VERSION 5.8 ;
BUSBITCHARS "[]" ;
DIVIDERCHAR "/" ;
UNITS
    DATABASE MICRONS 1000 ;
END UNITS

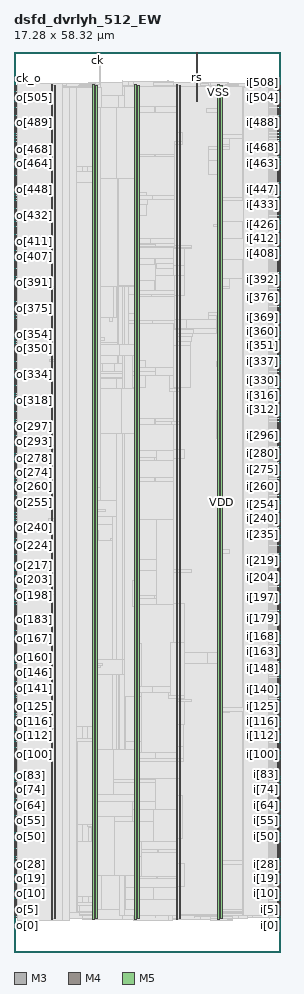
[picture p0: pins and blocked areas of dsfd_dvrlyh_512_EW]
MACRO dsfd_dvrlyh_512_EW
  FOREIGN dsfd_dvrlyh_512_EW 0 0 ;
  CLASS BLOCK ;
  SIZE 17.28 BY 58.32 ;
  PIN ck
    DIRECTION INPUT ;
    USE SIGNAL ;
    PORT
      LAYER M3 ;
        RECT  5.4 58.176 5.418 58.32 ;
    END
    PORT
      LAYER M3 ;
        RECT  5.4 57.595 5.418 58.188 ;
    END
  END ck
  PIN ck_o
    DIRECTION OUTPUT ;
    USE SIGNAL ;
    PORT
      LAYER M4 ;
        RECT  0 56.112 0.192 56.136 ;
    END
  END ck_o
  PIN i[0]
    DIRECTION INPUT ;
    USE SIGNAL ;
    PORT
      LAYER M4 ;
        RECT  17.088 2.208 17.28 2.232 ;
    END
  END i[0]
  PIN i[100]
    DIRECTION INPUT ;
    USE SIGNAL ;
    PORT
      LAYER M4 ;
        RECT  17.088 12.768 17.28 12.792 ;
    END
  END i[100]
  PIN i[101]
    DIRECTION INPUT ;
    USE SIGNAL ;
    PORT
      LAYER M4 ;
        RECT  17.088 12.864 17.28 12.888 ;
    END
  END i[101]
  PIN i[102]
    DIRECTION INPUT ;
    USE SIGNAL ;
    PORT
      LAYER M4 ;
        RECT  17.088 12.96 17.28 12.984 ;
    END
  END i[102]
  PIN i[103]
    DIRECTION INPUT ;
    USE SIGNAL ;
    PORT
      LAYER M4 ;
        RECT  17.088 13.104 17.28 13.128 ;
    END
  END i[103]
  PIN i[104]
    DIRECTION INPUT ;
    USE SIGNAL ;
    PORT
      LAYER M4 ;
        RECT  17.088 13.2 17.28 13.224 ;
    END
  END i[104]
  PIN i[105]
    DIRECTION INPUT ;
    USE SIGNAL ;
    PORT
      LAYER M4 ;
        RECT  17.088 13.296 17.28 13.32 ;
    END
  END i[105]
  PIN i[106]
    DIRECTION INPUT ;
    USE SIGNAL ;
    PORT
      LAYER M4 ;
        RECT  17.088 13.392 17.28 13.416 ;
    END
  END i[106]
  PIN i[107]
    DIRECTION INPUT ;
    USE SIGNAL ;
    PORT
      LAYER M4 ;
        RECT  17.088 13.488 17.28 13.512 ;
    END
  END i[107]
  PIN i[108]
    DIRECTION INPUT ;
    USE SIGNAL ;
    PORT
      LAYER M4 ;
        RECT  17.088 13.632 17.28 13.656 ;
    END
  END i[108]
  PIN i[109]
    DIRECTION INPUT ;
    USE SIGNAL ;
    PORT
      LAYER M4 ;
        RECT  17.088 13.728 17.28 13.752 ;
    END
  END i[109]
  PIN i[10]
    DIRECTION INPUT ;
    USE SIGNAL ;
    PORT
      LAYER M4 ;
        RECT  17.088 3.264 17.28 3.288 ;
    END
  END i[10]
  PIN i[110]
    DIRECTION INPUT ;
    USE SIGNAL ;
    PORT
      LAYER M4 ;
        RECT  17.088 13.824 17.28 13.848 ;
    END
  END i[110]
  PIN i[111]
    DIRECTION INPUT ;
    USE SIGNAL ;
    PORT
      LAYER M4 ;
        RECT  17.088 13.92 17.28 13.944 ;
    END
  END i[111]
  PIN i[112]
    DIRECTION INPUT ;
    USE SIGNAL ;
    PORT
      LAYER M4 ;
        RECT  17.088 14.016 17.28 14.04 ;
    END
  END i[112]
  PIN i[113]
    DIRECTION INPUT ;
    USE SIGNAL ;
    PORT
      LAYER M4 ;
        RECT  17.088 14.16 17.28 14.184 ;
    END
  END i[113]
  PIN i[114]
    DIRECTION INPUT ;
    USE SIGNAL ;
    PORT
      LAYER M4 ;
        RECT  17.088 14.256 17.28 14.28 ;
    END
  END i[114]
  PIN i[115]
    DIRECTION INPUT ;
    USE SIGNAL ;
    PORT
      LAYER M4 ;
        RECT  17.088 14.352 17.28 14.376 ;
    END
  END i[115]
  PIN i[116]
    DIRECTION INPUT ;
    USE SIGNAL ;
    PORT
      LAYER M4 ;
        RECT  17.088 14.448 17.28 14.472 ;
    END
  END i[116]
  PIN i[117]
    DIRECTION INPUT ;
    USE SIGNAL ;
    PORT
      LAYER M4 ;
        RECT  17.088 14.544 17.28 14.568 ;
    END
  END i[117]
  PIN i[118]
    DIRECTION INPUT ;
    USE SIGNAL ;
    PORT
      LAYER M4 ;
        RECT  17.088 14.688 17.28 14.712 ;
    END
  END i[118]
  PIN i[119]
    DIRECTION INPUT ;
    USE SIGNAL ;
    PORT
      LAYER M4 ;
        RECT  17.088 14.784 17.28 14.808 ;
    END
  END i[119]
  PIN i[11]
    DIRECTION INPUT ;
    USE SIGNAL ;
    PORT
      LAYER M4 ;
        RECT  17.088 3.408 17.28 3.432 ;
    END
  END i[11]
  PIN i[120]
    DIRECTION INPUT ;
    USE SIGNAL ;
    PORT
      LAYER M4 ;
        RECT  17.088 14.88 17.28 14.904 ;
    END
  END i[120]
  PIN i[121]
    DIRECTION INPUT ;
    USE SIGNAL ;
    PORT
      LAYER M4 ;
        RECT  17.088 14.976 17.28 15 ;
    END
  END i[121]
  PIN i[122]
    DIRECTION INPUT ;
    USE SIGNAL ;
    PORT
      LAYER M4 ;
        RECT  17.088 15.072 17.28 15.096 ;
    END
  END i[122]
  PIN i[123]
    DIRECTION INPUT ;
    USE SIGNAL ;
    PORT
      LAYER M4 ;
        RECT  17.088 15.216 17.28 15.24 ;
    END
  END i[123]
  PIN i[124]
    DIRECTION INPUT ;
    USE SIGNAL ;
    PORT
      LAYER M4 ;
        RECT  17.088 15.312 17.28 15.336 ;
    END
  END i[124]
  PIN i[125]
    DIRECTION INPUT ;
    USE SIGNAL ;
    PORT
      LAYER M4 ;
        RECT  17.088 15.408 17.28 15.432 ;
    END
  END i[125]
  PIN i[126]
    DIRECTION INPUT ;
    USE SIGNAL ;
    PORT
      LAYER M4 ;
        RECT  17.088 15.504 17.28 15.528 ;
    END
  END i[126]
  PIN i[127]
    DIRECTION INPUT ;
    USE SIGNAL ;
    PORT
      LAYER M4 ;
        RECT  17.088 15.6 17.28 15.624 ;
    END
  END i[127]
  PIN i[128]
    DIRECTION INPUT ;
    USE SIGNAL ;
    PORT
      LAYER M4 ;
        RECT  17.088 15.744 17.28 15.768 ;
    END
  END i[128]
  PIN i[129]
    DIRECTION INPUT ;
    USE SIGNAL ;
    PORT
      LAYER M4 ;
        RECT  17.088 15.84 17.28 15.864 ;
    END
  END i[129]
  PIN i[12]
    DIRECTION INPUT ;
    USE SIGNAL ;
    PORT
      LAYER M4 ;
        RECT  17.088 3.504 17.28 3.528 ;
    END
  END i[12]
  PIN i[130]
    DIRECTION INPUT ;
    USE SIGNAL ;
    PORT
      LAYER M4 ;
        RECT  17.088 15.936 17.28 15.96 ;
    END
  END i[130]
  PIN i[131]
    DIRECTION INPUT ;
    USE SIGNAL ;
    PORT
      LAYER M4 ;
        RECT  17.088 16.032 17.28 16.056 ;
    END
  END i[131]
  PIN i[132]
    DIRECTION INPUT ;
    USE SIGNAL ;
    PORT
      LAYER M4 ;
        RECT  17.088 16.128 17.28 16.152 ;
    END
  END i[132]
  PIN i[133]
    DIRECTION INPUT ;
    USE SIGNAL ;
    PORT
      LAYER M4 ;
        RECT  17.088 16.272 17.28 16.296 ;
    END
  END i[133]
  PIN i[134]
    DIRECTION INPUT ;
    USE SIGNAL ;
    PORT
      LAYER M4 ;
        RECT  17.088 16.368 17.28 16.392 ;
    END
  END i[134]
  PIN i[135]
    DIRECTION INPUT ;
    USE SIGNAL ;
    PORT
      LAYER M4 ;
        RECT  17.088 16.464 17.28 16.488 ;
    END
  END i[135]
  PIN i[136]
    DIRECTION INPUT ;
    USE SIGNAL ;
    PORT
      LAYER M4 ;
        RECT  17.088 16.56 17.28 16.584 ;
    END
  END i[136]
  PIN i[137]
    DIRECTION INPUT ;
    USE SIGNAL ;
    PORT
      LAYER M4 ;
        RECT  17.088 16.656 17.28 16.68 ;
    END
  END i[137]
  PIN i[138]
    DIRECTION INPUT ;
    USE SIGNAL ;
    PORT
      LAYER M4 ;
        RECT  17.088 16.8 17.28 16.824 ;
    END
  END i[138]
  PIN i[139]
    DIRECTION INPUT ;
    USE SIGNAL ;
    PORT
      LAYER M4 ;
        RECT  17.088 16.896 17.28 16.92 ;
    END
  END i[139]
  PIN i[13]
    DIRECTION INPUT ;
    USE SIGNAL ;
    PORT
      LAYER M4 ;
        RECT  17.088 3.6 17.28 3.624 ;
    END
  END i[13]
  PIN i[140]
    DIRECTION INPUT ;
    USE SIGNAL ;
    PORT
      LAYER M4 ;
        RECT  17.088 16.992 17.28 17.016 ;
    END
  END i[140]
  PIN i[141]
    DIRECTION INPUT ;
    USE SIGNAL ;
    PORT
      LAYER M4 ;
        RECT  17.088 17.088 17.28 17.112 ;
    END
  END i[141]
  PIN i[142]
    DIRECTION INPUT ;
    USE SIGNAL ;
    PORT
      LAYER M4 ;
        RECT  17.088 17.184 17.28 17.208 ;
    END
  END i[142]
  PIN i[143]
    DIRECTION INPUT ;
    USE SIGNAL ;
    PORT
      LAYER M4 ;
        RECT  17.088 17.328 17.28 17.352 ;
    END
  END i[143]
  PIN i[144]
    DIRECTION INPUT ;
    USE SIGNAL ;
    PORT
      LAYER M4 ;
        RECT  17.088 17.424 17.28 17.448 ;
    END
  END i[144]
  PIN i[145]
    DIRECTION INPUT ;
    USE SIGNAL ;
    PORT
      LAYER M4 ;
        RECT  17.088 17.52 17.28 17.544 ;
    END
  END i[145]
  PIN i[146]
    DIRECTION INPUT ;
    USE SIGNAL ;
    PORT
      LAYER M4 ;
        RECT  17.088 17.616 17.28 17.64 ;
    END
  END i[146]
  PIN i[147]
    DIRECTION INPUT ;
    USE SIGNAL ;
    PORT
      LAYER M4 ;
        RECT  17.088 17.712 17.28 17.736 ;
    END
  END i[147]
  PIN i[148]
    DIRECTION INPUT ;
    USE SIGNAL ;
    PORT
      LAYER M4 ;
        RECT  17.088 17.856 17.28 17.88 ;
    END
  END i[148]
  PIN i[149]
    DIRECTION INPUT ;
    USE SIGNAL ;
    PORT
      LAYER M4 ;
        RECT  17.088 17.952 17.28 17.976 ;
    END
  END i[149]
  PIN i[14]
    DIRECTION INPUT ;
    USE SIGNAL ;
    PORT
      LAYER M4 ;
        RECT  17.088 3.696 17.28 3.72 ;
    END
  END i[14]
  PIN i[150]
    DIRECTION INPUT ;
    USE SIGNAL ;
    PORT
      LAYER M4 ;
        RECT  17.088 18.048 17.28 18.072 ;
    END
  END i[150]
  PIN i[151]
    DIRECTION INPUT ;
    USE SIGNAL ;
    PORT
      LAYER M4 ;
        RECT  17.088 18.144 17.28 18.168 ;
    END
  END i[151]
  PIN i[152]
    DIRECTION INPUT ;
    USE SIGNAL ;
    PORT
      LAYER M4 ;
        RECT  17.088 18.24 17.28 18.264 ;
    END
  END i[152]
  PIN i[153]
    DIRECTION INPUT ;
    USE SIGNAL ;
    PORT
      LAYER M4 ;
        RECT  17.088 18.384 17.28 18.408 ;
    END
  END i[153]
  PIN i[154]
    DIRECTION INPUT ;
    USE SIGNAL ;
    PORT
      LAYER M4 ;
        RECT  17.088 18.48 17.28 18.504 ;
    END
  END i[154]
  PIN i[155]
    DIRECTION INPUT ;
    USE SIGNAL ;
    PORT
      LAYER M4 ;
        RECT  17.088 18.576 17.28 18.6 ;
    END
  END i[155]
  PIN i[156]
    DIRECTION INPUT ;
    USE SIGNAL ;
    PORT
      LAYER M4 ;
        RECT  17.088 18.672 17.28 18.696 ;
    END
  END i[156]
  PIN i[157]
    DIRECTION INPUT ;
    USE SIGNAL ;
    PORT
      LAYER M4 ;
        RECT  17.088 18.768 17.28 18.792 ;
    END
  END i[157]
  PIN i[158]
    DIRECTION INPUT ;
    USE SIGNAL ;
    PORT
      LAYER M4 ;
        RECT  17.088 18.912 17.28 18.936 ;
    END
  END i[158]
  PIN i[159]
    DIRECTION INPUT ;
    USE SIGNAL ;
    PORT
      LAYER M4 ;
        RECT  17.088 19.008 17.28 19.032 ;
    END
  END i[159]
  PIN i[15]
    DIRECTION INPUT ;
    USE SIGNAL ;
    PORT
      LAYER M4 ;
        RECT  17.088 3.792 17.28 3.816 ;
    END
  END i[15]
  PIN i[160]
    DIRECTION INPUT ;
    USE SIGNAL ;
    PORT
      LAYER M4 ;
        RECT  17.088 19.104 17.28 19.128 ;
    END
  END i[160]
  PIN i[161]
    DIRECTION INPUT ;
    USE SIGNAL ;
    PORT
      LAYER M4 ;
        RECT  17.088 19.2 17.28 19.224 ;
    END
  END i[161]
  PIN i[162]
    DIRECTION INPUT ;
    USE SIGNAL ;
    PORT
      LAYER M4 ;
        RECT  17.088 19.296 17.28 19.32 ;
    END
  END i[162]
  PIN i[163]
    DIRECTION INPUT ;
    USE SIGNAL ;
    PORT
      LAYER M4 ;
        RECT  17.088 19.44 17.28 19.464 ;
    END
  END i[163]
  PIN i[164]
    DIRECTION INPUT ;
    USE SIGNAL ;
    PORT
      LAYER M4 ;
        RECT  17.088 19.536 17.28 19.56 ;
    END
  END i[164]
  PIN i[165]
    DIRECTION INPUT ;
    USE SIGNAL ;
    PORT
      LAYER M4 ;
        RECT  17.088 19.632 17.28 19.656 ;
    END
  END i[165]
  PIN i[166]
    DIRECTION INPUT ;
    USE SIGNAL ;
    PORT
      LAYER M4 ;
        RECT  17.088 19.728 17.28 19.752 ;
    END
  END i[166]
  PIN i[167]
    DIRECTION INPUT ;
    USE SIGNAL ;
    PORT
      LAYER M4 ;
        RECT  17.088 19.824 17.28 19.848 ;
    END
  END i[167]
  PIN i[168]
    DIRECTION INPUT ;
    USE SIGNAL ;
    PORT
      LAYER M4 ;
        RECT  17.088 19.92 17.28 19.944 ;
    END
  END i[168]
  PIN i[169]
    DIRECTION INPUT ;
    USE SIGNAL ;
    PORT
      LAYER M4 ;
        RECT  17.088 20.064 17.28 20.088 ;
    END
  END i[169]
  PIN i[16]
    DIRECTION INPUT ;
    USE SIGNAL ;
    PORT
      LAYER M4 ;
        RECT  17.088 3.936 17.28 3.96 ;
    END
  END i[16]
  PIN i[170]
    DIRECTION INPUT ;
    USE SIGNAL ;
    PORT
      LAYER M4 ;
        RECT  17.088 20.16 17.28 20.184 ;
    END
  END i[170]
  PIN i[171]
    DIRECTION INPUT ;
    USE SIGNAL ;
    PORT
      LAYER M4 ;
        RECT  17.088 20.256 17.28 20.28 ;
    END
  END i[171]
  PIN i[172]
    DIRECTION INPUT ;
    USE SIGNAL ;
    PORT
      LAYER M4 ;
        RECT  17.088 20.352 17.28 20.376 ;
    END
  END i[172]
  PIN i[173]
    DIRECTION INPUT ;
    USE SIGNAL ;
    PORT
      LAYER M4 ;
        RECT  17.088 20.448 17.28 20.472 ;
    END
  END i[173]
  PIN i[174]
    DIRECTION INPUT ;
    USE SIGNAL ;
    PORT
      LAYER M4 ;
        RECT  17.088 20.592 17.28 20.616 ;
    END
  END i[174]
  PIN i[175]
    DIRECTION INPUT ;
    USE SIGNAL ;
    PORT
      LAYER M4 ;
        RECT  17.088 20.688 17.28 20.712 ;
    END
  END i[175]
  PIN i[176]
    DIRECTION INPUT ;
    USE SIGNAL ;
    PORT
      LAYER M4 ;
        RECT  17.088 20.784 17.28 20.808 ;
    END
  END i[176]
  PIN i[177]
    DIRECTION INPUT ;
    USE SIGNAL ;
    PORT
      LAYER M4 ;
        RECT  17.088 20.88 17.28 20.904 ;
    END
  END i[177]
  PIN i[178]
    DIRECTION INPUT ;
    USE SIGNAL ;
    PORT
      LAYER M4 ;
        RECT  17.088 20.976 17.28 21 ;
    END
  END i[178]
  PIN i[179]
    DIRECTION INPUT ;
    USE SIGNAL ;
    PORT
      LAYER M4 ;
        RECT  17.088 21.12 17.28 21.144 ;
    END
  END i[179]
  PIN i[17]
    DIRECTION INPUT ;
    USE SIGNAL ;
    PORT
      LAYER M4 ;
        RECT  17.088 4.032 17.28 4.056 ;
    END
  END i[17]
  PIN i[180]
    DIRECTION INPUT ;
    USE SIGNAL ;
    PORT
      LAYER M4 ;
        RECT  17.088 21.216 17.28 21.24 ;
    END
  END i[180]
  PIN i[181]
    DIRECTION INPUT ;
    USE SIGNAL ;
    PORT
      LAYER M4 ;
        RECT  17.088 21.312 17.28 21.336 ;
    END
  END i[181]
  PIN i[182]
    DIRECTION INPUT ;
    USE SIGNAL ;
    PORT
      LAYER M4 ;
        RECT  17.088 21.408 17.28 21.432 ;
    END
  END i[182]
  PIN i[183]
    DIRECTION INPUT ;
    USE SIGNAL ;
    PORT
      LAYER M4 ;
        RECT  17.088 21.504 17.28 21.528 ;
    END
  END i[183]
  PIN i[184]
    DIRECTION INPUT ;
    USE SIGNAL ;
    PORT
      LAYER M4 ;
        RECT  17.088 21.648 17.28 21.672 ;
    END
  END i[184]
  PIN i[185]
    DIRECTION INPUT ;
    USE SIGNAL ;
    PORT
      LAYER M4 ;
        RECT  17.088 21.744 17.28 21.768 ;
    END
  END i[185]
  PIN i[186]
    DIRECTION INPUT ;
    USE SIGNAL ;
    PORT
      LAYER M4 ;
        RECT  17.088 21.84 17.28 21.864 ;
    END
  END i[186]
  PIN i[187]
    DIRECTION INPUT ;
    USE SIGNAL ;
    PORT
      LAYER M4 ;
        RECT  17.088 21.936 17.28 21.96 ;
    END
  END i[187]
  PIN i[188]
    DIRECTION INPUT ;
    USE SIGNAL ;
    PORT
      LAYER M4 ;
        RECT  17.088 22.032 17.28 22.056 ;
    END
  END i[188]
  PIN i[189]
    DIRECTION INPUT ;
    USE SIGNAL ;
    PORT
      LAYER M4 ;
        RECT  17.088 22.176 17.28 22.2 ;
    END
  END i[189]
  PIN i[18]
    DIRECTION INPUT ;
    USE SIGNAL ;
    PORT
      LAYER M4 ;
        RECT  17.088 4.128 17.28 4.152 ;
    END
  END i[18]
  PIN i[190]
    DIRECTION INPUT ;
    USE SIGNAL ;
    PORT
      LAYER M4 ;
        RECT  17.088 22.272 17.28 22.296 ;
    END
  END i[190]
  PIN i[191]
    DIRECTION INPUT ;
    USE SIGNAL ;
    PORT
      LAYER M4 ;
        RECT  17.088 22.368 17.28 22.392 ;
    END
  END i[191]
  PIN i[192]
    DIRECTION INPUT ;
    USE SIGNAL ;
    PORT
      LAYER M4 ;
        RECT  17.088 22.464 17.28 22.488 ;
    END
  END i[192]
  PIN i[193]
    DIRECTION INPUT ;
    USE SIGNAL ;
    PORT
      LAYER M4 ;
        RECT  17.088 22.56 17.28 22.584 ;
    END
  END i[193]
  PIN i[194]
    DIRECTION INPUT ;
    USE SIGNAL ;
    PORT
      LAYER M4 ;
        RECT  17.088 22.704 17.28 22.728 ;
    END
  END i[194]
  PIN i[195]
    DIRECTION INPUT ;
    USE SIGNAL ;
    PORT
      LAYER M4 ;
        RECT  17.088 22.8 17.28 22.824 ;
    END
  END i[195]
  PIN i[196]
    DIRECTION INPUT ;
    USE SIGNAL ;
    PORT
      LAYER M4 ;
        RECT  17.088 22.896 17.28 22.92 ;
    END
  END i[196]
  PIN i[197]
    DIRECTION INPUT ;
    USE SIGNAL ;
    PORT
      LAYER M4 ;
        RECT  17.088 22.992 17.28 23.016 ;
    END
  END i[197]
  PIN i[198]
    DIRECTION INPUT ;
    USE SIGNAL ;
    PORT
      LAYER M4 ;
        RECT  17.088 23.088 17.28 23.112 ;
    END
  END i[198]
  PIN i[199]
    DIRECTION INPUT ;
    USE SIGNAL ;
    PORT
      LAYER M4 ;
        RECT  17.088 23.232 17.28 23.256 ;
    END
  END i[199]
  PIN i[19]
    DIRECTION INPUT ;
    USE SIGNAL ;
    PORT
      LAYER M4 ;
        RECT  17.088 4.224 17.28 4.248 ;
    END
  END i[19]
  PIN i[1]
    DIRECTION INPUT ;
    USE SIGNAL ;
    PORT
      LAYER M4 ;
        RECT  17.088 2.352 17.28 2.376 ;
    END
  END i[1]
  PIN i[200]
    DIRECTION INPUT ;
    USE SIGNAL ;
    PORT
      LAYER M4 ;
        RECT  17.088 23.328 17.28 23.352 ;
    END
  END i[200]
  PIN i[201]
    DIRECTION INPUT ;
    USE SIGNAL ;
    PORT
      LAYER M4 ;
        RECT  17.088 23.424 17.28 23.448 ;
    END
  END i[201]
  PIN i[202]
    DIRECTION INPUT ;
    USE SIGNAL ;
    PORT
      LAYER M4 ;
        RECT  17.088 23.52 17.28 23.544 ;
    END
  END i[202]
  PIN i[203]
    DIRECTION INPUT ;
    USE SIGNAL ;
    PORT
      LAYER M4 ;
        RECT  17.088 23.616 17.28 23.64 ;
    END
  END i[203]
  PIN i[204]
    DIRECTION INPUT ;
    USE SIGNAL ;
    PORT
      LAYER M4 ;
        RECT  17.088 23.76 17.28 23.784 ;
    END
  END i[204]
  PIN i[205]
    DIRECTION INPUT ;
    USE SIGNAL ;
    PORT
      LAYER M4 ;
        RECT  17.088 23.856 17.28 23.88 ;
    END
  END i[205]
  PIN i[206]
    DIRECTION INPUT ;
    USE SIGNAL ;
    PORT
      LAYER M4 ;
        RECT  17.088 23.952 17.28 23.976 ;
    END
  END i[206]
  PIN i[207]
    DIRECTION INPUT ;
    USE SIGNAL ;
    PORT
      LAYER M4 ;
        RECT  17.088 24.048 17.28 24.072 ;
    END
  END i[207]
  PIN i[208]
    DIRECTION INPUT ;
    USE SIGNAL ;
    PORT
      LAYER M4 ;
        RECT  17.088 24.144 17.28 24.168 ;
    END
  END i[208]
  PIN i[209]
    DIRECTION INPUT ;
    USE SIGNAL ;
    PORT
      LAYER M4 ;
        RECT  17.088 24.288 17.28 24.312 ;
    END
  END i[209]
  PIN i[20]
    DIRECTION INPUT ;
    USE SIGNAL ;
    PORT
      LAYER M4 ;
        RECT  17.088 4.32 17.28 4.344 ;
    END
  END i[20]
  PIN i[210]
    DIRECTION INPUT ;
    USE SIGNAL ;
    PORT
      LAYER M4 ;
        RECT  17.088 24.384 17.28 24.408 ;
    END
  END i[210]
  PIN i[211]
    DIRECTION INPUT ;
    USE SIGNAL ;
    PORT
      LAYER M4 ;
        RECT  17.088 24.48 17.28 24.504 ;
    END
  END i[211]
  PIN i[212]
    DIRECTION INPUT ;
    USE SIGNAL ;
    PORT
      LAYER M4 ;
        RECT  17.088 24.576 17.28 24.6 ;
    END
  END i[212]
  PIN i[213]
    DIRECTION INPUT ;
    USE SIGNAL ;
    PORT
      LAYER M4 ;
        RECT  17.088 24.672 17.28 24.696 ;
    END
  END i[213]
  PIN i[214]
    DIRECTION INPUT ;
    USE SIGNAL ;
    PORT
      LAYER M4 ;
        RECT  17.088 24.816 17.28 24.84 ;
    END
  END i[214]
  PIN i[215]
    DIRECTION INPUT ;
    USE SIGNAL ;
    PORT
      LAYER M4 ;
        RECT  17.088 24.912 17.28 24.936 ;
    END
  END i[215]
  PIN i[216]
    DIRECTION INPUT ;
    USE SIGNAL ;
    PORT
      LAYER M4 ;
        RECT  17.088 25.008 17.28 25.032 ;
    END
  END i[216]
  PIN i[217]
    DIRECTION INPUT ;
    USE SIGNAL ;
    PORT
      LAYER M4 ;
        RECT  17.088 25.104 17.28 25.128 ;
    END
  END i[217]
  PIN i[218]
    DIRECTION INPUT ;
    USE SIGNAL ;
    PORT
      LAYER M4 ;
        RECT  17.088 25.2 17.28 25.224 ;
    END
  END i[218]
  PIN i[219]
    DIRECTION INPUT ;
    USE SIGNAL ;
    PORT
      LAYER M4 ;
        RECT  17.088 25.344 17.28 25.368 ;
    END
  END i[219]
  PIN i[21]
    DIRECTION INPUT ;
    USE SIGNAL ;
    PORT
      LAYER M4 ;
        RECT  17.088 4.416 17.28 4.44 ;
    END
  END i[21]
  PIN i[220]
    DIRECTION INPUT ;
    USE SIGNAL ;
    PORT
      LAYER M4 ;
        RECT  17.088 25.44 17.28 25.464 ;
    END
  END i[220]
  PIN i[221]
    DIRECTION INPUT ;
    USE SIGNAL ;
    PORT
      LAYER M4 ;
        RECT  17.088 25.536 17.28 25.56 ;
    END
  END i[221]
  PIN i[222]
    DIRECTION INPUT ;
    USE SIGNAL ;
    PORT
      LAYER M4 ;
        RECT  17.088 25.632 17.28 25.656 ;
    END
  END i[222]
  PIN i[223]
    DIRECTION INPUT ;
    USE SIGNAL ;
    PORT
      LAYER M4 ;
        RECT  17.088 25.728 17.28 25.752 ;
    END
  END i[223]
  PIN i[224]
    DIRECTION INPUT ;
    USE SIGNAL ;
    PORT
      LAYER M4 ;
        RECT  17.088 25.872 17.28 25.896 ;
    END
  END i[224]
  PIN i[225]
    DIRECTION INPUT ;
    USE SIGNAL ;
    PORT
      LAYER M4 ;
        RECT  17.088 25.968 17.28 25.992 ;
    END
  END i[225]
  PIN i[226]
    DIRECTION INPUT ;
    USE SIGNAL ;
    PORT
      LAYER M4 ;
        RECT  17.088 26.064 17.28 26.088 ;
    END
  END i[226]
  PIN i[227]
    DIRECTION INPUT ;
    USE SIGNAL ;
    PORT
      LAYER M4 ;
        RECT  17.088 26.16 17.28 26.184 ;
    END
  END i[227]
  PIN i[228]
    DIRECTION INPUT ;
    USE SIGNAL ;
    PORT
      LAYER M4 ;
        RECT  17.088 26.256 17.28 26.28 ;
    END
  END i[228]
  PIN i[229]
    DIRECTION INPUT ;
    USE SIGNAL ;
    PORT
      LAYER M4 ;
        RECT  17.088 26.4 17.28 26.424 ;
    END
  END i[229]
  PIN i[22]
    DIRECTION INPUT ;
    USE SIGNAL ;
    PORT
      LAYER M4 ;
        RECT  17.088 4.56 17.28 4.584 ;
    END
  END i[22]
  PIN i[230]
    DIRECTION INPUT ;
    USE SIGNAL ;
    PORT
      LAYER M4 ;
        RECT  17.088 26.496 17.28 26.52 ;
    END
  END i[230]
  PIN i[231]
    DIRECTION INPUT ;
    USE SIGNAL ;
    PORT
      LAYER M4 ;
        RECT  17.088 26.592 17.28 26.616 ;
    END
  END i[231]
  PIN i[232]
    DIRECTION INPUT ;
    USE SIGNAL ;
    PORT
      LAYER M4 ;
        RECT  17.088 26.688 17.28 26.712 ;
    END
  END i[232]
  PIN i[233]
    DIRECTION INPUT ;
    USE SIGNAL ;
    PORT
      LAYER M4 ;
        RECT  17.088 26.784 17.28 26.808 ;
    END
  END i[233]
  PIN i[234]
    DIRECTION INPUT ;
    USE SIGNAL ;
    PORT
      LAYER M4 ;
        RECT  17.088 26.928 17.28 26.952 ;
    END
  END i[234]
  PIN i[235]
    DIRECTION INPUT ;
    USE SIGNAL ;
    PORT
      LAYER M4 ;
        RECT  17.088 27.024 17.28 27.048 ;
    END
  END i[235]
  PIN i[236]
    DIRECTION INPUT ;
    USE SIGNAL ;
    PORT
      LAYER M4 ;
        RECT  17.088 27.12 17.28 27.144 ;
    END
  END i[236]
  PIN i[237]
    DIRECTION INPUT ;
    USE SIGNAL ;
    PORT
      LAYER M4 ;
        RECT  17.088 27.216 17.28 27.24 ;
    END
  END i[237]
  PIN i[238]
    DIRECTION INPUT ;
    USE SIGNAL ;
    PORT
      LAYER M4 ;
        RECT  17.088 27.312 17.28 27.336 ;
    END
  END i[238]
  PIN i[239]
    DIRECTION INPUT ;
    USE SIGNAL ;
    PORT
      LAYER M4 ;
        RECT  17.088 27.408 17.28 27.432 ;
    END
  END i[239]
  PIN i[23]
    DIRECTION INPUT ;
    USE SIGNAL ;
    PORT
      LAYER M4 ;
        RECT  17.088 4.656 17.28 4.68 ;
    END
  END i[23]
  PIN i[240]
    DIRECTION INPUT ;
    USE SIGNAL ;
    PORT
      LAYER M4 ;
        RECT  17.088 27.552 17.28 27.576 ;
    END
  END i[240]
  PIN i[241]
    DIRECTION INPUT ;
    USE SIGNAL ;
    PORT
      LAYER M4 ;
        RECT  17.088 27.648 17.28 27.672 ;
    END
  END i[241]
  PIN i[242]
    DIRECTION INPUT ;
    USE SIGNAL ;
    PORT
      LAYER M4 ;
        RECT  17.088 27.744 17.28 27.768 ;
    END
  END i[242]
  PIN i[243]
    DIRECTION INPUT ;
    USE SIGNAL ;
    PORT
      LAYER M4 ;
        RECT  17.088 27.84 17.28 27.864 ;
    END
  END i[243]
  PIN i[244]
    DIRECTION INPUT ;
    USE SIGNAL ;
    PORT
      LAYER M4 ;
        RECT  17.088 27.936 17.28 27.96 ;
    END
  END i[244]
  PIN i[245]
    DIRECTION INPUT ;
    USE SIGNAL ;
    PORT
      LAYER M4 ;
        RECT  17.088 28.08 17.28 28.104 ;
    END
  END i[245]
  PIN i[246]
    DIRECTION INPUT ;
    USE SIGNAL ;
    PORT
      LAYER M4 ;
        RECT  17.088 28.176 17.28 28.2 ;
    END
  END i[246]
  PIN i[247]
    DIRECTION INPUT ;
    USE SIGNAL ;
    PORT
      LAYER M4 ;
        RECT  17.088 28.272 17.28 28.296 ;
    END
  END i[247]
  PIN i[248]
    DIRECTION INPUT ;
    USE SIGNAL ;
    PORT
      LAYER M4 ;
        RECT  17.088 28.368 17.28 28.392 ;
    END
  END i[248]
  PIN i[249]
    DIRECTION INPUT ;
    USE SIGNAL ;
    PORT
      LAYER M4 ;
        RECT  17.088 28.464 17.28 28.488 ;
    END
  END i[249]
  PIN i[24]
    DIRECTION INPUT ;
    USE SIGNAL ;
    PORT
      LAYER M4 ;
        RECT  17.088 4.752 17.28 4.776 ;
    END
  END i[24]
  PIN i[250]
    DIRECTION INPUT ;
    USE SIGNAL ;
    PORT
      LAYER M4 ;
        RECT  17.088 28.608 17.28 28.632 ;
    END
  END i[250]
  PIN i[251]
    DIRECTION INPUT ;
    USE SIGNAL ;
    PORT
      LAYER M4 ;
        RECT  17.088 28.704 17.28 28.728 ;
    END
  END i[251]
  PIN i[252]
    DIRECTION INPUT ;
    USE SIGNAL ;
    PORT
      LAYER M4 ;
        RECT  17.088 28.8 17.28 28.824 ;
    END
  END i[252]
  PIN i[253]
    DIRECTION INPUT ;
    USE SIGNAL ;
    PORT
      LAYER M4 ;
        RECT  17.088 28.896 17.28 28.92 ;
    END
  END i[253]
  PIN i[254]
    DIRECTION INPUT ;
    USE SIGNAL ;
    PORT
      LAYER M4 ;
        RECT  17.088 28.992 17.28 29.016 ;
    END
  END i[254]
  PIN i[255]
    DIRECTION INPUT ;
    USE SIGNAL ;
    PORT
      LAYER M4 ;
        RECT  17.088 29.136 17.28 29.16 ;
    END
  END i[255]
  PIN i[256]
    DIRECTION INPUT ;
    USE SIGNAL ;
    PORT
      LAYER M4 ;
        RECT  17.088 29.232 17.28 29.256 ;
    END
  END i[256]
  PIN i[257]
    DIRECTION INPUT ;
    USE SIGNAL ;
    PORT
      LAYER M4 ;
        RECT  17.088 29.328 17.28 29.352 ;
    END
  END i[257]
  PIN i[258]
    DIRECTION INPUT ;
    USE SIGNAL ;
    PORT
      LAYER M4 ;
        RECT  17.088 29.424 17.28 29.448 ;
    END
  END i[258]
  PIN i[259]
    DIRECTION INPUT ;
    USE SIGNAL ;
    PORT
      LAYER M4 ;
        RECT  17.088 29.52 17.28 29.544 ;
    END
  END i[259]
  PIN i[25]
    DIRECTION INPUT ;
    USE SIGNAL ;
    PORT
      LAYER M4 ;
        RECT  17.088 4.848 17.28 4.872 ;
    END
  END i[25]
  PIN i[260]
    DIRECTION INPUT ;
    USE SIGNAL ;
    PORT
      LAYER M4 ;
        RECT  17.088 29.664 17.28 29.688 ;
    END
  END i[260]
  PIN i[261]
    DIRECTION INPUT ;
    USE SIGNAL ;
    PORT
      LAYER M4 ;
        RECT  17.088 29.76 17.28 29.784 ;
    END
  END i[261]
  PIN i[262]
    DIRECTION INPUT ;
    USE SIGNAL ;
    PORT
      LAYER M4 ;
        RECT  17.088 29.856 17.28 29.88 ;
    END
  END i[262]
  PIN i[263]
    DIRECTION INPUT ;
    USE SIGNAL ;
    PORT
      LAYER M4 ;
        RECT  17.088 29.952 17.28 29.976 ;
    END
  END i[263]
  PIN i[264]
    DIRECTION INPUT ;
    USE SIGNAL ;
    PORT
      LAYER M4 ;
        RECT  17.088 30.048 17.28 30.072 ;
    END
  END i[264]
  PIN i[265]
    DIRECTION INPUT ;
    USE SIGNAL ;
    PORT
      LAYER M4 ;
        RECT  17.088 30.192 17.28 30.216 ;
    END
  END i[265]
  PIN i[266]
    DIRECTION INPUT ;
    USE SIGNAL ;
    PORT
      LAYER M4 ;
        RECT  17.088 30.288 17.28 30.312 ;
    END
  END i[266]
  PIN i[267]
    DIRECTION INPUT ;
    USE SIGNAL ;
    PORT
      LAYER M4 ;
        RECT  17.088 30.384 17.28 30.408 ;
    END
  END i[267]
  PIN i[268]
    DIRECTION INPUT ;
    USE SIGNAL ;
    PORT
      LAYER M4 ;
        RECT  17.088 30.48 17.28 30.504 ;
    END
  END i[268]
  PIN i[269]
    DIRECTION INPUT ;
    USE SIGNAL ;
    PORT
      LAYER M4 ;
        RECT  17.088 30.576 17.28 30.6 ;
    END
  END i[269]
  PIN i[26]
    DIRECTION INPUT ;
    USE SIGNAL ;
    PORT
      LAYER M4 ;
        RECT  17.088 4.944 17.28 4.968 ;
    END
  END i[26]
  PIN i[270]
    DIRECTION INPUT ;
    USE SIGNAL ;
    PORT
      LAYER M4 ;
        RECT  17.088 30.72 17.28 30.744 ;
    END
  END i[270]
  PIN i[271]
    DIRECTION INPUT ;
    USE SIGNAL ;
    PORT
      LAYER M4 ;
        RECT  17.088 30.816 17.28 30.84 ;
    END
  END i[271]
  PIN i[272]
    DIRECTION INPUT ;
    USE SIGNAL ;
    PORT
      LAYER M4 ;
        RECT  17.088 30.912 17.28 30.936 ;
    END
  END i[272]
  PIN i[273]
    DIRECTION INPUT ;
    USE SIGNAL ;
    PORT
      LAYER M4 ;
        RECT  17.088 31.008 17.28 31.032 ;
    END
  END i[273]
  PIN i[274]
    DIRECTION INPUT ;
    USE SIGNAL ;
    PORT
      LAYER M4 ;
        RECT  17.088 31.104 17.28 31.128 ;
    END
  END i[274]
  PIN i[275]
    DIRECTION INPUT ;
    USE SIGNAL ;
    PORT
      LAYER M4 ;
        RECT  17.088 31.248 17.28 31.272 ;
    END
  END i[275]
  PIN i[276]
    DIRECTION INPUT ;
    USE SIGNAL ;
    PORT
      LAYER M4 ;
        RECT  17.088 31.344 17.28 31.368 ;
    END
  END i[276]
  PIN i[277]
    DIRECTION INPUT ;
    USE SIGNAL ;
    PORT
      LAYER M4 ;
        RECT  17.088 31.44 17.28 31.464 ;
    END
  END i[277]
  PIN i[278]
    DIRECTION INPUT ;
    USE SIGNAL ;
    PORT
      LAYER M4 ;
        RECT  17.088 31.536 17.28 31.56 ;
    END
  END i[278]
  PIN i[279]
    DIRECTION INPUT ;
    USE SIGNAL ;
    PORT
      LAYER M4 ;
        RECT  17.088 31.632 17.28 31.656 ;
    END
  END i[279]
  PIN i[27]
    DIRECTION INPUT ;
    USE SIGNAL ;
    PORT
      LAYER M4 ;
        RECT  17.088 5.088 17.28 5.112 ;
    END
  END i[27]
  PIN i[280]
    DIRECTION INPUT ;
    USE SIGNAL ;
    PORT
      LAYER M4 ;
        RECT  17.088 31.776 17.28 31.8 ;
    END
  END i[280]
  PIN i[281]
    DIRECTION INPUT ;
    USE SIGNAL ;
    PORT
      LAYER M4 ;
        RECT  17.088 31.872 17.28 31.896 ;
    END
  END i[281]
  PIN i[282]
    DIRECTION INPUT ;
    USE SIGNAL ;
    PORT
      LAYER M4 ;
        RECT  17.088 31.968 17.28 31.992 ;
    END
  END i[282]
  PIN i[283]
    DIRECTION INPUT ;
    USE SIGNAL ;
    PORT
      LAYER M4 ;
        RECT  17.088 32.064 17.28 32.088 ;
    END
  END i[283]
  PIN i[284]
    DIRECTION INPUT ;
    USE SIGNAL ;
    PORT
      LAYER M4 ;
        RECT  17.088 32.16 17.28 32.184 ;
    END
  END i[284]
  PIN i[285]
    DIRECTION INPUT ;
    USE SIGNAL ;
    PORT
      LAYER M4 ;
        RECT  17.088 32.304 17.28 32.328 ;
    END
  END i[285]
  PIN i[286]
    DIRECTION INPUT ;
    USE SIGNAL ;
    PORT
      LAYER M4 ;
        RECT  17.088 32.4 17.28 32.424 ;
    END
  END i[286]
  PIN i[287]
    DIRECTION INPUT ;
    USE SIGNAL ;
    PORT
      LAYER M4 ;
        RECT  17.088 32.496 17.28 32.52 ;
    END
  END i[287]
  PIN i[288]
    DIRECTION INPUT ;
    USE SIGNAL ;
    PORT
      LAYER M4 ;
        RECT  17.088 32.592 17.28 32.616 ;
    END
  END i[288]
  PIN i[289]
    DIRECTION INPUT ;
    USE SIGNAL ;
    PORT
      LAYER M4 ;
        RECT  17.088 32.688 17.28 32.712 ;
    END
  END i[289]
  PIN i[28]
    DIRECTION INPUT ;
    USE SIGNAL ;
    PORT
      LAYER M4 ;
        RECT  17.088 5.184 17.28 5.208 ;
    END
  END i[28]
  PIN i[290]
    DIRECTION INPUT ;
    USE SIGNAL ;
    PORT
      LAYER M4 ;
        RECT  17.088 32.832 17.28 32.856 ;
    END
  END i[290]
  PIN i[291]
    DIRECTION INPUT ;
    USE SIGNAL ;
    PORT
      LAYER M4 ;
        RECT  17.088 32.928 17.28 32.952 ;
    END
  END i[291]
  PIN i[292]
    DIRECTION INPUT ;
    USE SIGNAL ;
    PORT
      LAYER M4 ;
        RECT  17.088 33.024 17.28 33.048 ;
    END
  END i[292]
  PIN i[293]
    DIRECTION INPUT ;
    USE SIGNAL ;
    PORT
      LAYER M4 ;
        RECT  17.088 33.12 17.28 33.144 ;
    END
  END i[293]
  PIN i[294]
    DIRECTION INPUT ;
    USE SIGNAL ;
    PORT
      LAYER M4 ;
        RECT  17.088 33.216 17.28 33.24 ;
    END
  END i[294]
  PIN i[295]
    DIRECTION INPUT ;
    USE SIGNAL ;
    PORT
      LAYER M4 ;
        RECT  17.088 33.36 17.28 33.384 ;
    END
  END i[295]
  PIN i[296]
    DIRECTION INPUT ;
    USE SIGNAL ;
    PORT
      LAYER M4 ;
        RECT  17.088 33.456 17.28 33.48 ;
    END
  END i[296]
  PIN i[297]
    DIRECTION INPUT ;
    USE SIGNAL ;
    PORT
      LAYER M4 ;
        RECT  17.088 33.552 17.28 33.576 ;
    END
  END i[297]
  PIN i[298]
    DIRECTION INPUT ;
    USE SIGNAL ;
    PORT
      LAYER M4 ;
        RECT  17.088 33.648 17.28 33.672 ;
    END
  END i[298]
  PIN i[299]
    DIRECTION INPUT ;
    USE SIGNAL ;
    PORT
      LAYER M4 ;
        RECT  17.088 33.744 17.28 33.768 ;
    END
  END i[299]
  PIN i[29]
    DIRECTION INPUT ;
    USE SIGNAL ;
    PORT
      LAYER M4 ;
        RECT  17.088 5.28 17.28 5.304 ;
    END
  END i[29]
  PIN i[2]
    DIRECTION INPUT ;
    USE SIGNAL ;
    PORT
      LAYER M4 ;
        RECT  17.088 2.448 17.28 2.472 ;
    END
  END i[2]
  PIN i[300]
    DIRECTION INPUT ;
    USE SIGNAL ;
    PORT
      LAYER M4 ;
        RECT  17.088 33.888 17.28 33.912 ;
    END
  END i[300]
  PIN i[301]
    DIRECTION INPUT ;
    USE SIGNAL ;
    PORT
      LAYER M4 ;
        RECT  17.088 33.984 17.28 34.008 ;
    END
  END i[301]
  PIN i[302]
    DIRECTION INPUT ;
    USE SIGNAL ;
    PORT
      LAYER M4 ;
        RECT  17.088 34.08 17.28 34.104 ;
    END
  END i[302]
  PIN i[303]
    DIRECTION INPUT ;
    USE SIGNAL ;
    PORT
      LAYER M4 ;
        RECT  17.088 34.176 17.28 34.2 ;
    END
  END i[303]
  PIN i[304]
    DIRECTION INPUT ;
    USE SIGNAL ;
    PORT
      LAYER M4 ;
        RECT  17.088 34.272 17.28 34.296 ;
    END
  END i[304]
  PIN i[305]
    DIRECTION INPUT ;
    USE SIGNAL ;
    PORT
      LAYER M4 ;
        RECT  17.088 34.416 17.28 34.44 ;
    END
  END i[305]
  PIN i[306]
    DIRECTION INPUT ;
    USE SIGNAL ;
    PORT
      LAYER M4 ;
        RECT  17.088 34.512 17.28 34.536 ;
    END
  END i[306]
  PIN i[307]
    DIRECTION INPUT ;
    USE SIGNAL ;
    PORT
      LAYER M4 ;
        RECT  17.088 34.608 17.28 34.632 ;
    END
  END i[307]
  PIN i[308]
    DIRECTION INPUT ;
    USE SIGNAL ;
    PORT
      LAYER M4 ;
        RECT  17.088 34.704 17.28 34.728 ;
    END
  END i[308]
  PIN i[309]
    DIRECTION INPUT ;
    USE SIGNAL ;
    PORT
      LAYER M4 ;
        RECT  17.088 34.8 17.28 34.824 ;
    END
  END i[309]
  PIN i[30]
    DIRECTION INPUT ;
    USE SIGNAL ;
    PORT
      LAYER M4 ;
        RECT  17.088 5.376 17.28 5.4 ;
    END
  END i[30]
  PIN i[310]
    DIRECTION INPUT ;
    USE SIGNAL ;
    PORT
      LAYER M4 ;
        RECT  17.088 34.944 17.28 34.968 ;
    END
  END i[310]
  PIN i[311]
    DIRECTION INPUT ;
    USE SIGNAL ;
    PORT
      LAYER M4 ;
        RECT  17.088 35.04 17.28 35.064 ;
    END
  END i[311]
  PIN i[312]
    DIRECTION INPUT ;
    USE SIGNAL ;
    PORT
      LAYER M4 ;
        RECT  17.088 35.136 17.28 35.16 ;
    END
  END i[312]
  PIN i[313]
    DIRECTION INPUT ;
    USE SIGNAL ;
    PORT
      LAYER M4 ;
        RECT  17.088 35.232 17.28 35.256 ;
    END
  END i[313]
  PIN i[314]
    DIRECTION INPUT ;
    USE SIGNAL ;
    PORT
      LAYER M4 ;
        RECT  17.088 35.328 17.28 35.352 ;
    END
  END i[314]
  PIN i[315]
    DIRECTION INPUT ;
    USE SIGNAL ;
    PORT
      LAYER M4 ;
        RECT  17.088 35.424 17.28 35.448 ;
    END
  END i[315]
  PIN i[316]
    DIRECTION INPUT ;
    USE SIGNAL ;
    PORT
      LAYER M4 ;
        RECT  17.088 35.568 17.28 35.592 ;
    END
  END i[316]
  PIN i[317]
    DIRECTION INPUT ;
    USE SIGNAL ;
    PORT
      LAYER M4 ;
        RECT  17.088 35.664 17.28 35.688 ;
    END
  END i[317]
  PIN i[318]
    DIRECTION INPUT ;
    USE SIGNAL ;
    PORT
      LAYER M4 ;
        RECT  17.088 35.76 17.28 35.784 ;
    END
  END i[318]
  PIN i[319]
    DIRECTION INPUT ;
    USE SIGNAL ;
    PORT
      LAYER M4 ;
        RECT  17.088 35.856 17.28 35.88 ;
    END
  END i[319]
  PIN i[31]
    DIRECTION INPUT ;
    USE SIGNAL ;
    PORT
      LAYER M4 ;
        RECT  17.088 5.472 17.28 5.496 ;
    END
  END i[31]
  PIN i[320]
    DIRECTION INPUT ;
    USE SIGNAL ;
    PORT
      LAYER M4 ;
        RECT  17.088 35.952 17.28 35.976 ;
    END
  END i[320]
  PIN i[321]
    DIRECTION INPUT ;
    USE SIGNAL ;
    PORT
      LAYER M4 ;
        RECT  17.088 36.096 17.28 36.12 ;
    END
  END i[321]
  PIN i[322]
    DIRECTION INPUT ;
    USE SIGNAL ;
    PORT
      LAYER M4 ;
        RECT  17.088 36.192 17.28 36.216 ;
    END
  END i[322]
  PIN i[323]
    DIRECTION INPUT ;
    USE SIGNAL ;
    PORT
      LAYER M4 ;
        RECT  17.088 36.288 17.28 36.312 ;
    END
  END i[323]
  PIN i[324]
    DIRECTION INPUT ;
    USE SIGNAL ;
    PORT
      LAYER M4 ;
        RECT  17.088 36.384 17.28 36.408 ;
    END
  END i[324]
  PIN i[325]
    DIRECTION INPUT ;
    USE SIGNAL ;
    PORT
      LAYER M4 ;
        RECT  17.088 36.48 17.28 36.504 ;
    END
  END i[325]
  PIN i[326]
    DIRECTION INPUT ;
    USE SIGNAL ;
    PORT
      LAYER M4 ;
        RECT  17.088 36.624 17.28 36.648 ;
    END
  END i[326]
  PIN i[327]
    DIRECTION INPUT ;
    USE SIGNAL ;
    PORT
      LAYER M4 ;
        RECT  17.088 36.72 17.28 36.744 ;
    END
  END i[327]
  PIN i[328]
    DIRECTION INPUT ;
    USE SIGNAL ;
    PORT
      LAYER M4 ;
        RECT  17.088 36.816 17.28 36.84 ;
    END
  END i[328]
  PIN i[329]
    DIRECTION INPUT ;
    USE SIGNAL ;
    PORT
      LAYER M4 ;
        RECT  17.088 36.912 17.28 36.936 ;
    END
  END i[329]
  PIN i[32]
    DIRECTION INPUT ;
    USE SIGNAL ;
    PORT
      LAYER M4 ;
        RECT  17.088 5.616 17.28 5.64 ;
    END
  END i[32]
  PIN i[330]
    DIRECTION INPUT ;
    USE SIGNAL ;
    PORT
      LAYER M4 ;
        RECT  17.088 37.008 17.28 37.032 ;
    END
  END i[330]
  PIN i[331]
    DIRECTION INPUT ;
    USE SIGNAL ;
    PORT
      LAYER M4 ;
        RECT  17.088 37.152 17.28 37.176 ;
    END
  END i[331]
  PIN i[332]
    DIRECTION INPUT ;
    USE SIGNAL ;
    PORT
      LAYER M4 ;
        RECT  17.088 37.248 17.28 37.272 ;
    END
  END i[332]
  PIN i[333]
    DIRECTION INPUT ;
    USE SIGNAL ;
    PORT
      LAYER M4 ;
        RECT  17.088 37.344 17.28 37.368 ;
    END
  END i[333]
  PIN i[334]
    DIRECTION INPUT ;
    USE SIGNAL ;
    PORT
      LAYER M4 ;
        RECT  17.088 37.44 17.28 37.464 ;
    END
  END i[334]
  PIN i[335]
    DIRECTION INPUT ;
    USE SIGNAL ;
    PORT
      LAYER M4 ;
        RECT  17.088 37.536 17.28 37.56 ;
    END
  END i[335]
  PIN i[336]
    DIRECTION INPUT ;
    USE SIGNAL ;
    PORT
      LAYER M4 ;
        RECT  17.088 37.68 17.28 37.704 ;
    END
  END i[336]
  PIN i[337]
    DIRECTION INPUT ;
    USE SIGNAL ;
    PORT
      LAYER M4 ;
        RECT  17.088 37.776 17.28 37.8 ;
    END
  END i[337]
  PIN i[338]
    DIRECTION INPUT ;
    USE SIGNAL ;
    PORT
      LAYER M4 ;
        RECT  17.088 37.872 17.28 37.896 ;
    END
  END i[338]
  PIN i[339]
    DIRECTION INPUT ;
    USE SIGNAL ;
    PORT
      LAYER M4 ;
        RECT  17.088 37.968 17.28 37.992 ;
    END
  END i[339]
  PIN i[33]
    DIRECTION INPUT ;
    USE SIGNAL ;
    PORT
      LAYER M4 ;
        RECT  17.088 5.712 17.28 5.736 ;
    END
  END i[33]
  PIN i[340]
    DIRECTION INPUT ;
    USE SIGNAL ;
    PORT
      LAYER M4 ;
        RECT  17.088 38.064 17.28 38.088 ;
    END
  END i[340]
  PIN i[341]
    DIRECTION INPUT ;
    USE SIGNAL ;
    PORT
      LAYER M4 ;
        RECT  17.088 38.208 17.28 38.232 ;
    END
  END i[341]
  PIN i[342]
    DIRECTION INPUT ;
    USE SIGNAL ;
    PORT
      LAYER M4 ;
        RECT  17.088 38.304 17.28 38.328 ;
    END
  END i[342]
  PIN i[343]
    DIRECTION INPUT ;
    USE SIGNAL ;
    PORT
      LAYER M4 ;
        RECT  17.088 38.4 17.28 38.424 ;
    END
  END i[343]
  PIN i[344]
    DIRECTION INPUT ;
    USE SIGNAL ;
    PORT
      LAYER M4 ;
        RECT  17.088 38.496 17.28 38.52 ;
    END
  END i[344]
  PIN i[345]
    DIRECTION INPUT ;
    USE SIGNAL ;
    PORT
      LAYER M4 ;
        RECT  17.088 38.592 17.28 38.616 ;
    END
  END i[345]
  PIN i[346]
    DIRECTION INPUT ;
    USE SIGNAL ;
    PORT
      LAYER M4 ;
        RECT  17.088 38.736 17.28 38.76 ;
    END
  END i[346]
  PIN i[347]
    DIRECTION INPUT ;
    USE SIGNAL ;
    PORT
      LAYER M4 ;
        RECT  17.088 38.832 17.28 38.856 ;
    END
  END i[347]
  PIN i[348]
    DIRECTION INPUT ;
    USE SIGNAL ;
    PORT
      LAYER M4 ;
        RECT  17.088 38.928 17.28 38.952 ;
    END
  END i[348]
  PIN i[349]
    DIRECTION INPUT ;
    USE SIGNAL ;
    PORT
      LAYER M4 ;
        RECT  17.088 39.024 17.28 39.048 ;
    END
  END i[349]
  PIN i[34]
    DIRECTION INPUT ;
    USE SIGNAL ;
    PORT
      LAYER M4 ;
        RECT  17.088 5.808 17.28 5.832 ;
    END
  END i[34]
  PIN i[350]
    DIRECTION INPUT ;
    USE SIGNAL ;
    PORT
      LAYER M4 ;
        RECT  17.088 39.12 17.28 39.144 ;
    END
  END i[350]
  PIN i[351]
    DIRECTION INPUT ;
    USE SIGNAL ;
    PORT
      LAYER M4 ;
        RECT  17.088 39.264 17.28 39.288 ;
    END
  END i[351]
  PIN i[352]
    DIRECTION INPUT ;
    USE SIGNAL ;
    PORT
      LAYER M4 ;
        RECT  17.088 39.36 17.28 39.384 ;
    END
  END i[352]
  PIN i[353]
    DIRECTION INPUT ;
    USE SIGNAL ;
    PORT
      LAYER M4 ;
        RECT  17.088 39.456 17.28 39.48 ;
    END
  END i[353]
  PIN i[354]
    DIRECTION INPUT ;
    USE SIGNAL ;
    PORT
      LAYER M4 ;
        RECT  17.088 39.552 17.28 39.576 ;
    END
  END i[354]
  PIN i[355]
    DIRECTION INPUT ;
    USE SIGNAL ;
    PORT
      LAYER M4 ;
        RECT  17.088 39.648 17.28 39.672 ;
    END
  END i[355]
  PIN i[356]
    DIRECTION INPUT ;
    USE SIGNAL ;
    PORT
      LAYER M4 ;
        RECT  17.088 39.792 17.28 39.816 ;
    END
  END i[356]
  PIN i[357]
    DIRECTION INPUT ;
    USE SIGNAL ;
    PORT
      LAYER M4 ;
        RECT  17.088 39.888 17.28 39.912 ;
    END
  END i[357]
  PIN i[358]
    DIRECTION INPUT ;
    USE SIGNAL ;
    PORT
      LAYER M4 ;
        RECT  17.088 39.984 17.28 40.008 ;
    END
  END i[358]
  PIN i[359]
    DIRECTION INPUT ;
    USE SIGNAL ;
    PORT
      LAYER M4 ;
        RECT  17.088 40.08 17.28 40.104 ;
    END
  END i[359]
  PIN i[35]
    DIRECTION INPUT ;
    USE SIGNAL ;
    PORT
      LAYER M4 ;
        RECT  17.088 5.904 17.28 5.928 ;
    END
  END i[35]
  PIN i[360]
    DIRECTION INPUT ;
    USE SIGNAL ;
    PORT
      LAYER M4 ;
        RECT  17.088 40.176 17.28 40.2 ;
    END
  END i[360]
  PIN i[361]
    DIRECTION INPUT ;
    USE SIGNAL ;
    PORT
      LAYER M4 ;
        RECT  17.088 40.32 17.28 40.344 ;
    END
  END i[361]
  PIN i[362]
    DIRECTION INPUT ;
    USE SIGNAL ;
    PORT
      LAYER M4 ;
        RECT  17.088 40.416 17.28 40.44 ;
    END
  END i[362]
  PIN i[363]
    DIRECTION INPUT ;
    USE SIGNAL ;
    PORT
      LAYER M4 ;
        RECT  17.088 40.512 17.28 40.536 ;
    END
  END i[363]
  PIN i[364]
    DIRECTION INPUT ;
    USE SIGNAL ;
    PORT
      LAYER M4 ;
        RECT  17.088 40.608 17.28 40.632 ;
    END
  END i[364]
  PIN i[365]
    DIRECTION INPUT ;
    USE SIGNAL ;
    PORT
      LAYER M4 ;
        RECT  17.088 40.704 17.28 40.728 ;
    END
  END i[365]
  PIN i[366]
    DIRECTION INPUT ;
    USE SIGNAL ;
    PORT
      LAYER M4 ;
        RECT  17.088 40.848 17.28 40.872 ;
    END
  END i[366]
  PIN i[367]
    DIRECTION INPUT ;
    USE SIGNAL ;
    PORT
      LAYER M4 ;
        RECT  17.088 40.944 17.28 40.968 ;
    END
  END i[367]
  PIN i[368]
    DIRECTION INPUT ;
    USE SIGNAL ;
    PORT
      LAYER M4 ;
        RECT  17.088 41.04 17.28 41.064 ;
    END
  END i[368]
  PIN i[369]
    DIRECTION INPUT ;
    USE SIGNAL ;
    PORT
      LAYER M4 ;
        RECT  17.088 41.136 17.28 41.16 ;
    END
  END i[369]
  PIN i[36]
    DIRECTION INPUT ;
    USE SIGNAL ;
    PORT
      LAYER M4 ;
        RECT  17.088 6 17.28 6.024 ;
    END
  END i[36]
  PIN i[370]
    DIRECTION INPUT ;
    USE SIGNAL ;
    PORT
      LAYER M4 ;
        RECT  17.088 41.232 17.28 41.256 ;
    END
  END i[370]
  PIN i[371]
    DIRECTION INPUT ;
    USE SIGNAL ;
    PORT
      LAYER M4 ;
        RECT  17.088 41.376 17.28 41.4 ;
    END
  END i[371]
  PIN i[372]
    DIRECTION INPUT ;
    USE SIGNAL ;
    PORT
      LAYER M4 ;
        RECT  17.088 41.472 17.28 41.496 ;
    END
  END i[372]
  PIN i[373]
    DIRECTION INPUT ;
    USE SIGNAL ;
    PORT
      LAYER M4 ;
        RECT  17.088 41.568 17.28 41.592 ;
    END
  END i[373]
  PIN i[374]
    DIRECTION INPUT ;
    USE SIGNAL ;
    PORT
      LAYER M4 ;
        RECT  17.088 41.664 17.28 41.688 ;
    END
  END i[374]
  PIN i[375]
    DIRECTION INPUT ;
    USE SIGNAL ;
    PORT
      LAYER M4 ;
        RECT  17.088 41.76 17.28 41.784 ;
    END
  END i[375]
  PIN i[376]
    DIRECTION INPUT ;
    USE SIGNAL ;
    PORT
      LAYER M4 ;
        RECT  17.088 41.904 17.28 41.928 ;
    END
  END i[376]
  PIN i[377]
    DIRECTION INPUT ;
    USE SIGNAL ;
    PORT
      LAYER M4 ;
        RECT  17.088 42 17.28 42.024 ;
    END
  END i[377]
  PIN i[378]
    DIRECTION INPUT ;
    USE SIGNAL ;
    PORT
      LAYER M4 ;
        RECT  17.088 42.096 17.28 42.12 ;
    END
  END i[378]
  PIN i[379]
    DIRECTION INPUT ;
    USE SIGNAL ;
    PORT
      LAYER M4 ;
        RECT  17.088 42.192 17.28 42.216 ;
    END
  END i[379]
  PIN i[37]
    DIRECTION INPUT ;
    USE SIGNAL ;
    PORT
      LAYER M4 ;
        RECT  17.088 6.144 17.28 6.168 ;
    END
  END i[37]
  PIN i[380]
    DIRECTION INPUT ;
    USE SIGNAL ;
    PORT
      LAYER M4 ;
        RECT  17.088 42.288 17.28 42.312 ;
    END
  END i[380]
  PIN i[381]
    DIRECTION INPUT ;
    USE SIGNAL ;
    PORT
      LAYER M4 ;
        RECT  17.088 42.432 17.28 42.456 ;
    END
  END i[381]
  PIN i[382]
    DIRECTION INPUT ;
    USE SIGNAL ;
    PORT
      LAYER M4 ;
        RECT  17.088 42.528 17.28 42.552 ;
    END
  END i[382]
  PIN i[383]
    DIRECTION INPUT ;
    USE SIGNAL ;
    PORT
      LAYER M4 ;
        RECT  17.088 42.624 17.28 42.648 ;
    END
  END i[383]
  PIN i[384]
    DIRECTION INPUT ;
    USE SIGNAL ;
    PORT
      LAYER M4 ;
        RECT  17.088 42.72 17.28 42.744 ;
    END
  END i[384]
  PIN i[385]
    DIRECTION INPUT ;
    USE SIGNAL ;
    PORT
      LAYER M4 ;
        RECT  17.088 42.816 17.28 42.84 ;
    END
  END i[385]
  PIN i[386]
    DIRECTION INPUT ;
    USE SIGNAL ;
    PORT
      LAYER M4 ;
        RECT  17.088 42.912 17.28 42.936 ;
    END
  END i[386]
  PIN i[387]
    DIRECTION INPUT ;
    USE SIGNAL ;
    PORT
      LAYER M4 ;
        RECT  17.088 43.056 17.28 43.08 ;
    END
  END i[387]
  PIN i[388]
    DIRECTION INPUT ;
    USE SIGNAL ;
    PORT
      LAYER M4 ;
        RECT  17.088 43.152 17.28 43.176 ;
    END
  END i[388]
  PIN i[389]
    DIRECTION INPUT ;
    USE SIGNAL ;
    PORT
      LAYER M4 ;
        RECT  17.088 43.248 17.28 43.272 ;
    END
  END i[389]
  PIN i[38]
    DIRECTION INPUT ;
    USE SIGNAL ;
    PORT
      LAYER M4 ;
        RECT  17.088 6.24 17.28 6.264 ;
    END
  END i[38]
  PIN i[390]
    DIRECTION INPUT ;
    USE SIGNAL ;
    PORT
      LAYER M4 ;
        RECT  17.088 43.344 17.28 43.368 ;
    END
  END i[390]
  PIN i[391]
    DIRECTION INPUT ;
    USE SIGNAL ;
    PORT
      LAYER M4 ;
        RECT  17.088 43.44 17.28 43.464 ;
    END
  END i[391]
  PIN i[392]
    DIRECTION INPUT ;
    USE SIGNAL ;
    PORT
      LAYER M4 ;
        RECT  17.088 43.584 17.28 43.608 ;
    END
  END i[392]
  PIN i[393]
    DIRECTION INPUT ;
    USE SIGNAL ;
    PORT
      LAYER M4 ;
        RECT  17.088 43.68 17.28 43.704 ;
    END
  END i[393]
  PIN i[394]
    DIRECTION INPUT ;
    USE SIGNAL ;
    PORT
      LAYER M4 ;
        RECT  17.088 43.776 17.28 43.8 ;
    END
  END i[394]
  PIN i[395]
    DIRECTION INPUT ;
    USE SIGNAL ;
    PORT
      LAYER M4 ;
        RECT  17.088 43.872 17.28 43.896 ;
    END
  END i[395]
  PIN i[396]
    DIRECTION INPUT ;
    USE SIGNAL ;
    PORT
      LAYER M4 ;
        RECT  17.088 43.968 17.28 43.992 ;
    END
  END i[396]
  PIN i[397]
    DIRECTION INPUT ;
    USE SIGNAL ;
    PORT
      LAYER M4 ;
        RECT  17.088 44.112 17.28 44.136 ;
    END
  END i[397]
  PIN i[398]
    DIRECTION INPUT ;
    USE SIGNAL ;
    PORT
      LAYER M4 ;
        RECT  17.088 44.208 17.28 44.232 ;
    END
  END i[398]
  PIN i[399]
    DIRECTION INPUT ;
    USE SIGNAL ;
    PORT
      LAYER M4 ;
        RECT  17.088 44.304 17.28 44.328 ;
    END
  END i[399]
  PIN i[39]
    DIRECTION INPUT ;
    USE SIGNAL ;
    PORT
      LAYER M4 ;
        RECT  17.088 6.336 17.28 6.36 ;
    END
  END i[39]
  PIN i[3]
    DIRECTION INPUT ;
    USE SIGNAL ;
    PORT
      LAYER M4 ;
        RECT  17.088 2.544 17.28 2.568 ;
    END
  END i[3]
  PIN i[400]
    DIRECTION INPUT ;
    USE SIGNAL ;
    PORT
      LAYER M4 ;
        RECT  17.088 44.4 17.28 44.424 ;
    END
  END i[400]
  PIN i[401]
    DIRECTION INPUT ;
    USE SIGNAL ;
    PORT
      LAYER M4 ;
        RECT  17.088 44.496 17.28 44.52 ;
    END
  END i[401]
  PIN i[402]
    DIRECTION INPUT ;
    USE SIGNAL ;
    PORT
      LAYER M4 ;
        RECT  17.088 44.64 17.28 44.664 ;
    END
  END i[402]
  PIN i[403]
    DIRECTION INPUT ;
    USE SIGNAL ;
    PORT
      LAYER M4 ;
        RECT  17.088 44.736 17.28 44.76 ;
    END
  END i[403]
  PIN i[404]
    DIRECTION INPUT ;
    USE SIGNAL ;
    PORT
      LAYER M4 ;
        RECT  17.088 44.832 17.28 44.856 ;
    END
  END i[404]
  PIN i[405]
    DIRECTION INPUT ;
    USE SIGNAL ;
    PORT
      LAYER M4 ;
        RECT  17.088 44.928 17.28 44.952 ;
    END
  END i[405]
  PIN i[406]
    DIRECTION INPUT ;
    USE SIGNAL ;
    PORT
      LAYER M4 ;
        RECT  17.088 45.024 17.28 45.048 ;
    END
  END i[406]
  PIN i[407]
    DIRECTION INPUT ;
    USE SIGNAL ;
    PORT
      LAYER M4 ;
        RECT  17.088 45.168 17.28 45.192 ;
    END
  END i[407]
  PIN i[408]
    DIRECTION INPUT ;
    USE SIGNAL ;
    PORT
      LAYER M4 ;
        RECT  17.088 45.264 17.28 45.288 ;
    END
  END i[408]
  PIN i[409]
    DIRECTION INPUT ;
    USE SIGNAL ;
    PORT
      LAYER M4 ;
        RECT  17.088 45.36 17.28 45.384 ;
    END
  END i[409]
  PIN i[40]
    DIRECTION INPUT ;
    USE SIGNAL ;
    PORT
      LAYER M4 ;
        RECT  17.088 6.432 17.28 6.456 ;
    END
  END i[40]
  PIN i[410]
    DIRECTION INPUT ;
    USE SIGNAL ;
    PORT
      LAYER M4 ;
        RECT  17.088 45.456 17.28 45.48 ;
    END
  END i[410]
  PIN i[411]
    DIRECTION INPUT ;
    USE SIGNAL ;
    PORT
      LAYER M4 ;
        RECT  17.088 45.552 17.28 45.576 ;
    END
  END i[411]
  PIN i[412]
    DIRECTION INPUT ;
    USE SIGNAL ;
    PORT
      LAYER M4 ;
        RECT  17.088 45.696 17.28 45.72 ;
    END
  END i[412]
  PIN i[413]
    DIRECTION INPUT ;
    USE SIGNAL ;
    PORT
      LAYER M4 ;
        RECT  17.088 45.792 17.28 45.816 ;
    END
  END i[413]
  PIN i[414]
    DIRECTION INPUT ;
    USE SIGNAL ;
    PORT
      LAYER M4 ;
        RECT  17.088 45.888 17.28 45.912 ;
    END
  END i[414]
  PIN i[415]
    DIRECTION INPUT ;
    USE SIGNAL ;
    PORT
      LAYER M4 ;
        RECT  17.088 45.984 17.28 46.008 ;
    END
  END i[415]
  PIN i[416]
    DIRECTION INPUT ;
    USE SIGNAL ;
    PORT
      LAYER M4 ;
        RECT  17.088 46.08 17.28 46.104 ;
    END
  END i[416]
  PIN i[417]
    DIRECTION INPUT ;
    USE SIGNAL ;
    PORT
      LAYER M4 ;
        RECT  17.088 46.224 17.28 46.248 ;
    END
  END i[417]
  PIN i[418]
    DIRECTION INPUT ;
    USE SIGNAL ;
    PORT
      LAYER M4 ;
        RECT  17.088 46.32 17.28 46.344 ;
    END
  END i[418]
  PIN i[419]
    DIRECTION INPUT ;
    USE SIGNAL ;
    PORT
      LAYER M4 ;
        RECT  17.088 46.416 17.28 46.44 ;
    END
  END i[419]
  PIN i[41]
    DIRECTION INPUT ;
    USE SIGNAL ;
    PORT
      LAYER M4 ;
        RECT  17.088 6.528 17.28 6.552 ;
    END
  END i[41]
  PIN i[420]
    DIRECTION INPUT ;
    USE SIGNAL ;
    PORT
      LAYER M4 ;
        RECT  17.088 46.512 17.28 46.536 ;
    END
  END i[420]
  PIN i[421]
    DIRECTION INPUT ;
    USE SIGNAL ;
    PORT
      LAYER M4 ;
        RECT  17.088 46.608 17.28 46.632 ;
    END
  END i[421]
  PIN i[422]
    DIRECTION INPUT ;
    USE SIGNAL ;
    PORT
      LAYER M4 ;
        RECT  17.088 46.752 17.28 46.776 ;
    END
  END i[422]
  PIN i[423]
    DIRECTION INPUT ;
    USE SIGNAL ;
    PORT
      LAYER M4 ;
        RECT  17.088 46.848 17.28 46.872 ;
    END
  END i[423]
  PIN i[424]
    DIRECTION INPUT ;
    USE SIGNAL ;
    PORT
      LAYER M4 ;
        RECT  17.088 46.944 17.28 46.968 ;
    END
  END i[424]
  PIN i[425]
    DIRECTION INPUT ;
    USE SIGNAL ;
    PORT
      LAYER M4 ;
        RECT  17.088 47.04 17.28 47.064 ;
    END
  END i[425]
  PIN i[426]
    DIRECTION INPUT ;
    USE SIGNAL ;
    PORT
      LAYER M4 ;
        RECT  17.088 47.136 17.28 47.16 ;
    END
  END i[426]
  PIN i[427]
    DIRECTION INPUT ;
    USE SIGNAL ;
    PORT
      LAYER M4 ;
        RECT  17.088 47.28 17.28 47.304 ;
    END
  END i[427]
  PIN i[428]
    DIRECTION INPUT ;
    USE SIGNAL ;
    PORT
      LAYER M4 ;
        RECT  17.088 47.376 17.28 47.4 ;
    END
  END i[428]
  PIN i[429]
    DIRECTION INPUT ;
    USE SIGNAL ;
    PORT
      LAYER M4 ;
        RECT  17.088 47.472 17.28 47.496 ;
    END
  END i[429]
  PIN i[42]
    DIRECTION INPUT ;
    USE SIGNAL ;
    PORT
      LAYER M4 ;
        RECT  17.088 6.672 17.28 6.696 ;
    END
  END i[42]
  PIN i[430]
    DIRECTION INPUT ;
    USE SIGNAL ;
    PORT
      LAYER M4 ;
        RECT  17.088 47.568 17.28 47.592 ;
    END
  END i[430]
  PIN i[431]
    DIRECTION INPUT ;
    USE SIGNAL ;
    PORT
      LAYER M4 ;
        RECT  17.088 47.664 17.28 47.688 ;
    END
  END i[431]
  PIN i[432]
    DIRECTION INPUT ;
    USE SIGNAL ;
    PORT
      LAYER M4 ;
        RECT  17.088 47.808 17.28 47.832 ;
    END
  END i[432]
  PIN i[433]
    DIRECTION INPUT ;
    USE SIGNAL ;
    PORT
      LAYER M4 ;
        RECT  17.088 47.904 17.28 47.928 ;
    END
  END i[433]
  PIN i[434]
    DIRECTION INPUT ;
    USE SIGNAL ;
    PORT
      LAYER M4 ;
        RECT  17.088 48 17.28 48.024 ;
    END
  END i[434]
  PIN i[435]
    DIRECTION INPUT ;
    USE SIGNAL ;
    PORT
      LAYER M4 ;
        RECT  17.088 48.096 17.28 48.12 ;
    END
  END i[435]
  PIN i[436]
    DIRECTION INPUT ;
    USE SIGNAL ;
    PORT
      LAYER M4 ;
        RECT  17.088 48.192 17.28 48.216 ;
    END
  END i[436]
  PIN i[437]
    DIRECTION INPUT ;
    USE SIGNAL ;
    PORT
      LAYER M4 ;
        RECT  17.088 48.336 17.28 48.36 ;
    END
  END i[437]
  PIN i[438]
    DIRECTION INPUT ;
    USE SIGNAL ;
    PORT
      LAYER M4 ;
        RECT  17.088 48.432 17.28 48.456 ;
    END
  END i[438]
  PIN i[439]
    DIRECTION INPUT ;
    USE SIGNAL ;
    PORT
      LAYER M4 ;
        RECT  17.088 48.528 17.28 48.552 ;
    END
  END i[439]
  PIN i[43]
    DIRECTION INPUT ;
    USE SIGNAL ;
    PORT
      LAYER M4 ;
        RECT  17.088 6.768 17.28 6.792 ;
    END
  END i[43]
  PIN i[440]
    DIRECTION INPUT ;
    USE SIGNAL ;
    PORT
      LAYER M4 ;
        RECT  17.088 48.624 17.28 48.648 ;
    END
  END i[440]
  PIN i[441]
    DIRECTION INPUT ;
    USE SIGNAL ;
    PORT
      LAYER M4 ;
        RECT  17.088 48.72 17.28 48.744 ;
    END
  END i[441]
  PIN i[442]
    DIRECTION INPUT ;
    USE SIGNAL ;
    PORT
      LAYER M4 ;
        RECT  17.088 48.864 17.28 48.888 ;
    END
  END i[442]
  PIN i[443]
    DIRECTION INPUT ;
    USE SIGNAL ;
    PORT
      LAYER M4 ;
        RECT  17.088 48.96 17.28 48.984 ;
    END
  END i[443]
  PIN i[444]
    DIRECTION INPUT ;
    USE SIGNAL ;
    PORT
      LAYER M4 ;
        RECT  17.088 49.056 17.28 49.08 ;
    END
  END i[444]
  PIN i[445]
    DIRECTION INPUT ;
    USE SIGNAL ;
    PORT
      LAYER M4 ;
        RECT  17.088 49.152 17.28 49.176 ;
    END
  END i[445]
  PIN i[446]
    DIRECTION INPUT ;
    USE SIGNAL ;
    PORT
      LAYER M4 ;
        RECT  17.088 49.248 17.28 49.272 ;
    END
  END i[446]
  PIN i[447]
    DIRECTION INPUT ;
    USE SIGNAL ;
    PORT
      LAYER M4 ;
        RECT  17.088 49.392 17.28 49.416 ;
    END
  END i[447]
  PIN i[448]
    DIRECTION INPUT ;
    USE SIGNAL ;
    PORT
      LAYER M4 ;
        RECT  17.088 49.488 17.28 49.512 ;
    END
  END i[448]
  PIN i[449]
    DIRECTION INPUT ;
    USE SIGNAL ;
    PORT
      LAYER M4 ;
        RECT  17.088 49.584 17.28 49.608 ;
    END
  END i[449]
  PIN i[44]
    DIRECTION INPUT ;
    USE SIGNAL ;
    PORT
      LAYER M4 ;
        RECT  17.088 6.864 17.28 6.888 ;
    END
  END i[44]
  PIN i[450]
    DIRECTION INPUT ;
    USE SIGNAL ;
    PORT
      LAYER M4 ;
        RECT  17.088 49.68 17.28 49.704 ;
    END
  END i[450]
  PIN i[451]
    DIRECTION INPUT ;
    USE SIGNAL ;
    PORT
      LAYER M4 ;
        RECT  17.088 49.776 17.28 49.8 ;
    END
  END i[451]
  PIN i[452]
    DIRECTION INPUT ;
    USE SIGNAL ;
    PORT
      LAYER M4 ;
        RECT  17.088 49.92 17.28 49.944 ;
    END
  END i[452]
  PIN i[453]
    DIRECTION INPUT ;
    USE SIGNAL ;
    PORT
      LAYER M4 ;
        RECT  17.088 50.016 17.28 50.04 ;
    END
  END i[453]
  PIN i[454]
    DIRECTION INPUT ;
    USE SIGNAL ;
    PORT
      LAYER M4 ;
        RECT  17.088 50.112 17.28 50.136 ;
    END
  END i[454]
  PIN i[455]
    DIRECTION INPUT ;
    USE SIGNAL ;
    PORT
      LAYER M4 ;
        RECT  17.088 50.208 17.28 50.232 ;
    END
  END i[455]
  PIN i[456]
    DIRECTION INPUT ;
    USE SIGNAL ;
    PORT
      LAYER M4 ;
        RECT  17.088 50.304 17.28 50.328 ;
    END
  END i[456]
  PIN i[457]
    DIRECTION INPUT ;
    USE SIGNAL ;
    PORT
      LAYER M4 ;
        RECT  17.088 50.4 17.28 50.424 ;
    END
  END i[457]
  PIN i[458]
    DIRECTION INPUT ;
    USE SIGNAL ;
    PORT
      LAYER M4 ;
        RECT  17.088 50.544 17.28 50.568 ;
    END
  END i[458]
  PIN i[459]
    DIRECTION INPUT ;
    USE SIGNAL ;
    PORT
      LAYER M4 ;
        RECT  17.088 50.64 17.28 50.664 ;
    END
  END i[459]
  PIN i[45]
    DIRECTION INPUT ;
    USE SIGNAL ;
    PORT
      LAYER M4 ;
        RECT  17.088 6.96 17.28 6.984 ;
    END
  END i[45]
  PIN i[460]
    DIRECTION INPUT ;
    USE SIGNAL ;
    PORT
      LAYER M4 ;
        RECT  17.088 50.736 17.28 50.76 ;
    END
  END i[460]
  PIN i[461]
    DIRECTION INPUT ;
    USE SIGNAL ;
    PORT
      LAYER M4 ;
        RECT  17.088 50.832 17.28 50.856 ;
    END
  END i[461]
  PIN i[462]
    DIRECTION INPUT ;
    USE SIGNAL ;
    PORT
      LAYER M4 ;
        RECT  17.088 50.928 17.28 50.952 ;
    END
  END i[462]
  PIN i[463]
    DIRECTION INPUT ;
    USE SIGNAL ;
    PORT
      LAYER M4 ;
        RECT  17.088 51.072 17.28 51.096 ;
    END
  END i[463]
  PIN i[464]
    DIRECTION INPUT ;
    USE SIGNAL ;
    PORT
      LAYER M4 ;
        RECT  17.088 51.168 17.28 51.192 ;
    END
  END i[464]
  PIN i[465]
    DIRECTION INPUT ;
    USE SIGNAL ;
    PORT
      LAYER M4 ;
        RECT  17.088 51.264 17.28 51.288 ;
    END
  END i[465]
  PIN i[466]
    DIRECTION INPUT ;
    USE SIGNAL ;
    PORT
      LAYER M4 ;
        RECT  17.088 51.36 17.28 51.384 ;
    END
  END i[466]
  PIN i[467]
    DIRECTION INPUT ;
    USE SIGNAL ;
    PORT
      LAYER M4 ;
        RECT  17.088 51.456 17.28 51.48 ;
    END
  END i[467]
  PIN i[468]
    DIRECTION INPUT ;
    USE SIGNAL ;
    PORT
      LAYER M4 ;
        RECT  17.088 51.6 17.28 51.624 ;
    END
  END i[468]
  PIN i[469]
    DIRECTION INPUT ;
    USE SIGNAL ;
    PORT
      LAYER M4 ;
        RECT  17.088 51.696 17.28 51.72 ;
    END
  END i[469]
  PIN i[46]
    DIRECTION INPUT ;
    USE SIGNAL ;
    PORT
      LAYER M4 ;
        RECT  17.088 7.056 17.28 7.08 ;
    END
  END i[46]
  PIN i[470]
    DIRECTION INPUT ;
    USE SIGNAL ;
    PORT
      LAYER M4 ;
        RECT  17.088 51.792 17.28 51.816 ;
    END
  END i[470]
  PIN i[471]
    DIRECTION INPUT ;
    USE SIGNAL ;
    PORT
      LAYER M4 ;
        RECT  17.088 51.888 17.28 51.912 ;
    END
  END i[471]
  PIN i[472]
    DIRECTION INPUT ;
    USE SIGNAL ;
    PORT
      LAYER M4 ;
        RECT  17.088 51.984 17.28 52.008 ;
    END
  END i[472]
  PIN i[473]
    DIRECTION INPUT ;
    USE SIGNAL ;
    PORT
      LAYER M4 ;
        RECT  17.088 52.128 17.28 52.152 ;
    END
  END i[473]
  PIN i[474]
    DIRECTION INPUT ;
    USE SIGNAL ;
    PORT
      LAYER M4 ;
        RECT  17.088 52.224 17.28 52.248 ;
    END
  END i[474]
  PIN i[475]
    DIRECTION INPUT ;
    USE SIGNAL ;
    PORT
      LAYER M4 ;
        RECT  17.088 52.32 17.28 52.344 ;
    END
  END i[475]
  PIN i[476]
    DIRECTION INPUT ;
    USE SIGNAL ;
    PORT
      LAYER M4 ;
        RECT  17.088 52.416 17.28 52.44 ;
    END
  END i[476]
  PIN i[477]
    DIRECTION INPUT ;
    USE SIGNAL ;
    PORT
      LAYER M4 ;
        RECT  17.088 52.512 17.28 52.536 ;
    END
  END i[477]
  PIN i[478]
    DIRECTION INPUT ;
    USE SIGNAL ;
    PORT
      LAYER M4 ;
        RECT  17.088 52.656 17.28 52.68 ;
    END
  END i[478]
  PIN i[479]
    DIRECTION INPUT ;
    USE SIGNAL ;
    PORT
      LAYER M4 ;
        RECT  17.088 52.752 17.28 52.776 ;
    END
  END i[479]
  PIN i[47]
    DIRECTION INPUT ;
    USE SIGNAL ;
    PORT
      LAYER M4 ;
        RECT  17.088 7.2 17.28 7.224 ;
    END
  END i[47]
  PIN i[480]
    DIRECTION INPUT ;
    USE SIGNAL ;
    PORT
      LAYER M4 ;
        RECT  17.088 52.848 17.28 52.872 ;
    END
  END i[480]
  PIN i[481]
    DIRECTION INPUT ;
    USE SIGNAL ;
    PORT
      LAYER M4 ;
        RECT  17.088 52.944 17.28 52.968 ;
    END
  END i[481]
  PIN i[482]
    DIRECTION INPUT ;
    USE SIGNAL ;
    PORT
      LAYER M4 ;
        RECT  17.088 53.04 17.28 53.064 ;
    END
  END i[482]
  PIN i[483]
    DIRECTION INPUT ;
    USE SIGNAL ;
    PORT
      LAYER M4 ;
        RECT  17.088 53.184 17.28 53.208 ;
    END
  END i[483]
  PIN i[484]
    DIRECTION INPUT ;
    USE SIGNAL ;
    PORT
      LAYER M4 ;
        RECT  17.088 53.28 17.28 53.304 ;
    END
  END i[484]
  PIN i[485]
    DIRECTION INPUT ;
    USE SIGNAL ;
    PORT
      LAYER M4 ;
        RECT  17.088 53.376 17.28 53.4 ;
    END
  END i[485]
  PIN i[486]
    DIRECTION INPUT ;
    USE SIGNAL ;
    PORT
      LAYER M4 ;
        RECT  17.088 53.472 17.28 53.496 ;
    END
  END i[486]
  PIN i[487]
    DIRECTION INPUT ;
    USE SIGNAL ;
    PORT
      LAYER M4 ;
        RECT  17.088 53.568 17.28 53.592 ;
    END
  END i[487]
  PIN i[488]
    DIRECTION INPUT ;
    USE SIGNAL ;
    PORT
      LAYER M4 ;
        RECT  17.088 53.712 17.28 53.736 ;
    END
  END i[488]
  PIN i[489]
    DIRECTION INPUT ;
    USE SIGNAL ;
    PORT
      LAYER M4 ;
        RECT  17.088 53.808 17.28 53.832 ;
    END
  END i[489]
  PIN i[48]
    DIRECTION INPUT ;
    USE SIGNAL ;
    PORT
      LAYER M4 ;
        RECT  17.088 7.296 17.28 7.32 ;
    END
  END i[48]
  PIN i[490]
    DIRECTION INPUT ;
    USE SIGNAL ;
    PORT
      LAYER M4 ;
        RECT  17.088 53.904 17.28 53.928 ;
    END
  END i[490]
  PIN i[491]
    DIRECTION INPUT ;
    USE SIGNAL ;
    PORT
      LAYER M4 ;
        RECT  17.088 54 17.28 54.024 ;
    END
  END i[491]
  PIN i[492]
    DIRECTION INPUT ;
    USE SIGNAL ;
    PORT
      LAYER M4 ;
        RECT  17.088 54.096 17.28 54.12 ;
    END
  END i[492]
  PIN i[493]
    DIRECTION INPUT ;
    USE SIGNAL ;
    PORT
      LAYER M4 ;
        RECT  17.088 54.24 17.28 54.264 ;
    END
  END i[493]
  PIN i[494]
    DIRECTION INPUT ;
    USE SIGNAL ;
    PORT
      LAYER M4 ;
        RECT  17.088 54.336 17.28 54.36 ;
    END
  END i[494]
  PIN i[495]
    DIRECTION INPUT ;
    USE SIGNAL ;
    PORT
      LAYER M4 ;
        RECT  17.088 54.432 17.28 54.456 ;
    END
  END i[495]
  PIN i[496]
    DIRECTION INPUT ;
    USE SIGNAL ;
    PORT
      LAYER M4 ;
        RECT  17.088 54.528 17.28 54.552 ;
    END
  END i[496]
  PIN i[497]
    DIRECTION INPUT ;
    USE SIGNAL ;
    PORT
      LAYER M4 ;
        RECT  17.088 54.624 17.28 54.648 ;
    END
  END i[497]
  PIN i[498]
    DIRECTION INPUT ;
    USE SIGNAL ;
    PORT
      LAYER M4 ;
        RECT  17.088 54.768 17.28 54.792 ;
    END
  END i[498]
  PIN i[499]
    DIRECTION INPUT ;
    USE SIGNAL ;
    PORT
      LAYER M4 ;
        RECT  17.088 54.864 17.28 54.888 ;
    END
  END i[499]
  PIN i[49]
    DIRECTION INPUT ;
    USE SIGNAL ;
    PORT
      LAYER M4 ;
        RECT  17.088 7.392 17.28 7.416 ;
    END
  END i[49]
  PIN i[4]
    DIRECTION INPUT ;
    USE SIGNAL ;
    PORT
      LAYER M4 ;
        RECT  17.088 2.64 17.28 2.664 ;
    END
  END i[4]
  PIN i[500]
    DIRECTION INPUT ;
    USE SIGNAL ;
    PORT
      LAYER M4 ;
        RECT  17.088 54.96 17.28 54.984 ;
    END
  END i[500]
  PIN i[501]
    DIRECTION INPUT ;
    USE SIGNAL ;
    PORT
      LAYER M4 ;
        RECT  17.088 55.056 17.28 55.08 ;
    END
  END i[501]
  PIN i[502]
    DIRECTION INPUT ;
    USE SIGNAL ;
    PORT
      LAYER M4 ;
        RECT  17.088 55.152 17.28 55.176 ;
    END
  END i[502]
  PIN i[503]
    DIRECTION INPUT ;
    USE SIGNAL ;
    PORT
      LAYER M4 ;
        RECT  17.088 55.296 17.28 55.32 ;
    END
  END i[503]
  PIN i[504]
    DIRECTION INPUT ;
    USE SIGNAL ;
    PORT
      LAYER M4 ;
        RECT  17.088 55.392 17.28 55.416 ;
    END
  END i[504]
  PIN i[505]
    DIRECTION INPUT ;
    USE SIGNAL ;
    PORT
      LAYER M4 ;
        RECT  17.088 55.488 17.28 55.512 ;
    END
  END i[505]
  PIN i[506]
    DIRECTION INPUT ;
    USE SIGNAL ;
    PORT
      LAYER M4 ;
        RECT  17.088 55.584 17.28 55.608 ;
    END
  END i[506]
  PIN i[507]
    DIRECTION INPUT ;
    USE SIGNAL ;
    PORT
      LAYER M4 ;
        RECT  17.088 55.68 17.28 55.704 ;
    END
  END i[507]
  PIN i[508]
    DIRECTION INPUT ;
    USE SIGNAL ;
    PORT
      LAYER M4 ;
        RECT  17.088 55.824 17.28 55.848 ;
    END
  END i[508]
  PIN i[509]
    DIRECTION INPUT ;
    USE SIGNAL ;
    PORT
      LAYER M4 ;
        RECT  17.088 55.92 17.28 55.944 ;
    END
  END i[509]
  PIN i[50]
    DIRECTION INPUT ;
    USE SIGNAL ;
    PORT
      LAYER M4 ;
        RECT  17.088 7.488 17.28 7.512 ;
    END
  END i[50]
  PIN i[510]
    DIRECTION INPUT ;
    USE SIGNAL ;
    PORT
      LAYER M4 ;
        RECT  17.088 56.016 17.28 56.04 ;
    END
  END i[510]
  PIN i[511]
    DIRECTION INPUT ;
    USE SIGNAL ;
    PORT
      LAYER M4 ;
        RECT  17.088 56.112 17.28 56.136 ;
    END
  END i[511]
  PIN i[51]
    DIRECTION INPUT ;
    USE SIGNAL ;
    PORT
      LAYER M4 ;
        RECT  17.088 7.584 17.28 7.608 ;
    END
  END i[51]
  PIN i[52]
    DIRECTION INPUT ;
    USE SIGNAL ;
    PORT
      LAYER M4 ;
        RECT  17.088 7.728 17.28 7.752 ;
    END
  END i[52]
  PIN i[53]
    DIRECTION INPUT ;
    USE SIGNAL ;
    PORT
      LAYER M4 ;
        RECT  17.088 7.824 17.28 7.848 ;
    END
  END i[53]
  PIN i[54]
    DIRECTION INPUT ;
    USE SIGNAL ;
    PORT
      LAYER M4 ;
        RECT  17.088 7.92 17.28 7.944 ;
    END
  END i[54]
  PIN i[55]
    DIRECTION INPUT ;
    USE SIGNAL ;
    PORT
      LAYER M4 ;
        RECT  17.088 8.016 17.28 8.04 ;
    END
  END i[55]
  PIN i[56]
    DIRECTION INPUT ;
    USE SIGNAL ;
    PORT
      LAYER M4 ;
        RECT  17.088 8.112 17.28 8.136 ;
    END
  END i[56]
  PIN i[57]
    DIRECTION INPUT ;
    USE SIGNAL ;
    PORT
      LAYER M4 ;
        RECT  17.088 8.256 17.28 8.28 ;
    END
  END i[57]
  PIN i[58]
    DIRECTION INPUT ;
    USE SIGNAL ;
    PORT
      LAYER M4 ;
        RECT  17.088 8.352 17.28 8.376 ;
    END
  END i[58]
  PIN i[59]
    DIRECTION INPUT ;
    USE SIGNAL ;
    PORT
      LAYER M4 ;
        RECT  17.088 8.448 17.28 8.472 ;
    END
  END i[59]
  PIN i[5]
    DIRECTION INPUT ;
    USE SIGNAL ;
    PORT
      LAYER M4 ;
        RECT  17.088 2.736 17.28 2.76 ;
    END
  END i[5]
  PIN i[60]
    DIRECTION INPUT ;
    USE SIGNAL ;
    PORT
      LAYER M4 ;
        RECT  17.088 8.544 17.28 8.568 ;
    END
  END i[60]
  PIN i[61]
    DIRECTION INPUT ;
    USE SIGNAL ;
    PORT
      LAYER M4 ;
        RECT  17.088 8.64 17.28 8.664 ;
    END
  END i[61]
  PIN i[62]
    DIRECTION INPUT ;
    USE SIGNAL ;
    PORT
      LAYER M4 ;
        RECT  17.088 8.784 17.28 8.808 ;
    END
  END i[62]
  PIN i[63]
    DIRECTION INPUT ;
    USE SIGNAL ;
    PORT
      LAYER M4 ;
        RECT  17.088 8.88 17.28 8.904 ;
    END
  END i[63]
  PIN i[64]
    DIRECTION INPUT ;
    USE SIGNAL ;
    PORT
      LAYER M4 ;
        RECT  17.088 8.976 17.28 9 ;
    END
  END i[64]
  PIN i[65]
    DIRECTION INPUT ;
    USE SIGNAL ;
    PORT
      LAYER M4 ;
        RECT  17.088 9.072 17.28 9.096 ;
    END
  END i[65]
  PIN i[66]
    DIRECTION INPUT ;
    USE SIGNAL ;
    PORT
      LAYER M4 ;
        RECT  17.088 9.168 17.28 9.192 ;
    END
  END i[66]
  PIN i[67]
    DIRECTION INPUT ;
    USE SIGNAL ;
    PORT
      LAYER M4 ;
        RECT  17.088 9.312 17.28 9.336 ;
    END
  END i[67]
  PIN i[68]
    DIRECTION INPUT ;
    USE SIGNAL ;
    PORT
      LAYER M4 ;
        RECT  17.088 9.408 17.28 9.432 ;
    END
  END i[68]
  PIN i[69]
    DIRECTION INPUT ;
    USE SIGNAL ;
    PORT
      LAYER M4 ;
        RECT  17.088 9.504 17.28 9.528 ;
    END
  END i[69]
  PIN i[6]
    DIRECTION INPUT ;
    USE SIGNAL ;
    PORT
      LAYER M4 ;
        RECT  17.088 2.88 17.28 2.904 ;
    END
  END i[6]
  PIN i[70]
    DIRECTION INPUT ;
    USE SIGNAL ;
    PORT
      LAYER M4 ;
        RECT  17.088 9.6 17.28 9.624 ;
    END
  END i[70]
  PIN i[71]
    DIRECTION INPUT ;
    USE SIGNAL ;
    PORT
      LAYER M4 ;
        RECT  17.088 9.696 17.28 9.72 ;
    END
  END i[71]
  PIN i[72]
    DIRECTION INPUT ;
    USE SIGNAL ;
    PORT
      LAYER M4 ;
        RECT  17.088 9.84 17.28 9.864 ;
    END
  END i[72]
  PIN i[73]
    DIRECTION INPUT ;
    USE SIGNAL ;
    PORT
      LAYER M4 ;
        RECT  17.088 9.936 17.28 9.96 ;
    END
  END i[73]
  PIN i[74]
    DIRECTION INPUT ;
    USE SIGNAL ;
    PORT
      LAYER M4 ;
        RECT  17.088 10.032 17.28 10.056 ;
    END
  END i[74]
  PIN i[75]
    DIRECTION INPUT ;
    USE SIGNAL ;
    PORT
      LAYER M4 ;
        RECT  17.088 10.128 17.28 10.152 ;
    END
  END i[75]
  PIN i[76]
    DIRECTION INPUT ;
    USE SIGNAL ;
    PORT
      LAYER M4 ;
        RECT  17.088 10.224 17.28 10.248 ;
    END
  END i[76]
  PIN i[77]
    DIRECTION INPUT ;
    USE SIGNAL ;
    PORT
      LAYER M4 ;
        RECT  17.088 10.368 17.28 10.392 ;
    END
  END i[77]
  PIN i[78]
    DIRECTION INPUT ;
    USE SIGNAL ;
    PORT
      LAYER M4 ;
        RECT  17.088 10.464 17.28 10.488 ;
    END
  END i[78]
  PIN i[79]
    DIRECTION INPUT ;
    USE SIGNAL ;
    PORT
      LAYER M4 ;
        RECT  17.088 10.56 17.28 10.584 ;
    END
  END i[79]
  PIN i[7]
    DIRECTION INPUT ;
    USE SIGNAL ;
    PORT
      LAYER M4 ;
        RECT  17.088 2.976 17.28 3 ;
    END
  END i[7]
  PIN i[80]
    DIRECTION INPUT ;
    USE SIGNAL ;
    PORT
      LAYER M4 ;
        RECT  17.088 10.656 17.28 10.68 ;
    END
  END i[80]
  PIN i[81]
    DIRECTION INPUT ;
    USE SIGNAL ;
    PORT
      LAYER M4 ;
        RECT  17.088 10.752 17.28 10.776 ;
    END
  END i[81]
  PIN i[82]
    DIRECTION INPUT ;
    USE SIGNAL ;
    PORT
      LAYER M4 ;
        RECT  17.088 10.896 17.28 10.92 ;
    END
  END i[82]
  PIN i[83]
    DIRECTION INPUT ;
    USE SIGNAL ;
    PORT
      LAYER M4 ;
        RECT  17.088 10.992 17.28 11.016 ;
    END
  END i[83]
  PIN i[84]
    DIRECTION INPUT ;
    USE SIGNAL ;
    PORT
      LAYER M4 ;
        RECT  17.088 11.088 17.28 11.112 ;
    END
  END i[84]
  PIN i[85]
    DIRECTION INPUT ;
    USE SIGNAL ;
    PORT
      LAYER M4 ;
        RECT  17.088 11.184 17.28 11.208 ;
    END
  END i[85]
  PIN i[86]
    DIRECTION INPUT ;
    USE SIGNAL ;
    PORT
      LAYER M4 ;
        RECT  17.088 11.28 17.28 11.304 ;
    END
  END i[86]
  PIN i[87]
    DIRECTION INPUT ;
    USE SIGNAL ;
    PORT
      LAYER M4 ;
        RECT  17.088 11.424 17.28 11.448 ;
    END
  END i[87]
  PIN i[88]
    DIRECTION INPUT ;
    USE SIGNAL ;
    PORT
      LAYER M4 ;
        RECT  17.088 11.52 17.28 11.544 ;
    END
  END i[88]
  PIN i[89]
    DIRECTION INPUT ;
    USE SIGNAL ;
    PORT
      LAYER M4 ;
        RECT  17.088 11.616 17.28 11.64 ;
    END
  END i[89]
  PIN i[8]
    DIRECTION INPUT ;
    USE SIGNAL ;
    PORT
      LAYER M4 ;
        RECT  17.088 3.072 17.28 3.096 ;
    END
  END i[8]
  PIN i[90]
    DIRECTION INPUT ;
    USE SIGNAL ;
    PORT
      LAYER M4 ;
        RECT  17.088 11.712 17.28 11.736 ;
    END
  END i[90]
  PIN i[91]
    DIRECTION INPUT ;
    USE SIGNAL ;
    PORT
      LAYER M4 ;
        RECT  17.088 11.808 17.28 11.832 ;
    END
  END i[91]
  PIN i[92]
    DIRECTION INPUT ;
    USE SIGNAL ;
    PORT
      LAYER M4 ;
        RECT  17.088 11.904 17.28 11.928 ;
    END
  END i[92]
  PIN i[93]
    DIRECTION INPUT ;
    USE SIGNAL ;
    PORT
      LAYER M4 ;
        RECT  17.088 12.048 17.28 12.072 ;
    END
  END i[93]
  PIN i[94]
    DIRECTION INPUT ;
    USE SIGNAL ;
    PORT
      LAYER M4 ;
        RECT  17.088 12.144 17.28 12.168 ;
    END
  END i[94]
  PIN i[95]
    DIRECTION INPUT ;
    USE SIGNAL ;
    PORT
      LAYER M4 ;
        RECT  17.088 12.24 17.28 12.264 ;
    END
  END i[95]
  PIN i[96]
    DIRECTION INPUT ;
    USE SIGNAL ;
    PORT
      LAYER M4 ;
        RECT  17.088 12.336 17.28 12.36 ;
    END
  END i[96]
  PIN i[97]
    DIRECTION INPUT ;
    USE SIGNAL ;
    PORT
      LAYER M4 ;
        RECT  17.088 12.432 17.28 12.456 ;
    END
  END i[97]
  PIN i[98]
    DIRECTION INPUT ;
    USE SIGNAL ;
    PORT
      LAYER M4 ;
        RECT  17.088 12.576 17.28 12.6 ;
    END
  END i[98]
  PIN i[99]
    DIRECTION INPUT ;
    USE SIGNAL ;
    PORT
      LAYER M4 ;
        RECT  17.088 12.672 17.28 12.696 ;
    END
  END i[99]
  PIN i[9]
    DIRECTION INPUT ;
    USE SIGNAL ;
    PORT
      LAYER M4 ;
        RECT  17.088 3.168 17.28 3.192 ;
    END
  END i[9]
  PIN o[0]
    DIRECTION OUTPUT ;
    USE SIGNAL ;
    PORT
      LAYER M4 ;
        RECT  0 2.208 0.192 2.232 ;
    END
  END o[0]
  PIN o[100]
    DIRECTION OUTPUT ;
    USE SIGNAL ;
    PORT
      LAYER M4 ;
        RECT  0 12.768 0.192 12.792 ;
    END
  END o[100]
  PIN o[101]
    DIRECTION OUTPUT ;
    USE SIGNAL ;
    PORT
      LAYER M4 ;
        RECT  0 12.864 0.192 12.888 ;
    END
  END o[101]
  PIN o[102]
    DIRECTION OUTPUT ;
    USE SIGNAL ;
    PORT
      LAYER M4 ;
        RECT  0 12.96 0.192 12.984 ;
    END
  END o[102]
  PIN o[103]
    DIRECTION OUTPUT ;
    USE SIGNAL ;
    PORT
      LAYER M4 ;
        RECT  0 13.056 0.192 13.08 ;
    END
  END o[103]
  PIN o[104]
    DIRECTION OUTPUT ;
    USE SIGNAL ;
    PORT
      LAYER M4 ;
        RECT  0 13.152 0.192 13.176 ;
    END
  END o[104]
  PIN o[105]
    DIRECTION OUTPUT ;
    USE SIGNAL ;
    PORT
      LAYER M4 ;
        RECT  0 13.296 0.192 13.32 ;
    END
  END o[105]
  PIN o[106]
    DIRECTION OUTPUT ;
    USE SIGNAL ;
    PORT
      LAYER M4 ;
        RECT  0 13.392 0.192 13.416 ;
    END
  END o[106]
  PIN o[107]
    DIRECTION OUTPUT ;
    USE SIGNAL ;
    PORT
      LAYER M4 ;
        RECT  0 13.488 0.192 13.512 ;
    END
  END o[107]
  PIN o[108]
    DIRECTION OUTPUT ;
    USE SIGNAL ;
    PORT
      LAYER M4 ;
        RECT  0 13.584 0.192 13.608 ;
    END
  END o[108]
  PIN o[109]
    DIRECTION OUTPUT ;
    USE SIGNAL ;
    PORT
      LAYER M4 ;
        RECT  0 13.68 0.192 13.704 ;
    END
  END o[109]
  PIN o[10]
    DIRECTION OUTPUT ;
    USE SIGNAL ;
    PORT
      LAYER M4 ;
        RECT  0 3.264 0.192 3.288 ;
    END
  END o[10]
  PIN o[110]
    DIRECTION OUTPUT ;
    USE SIGNAL ;
    PORT
      LAYER M4 ;
        RECT  0 13.824 0.192 13.848 ;
    END
  END o[110]
  PIN o[111]
    DIRECTION OUTPUT ;
    USE SIGNAL ;
    PORT
      LAYER M4 ;
        RECT  0 13.92 0.192 13.944 ;
    END
  END o[111]
  PIN o[112]
    DIRECTION OUTPUT ;
    USE SIGNAL ;
    PORT
      LAYER M4 ;
        RECT  0 14.016 0.192 14.04 ;
    END
  END o[112]
  PIN o[113]
    DIRECTION OUTPUT ;
    USE SIGNAL ;
    PORT
      LAYER M4 ;
        RECT  0 14.112 0.192 14.136 ;
    END
  END o[113]
  PIN o[114]
    DIRECTION OUTPUT ;
    USE SIGNAL ;
    PORT
      LAYER M4 ;
        RECT  0 14.208 0.192 14.232 ;
    END
  END o[114]
  PIN o[115]
    DIRECTION OUTPUT ;
    USE SIGNAL ;
    PORT
      LAYER M4 ;
        RECT  0 14.352 0.192 14.376 ;
    END
  END o[115]
  PIN o[116]
    DIRECTION OUTPUT ;
    USE SIGNAL ;
    PORT
      LAYER M4 ;
        RECT  0 14.448 0.192 14.472 ;
    END
  END o[116]
  PIN o[117]
    DIRECTION OUTPUT ;
    USE SIGNAL ;
    PORT
      LAYER M4 ;
        RECT  0 14.544 0.192 14.568 ;
    END
  END o[117]
  PIN o[118]
    DIRECTION OUTPUT ;
    USE SIGNAL ;
    PORT
      LAYER M4 ;
        RECT  0 14.64 0.192 14.664 ;
    END
  END o[118]
  PIN o[119]
    DIRECTION OUTPUT ;
    USE SIGNAL ;
    PORT
      LAYER M4 ;
        RECT  0 14.736 0.192 14.76 ;
    END
  END o[119]
  PIN o[11]
    DIRECTION OUTPUT ;
    USE SIGNAL ;
    PORT
      LAYER M4 ;
        RECT  0 3.36 0.192 3.384 ;
    END
  END o[11]
  PIN o[120]
    DIRECTION OUTPUT ;
    USE SIGNAL ;
    PORT
      LAYER M4 ;
        RECT  0 14.88 0.192 14.904 ;
    END
  END o[120]
  PIN o[121]
    DIRECTION OUTPUT ;
    USE SIGNAL ;
    PORT
      LAYER M4 ;
        RECT  0 14.976 0.192 15 ;
    END
  END o[121]
  PIN o[122]
    DIRECTION OUTPUT ;
    USE SIGNAL ;
    PORT
      LAYER M4 ;
        RECT  0 15.072 0.192 15.096 ;
    END
  END o[122]
  PIN o[123]
    DIRECTION OUTPUT ;
    USE SIGNAL ;
    PORT
      LAYER M4 ;
        RECT  0 15.168 0.192 15.192 ;
    END
  END o[123]
  PIN o[124]
    DIRECTION OUTPUT ;
    USE SIGNAL ;
    PORT
      LAYER M4 ;
        RECT  0 15.264 0.192 15.288 ;
    END
  END o[124]
  PIN o[125]
    DIRECTION OUTPUT ;
    USE SIGNAL ;
    PORT
      LAYER M4 ;
        RECT  0 15.36 0.192 15.384 ;
    END
  END o[125]
  PIN o[126]
    DIRECTION OUTPUT ;
    USE SIGNAL ;
    PORT
      LAYER M4 ;
        RECT  0 15.504 0.192 15.528 ;
    END
  END o[126]
  PIN o[127]
    DIRECTION OUTPUT ;
    USE SIGNAL ;
    PORT
      LAYER M4 ;
        RECT  0 15.6 0.192 15.624 ;
    END
  END o[127]
  PIN o[128]
    DIRECTION OUTPUT ;
    USE SIGNAL ;
    PORT
      LAYER M4 ;
        RECT  0 15.696 0.192 15.72 ;
    END
  END o[128]
  PIN o[129]
    DIRECTION OUTPUT ;
    USE SIGNAL ;
    PORT
      LAYER M4 ;
        RECT  0 15.792 0.192 15.816 ;
    END
  END o[129]
  PIN o[12]
    DIRECTION OUTPUT ;
    USE SIGNAL ;
    PORT
      LAYER M4 ;
        RECT  0 3.504 0.192 3.528 ;
    END
  END o[12]
  PIN o[130]
    DIRECTION OUTPUT ;
    USE SIGNAL ;
    PORT
      LAYER M4 ;
        RECT  0 15.888 0.192 15.912 ;
    END
  END o[130]
  PIN o[131]
    DIRECTION OUTPUT ;
    USE SIGNAL ;
    PORT
      LAYER M4 ;
        RECT  0 16.032 0.192 16.056 ;
    END
  END o[131]
  PIN o[132]
    DIRECTION OUTPUT ;
    USE SIGNAL ;
    PORT
      LAYER M4 ;
        RECT  0 16.128 0.192 16.152 ;
    END
  END o[132]
  PIN o[133]
    DIRECTION OUTPUT ;
    USE SIGNAL ;
    PORT
      LAYER M4 ;
        RECT  0 16.224 0.192 16.248 ;
    END
  END o[133]
  PIN o[134]
    DIRECTION OUTPUT ;
    USE SIGNAL ;
    PORT
      LAYER M4 ;
        RECT  0 16.32 0.192 16.344 ;
    END
  END o[134]
  PIN o[135]
    DIRECTION OUTPUT ;
    USE SIGNAL ;
    PORT
      LAYER M4 ;
        RECT  0 16.416 0.192 16.44 ;
    END
  END o[135]
  PIN o[136]
    DIRECTION OUTPUT ;
    USE SIGNAL ;
    PORT
      LAYER M4 ;
        RECT  0 16.56 0.192 16.584 ;
    END
  END o[136]
  PIN o[137]
    DIRECTION OUTPUT ;
    USE SIGNAL ;
    PORT
      LAYER M4 ;
        RECT  0 16.656 0.192 16.68 ;
    END
  END o[137]
  PIN o[138]
    DIRECTION OUTPUT ;
    USE SIGNAL ;
    PORT
      LAYER M4 ;
        RECT  0 16.752 0.192 16.776 ;
    END
  END o[138]
  PIN o[139]
    DIRECTION OUTPUT ;
    USE SIGNAL ;
    PORT
      LAYER M4 ;
        RECT  0 16.848 0.192 16.872 ;
    END
  END o[139]
  PIN o[13]
    DIRECTION OUTPUT ;
    USE SIGNAL ;
    PORT
      LAYER M4 ;
        RECT  0 3.6 0.192 3.624 ;
    END
  END o[13]
  PIN o[140]
    DIRECTION OUTPUT ;
    USE SIGNAL ;
    PORT
      LAYER M4 ;
        RECT  0 16.944 0.192 16.968 ;
    END
  END o[140]
  PIN o[141]
    DIRECTION OUTPUT ;
    USE SIGNAL ;
    PORT
      LAYER M4 ;
        RECT  0 17.088 0.192 17.112 ;
    END
  END o[141]
  PIN o[142]
    DIRECTION OUTPUT ;
    USE SIGNAL ;
    PORT
      LAYER M4 ;
        RECT  0 17.184 0.192 17.208 ;
    END
  END o[142]
  PIN o[143]
    DIRECTION OUTPUT ;
    USE SIGNAL ;
    PORT
      LAYER M4 ;
        RECT  0 17.28 0.192 17.304 ;
    END
  END o[143]
  PIN o[144]
    DIRECTION OUTPUT ;
    USE SIGNAL ;
    PORT
      LAYER M4 ;
        RECT  0 17.376 0.192 17.4 ;
    END
  END o[144]
  PIN o[145]
    DIRECTION OUTPUT ;
    USE SIGNAL ;
    PORT
      LAYER M4 ;
        RECT  0 17.472 0.192 17.496 ;
    END
  END o[145]
  PIN o[146]
    DIRECTION OUTPUT ;
    USE SIGNAL ;
    PORT
      LAYER M4 ;
        RECT  0 17.616 0.192 17.64 ;
    END
  END o[146]
  PIN o[147]
    DIRECTION OUTPUT ;
    USE SIGNAL ;
    PORT
      LAYER M4 ;
        RECT  0 17.712 0.192 17.736 ;
    END
  END o[147]
  PIN o[148]
    DIRECTION OUTPUT ;
    USE SIGNAL ;
    PORT
      LAYER M4 ;
        RECT  0 17.808 0.192 17.832 ;
    END
  END o[148]
  PIN o[149]
    DIRECTION OUTPUT ;
    USE SIGNAL ;
    PORT
      LAYER M4 ;
        RECT  0 17.904 0.192 17.928 ;
    END
  END o[149]
  PIN o[14]
    DIRECTION OUTPUT ;
    USE SIGNAL ;
    PORT
      LAYER M4 ;
        RECT  0 3.696 0.192 3.72 ;
    END
  END o[14]
  PIN o[150]
    DIRECTION OUTPUT ;
    USE SIGNAL ;
    PORT
      LAYER M4 ;
        RECT  0 18 0.192 18.024 ;
    END
  END o[150]
  PIN o[151]
    DIRECTION OUTPUT ;
    USE SIGNAL ;
    PORT
      LAYER M4 ;
        RECT  0 18.096 0.192 18.12 ;
    END
  END o[151]
  PIN o[152]
    DIRECTION OUTPUT ;
    USE SIGNAL ;
    PORT
      LAYER M4 ;
        RECT  0 18.24 0.192 18.264 ;
    END
  END o[152]
  PIN o[153]
    DIRECTION OUTPUT ;
    USE SIGNAL ;
    PORT
      LAYER M4 ;
        RECT  0 18.336 0.192 18.36 ;
    END
  END o[153]
  PIN o[154]
    DIRECTION OUTPUT ;
    USE SIGNAL ;
    PORT
      LAYER M4 ;
        RECT  0 18.432 0.192 18.456 ;
    END
  END o[154]
  PIN o[155]
    DIRECTION OUTPUT ;
    USE SIGNAL ;
    PORT
      LAYER M4 ;
        RECT  0 18.528 0.192 18.552 ;
    END
  END o[155]
  PIN o[156]
    DIRECTION OUTPUT ;
    USE SIGNAL ;
    PORT
      LAYER M4 ;
        RECT  0 18.624 0.192 18.648 ;
    END
  END o[156]
  PIN o[157]
    DIRECTION OUTPUT ;
    USE SIGNAL ;
    PORT
      LAYER M4 ;
        RECT  0 18.768 0.192 18.792 ;
    END
  END o[157]
  PIN o[158]
    DIRECTION OUTPUT ;
    USE SIGNAL ;
    PORT
      LAYER M4 ;
        RECT  0 18.864 0.192 18.888 ;
    END
  END o[158]
  PIN o[159]
    DIRECTION OUTPUT ;
    USE SIGNAL ;
    PORT
      LAYER M4 ;
        RECT  0 18.96 0.192 18.984 ;
    END
  END o[159]
  PIN o[15]
    DIRECTION OUTPUT ;
    USE SIGNAL ;
    PORT
      LAYER M4 ;
        RECT  0 3.792 0.192 3.816 ;
    END
  END o[15]
  PIN o[160]
    DIRECTION OUTPUT ;
    USE SIGNAL ;
    PORT
      LAYER M4 ;
        RECT  0 19.056 0.192 19.08 ;
    END
  END o[160]
  PIN o[161]
    DIRECTION OUTPUT ;
    USE SIGNAL ;
    PORT
      LAYER M4 ;
        RECT  0 19.152 0.192 19.176 ;
    END
  END o[161]
  PIN o[162]
    DIRECTION OUTPUT ;
    USE SIGNAL ;
    PORT
      LAYER M4 ;
        RECT  0 19.296 0.192 19.32 ;
    END
  END o[162]
  PIN o[163]
    DIRECTION OUTPUT ;
    USE SIGNAL ;
    PORT
      LAYER M4 ;
        RECT  0 19.392 0.192 19.416 ;
    END
  END o[163]
  PIN o[164]
    DIRECTION OUTPUT ;
    USE SIGNAL ;
    PORT
      LAYER M4 ;
        RECT  0 19.488 0.192 19.512 ;
    END
  END o[164]
  PIN o[165]
    DIRECTION OUTPUT ;
    USE SIGNAL ;
    PORT
      LAYER M4 ;
        RECT  0 19.584 0.192 19.608 ;
    END
  END o[165]
  PIN o[166]
    DIRECTION OUTPUT ;
    USE SIGNAL ;
    PORT
      LAYER M4 ;
        RECT  0 19.68 0.192 19.704 ;
    END
  END o[166]
  PIN o[167]
    DIRECTION OUTPUT ;
    USE SIGNAL ;
    PORT
      LAYER M4 ;
        RECT  0 19.824 0.192 19.848 ;
    END
  END o[167]
  PIN o[168]
    DIRECTION OUTPUT ;
    USE SIGNAL ;
    PORT
      LAYER M4 ;
        RECT  0 19.92 0.192 19.944 ;
    END
  END o[168]
  PIN o[169]
    DIRECTION OUTPUT ;
    USE SIGNAL ;
    PORT
      LAYER M4 ;
        RECT  0 20.016 0.192 20.04 ;
    END
  END o[169]
  PIN o[16]
    DIRECTION OUTPUT ;
    USE SIGNAL ;
    PORT
      LAYER M4 ;
        RECT  0 3.888 0.192 3.912 ;
    END
  END o[16]
  PIN o[170]
    DIRECTION OUTPUT ;
    USE SIGNAL ;
    PORT
      LAYER M4 ;
        RECT  0 20.112 0.192 20.136 ;
    END
  END o[170]
  PIN o[171]
    DIRECTION OUTPUT ;
    USE SIGNAL ;
    PORT
      LAYER M4 ;
        RECT  0 20.208 0.192 20.232 ;
    END
  END o[171]
  PIN o[172]
    DIRECTION OUTPUT ;
    USE SIGNAL ;
    PORT
      LAYER M4 ;
        RECT  0 20.352 0.192 20.376 ;
    END
  END o[172]
  PIN o[173]
    DIRECTION OUTPUT ;
    USE SIGNAL ;
    PORT
      LAYER M4 ;
        RECT  0 20.448 0.192 20.472 ;
    END
  END o[173]
  PIN o[174]
    DIRECTION OUTPUT ;
    USE SIGNAL ;
    PORT
      LAYER M4 ;
        RECT  0 20.544 0.192 20.568 ;
    END
  END o[174]
  PIN o[175]
    DIRECTION OUTPUT ;
    USE SIGNAL ;
    PORT
      LAYER M4 ;
        RECT  0 20.64 0.192 20.664 ;
    END
  END o[175]
  PIN o[176]
    DIRECTION OUTPUT ;
    USE SIGNAL ;
    PORT
      LAYER M4 ;
        RECT  0 20.736 0.192 20.76 ;
    END
  END o[176]
  PIN o[177]
    DIRECTION OUTPUT ;
    USE SIGNAL ;
    PORT
      LAYER M4 ;
        RECT  0 20.88 0.192 20.904 ;
    END
  END o[177]
  PIN o[178]
    DIRECTION OUTPUT ;
    USE SIGNAL ;
    PORT
      LAYER M4 ;
        RECT  0 20.976 0.192 21 ;
    END
  END o[178]
  PIN o[179]
    DIRECTION OUTPUT ;
    USE SIGNAL ;
    PORT
      LAYER M4 ;
        RECT  0 21.072 0.192 21.096 ;
    END
  END o[179]
  PIN o[17]
    DIRECTION OUTPUT ;
    USE SIGNAL ;
    PORT
      LAYER M4 ;
        RECT  0 4.032 0.192 4.056 ;
    END
  END o[17]
  PIN o[180]
    DIRECTION OUTPUT ;
    USE SIGNAL ;
    PORT
      LAYER M4 ;
        RECT  0 21.168 0.192 21.192 ;
    END
  END o[180]
  PIN o[181]
    DIRECTION OUTPUT ;
    USE SIGNAL ;
    PORT
      LAYER M4 ;
        RECT  0 21.264 0.192 21.288 ;
    END
  END o[181]
  PIN o[182]
    DIRECTION OUTPUT ;
    USE SIGNAL ;
    PORT
      LAYER M4 ;
        RECT  0 21.36 0.192 21.384 ;
    END
  END o[182]
  PIN o[183]
    DIRECTION OUTPUT ;
    USE SIGNAL ;
    PORT
      LAYER M4 ;
        RECT  0 21.504 0.192 21.528 ;
    END
  END o[183]
  PIN o[184]
    DIRECTION OUTPUT ;
    USE SIGNAL ;
    PORT
      LAYER M4 ;
        RECT  0 21.6 0.192 21.624 ;
    END
  END o[184]
  PIN o[185]
    DIRECTION OUTPUT ;
    USE SIGNAL ;
    PORT
      LAYER M4 ;
        RECT  0 21.696 0.192 21.72 ;
    END
  END o[185]
  PIN o[186]
    DIRECTION OUTPUT ;
    USE SIGNAL ;
    PORT
      LAYER M4 ;
        RECT  0 21.792 0.192 21.816 ;
    END
  END o[186]
  PIN o[187]
    DIRECTION OUTPUT ;
    USE SIGNAL ;
    PORT
      LAYER M4 ;
        RECT  0 21.888 0.192 21.912 ;
    END
  END o[187]
  PIN o[188]
    DIRECTION OUTPUT ;
    USE SIGNAL ;
    PORT
      LAYER M4 ;
        RECT  0 22.032 0.192 22.056 ;
    END
  END o[188]
  PIN o[189]
    DIRECTION OUTPUT ;
    USE SIGNAL ;
    PORT
      LAYER M4 ;
        RECT  0 22.128 0.192 22.152 ;
    END
  END o[189]
  PIN o[18]
    DIRECTION OUTPUT ;
    USE SIGNAL ;
    PORT
      LAYER M4 ;
        RECT  0 4.128 0.192 4.152 ;
    END
  END o[18]
  PIN o[190]
    DIRECTION OUTPUT ;
    USE SIGNAL ;
    PORT
      LAYER M4 ;
        RECT  0 22.224 0.192 22.248 ;
    END
  END o[190]
  PIN o[191]
    DIRECTION OUTPUT ;
    USE SIGNAL ;
    PORT
      LAYER M4 ;
        RECT  0 22.32 0.192 22.344 ;
    END
  END o[191]
  PIN o[192]
    DIRECTION OUTPUT ;
    USE SIGNAL ;
    PORT
      LAYER M4 ;
        RECT  0 22.416 0.192 22.44 ;
    END
  END o[192]
  PIN o[193]
    DIRECTION OUTPUT ;
    USE SIGNAL ;
    PORT
      LAYER M4 ;
        RECT  0 22.56 0.192 22.584 ;
    END
  END o[193]
  PIN o[194]
    DIRECTION OUTPUT ;
    USE SIGNAL ;
    PORT
      LAYER M4 ;
        RECT  0 22.656 0.192 22.68 ;
    END
  END o[194]
  PIN o[195]
    DIRECTION OUTPUT ;
    USE SIGNAL ;
    PORT
      LAYER M4 ;
        RECT  0 22.752 0.192 22.776 ;
    END
  END o[195]
  PIN o[196]
    DIRECTION OUTPUT ;
    USE SIGNAL ;
    PORT
      LAYER M4 ;
        RECT  0 22.848 0.192 22.872 ;
    END
  END o[196]
  PIN o[197]
    DIRECTION OUTPUT ;
    USE SIGNAL ;
    PORT
      LAYER M4 ;
        RECT  0 22.944 0.192 22.968 ;
    END
  END o[197]
  PIN o[198]
    DIRECTION OUTPUT ;
    USE SIGNAL ;
    PORT
      LAYER M4 ;
        RECT  0 23.088 0.192 23.112 ;
    END
  END o[198]
  PIN o[199]
    DIRECTION OUTPUT ;
    USE SIGNAL ;
    PORT
      LAYER M4 ;
        RECT  0 23.184 0.192 23.208 ;
    END
  END o[199]
  PIN o[19]
    DIRECTION OUTPUT ;
    USE SIGNAL ;
    PORT
      LAYER M4 ;
        RECT  0 4.224 0.192 4.248 ;
    END
  END o[19]
  PIN o[1]
    DIRECTION OUTPUT ;
    USE SIGNAL ;
    PORT
      LAYER M4 ;
        RECT  0 2.352 0.192 2.376 ;
    END
  END o[1]
  PIN o[200]
    DIRECTION OUTPUT ;
    USE SIGNAL ;
    PORT
      LAYER M4 ;
        RECT  0 23.28 0.192 23.304 ;
    END
  END o[200]
  PIN o[201]
    DIRECTION OUTPUT ;
    USE SIGNAL ;
    PORT
      LAYER M4 ;
        RECT  0 23.376 0.192 23.4 ;
    END
  END o[201]
  PIN o[202]
    DIRECTION OUTPUT ;
    USE SIGNAL ;
    PORT
      LAYER M4 ;
        RECT  0 23.472 0.192 23.496 ;
    END
  END o[202]
  PIN o[203]
    DIRECTION OUTPUT ;
    USE SIGNAL ;
    PORT
      LAYER M4 ;
        RECT  0 23.616 0.192 23.64 ;
    END
  END o[203]
  PIN o[204]
    DIRECTION OUTPUT ;
    USE SIGNAL ;
    PORT
      LAYER M4 ;
        RECT  0 23.712 0.192 23.736 ;
    END
  END o[204]
  PIN o[205]
    DIRECTION OUTPUT ;
    USE SIGNAL ;
    PORT
      LAYER M4 ;
        RECT  0 23.808 0.192 23.832 ;
    END
  END o[205]
  PIN o[206]
    DIRECTION OUTPUT ;
    USE SIGNAL ;
    PORT
      LAYER M4 ;
        RECT  0 23.904 0.192 23.928 ;
    END
  END o[206]
  PIN o[207]
    DIRECTION OUTPUT ;
    USE SIGNAL ;
    PORT
      LAYER M4 ;
        RECT  0 24 0.192 24.024 ;
    END
  END o[207]
  PIN o[208]
    DIRECTION OUTPUT ;
    USE SIGNAL ;
    PORT
      LAYER M4 ;
        RECT  0 24.096 0.192 24.12 ;
    END
  END o[208]
  PIN o[209]
    DIRECTION OUTPUT ;
    USE SIGNAL ;
    PORT
      LAYER M4 ;
        RECT  0 24.24 0.192 24.264 ;
    END
  END o[209]
  PIN o[20]
    DIRECTION OUTPUT ;
    USE SIGNAL ;
    PORT
      LAYER M4 ;
        RECT  0 4.32 0.192 4.344 ;
    END
  END o[20]
  PIN o[210]
    DIRECTION OUTPUT ;
    USE SIGNAL ;
    PORT
      LAYER M4 ;
        RECT  0 24.336 0.192 24.36 ;
    END
  END o[210]
  PIN o[211]
    DIRECTION OUTPUT ;
    USE SIGNAL ;
    PORT
      LAYER M4 ;
        RECT  0 24.432 0.192 24.456 ;
    END
  END o[211]
  PIN o[212]
    DIRECTION OUTPUT ;
    USE SIGNAL ;
    PORT
      LAYER M4 ;
        RECT  0 24.528 0.192 24.552 ;
    END
  END o[212]
  PIN o[213]
    DIRECTION OUTPUT ;
    USE SIGNAL ;
    PORT
      LAYER M4 ;
        RECT  0 24.624 0.192 24.648 ;
    END
  END o[213]
  PIN o[214]
    DIRECTION OUTPUT ;
    USE SIGNAL ;
    PORT
      LAYER M4 ;
        RECT  0 24.768 0.192 24.792 ;
    END
  END o[214]
  PIN o[215]
    DIRECTION OUTPUT ;
    USE SIGNAL ;
    PORT
      LAYER M4 ;
        RECT  0 24.864 0.192 24.888 ;
    END
  END o[215]
  PIN o[216]
    DIRECTION OUTPUT ;
    USE SIGNAL ;
    PORT
      LAYER M4 ;
        RECT  0 24.96 0.192 24.984 ;
    END
  END o[216]
  PIN o[217]
    DIRECTION OUTPUT ;
    USE SIGNAL ;
    PORT
      LAYER M4 ;
        RECT  0 25.056 0.192 25.08 ;
    END
  END o[217]
  PIN o[218]
    DIRECTION OUTPUT ;
    USE SIGNAL ;
    PORT
      LAYER M4 ;
        RECT  0 25.152 0.192 25.176 ;
    END
  END o[218]
  PIN o[219]
    DIRECTION OUTPUT ;
    USE SIGNAL ;
    PORT
      LAYER M4 ;
        RECT  0 25.296 0.192 25.32 ;
    END
  END o[219]
  PIN o[21]
    DIRECTION OUTPUT ;
    USE SIGNAL ;
    PORT
      LAYER M4 ;
        RECT  0 4.416 0.192 4.44 ;
    END
  END o[21]
  PIN o[220]
    DIRECTION OUTPUT ;
    USE SIGNAL ;
    PORT
      LAYER M4 ;
        RECT  0 25.392 0.192 25.416 ;
    END
  END o[220]
  PIN o[221]
    DIRECTION OUTPUT ;
    USE SIGNAL ;
    PORT
      LAYER M4 ;
        RECT  0 25.488 0.192 25.512 ;
    END
  END o[221]
  PIN o[222]
    DIRECTION OUTPUT ;
    USE SIGNAL ;
    PORT
      LAYER M4 ;
        RECT  0 25.584 0.192 25.608 ;
    END
  END o[222]
  PIN o[223]
    DIRECTION OUTPUT ;
    USE SIGNAL ;
    PORT
      LAYER M4 ;
        RECT  0 25.68 0.192 25.704 ;
    END
  END o[223]
  PIN o[224]
    DIRECTION OUTPUT ;
    USE SIGNAL ;
    PORT
      LAYER M4 ;
        RECT  0 25.824 0.192 25.848 ;
    END
  END o[224]
  PIN o[225]
    DIRECTION OUTPUT ;
    USE SIGNAL ;
    PORT
      LAYER M4 ;
        RECT  0 25.92 0.192 25.944 ;
    END
  END o[225]
  PIN o[226]
    DIRECTION OUTPUT ;
    USE SIGNAL ;
    PORT
      LAYER M4 ;
        RECT  0 26.016 0.192 26.04 ;
    END
  END o[226]
  PIN o[227]
    DIRECTION OUTPUT ;
    USE SIGNAL ;
    PORT
      LAYER M4 ;
        RECT  0 26.112 0.192 26.136 ;
    END
  END o[227]
  PIN o[228]
    DIRECTION OUTPUT ;
    USE SIGNAL ;
    PORT
      LAYER M4 ;
        RECT  0 26.208 0.192 26.232 ;
    END
  END o[228]
  PIN o[229]
    DIRECTION OUTPUT ;
    USE SIGNAL ;
    PORT
      LAYER M4 ;
        RECT  0 26.352 0.192 26.376 ;
    END
  END o[229]
  PIN o[22]
    DIRECTION OUTPUT ;
    USE SIGNAL ;
    PORT
      LAYER M4 ;
        RECT  0 4.56 0.192 4.584 ;
    END
  END o[22]
  PIN o[230]
    DIRECTION OUTPUT ;
    USE SIGNAL ;
    PORT
      LAYER M4 ;
        RECT  0 26.448 0.192 26.472 ;
    END
  END o[230]
  PIN o[231]
    DIRECTION OUTPUT ;
    USE SIGNAL ;
    PORT
      LAYER M4 ;
        RECT  0 26.544 0.192 26.568 ;
    END
  END o[231]
  PIN o[232]
    DIRECTION OUTPUT ;
    USE SIGNAL ;
    PORT
      LAYER M4 ;
        RECT  0 26.64 0.192 26.664 ;
    END
  END o[232]
  PIN o[233]
    DIRECTION OUTPUT ;
    USE SIGNAL ;
    PORT
      LAYER M4 ;
        RECT  0 26.736 0.192 26.76 ;
    END
  END o[233]
  PIN o[234]
    DIRECTION OUTPUT ;
    USE SIGNAL ;
    PORT
      LAYER M4 ;
        RECT  0 26.88 0.192 26.904 ;
    END
  END o[234]
  PIN o[235]
    DIRECTION OUTPUT ;
    USE SIGNAL ;
    PORT
      LAYER M4 ;
        RECT  0 26.976 0.192 27 ;
    END
  END o[235]
  PIN o[236]
    DIRECTION OUTPUT ;
    USE SIGNAL ;
    PORT
      LAYER M4 ;
        RECT  0 27.072 0.192 27.096 ;
    END
  END o[236]
  PIN o[237]
    DIRECTION OUTPUT ;
    USE SIGNAL ;
    PORT
      LAYER M4 ;
        RECT  0 27.168 0.192 27.192 ;
    END
  END o[237]
  PIN o[238]
    DIRECTION OUTPUT ;
    USE SIGNAL ;
    PORT
      LAYER M4 ;
        RECT  0 27.264 0.192 27.288 ;
    END
  END o[238]
  PIN o[239]
    DIRECTION OUTPUT ;
    USE SIGNAL ;
    PORT
      LAYER M4 ;
        RECT  0 27.36 0.192 27.384 ;
    END
  END o[239]
  PIN o[23]
    DIRECTION OUTPUT ;
    USE SIGNAL ;
    PORT
      LAYER M4 ;
        RECT  0 4.656 0.192 4.68 ;
    END
  END o[23]
  PIN o[240]
    DIRECTION OUTPUT ;
    USE SIGNAL ;
    PORT
      LAYER M4 ;
        RECT  0 27.504 0.192 27.528 ;
    END
  END o[240]
  PIN o[241]
    DIRECTION OUTPUT ;
    USE SIGNAL ;
    PORT
      LAYER M4 ;
        RECT  0 27.6 0.192 27.624 ;
    END
  END o[241]
  PIN o[242]
    DIRECTION OUTPUT ;
    USE SIGNAL ;
    PORT
      LAYER M4 ;
        RECT  0 27.696 0.192 27.72 ;
    END
  END o[242]
  PIN o[243]
    DIRECTION OUTPUT ;
    USE SIGNAL ;
    PORT
      LAYER M4 ;
        RECT  0 27.792 0.192 27.816 ;
    END
  END o[243]
  PIN o[244]
    DIRECTION OUTPUT ;
    USE SIGNAL ;
    PORT
      LAYER M4 ;
        RECT  0 27.888 0.192 27.912 ;
    END
  END o[244]
  PIN o[245]
    DIRECTION OUTPUT ;
    USE SIGNAL ;
    PORT
      LAYER M4 ;
        RECT  0 28.032 0.192 28.056 ;
    END
  END o[245]
  PIN o[246]
    DIRECTION OUTPUT ;
    USE SIGNAL ;
    PORT
      LAYER M4 ;
        RECT  0 28.128 0.192 28.152 ;
    END
  END o[246]
  PIN o[247]
    DIRECTION OUTPUT ;
    USE SIGNAL ;
    PORT
      LAYER M4 ;
        RECT  0 28.224 0.192 28.248 ;
    END
  END o[247]
  PIN o[248]
    DIRECTION OUTPUT ;
    USE SIGNAL ;
    PORT
      LAYER M4 ;
        RECT  0 28.32 0.192 28.344 ;
    END
  END o[248]
  PIN o[249]
    DIRECTION OUTPUT ;
    USE SIGNAL ;
    PORT
      LAYER M4 ;
        RECT  0 28.416 0.192 28.44 ;
    END
  END o[249]
  PIN o[24]
    DIRECTION OUTPUT ;
    USE SIGNAL ;
    PORT
      LAYER M4 ;
        RECT  0 4.752 0.192 4.776 ;
    END
  END o[24]
  PIN o[250]
    DIRECTION OUTPUT ;
    USE SIGNAL ;
    PORT
      LAYER M4 ;
        RECT  0 28.56 0.192 28.584 ;
    END
  END o[250]
  PIN o[251]
    DIRECTION OUTPUT ;
    USE SIGNAL ;
    PORT
      LAYER M4 ;
        RECT  0 28.656 0.192 28.68 ;
    END
  END o[251]
  PIN o[252]
    DIRECTION OUTPUT ;
    USE SIGNAL ;
    PORT
      LAYER M4 ;
        RECT  0 28.752 0.192 28.776 ;
    END
  END o[252]
  PIN o[253]
    DIRECTION OUTPUT ;
    USE SIGNAL ;
    PORT
      LAYER M4 ;
        RECT  0 28.848 0.192 28.872 ;
    END
  END o[253]
  PIN o[254]
    DIRECTION OUTPUT ;
    USE SIGNAL ;
    PORT
      LAYER M4 ;
        RECT  0 28.944 0.192 28.968 ;
    END
  END o[254]
  PIN o[255]
    DIRECTION OUTPUT ;
    USE SIGNAL ;
    PORT
      LAYER M4 ;
        RECT  0 29.088 0.192 29.112 ;
    END
  END o[255]
  PIN o[256]
    DIRECTION OUTPUT ;
    USE SIGNAL ;
    PORT
      LAYER M4 ;
        RECT  0 29.184 0.192 29.208 ;
    END
  END o[256]
  PIN o[257]
    DIRECTION OUTPUT ;
    USE SIGNAL ;
    PORT
      LAYER M4 ;
        RECT  0 29.28 0.192 29.304 ;
    END
  END o[257]
  PIN o[258]
    DIRECTION OUTPUT ;
    USE SIGNAL ;
    PORT
      LAYER M4 ;
        RECT  0 29.376 0.192 29.4 ;
    END
  END o[258]
  PIN o[259]
    DIRECTION OUTPUT ;
    USE SIGNAL ;
    PORT
      LAYER M4 ;
        RECT  0 29.472 0.192 29.496 ;
    END
  END o[259]
  PIN o[25]
    DIRECTION OUTPUT ;
    USE SIGNAL ;
    PORT
      LAYER M4 ;
        RECT  0 4.848 0.192 4.872 ;
    END
  END o[25]
  PIN o[260]
    DIRECTION OUTPUT ;
    USE SIGNAL ;
    PORT
      LAYER M4 ;
        RECT  0 29.616 0.192 29.64 ;
    END
  END o[260]
  PIN o[261]
    DIRECTION OUTPUT ;
    USE SIGNAL ;
    PORT
      LAYER M4 ;
        RECT  0 29.712 0.192 29.736 ;
    END
  END o[261]
  PIN o[262]
    DIRECTION OUTPUT ;
    USE SIGNAL ;
    PORT
      LAYER M4 ;
        RECT  0 29.808 0.192 29.832 ;
    END
  END o[262]
  PIN o[263]
    DIRECTION OUTPUT ;
    USE SIGNAL ;
    PORT
      LAYER M4 ;
        RECT  0 29.904 0.192 29.928 ;
    END
  END o[263]
  PIN o[264]
    DIRECTION OUTPUT ;
    USE SIGNAL ;
    PORT
      LAYER M4 ;
        RECT  0 30 0.192 30.024 ;
    END
  END o[264]
  PIN o[265]
    DIRECTION OUTPUT ;
    USE SIGNAL ;
    PORT
      LAYER M4 ;
        RECT  0 30.096 0.192 30.12 ;
    END
  END o[265]
  PIN o[266]
    DIRECTION OUTPUT ;
    USE SIGNAL ;
    PORT
      LAYER M4 ;
        RECT  0 30.24 0.192 30.264 ;
    END
  END o[266]
  PIN o[267]
    DIRECTION OUTPUT ;
    USE SIGNAL ;
    PORT
      LAYER M4 ;
        RECT  0 30.336 0.192 30.36 ;
    END
  END o[267]
  PIN o[268]
    DIRECTION OUTPUT ;
    USE SIGNAL ;
    PORT
      LAYER M4 ;
        RECT  0 30.432 0.192 30.456 ;
    END
  END o[268]
  PIN o[269]
    DIRECTION OUTPUT ;
    USE SIGNAL ;
    PORT
      LAYER M4 ;
        RECT  0 30.528 0.192 30.552 ;
    END
  END o[269]
  PIN o[26]
    DIRECTION OUTPUT ;
    USE SIGNAL ;
    PORT
      LAYER M4 ;
        RECT  0 4.944 0.192 4.968 ;
    END
  END o[26]
  PIN o[270]
    DIRECTION OUTPUT ;
    USE SIGNAL ;
    PORT
      LAYER M4 ;
        RECT  0 30.624 0.192 30.648 ;
    END
  END o[270]
  PIN o[271]
    DIRECTION OUTPUT ;
    USE SIGNAL ;
    PORT
      LAYER M4 ;
        RECT  0 30.768 0.192 30.792 ;
    END
  END o[271]
  PIN o[272]
    DIRECTION OUTPUT ;
    USE SIGNAL ;
    PORT
      LAYER M4 ;
        RECT  0 30.864 0.192 30.888 ;
    END
  END o[272]
  PIN o[273]
    DIRECTION OUTPUT ;
    USE SIGNAL ;
    PORT
      LAYER M4 ;
        RECT  0 30.96 0.192 30.984 ;
    END
  END o[273]
  PIN o[274]
    DIRECTION OUTPUT ;
    USE SIGNAL ;
    PORT
      LAYER M4 ;
        RECT  0 31.056 0.192 31.08 ;
    END
  END o[274]
  PIN o[275]
    DIRECTION OUTPUT ;
    USE SIGNAL ;
    PORT
      LAYER M4 ;
        RECT  0 31.152 0.192 31.176 ;
    END
  END o[275]
  PIN o[276]
    DIRECTION OUTPUT ;
    USE SIGNAL ;
    PORT
      LAYER M4 ;
        RECT  0 31.296 0.192 31.32 ;
    END
  END o[276]
  PIN o[277]
    DIRECTION OUTPUT ;
    USE SIGNAL ;
    PORT
      LAYER M4 ;
        RECT  0 31.392 0.192 31.416 ;
    END
  END o[277]
  PIN o[278]
    DIRECTION OUTPUT ;
    USE SIGNAL ;
    PORT
      LAYER M4 ;
        RECT  0 31.488 0.192 31.512 ;
    END
  END o[278]
  PIN o[279]
    DIRECTION OUTPUT ;
    USE SIGNAL ;
    PORT
      LAYER M4 ;
        RECT  0 31.584 0.192 31.608 ;
    END
  END o[279]
  PIN o[27]
    DIRECTION OUTPUT ;
    USE SIGNAL ;
    PORT
      LAYER M4 ;
        RECT  0 5.088 0.192 5.112 ;
    END
  END o[27]
  PIN o[280]
    DIRECTION OUTPUT ;
    USE SIGNAL ;
    PORT
      LAYER M4 ;
        RECT  0 31.68 0.192 31.704 ;
    END
  END o[280]
  PIN o[281]
    DIRECTION OUTPUT ;
    USE SIGNAL ;
    PORT
      LAYER M4 ;
        RECT  0 31.824 0.192 31.848 ;
    END
  END o[281]
  PIN o[282]
    DIRECTION OUTPUT ;
    USE SIGNAL ;
    PORT
      LAYER M4 ;
        RECT  0 31.92 0.192 31.944 ;
    END
  END o[282]
  PIN o[283]
    DIRECTION OUTPUT ;
    USE SIGNAL ;
    PORT
      LAYER M4 ;
        RECT  0 32.016 0.192 32.04 ;
    END
  END o[283]
  PIN o[284]
    DIRECTION OUTPUT ;
    USE SIGNAL ;
    PORT
      LAYER M4 ;
        RECT  0 32.112 0.192 32.136 ;
    END
  END o[284]
  PIN o[285]
    DIRECTION OUTPUT ;
    USE SIGNAL ;
    PORT
      LAYER M4 ;
        RECT  0 32.208 0.192 32.232 ;
    END
  END o[285]
  PIN o[286]
    DIRECTION OUTPUT ;
    USE SIGNAL ;
    PORT
      LAYER M4 ;
        RECT  0 32.352 0.192 32.376 ;
    END
  END o[286]
  PIN o[287]
    DIRECTION OUTPUT ;
    USE SIGNAL ;
    PORT
      LAYER M4 ;
        RECT  0 32.448 0.192 32.472 ;
    END
  END o[287]
  PIN o[288]
    DIRECTION OUTPUT ;
    USE SIGNAL ;
    PORT
      LAYER M4 ;
        RECT  0 32.544 0.192 32.568 ;
    END
  END o[288]
  PIN o[289]
    DIRECTION OUTPUT ;
    USE SIGNAL ;
    PORT
      LAYER M4 ;
        RECT  0 32.64 0.192 32.664 ;
    END
  END o[289]
  PIN o[28]
    DIRECTION OUTPUT ;
    USE SIGNAL ;
    PORT
      LAYER M4 ;
        RECT  0 5.184 0.192 5.208 ;
    END
  END o[28]
  PIN o[290]
    DIRECTION OUTPUT ;
    USE SIGNAL ;
    PORT
      LAYER M4 ;
        RECT  0 32.736 0.192 32.76 ;
    END
  END o[290]
  PIN o[291]
    DIRECTION OUTPUT ;
    USE SIGNAL ;
    PORT
      LAYER M4 ;
        RECT  0 32.88 0.192 32.904 ;
    END
  END o[291]
  PIN o[292]
    DIRECTION OUTPUT ;
    USE SIGNAL ;
    PORT
      LAYER M4 ;
        RECT  0 32.976 0.192 33 ;
    END
  END o[292]
  PIN o[293]
    DIRECTION OUTPUT ;
    USE SIGNAL ;
    PORT
      LAYER M4 ;
        RECT  0 33.072 0.192 33.096 ;
    END
  END o[293]
  PIN o[294]
    DIRECTION OUTPUT ;
    USE SIGNAL ;
    PORT
      LAYER M4 ;
        RECT  0 33.168 0.192 33.192 ;
    END
  END o[294]
  PIN o[295]
    DIRECTION OUTPUT ;
    USE SIGNAL ;
    PORT
      LAYER M4 ;
        RECT  0 33.264 0.192 33.288 ;
    END
  END o[295]
  PIN o[296]
    DIRECTION OUTPUT ;
    USE SIGNAL ;
    PORT
      LAYER M4 ;
        RECT  0 33.36 0.192 33.384 ;
    END
  END o[296]
  PIN o[297]
    DIRECTION OUTPUT ;
    USE SIGNAL ;
    PORT
      LAYER M4 ;
        RECT  0 33.504 0.192 33.528 ;
    END
  END o[297]
  PIN o[298]
    DIRECTION OUTPUT ;
    USE SIGNAL ;
    PORT
      LAYER M4 ;
        RECT  0 33.6 0.192 33.624 ;
    END
  END o[298]
  PIN o[299]
    DIRECTION OUTPUT ;
    USE SIGNAL ;
    PORT
      LAYER M4 ;
        RECT  0 33.696 0.192 33.72 ;
    END
  END o[299]
  PIN o[29]
    DIRECTION OUTPUT ;
    USE SIGNAL ;
    PORT
      LAYER M4 ;
        RECT  0 5.28 0.192 5.304 ;
    END
  END o[29]
  PIN o[2]
    DIRECTION OUTPUT ;
    USE SIGNAL ;
    PORT
      LAYER M4 ;
        RECT  0 2.448 0.192 2.472 ;
    END
  END o[2]
  PIN o[300]
    DIRECTION OUTPUT ;
    USE SIGNAL ;
    PORT
      LAYER M4 ;
        RECT  0 33.792 0.192 33.816 ;
    END
  END o[300]
  PIN o[301]
    DIRECTION OUTPUT ;
    USE SIGNAL ;
    PORT
      LAYER M4 ;
        RECT  0 33.888 0.192 33.912 ;
    END
  END o[301]
  PIN o[302]
    DIRECTION OUTPUT ;
    USE SIGNAL ;
    PORT
      LAYER M4 ;
        RECT  0 34.032 0.192 34.056 ;
    END
  END o[302]
  PIN o[303]
    DIRECTION OUTPUT ;
    USE SIGNAL ;
    PORT
      LAYER M4 ;
        RECT  0 34.128 0.192 34.152 ;
    END
  END o[303]
  PIN o[304]
    DIRECTION OUTPUT ;
    USE SIGNAL ;
    PORT
      LAYER M4 ;
        RECT  0 34.224 0.192 34.248 ;
    END
  END o[304]
  PIN o[305]
    DIRECTION OUTPUT ;
    USE SIGNAL ;
    PORT
      LAYER M4 ;
        RECT  0 34.32 0.192 34.344 ;
    END
  END o[305]
  PIN o[306]
    DIRECTION OUTPUT ;
    USE SIGNAL ;
    PORT
      LAYER M4 ;
        RECT  0 34.416 0.192 34.44 ;
    END
  END o[306]
  PIN o[307]
    DIRECTION OUTPUT ;
    USE SIGNAL ;
    PORT
      LAYER M4 ;
        RECT  0 34.56 0.192 34.584 ;
    END
  END o[307]
  PIN o[308]
    DIRECTION OUTPUT ;
    USE SIGNAL ;
    PORT
      LAYER M4 ;
        RECT  0 34.656 0.192 34.68 ;
    END
  END o[308]
  PIN o[309]
    DIRECTION OUTPUT ;
    USE SIGNAL ;
    PORT
      LAYER M4 ;
        RECT  0 34.752 0.192 34.776 ;
    END
  END o[309]
  PIN o[30]
    DIRECTION OUTPUT ;
    USE SIGNAL ;
    PORT
      LAYER M4 ;
        RECT  0 5.376 0.192 5.4 ;
    END
  END o[30]
  PIN o[310]
    DIRECTION OUTPUT ;
    USE SIGNAL ;
    PORT
      LAYER M4 ;
        RECT  0 34.848 0.192 34.872 ;
    END
  END o[310]
  PIN o[311]
    DIRECTION OUTPUT ;
    USE SIGNAL ;
    PORT
      LAYER M4 ;
        RECT  0 34.944 0.192 34.968 ;
    END
  END o[311]
  PIN o[312]
    DIRECTION OUTPUT ;
    USE SIGNAL ;
    PORT
      LAYER M4 ;
        RECT  0 35.088 0.192 35.112 ;
    END
  END o[312]
  PIN o[313]
    DIRECTION OUTPUT ;
    USE SIGNAL ;
    PORT
      LAYER M4 ;
        RECT  0 35.184 0.192 35.208 ;
    END
  END o[313]
  PIN o[314]
    DIRECTION OUTPUT ;
    USE SIGNAL ;
    PORT
      LAYER M4 ;
        RECT  0 35.28 0.192 35.304 ;
    END
  END o[314]
  PIN o[315]
    DIRECTION OUTPUT ;
    USE SIGNAL ;
    PORT
      LAYER M4 ;
        RECT  0 35.376 0.192 35.4 ;
    END
  END o[315]
  PIN o[316]
    DIRECTION OUTPUT ;
    USE SIGNAL ;
    PORT
      LAYER M4 ;
        RECT  0 35.472 0.192 35.496 ;
    END
  END o[316]
  PIN o[317]
    DIRECTION OUTPUT ;
    USE SIGNAL ;
    PORT
      LAYER M4 ;
        RECT  0 35.616 0.192 35.64 ;
    END
  END o[317]
  PIN o[318]
    DIRECTION OUTPUT ;
    USE SIGNAL ;
    PORT
      LAYER M4 ;
        RECT  0 35.712 0.192 35.736 ;
    END
  END o[318]
  PIN o[319]
    DIRECTION OUTPUT ;
    USE SIGNAL ;
    PORT
      LAYER M4 ;
        RECT  0 35.808 0.192 35.832 ;
    END
  END o[319]
  PIN o[31]
    DIRECTION OUTPUT ;
    USE SIGNAL ;
    PORT
      LAYER M4 ;
        RECT  0 5.472 0.192 5.496 ;
    END
  END o[31]
  PIN o[320]
    DIRECTION OUTPUT ;
    USE SIGNAL ;
    PORT
      LAYER M4 ;
        RECT  0 35.904 0.192 35.928 ;
    END
  END o[320]
  PIN o[321]
    DIRECTION OUTPUT ;
    USE SIGNAL ;
    PORT
      LAYER M4 ;
        RECT  0 36 0.192 36.024 ;
    END
  END o[321]
  PIN o[322]
    DIRECTION OUTPUT ;
    USE SIGNAL ;
    PORT
      LAYER M4 ;
        RECT  0 36.096 0.192 36.12 ;
    END
  END o[322]
  PIN o[323]
    DIRECTION OUTPUT ;
    USE SIGNAL ;
    PORT
      LAYER M4 ;
        RECT  0 36.24 0.192 36.264 ;
    END
  END o[323]
  PIN o[324]
    DIRECTION OUTPUT ;
    USE SIGNAL ;
    PORT
      LAYER M4 ;
        RECT  0 36.336 0.192 36.36 ;
    END
  END o[324]
  PIN o[325]
    DIRECTION OUTPUT ;
    USE SIGNAL ;
    PORT
      LAYER M4 ;
        RECT  0 36.432 0.192 36.456 ;
    END
  END o[325]
  PIN o[326]
    DIRECTION OUTPUT ;
    USE SIGNAL ;
    PORT
      LAYER M4 ;
        RECT  0 36.528 0.192 36.552 ;
    END
  END o[326]
  PIN o[327]
    DIRECTION OUTPUT ;
    USE SIGNAL ;
    PORT
      LAYER M4 ;
        RECT  0 36.624 0.192 36.648 ;
    END
  END o[327]
  PIN o[328]
    DIRECTION OUTPUT ;
    USE SIGNAL ;
    PORT
      LAYER M4 ;
        RECT  0 36.768 0.192 36.792 ;
    END
  END o[328]
  PIN o[329]
    DIRECTION OUTPUT ;
    USE SIGNAL ;
    PORT
      LAYER M4 ;
        RECT  0 36.864 0.192 36.888 ;
    END
  END o[329]
  PIN o[32]
    DIRECTION OUTPUT ;
    USE SIGNAL ;
    PORT
      LAYER M4 ;
        RECT  0 5.616 0.192 5.64 ;
    END
  END o[32]
  PIN o[330]
    DIRECTION OUTPUT ;
    USE SIGNAL ;
    PORT
      LAYER M4 ;
        RECT  0 36.96 0.192 36.984 ;
    END
  END o[330]
  PIN o[331]
    DIRECTION OUTPUT ;
    USE SIGNAL ;
    PORT
      LAYER M4 ;
        RECT  0 37.056 0.192 37.08 ;
    END
  END o[331]
  PIN o[332]
    DIRECTION OUTPUT ;
    USE SIGNAL ;
    PORT
      LAYER M4 ;
        RECT  0 37.152 0.192 37.176 ;
    END
  END o[332]
  PIN o[333]
    DIRECTION OUTPUT ;
    USE SIGNAL ;
    PORT
      LAYER M4 ;
        RECT  0 37.296 0.192 37.32 ;
    END
  END o[333]
  PIN o[334]
    DIRECTION OUTPUT ;
    USE SIGNAL ;
    PORT
      LAYER M4 ;
        RECT  0 37.392 0.192 37.416 ;
    END
  END o[334]
  PIN o[335]
    DIRECTION OUTPUT ;
    USE SIGNAL ;
    PORT
      LAYER M4 ;
        RECT  0 37.488 0.192 37.512 ;
    END
  END o[335]
  PIN o[336]
    DIRECTION OUTPUT ;
    USE SIGNAL ;
    PORT
      LAYER M4 ;
        RECT  0 37.584 0.192 37.608 ;
    END
  END o[336]
  PIN o[337]
    DIRECTION OUTPUT ;
    USE SIGNAL ;
    PORT
      LAYER M4 ;
        RECT  0 37.68 0.192 37.704 ;
    END
  END o[337]
  PIN o[338]
    DIRECTION OUTPUT ;
    USE SIGNAL ;
    PORT
      LAYER M4 ;
        RECT  0 37.824 0.192 37.848 ;
    END
  END o[338]
  PIN o[339]
    DIRECTION OUTPUT ;
    USE SIGNAL ;
    PORT
      LAYER M4 ;
        RECT  0 37.92 0.192 37.944 ;
    END
  END o[339]
  PIN o[33]
    DIRECTION OUTPUT ;
    USE SIGNAL ;
    PORT
      LAYER M4 ;
        RECT  0 5.712 0.192 5.736 ;
    END
  END o[33]
  PIN o[340]
    DIRECTION OUTPUT ;
    USE SIGNAL ;
    PORT
      LAYER M4 ;
        RECT  0 38.016 0.192 38.04 ;
    END
  END o[340]
  PIN o[341]
    DIRECTION OUTPUT ;
    USE SIGNAL ;
    PORT
      LAYER M4 ;
        RECT  0 38.112 0.192 38.136 ;
    END
  END o[341]
  PIN o[342]
    DIRECTION OUTPUT ;
    USE SIGNAL ;
    PORT
      LAYER M4 ;
        RECT  0 38.208 0.192 38.232 ;
    END
  END o[342]
  PIN o[343]
    DIRECTION OUTPUT ;
    USE SIGNAL ;
    PORT
      LAYER M4 ;
        RECT  0 38.352 0.192 38.376 ;
    END
  END o[343]
  PIN o[344]
    DIRECTION OUTPUT ;
    USE SIGNAL ;
    PORT
      LAYER M4 ;
        RECT  0 38.448 0.192 38.472 ;
    END
  END o[344]
  PIN o[345]
    DIRECTION OUTPUT ;
    USE SIGNAL ;
    PORT
      LAYER M4 ;
        RECT  0 38.544 0.192 38.568 ;
    END
  END o[345]
  PIN o[346]
    DIRECTION OUTPUT ;
    USE SIGNAL ;
    PORT
      LAYER M4 ;
        RECT  0 38.64 0.192 38.664 ;
    END
  END o[346]
  PIN o[347]
    DIRECTION OUTPUT ;
    USE SIGNAL ;
    PORT
      LAYER M4 ;
        RECT  0 38.736 0.192 38.76 ;
    END
  END o[347]
  PIN o[348]
    DIRECTION OUTPUT ;
    USE SIGNAL ;
    PORT
      LAYER M4 ;
        RECT  0 38.88 0.192 38.904 ;
    END
  END o[348]
  PIN o[349]
    DIRECTION OUTPUT ;
    USE SIGNAL ;
    PORT
      LAYER M4 ;
        RECT  0 38.976 0.192 39 ;
    END
  END o[349]
  PIN o[34]
    DIRECTION OUTPUT ;
    USE SIGNAL ;
    PORT
      LAYER M4 ;
        RECT  0 5.808 0.192 5.832 ;
    END
  END o[34]
  PIN o[350]
    DIRECTION OUTPUT ;
    USE SIGNAL ;
    PORT
      LAYER M4 ;
        RECT  0 39.072 0.192 39.096 ;
    END
  END o[350]
  PIN o[351]
    DIRECTION OUTPUT ;
    USE SIGNAL ;
    PORT
      LAYER M4 ;
        RECT  0 39.168 0.192 39.192 ;
    END
  END o[351]
  PIN o[352]
    DIRECTION OUTPUT ;
    USE SIGNAL ;
    PORT
      LAYER M4 ;
        RECT  0 39.264 0.192 39.288 ;
    END
  END o[352]
  PIN o[353]
    DIRECTION OUTPUT ;
    USE SIGNAL ;
    PORT
      LAYER M4 ;
        RECT  0 39.36 0.192 39.384 ;
    END
  END o[353]
  PIN o[354]
    DIRECTION OUTPUT ;
    USE SIGNAL ;
    PORT
      LAYER M4 ;
        RECT  0 39.504 0.192 39.528 ;
    END
  END o[354]
  PIN o[355]
    DIRECTION OUTPUT ;
    USE SIGNAL ;
    PORT
      LAYER M4 ;
        RECT  0 39.6 0.192 39.624 ;
    END
  END o[355]
  PIN o[356]
    DIRECTION OUTPUT ;
    USE SIGNAL ;
    PORT
      LAYER M4 ;
        RECT  0 39.696 0.192 39.72 ;
    END
  END o[356]
  PIN o[357]
    DIRECTION OUTPUT ;
    USE SIGNAL ;
    PORT
      LAYER M4 ;
        RECT  0 39.792 0.192 39.816 ;
    END
  END o[357]
  PIN o[358]
    DIRECTION OUTPUT ;
    USE SIGNAL ;
    PORT
      LAYER M4 ;
        RECT  0 39.888 0.192 39.912 ;
    END
  END o[358]
  PIN o[359]
    DIRECTION OUTPUT ;
    USE SIGNAL ;
    PORT
      LAYER M4 ;
        RECT  0 40.032 0.192 40.056 ;
    END
  END o[359]
  PIN o[35]
    DIRECTION OUTPUT ;
    USE SIGNAL ;
    PORT
      LAYER M4 ;
        RECT  0 5.904 0.192 5.928 ;
    END
  END o[35]
  PIN o[360]
    DIRECTION OUTPUT ;
    USE SIGNAL ;
    PORT
      LAYER M4 ;
        RECT  0 40.128 0.192 40.152 ;
    END
  END o[360]
  PIN o[361]
    DIRECTION OUTPUT ;
    USE SIGNAL ;
    PORT
      LAYER M4 ;
        RECT  0 40.224 0.192 40.248 ;
    END
  END o[361]
  PIN o[362]
    DIRECTION OUTPUT ;
    USE SIGNAL ;
    PORT
      LAYER M4 ;
        RECT  0 40.32 0.192 40.344 ;
    END
  END o[362]
  PIN o[363]
    DIRECTION OUTPUT ;
    USE SIGNAL ;
    PORT
      LAYER M4 ;
        RECT  0 40.416 0.192 40.44 ;
    END
  END o[363]
  PIN o[364]
    DIRECTION OUTPUT ;
    USE SIGNAL ;
    PORT
      LAYER M4 ;
        RECT  0 40.56 0.192 40.584 ;
    END
  END o[364]
  PIN o[365]
    DIRECTION OUTPUT ;
    USE SIGNAL ;
    PORT
      LAYER M4 ;
        RECT  0 40.656 0.192 40.68 ;
    END
  END o[365]
  PIN o[366]
    DIRECTION OUTPUT ;
    USE SIGNAL ;
    PORT
      LAYER M4 ;
        RECT  0 40.752 0.192 40.776 ;
    END
  END o[366]
  PIN o[367]
    DIRECTION OUTPUT ;
    USE SIGNAL ;
    PORT
      LAYER M4 ;
        RECT  0 40.848 0.192 40.872 ;
    END
  END o[367]
  PIN o[368]
    DIRECTION OUTPUT ;
    USE SIGNAL ;
    PORT
      LAYER M4 ;
        RECT  0 40.944 0.192 40.968 ;
    END
  END o[368]
  PIN o[369]
    DIRECTION OUTPUT ;
    USE SIGNAL ;
    PORT
      LAYER M4 ;
        RECT  0 41.088 0.192 41.112 ;
    END
  END o[369]
  PIN o[36]
    DIRECTION OUTPUT ;
    USE SIGNAL ;
    PORT
      LAYER M4 ;
        RECT  0 6 0.192 6.024 ;
    END
  END o[36]
  PIN o[370]
    DIRECTION OUTPUT ;
    USE SIGNAL ;
    PORT
      LAYER M4 ;
        RECT  0 41.184 0.192 41.208 ;
    END
  END o[370]
  PIN o[371]
    DIRECTION OUTPUT ;
    USE SIGNAL ;
    PORT
      LAYER M4 ;
        RECT  0 41.28 0.192 41.304 ;
    END
  END o[371]
  PIN o[372]
    DIRECTION OUTPUT ;
    USE SIGNAL ;
    PORT
      LAYER M4 ;
        RECT  0 41.376 0.192 41.4 ;
    END
  END o[372]
  PIN o[373]
    DIRECTION OUTPUT ;
    USE SIGNAL ;
    PORT
      LAYER M4 ;
        RECT  0 41.472 0.192 41.496 ;
    END
  END o[373]
  PIN o[374]
    DIRECTION OUTPUT ;
    USE SIGNAL ;
    PORT
      LAYER M4 ;
        RECT  0 41.616 0.192 41.64 ;
    END
  END o[374]
  PIN o[375]
    DIRECTION OUTPUT ;
    USE SIGNAL ;
    PORT
      LAYER M4 ;
        RECT  0 41.712 0.192 41.736 ;
    END
  END o[375]
  PIN o[376]
    DIRECTION OUTPUT ;
    USE SIGNAL ;
    PORT
      LAYER M4 ;
        RECT  0 41.808 0.192 41.832 ;
    END
  END o[376]
  PIN o[377]
    DIRECTION OUTPUT ;
    USE SIGNAL ;
    PORT
      LAYER M4 ;
        RECT  0 41.904 0.192 41.928 ;
    END
  END o[377]
  PIN o[378]
    DIRECTION OUTPUT ;
    USE SIGNAL ;
    PORT
      LAYER M4 ;
        RECT  0 42 0.192 42.024 ;
    END
  END o[378]
  PIN o[379]
    DIRECTION OUTPUT ;
    USE SIGNAL ;
    PORT
      LAYER M4 ;
        RECT  0 42.096 0.192 42.12 ;
    END
  END o[379]
  PIN o[37]
    DIRECTION OUTPUT ;
    USE SIGNAL ;
    PORT
      LAYER M4 ;
        RECT  0 6.096 0.192 6.12 ;
    END
  END o[37]
  PIN o[380]
    DIRECTION OUTPUT ;
    USE SIGNAL ;
    PORT
      LAYER M4 ;
        RECT  0 42.24 0.192 42.264 ;
    END
  END o[380]
  PIN o[381]
    DIRECTION OUTPUT ;
    USE SIGNAL ;
    PORT
      LAYER M4 ;
        RECT  0 42.336 0.192 42.36 ;
    END
  END o[381]
  PIN o[382]
    DIRECTION OUTPUT ;
    USE SIGNAL ;
    PORT
      LAYER M4 ;
        RECT  0 42.432 0.192 42.456 ;
    END
  END o[382]
  PIN o[383]
    DIRECTION OUTPUT ;
    USE SIGNAL ;
    PORT
      LAYER M4 ;
        RECT  0 42.528 0.192 42.552 ;
    END
  END o[383]
  PIN o[384]
    DIRECTION OUTPUT ;
    USE SIGNAL ;
    PORT
      LAYER M4 ;
        RECT  0 42.624 0.192 42.648 ;
    END
  END o[384]
  PIN o[385]
    DIRECTION OUTPUT ;
    USE SIGNAL ;
    PORT
      LAYER M4 ;
        RECT  0 42.768 0.192 42.792 ;
    END
  END o[385]
  PIN o[386]
    DIRECTION OUTPUT ;
    USE SIGNAL ;
    PORT
      LAYER M4 ;
        RECT  0 42.864 0.192 42.888 ;
    END
  END o[386]
  PIN o[387]
    DIRECTION OUTPUT ;
    USE SIGNAL ;
    PORT
      LAYER M4 ;
        RECT  0 42.96 0.192 42.984 ;
    END
  END o[387]
  PIN o[388]
    DIRECTION OUTPUT ;
    USE SIGNAL ;
    PORT
      LAYER M4 ;
        RECT  0 43.056 0.192 43.08 ;
    END
  END o[388]
  PIN o[389]
    DIRECTION OUTPUT ;
    USE SIGNAL ;
    PORT
      LAYER M4 ;
        RECT  0 43.152 0.192 43.176 ;
    END
  END o[389]
  PIN o[38]
    DIRECTION OUTPUT ;
    USE SIGNAL ;
    PORT
      LAYER M4 ;
        RECT  0 6.24 0.192 6.264 ;
    END
  END o[38]
  PIN o[390]
    DIRECTION OUTPUT ;
    USE SIGNAL ;
    PORT
      LAYER M4 ;
        RECT  0 43.296 0.192 43.32 ;
    END
  END o[390]
  PIN o[391]
    DIRECTION OUTPUT ;
    USE SIGNAL ;
    PORT
      LAYER M4 ;
        RECT  0 43.392 0.192 43.416 ;
    END
  END o[391]
  PIN o[392]
    DIRECTION OUTPUT ;
    USE SIGNAL ;
    PORT
      LAYER M4 ;
        RECT  0 43.488 0.192 43.512 ;
    END
  END o[392]
  PIN o[393]
    DIRECTION OUTPUT ;
    USE SIGNAL ;
    PORT
      LAYER M4 ;
        RECT  0 43.584 0.192 43.608 ;
    END
  END o[393]
  PIN o[394]
    DIRECTION OUTPUT ;
    USE SIGNAL ;
    PORT
      LAYER M4 ;
        RECT  0 43.68 0.192 43.704 ;
    END
  END o[394]
  PIN o[395]
    DIRECTION OUTPUT ;
    USE SIGNAL ;
    PORT
      LAYER M4 ;
        RECT  0 43.824 0.192 43.848 ;
    END
  END o[395]
  PIN o[396]
    DIRECTION OUTPUT ;
    USE SIGNAL ;
    PORT
      LAYER M4 ;
        RECT  0 43.92 0.192 43.944 ;
    END
  END o[396]
  PIN o[397]
    DIRECTION OUTPUT ;
    USE SIGNAL ;
    PORT
      LAYER M4 ;
        RECT  0 44.016 0.192 44.04 ;
    END
  END o[397]
  PIN o[398]
    DIRECTION OUTPUT ;
    USE SIGNAL ;
    PORT
      LAYER M4 ;
        RECT  0 44.112 0.192 44.136 ;
    END
  END o[398]
  PIN o[399]
    DIRECTION OUTPUT ;
    USE SIGNAL ;
    PORT
      LAYER M4 ;
        RECT  0 44.208 0.192 44.232 ;
    END
  END o[399]
  PIN o[39]
    DIRECTION OUTPUT ;
    USE SIGNAL ;
    PORT
      LAYER M4 ;
        RECT  0 6.336 0.192 6.36 ;
    END
  END o[39]
  PIN o[3]
    DIRECTION OUTPUT ;
    USE SIGNAL ;
    PORT
      LAYER M4 ;
        RECT  0 2.544 0.192 2.568 ;
    END
  END o[3]
  PIN o[400]
    DIRECTION OUTPUT ;
    USE SIGNAL ;
    PORT
      LAYER M4 ;
        RECT  0 44.352 0.192 44.376 ;
    END
  END o[400]
  PIN o[401]
    DIRECTION OUTPUT ;
    USE SIGNAL ;
    PORT
      LAYER M4 ;
        RECT  0 44.448 0.192 44.472 ;
    END
  END o[401]
  PIN o[402]
    DIRECTION OUTPUT ;
    USE SIGNAL ;
    PORT
      LAYER M4 ;
        RECT  0 44.544 0.192 44.568 ;
    END
  END o[402]
  PIN o[403]
    DIRECTION OUTPUT ;
    USE SIGNAL ;
    PORT
      LAYER M4 ;
        RECT  0 44.64 0.192 44.664 ;
    END
  END o[403]
  PIN o[404]
    DIRECTION OUTPUT ;
    USE SIGNAL ;
    PORT
      LAYER M4 ;
        RECT  0 44.736 0.192 44.76 ;
    END
  END o[404]
  PIN o[405]
    DIRECTION OUTPUT ;
    USE SIGNAL ;
    PORT
      LAYER M4 ;
        RECT  0 44.88 0.192 44.904 ;
    END
  END o[405]
  PIN o[406]
    DIRECTION OUTPUT ;
    USE SIGNAL ;
    PORT
      LAYER M4 ;
        RECT  0 44.976 0.192 45 ;
    END
  END o[406]
  PIN o[407]
    DIRECTION OUTPUT ;
    USE SIGNAL ;
    PORT
      LAYER M4 ;
        RECT  0 45.072 0.192 45.096 ;
    END
  END o[407]
  PIN o[408]
    DIRECTION OUTPUT ;
    USE SIGNAL ;
    PORT
      LAYER M4 ;
        RECT  0 45.168 0.192 45.192 ;
    END
  END o[408]
  PIN o[409]
    DIRECTION OUTPUT ;
    USE SIGNAL ;
    PORT
      LAYER M4 ;
        RECT  0 45.264 0.192 45.288 ;
    END
  END o[409]
  PIN o[40]
    DIRECTION OUTPUT ;
    USE SIGNAL ;
    PORT
      LAYER M4 ;
        RECT  0 6.432 0.192 6.456 ;
    END
  END o[40]
  PIN o[410]
    DIRECTION OUTPUT ;
    USE SIGNAL ;
    PORT
      LAYER M4 ;
        RECT  0 45.36 0.192 45.384 ;
    END
  END o[410]
  PIN o[411]
    DIRECTION OUTPUT ;
    USE SIGNAL ;
    PORT
      LAYER M4 ;
        RECT  0 45.504 0.192 45.528 ;
    END
  END o[411]
  PIN o[412]
    DIRECTION OUTPUT ;
    USE SIGNAL ;
    PORT
      LAYER M4 ;
        RECT  0 45.6 0.192 45.624 ;
    END
  END o[412]
  PIN o[413]
    DIRECTION OUTPUT ;
    USE SIGNAL ;
    PORT
      LAYER M4 ;
        RECT  0 45.696 0.192 45.72 ;
    END
  END o[413]
  PIN o[414]
    DIRECTION OUTPUT ;
    USE SIGNAL ;
    PORT
      LAYER M4 ;
        RECT  0 45.792 0.192 45.816 ;
    END
  END o[414]
  PIN o[415]
    DIRECTION OUTPUT ;
    USE SIGNAL ;
    PORT
      LAYER M4 ;
        RECT  0 45.888 0.192 45.912 ;
    END
  END o[415]
  PIN o[416]
    DIRECTION OUTPUT ;
    USE SIGNAL ;
    PORT
      LAYER M4 ;
        RECT  0 46.032 0.192 46.056 ;
    END
  END o[416]
  PIN o[417]
    DIRECTION OUTPUT ;
    USE SIGNAL ;
    PORT
      LAYER M4 ;
        RECT  0 46.128 0.192 46.152 ;
    END
  END o[417]
  PIN o[418]
    DIRECTION OUTPUT ;
    USE SIGNAL ;
    PORT
      LAYER M4 ;
        RECT  0 46.224 0.192 46.248 ;
    END
  END o[418]
  PIN o[419]
    DIRECTION OUTPUT ;
    USE SIGNAL ;
    PORT
      LAYER M4 ;
        RECT  0 46.32 0.192 46.344 ;
    END
  END o[419]
  PIN o[41]
    DIRECTION OUTPUT ;
    USE SIGNAL ;
    PORT
      LAYER M4 ;
        RECT  0 6.528 0.192 6.552 ;
    END
  END o[41]
  PIN o[420]
    DIRECTION OUTPUT ;
    USE SIGNAL ;
    PORT
      LAYER M4 ;
        RECT  0 46.416 0.192 46.44 ;
    END
  END o[420]
  PIN o[421]
    DIRECTION OUTPUT ;
    USE SIGNAL ;
    PORT
      LAYER M4 ;
        RECT  0 46.56 0.192 46.584 ;
    END
  END o[421]
  PIN o[422]
    DIRECTION OUTPUT ;
    USE SIGNAL ;
    PORT
      LAYER M4 ;
        RECT  0 46.656 0.192 46.68 ;
    END
  END o[422]
  PIN o[423]
    DIRECTION OUTPUT ;
    USE SIGNAL ;
    PORT
      LAYER M4 ;
        RECT  0 46.752 0.192 46.776 ;
    END
  END o[423]
  PIN o[424]
    DIRECTION OUTPUT ;
    USE SIGNAL ;
    PORT
      LAYER M4 ;
        RECT  0 46.848 0.192 46.872 ;
    END
  END o[424]
  PIN o[425]
    DIRECTION OUTPUT ;
    USE SIGNAL ;
    PORT
      LAYER M4 ;
        RECT  0 46.944 0.192 46.968 ;
    END
  END o[425]
  PIN o[426]
    DIRECTION OUTPUT ;
    USE SIGNAL ;
    PORT
      LAYER M4 ;
        RECT  0 47.088 0.192 47.112 ;
    END
  END o[426]
  PIN o[427]
    DIRECTION OUTPUT ;
    USE SIGNAL ;
    PORT
      LAYER M4 ;
        RECT  0 47.184 0.192 47.208 ;
    END
  END o[427]
  PIN o[428]
    DIRECTION OUTPUT ;
    USE SIGNAL ;
    PORT
      LAYER M4 ;
        RECT  0 47.28 0.192 47.304 ;
    END
  END o[428]
  PIN o[429]
    DIRECTION OUTPUT ;
    USE SIGNAL ;
    PORT
      LAYER M4 ;
        RECT  0 47.376 0.192 47.4 ;
    END
  END o[429]
  PIN o[42]
    DIRECTION OUTPUT ;
    USE SIGNAL ;
    PORT
      LAYER M4 ;
        RECT  0 6.624 0.192 6.648 ;
    END
  END o[42]
  PIN o[430]
    DIRECTION OUTPUT ;
    USE SIGNAL ;
    PORT
      LAYER M4 ;
        RECT  0 47.472 0.192 47.496 ;
    END
  END o[430]
  PIN o[431]
    DIRECTION OUTPUT ;
    USE SIGNAL ;
    PORT
      LAYER M4 ;
        RECT  0 47.616 0.192 47.64 ;
    END
  END o[431]
  PIN o[432]
    DIRECTION OUTPUT ;
    USE SIGNAL ;
    PORT
      LAYER M4 ;
        RECT  0 47.712 0.192 47.736 ;
    END
  END o[432]
  PIN o[433]
    DIRECTION OUTPUT ;
    USE SIGNAL ;
    PORT
      LAYER M4 ;
        RECT  0 47.808 0.192 47.832 ;
    END
  END o[433]
  PIN o[434]
    DIRECTION OUTPUT ;
    USE SIGNAL ;
    PORT
      LAYER M4 ;
        RECT  0 47.904 0.192 47.928 ;
    END
  END o[434]
  PIN o[435]
    DIRECTION OUTPUT ;
    USE SIGNAL ;
    PORT
      LAYER M4 ;
        RECT  0 48 0.192 48.024 ;
    END
  END o[435]
  PIN o[436]
    DIRECTION OUTPUT ;
    USE SIGNAL ;
    PORT
      LAYER M4 ;
        RECT  0 48.096 0.192 48.12 ;
    END
  END o[436]
  PIN o[437]
    DIRECTION OUTPUT ;
    USE SIGNAL ;
    PORT
      LAYER M4 ;
        RECT  0 48.24 0.192 48.264 ;
    END
  END o[437]
  PIN o[438]
    DIRECTION OUTPUT ;
    USE SIGNAL ;
    PORT
      LAYER M4 ;
        RECT  0 48.336 0.192 48.36 ;
    END
  END o[438]
  PIN o[439]
    DIRECTION OUTPUT ;
    USE SIGNAL ;
    PORT
      LAYER M4 ;
        RECT  0 48.432 0.192 48.456 ;
    END
  END o[439]
  PIN o[43]
    DIRECTION OUTPUT ;
    USE SIGNAL ;
    PORT
      LAYER M4 ;
        RECT  0 6.768 0.192 6.792 ;
    END
  END o[43]
  PIN o[440]
    DIRECTION OUTPUT ;
    USE SIGNAL ;
    PORT
      LAYER M4 ;
        RECT  0 48.528 0.192 48.552 ;
    END
  END o[440]
  PIN o[441]
    DIRECTION OUTPUT ;
    USE SIGNAL ;
    PORT
      LAYER M4 ;
        RECT  0 48.624 0.192 48.648 ;
    END
  END o[441]
  PIN o[442]
    DIRECTION OUTPUT ;
    USE SIGNAL ;
    PORT
      LAYER M4 ;
        RECT  0 48.768 0.192 48.792 ;
    END
  END o[442]
  PIN o[443]
    DIRECTION OUTPUT ;
    USE SIGNAL ;
    PORT
      LAYER M4 ;
        RECT  0 48.864 0.192 48.888 ;
    END
  END o[443]
  PIN o[444]
    DIRECTION OUTPUT ;
    USE SIGNAL ;
    PORT
      LAYER M4 ;
        RECT  0 48.96 0.192 48.984 ;
    END
  END o[444]
  PIN o[445]
    DIRECTION OUTPUT ;
    USE SIGNAL ;
    PORT
      LAYER M4 ;
        RECT  0 49.056 0.192 49.08 ;
    END
  END o[445]
  PIN o[446]
    DIRECTION OUTPUT ;
    USE SIGNAL ;
    PORT
      LAYER M4 ;
        RECT  0 49.152 0.192 49.176 ;
    END
  END o[446]
  PIN o[447]
    DIRECTION OUTPUT ;
    USE SIGNAL ;
    PORT
      LAYER M4 ;
        RECT  0 49.296 0.192 49.32 ;
    END
  END o[447]
  PIN o[448]
    DIRECTION OUTPUT ;
    USE SIGNAL ;
    PORT
      LAYER M4 ;
        RECT  0 49.392 0.192 49.416 ;
    END
  END o[448]
  PIN o[449]
    DIRECTION OUTPUT ;
    USE SIGNAL ;
    PORT
      LAYER M4 ;
        RECT  0 49.488 0.192 49.512 ;
    END
  END o[449]
  PIN o[44]
    DIRECTION OUTPUT ;
    USE SIGNAL ;
    PORT
      LAYER M4 ;
        RECT  0 6.864 0.192 6.888 ;
    END
  END o[44]
  PIN o[450]
    DIRECTION OUTPUT ;
    USE SIGNAL ;
    PORT
      LAYER M4 ;
        RECT  0 49.584 0.192 49.608 ;
    END
  END o[450]
  PIN o[451]
    DIRECTION OUTPUT ;
    USE SIGNAL ;
    PORT
      LAYER M4 ;
        RECT  0 49.68 0.192 49.704 ;
    END
  END o[451]
  PIN o[452]
    DIRECTION OUTPUT ;
    USE SIGNAL ;
    PORT
      LAYER M4 ;
        RECT  0 49.824 0.192 49.848 ;
    END
  END o[452]
  PIN o[453]
    DIRECTION OUTPUT ;
    USE SIGNAL ;
    PORT
      LAYER M4 ;
        RECT  0 49.92 0.192 49.944 ;
    END
  END o[453]
  PIN o[454]
    DIRECTION OUTPUT ;
    USE SIGNAL ;
    PORT
      LAYER M4 ;
        RECT  0 50.016 0.192 50.04 ;
    END
  END o[454]
  PIN o[455]
    DIRECTION OUTPUT ;
    USE SIGNAL ;
    PORT
      LAYER M4 ;
        RECT  0 50.112 0.192 50.136 ;
    END
  END o[455]
  PIN o[456]
    DIRECTION OUTPUT ;
    USE SIGNAL ;
    PORT
      LAYER M4 ;
        RECT  0 50.208 0.192 50.232 ;
    END
  END o[456]
  PIN o[457]
    DIRECTION OUTPUT ;
    USE SIGNAL ;
    PORT
      LAYER M4 ;
        RECT  0 50.352 0.192 50.376 ;
    END
  END o[457]
  PIN o[458]
    DIRECTION OUTPUT ;
    USE SIGNAL ;
    PORT
      LAYER M4 ;
        RECT  0 50.448 0.192 50.472 ;
    END
  END o[458]
  PIN o[459]
    DIRECTION OUTPUT ;
    USE SIGNAL ;
    PORT
      LAYER M4 ;
        RECT  0 50.544 0.192 50.568 ;
    END
  END o[459]
  PIN o[45]
    DIRECTION OUTPUT ;
    USE SIGNAL ;
    PORT
      LAYER M4 ;
        RECT  0 6.96 0.192 6.984 ;
    END
  END o[45]
  PIN o[460]
    DIRECTION OUTPUT ;
    USE SIGNAL ;
    PORT
      LAYER M4 ;
        RECT  0 50.64 0.192 50.664 ;
    END
  END o[460]
  PIN o[461]
    DIRECTION OUTPUT ;
    USE SIGNAL ;
    PORT
      LAYER M4 ;
        RECT  0 50.736 0.192 50.76 ;
    END
  END o[461]
  PIN o[462]
    DIRECTION OUTPUT ;
    USE SIGNAL ;
    PORT
      LAYER M4 ;
        RECT  0 50.88 0.192 50.904 ;
    END
  END o[462]
  PIN o[463]
    DIRECTION OUTPUT ;
    USE SIGNAL ;
    PORT
      LAYER M4 ;
        RECT  0 50.976 0.192 51 ;
    END
  END o[463]
  PIN o[464]
    DIRECTION OUTPUT ;
    USE SIGNAL ;
    PORT
      LAYER M4 ;
        RECT  0 51.072 0.192 51.096 ;
    END
  END o[464]
  PIN o[465]
    DIRECTION OUTPUT ;
    USE SIGNAL ;
    PORT
      LAYER M4 ;
        RECT  0 51.168 0.192 51.192 ;
    END
  END o[465]
  PIN o[466]
    DIRECTION OUTPUT ;
    USE SIGNAL ;
    PORT
      LAYER M4 ;
        RECT  0 51.264 0.192 51.288 ;
    END
  END o[466]
  PIN o[467]
    DIRECTION OUTPUT ;
    USE SIGNAL ;
    PORT
      LAYER M4 ;
        RECT  0 51.36 0.192 51.384 ;
    END
  END o[467]
  PIN o[468]
    DIRECTION OUTPUT ;
    USE SIGNAL ;
    PORT
      LAYER M4 ;
        RECT  0 51.504 0.192 51.528 ;
    END
  END o[468]
  PIN o[469]
    DIRECTION OUTPUT ;
    USE SIGNAL ;
    PORT
      LAYER M4 ;
        RECT  0 51.6 0.192 51.624 ;
    END
  END o[469]
  PIN o[46]
    DIRECTION OUTPUT ;
    USE SIGNAL ;
    PORT
      LAYER M4 ;
        RECT  0 7.056 0.192 7.08 ;
    END
  END o[46]
  PIN o[470]
    DIRECTION OUTPUT ;
    USE SIGNAL ;
    PORT
      LAYER M4 ;
        RECT  0 51.696 0.192 51.72 ;
    END
  END o[470]
  PIN o[471]
    DIRECTION OUTPUT ;
    USE SIGNAL ;
    PORT
      LAYER M4 ;
        RECT  0 51.792 0.192 51.816 ;
    END
  END o[471]
  PIN o[472]
    DIRECTION OUTPUT ;
    USE SIGNAL ;
    PORT
      LAYER M4 ;
        RECT  0 51.888 0.192 51.912 ;
    END
  END o[472]
  PIN o[473]
    DIRECTION OUTPUT ;
    USE SIGNAL ;
    PORT
      LAYER M4 ;
        RECT  0 52.032 0.192 52.056 ;
    END
  END o[473]
  PIN o[474]
    DIRECTION OUTPUT ;
    USE SIGNAL ;
    PORT
      LAYER M4 ;
        RECT  0 52.128 0.192 52.152 ;
    END
  END o[474]
  PIN o[475]
    DIRECTION OUTPUT ;
    USE SIGNAL ;
    PORT
      LAYER M4 ;
        RECT  0 52.224 0.192 52.248 ;
    END
  END o[475]
  PIN o[476]
    DIRECTION OUTPUT ;
    USE SIGNAL ;
    PORT
      LAYER M4 ;
        RECT  0 52.32 0.192 52.344 ;
    END
  END o[476]
  PIN o[477]
    DIRECTION OUTPUT ;
    USE SIGNAL ;
    PORT
      LAYER M4 ;
        RECT  0 52.416 0.192 52.44 ;
    END
  END o[477]
  PIN o[478]
    DIRECTION OUTPUT ;
    USE SIGNAL ;
    PORT
      LAYER M4 ;
        RECT  0 52.56 0.192 52.584 ;
    END
  END o[478]
  PIN o[479]
    DIRECTION OUTPUT ;
    USE SIGNAL ;
    PORT
      LAYER M4 ;
        RECT  0 52.656 0.192 52.68 ;
    END
  END o[479]
  PIN o[47]
    DIRECTION OUTPUT ;
    USE SIGNAL ;
    PORT
      LAYER M4 ;
        RECT  0 7.152 0.192 7.176 ;
    END
  END o[47]
  PIN o[480]
    DIRECTION OUTPUT ;
    USE SIGNAL ;
    PORT
      LAYER M4 ;
        RECT  0 52.752 0.192 52.776 ;
    END
  END o[480]
  PIN o[481]
    DIRECTION OUTPUT ;
    USE SIGNAL ;
    PORT
      LAYER M4 ;
        RECT  0 52.848 0.192 52.872 ;
    END
  END o[481]
  PIN o[482]
    DIRECTION OUTPUT ;
    USE SIGNAL ;
    PORT
      LAYER M4 ;
        RECT  0 52.944 0.192 52.968 ;
    END
  END o[482]
  PIN o[483]
    DIRECTION OUTPUT ;
    USE SIGNAL ;
    PORT
      LAYER M4 ;
        RECT  0 53.088 0.192 53.112 ;
    END
  END o[483]
  PIN o[484]
    DIRECTION OUTPUT ;
    USE SIGNAL ;
    PORT
      LAYER M4 ;
        RECT  0 53.184 0.192 53.208 ;
    END
  END o[484]
  PIN o[485]
    DIRECTION OUTPUT ;
    USE SIGNAL ;
    PORT
      LAYER M4 ;
        RECT  0 53.28 0.192 53.304 ;
    END
  END o[485]
  PIN o[486]
    DIRECTION OUTPUT ;
    USE SIGNAL ;
    PORT
      LAYER M4 ;
        RECT  0 53.376 0.192 53.4 ;
    END
  END o[486]
  PIN o[487]
    DIRECTION OUTPUT ;
    USE SIGNAL ;
    PORT
      LAYER M4 ;
        RECT  0 53.472 0.192 53.496 ;
    END
  END o[487]
  PIN o[488]
    DIRECTION OUTPUT ;
    USE SIGNAL ;
    PORT
      LAYER M4 ;
        RECT  0 53.616 0.192 53.64 ;
    END
  END o[488]
  PIN o[489]
    DIRECTION OUTPUT ;
    USE SIGNAL ;
    PORT
      LAYER M4 ;
        RECT  0 53.712 0.192 53.736 ;
    END
  END o[489]
  PIN o[48]
    DIRECTION OUTPUT ;
    USE SIGNAL ;
    PORT
      LAYER M4 ;
        RECT  0 7.296 0.192 7.32 ;
    END
  END o[48]
  PIN o[490]
    DIRECTION OUTPUT ;
    USE SIGNAL ;
    PORT
      LAYER M4 ;
        RECT  0 53.808 0.192 53.832 ;
    END
  END o[490]
  PIN o[491]
    DIRECTION OUTPUT ;
    USE SIGNAL ;
    PORT
      LAYER M4 ;
        RECT  0 53.904 0.192 53.928 ;
    END
  END o[491]
  PIN o[492]
    DIRECTION OUTPUT ;
    USE SIGNAL ;
    PORT
      LAYER M4 ;
        RECT  0 54 0.192 54.024 ;
    END
  END o[492]
  PIN o[493]
    DIRECTION OUTPUT ;
    USE SIGNAL ;
    PORT
      LAYER M4 ;
        RECT  0 54.096 0.192 54.12 ;
    END
  END o[493]
  PIN o[494]
    DIRECTION OUTPUT ;
    USE SIGNAL ;
    PORT
      LAYER M4 ;
        RECT  0 54.24 0.192 54.264 ;
    END
  END o[494]
  PIN o[495]
    DIRECTION OUTPUT ;
    USE SIGNAL ;
    PORT
      LAYER M4 ;
        RECT  0 54.336 0.192 54.36 ;
    END
  END o[495]
  PIN o[496]
    DIRECTION OUTPUT ;
    USE SIGNAL ;
    PORT
      LAYER M4 ;
        RECT  0 54.432 0.192 54.456 ;
    END
  END o[496]
  PIN o[497]
    DIRECTION OUTPUT ;
    USE SIGNAL ;
    PORT
      LAYER M4 ;
        RECT  0 54.528 0.192 54.552 ;
    END
  END o[497]
  PIN o[498]
    DIRECTION OUTPUT ;
    USE SIGNAL ;
    PORT
      LAYER M4 ;
        RECT  0 54.624 0.192 54.648 ;
    END
  END o[498]
  PIN o[499]
    DIRECTION OUTPUT ;
    USE SIGNAL ;
    PORT
      LAYER M4 ;
        RECT  0 54.768 0.192 54.792 ;
    END
  END o[499]
  PIN o[49]
    DIRECTION OUTPUT ;
    USE SIGNAL ;
    PORT
      LAYER M4 ;
        RECT  0 7.392 0.192 7.416 ;
    END
  END o[49]
  PIN o[4]
    DIRECTION OUTPUT ;
    USE SIGNAL ;
    PORT
      LAYER M4 ;
        RECT  0 2.64 0.192 2.664 ;
    END
  END o[4]
  PIN o[500]
    DIRECTION OUTPUT ;
    USE SIGNAL ;
    PORT
      LAYER M4 ;
        RECT  0 54.864 0.192 54.888 ;
    END
  END o[500]
  PIN o[501]
    DIRECTION OUTPUT ;
    USE SIGNAL ;
    PORT
      LAYER M4 ;
        RECT  0 54.96 0.192 54.984 ;
    END
  END o[501]
  PIN o[502]
    DIRECTION OUTPUT ;
    USE SIGNAL ;
    PORT
      LAYER M4 ;
        RECT  0 55.056 0.192 55.08 ;
    END
  END o[502]
  PIN o[503]
    DIRECTION OUTPUT ;
    USE SIGNAL ;
    PORT
      LAYER M4 ;
        RECT  0 55.152 0.192 55.176 ;
    END
  END o[503]
  PIN o[504]
    DIRECTION OUTPUT ;
    USE SIGNAL ;
    PORT
      LAYER M4 ;
        RECT  0 55.296 0.192 55.32 ;
    END
  END o[504]
  PIN o[505]
    DIRECTION OUTPUT ;
    USE SIGNAL ;
    PORT
      LAYER M4 ;
        RECT  0 55.392 0.192 55.416 ;
    END
  END o[505]
  PIN o[506]
    DIRECTION OUTPUT ;
    USE SIGNAL ;
    PORT
      LAYER M4 ;
        RECT  0 55.488 0.192 55.512 ;
    END
  END o[506]
  PIN o[507]
    DIRECTION OUTPUT ;
    USE SIGNAL ;
    PORT
      LAYER M4 ;
        RECT  0 55.584 0.192 55.608 ;
    END
  END o[507]
  PIN o[508]
    DIRECTION OUTPUT ;
    USE SIGNAL ;
    PORT
      LAYER M4 ;
        RECT  0 55.68 0.192 55.704 ;
    END
  END o[508]
  PIN o[509]
    DIRECTION OUTPUT ;
    USE SIGNAL ;
    PORT
      LAYER M4 ;
        RECT  0 55.824 0.192 55.848 ;
    END
  END o[509]
  PIN o[50]
    DIRECTION OUTPUT ;
    USE SIGNAL ;
    PORT
      LAYER M4 ;
        RECT  0 7.488 0.192 7.512 ;
    END
  END o[50]
  PIN o[510]
    DIRECTION OUTPUT ;
    USE SIGNAL ;
    PORT
      LAYER M4 ;
        RECT  0 55.92 0.192 55.944 ;
    END
  END o[510]
  PIN o[511]
    DIRECTION OUTPUT ;
    USE SIGNAL ;
    PORT
      LAYER M4 ;
        RECT  0 56.016 0.192 56.04 ;
    END
  END o[511]
  PIN o[51]
    DIRECTION OUTPUT ;
    USE SIGNAL ;
    PORT
      LAYER M4 ;
        RECT  0 7.584 0.192 7.608 ;
    END
  END o[51]
  PIN o[52]
    DIRECTION OUTPUT ;
    USE SIGNAL ;
    PORT
      LAYER M4 ;
        RECT  0 7.68 0.192 7.704 ;
    END
  END o[52]
  PIN o[53]
    DIRECTION OUTPUT ;
    USE SIGNAL ;
    PORT
      LAYER M4 ;
        RECT  0 7.824 0.192 7.848 ;
    END
  END o[53]
  PIN o[54]
    DIRECTION OUTPUT ;
    USE SIGNAL ;
    PORT
      LAYER M4 ;
        RECT  0 7.92 0.192 7.944 ;
    END
  END o[54]
  PIN o[55]
    DIRECTION OUTPUT ;
    USE SIGNAL ;
    PORT
      LAYER M4 ;
        RECT  0 8.016 0.192 8.04 ;
    END
  END o[55]
  PIN o[56]
    DIRECTION OUTPUT ;
    USE SIGNAL ;
    PORT
      LAYER M4 ;
        RECT  0 8.112 0.192 8.136 ;
    END
  END o[56]
  PIN o[57]
    DIRECTION OUTPUT ;
    USE SIGNAL ;
    PORT
      LAYER M4 ;
        RECT  0 8.208 0.192 8.232 ;
    END
  END o[57]
  PIN o[58]
    DIRECTION OUTPUT ;
    USE SIGNAL ;
    PORT
      LAYER M4 ;
        RECT  0 8.352 0.192 8.376 ;
    END
  END o[58]
  PIN o[59]
    DIRECTION OUTPUT ;
    USE SIGNAL ;
    PORT
      LAYER M4 ;
        RECT  0 8.448 0.192 8.472 ;
    END
  END o[59]
  PIN o[5]
    DIRECTION OUTPUT ;
    USE SIGNAL ;
    PORT
      LAYER M4 ;
        RECT  0 2.736 0.192 2.76 ;
    END
  END o[5]
  PIN o[60]
    DIRECTION OUTPUT ;
    USE SIGNAL ;
    PORT
      LAYER M4 ;
        RECT  0 8.544 0.192 8.568 ;
    END
  END o[60]
  PIN o[61]
    DIRECTION OUTPUT ;
    USE SIGNAL ;
    PORT
      LAYER M4 ;
        RECT  0 8.64 0.192 8.664 ;
    END
  END o[61]
  PIN o[62]
    DIRECTION OUTPUT ;
    USE SIGNAL ;
    PORT
      LAYER M4 ;
        RECT  0 8.736 0.192 8.76 ;
    END
  END o[62]
  PIN o[63]
    DIRECTION OUTPUT ;
    USE SIGNAL ;
    PORT
      LAYER M4 ;
        RECT  0 8.88 0.192 8.904 ;
    END
  END o[63]
  PIN o[64]
    DIRECTION OUTPUT ;
    USE SIGNAL ;
    PORT
      LAYER M4 ;
        RECT  0 8.976 0.192 9 ;
    END
  END o[64]
  PIN o[65]
    DIRECTION OUTPUT ;
    USE SIGNAL ;
    PORT
      LAYER M4 ;
        RECT  0 9.072 0.192 9.096 ;
    END
  END o[65]
  PIN o[66]
    DIRECTION OUTPUT ;
    USE SIGNAL ;
    PORT
      LAYER M4 ;
        RECT  0 9.168 0.192 9.192 ;
    END
  END o[66]
  PIN o[67]
    DIRECTION OUTPUT ;
    USE SIGNAL ;
    PORT
      LAYER M4 ;
        RECT  0 9.264 0.192 9.288 ;
    END
  END o[67]
  PIN o[68]
    DIRECTION OUTPUT ;
    USE SIGNAL ;
    PORT
      LAYER M4 ;
        RECT  0 9.36 0.192 9.384 ;
    END
  END o[68]
  PIN o[69]
    DIRECTION OUTPUT ;
    USE SIGNAL ;
    PORT
      LAYER M4 ;
        RECT  0 9.504 0.192 9.528 ;
    END
  END o[69]
  PIN o[6]
    DIRECTION OUTPUT ;
    USE SIGNAL ;
    PORT
      LAYER M4 ;
        RECT  0 2.88 0.192 2.904 ;
    END
  END o[6]
  PIN o[70]
    DIRECTION OUTPUT ;
    USE SIGNAL ;
    PORT
      LAYER M4 ;
        RECT  0 9.6 0.192 9.624 ;
    END
  END o[70]
  PIN o[71]
    DIRECTION OUTPUT ;
    USE SIGNAL ;
    PORT
      LAYER M4 ;
        RECT  0 9.696 0.192 9.72 ;
    END
  END o[71]
  PIN o[72]
    DIRECTION OUTPUT ;
    USE SIGNAL ;
    PORT
      LAYER M4 ;
        RECT  0 9.792 0.192 9.816 ;
    END
  END o[72]
  PIN o[73]
    DIRECTION OUTPUT ;
    USE SIGNAL ;
    PORT
      LAYER M4 ;
        RECT  0 9.888 0.192 9.912 ;
    END
  END o[73]
  PIN o[74]
    DIRECTION OUTPUT ;
    USE SIGNAL ;
    PORT
      LAYER M4 ;
        RECT  0 10.032 0.192 10.056 ;
    END
  END o[74]
  PIN o[75]
    DIRECTION OUTPUT ;
    USE SIGNAL ;
    PORT
      LAYER M4 ;
        RECT  0 10.128 0.192 10.152 ;
    END
  END o[75]
  PIN o[76]
    DIRECTION OUTPUT ;
    USE SIGNAL ;
    PORT
      LAYER M4 ;
        RECT  0 10.224 0.192 10.248 ;
    END
  END o[76]
  PIN o[77]
    DIRECTION OUTPUT ;
    USE SIGNAL ;
    PORT
      LAYER M4 ;
        RECT  0 10.32 0.192 10.344 ;
    END
  END o[77]
  PIN o[78]
    DIRECTION OUTPUT ;
    USE SIGNAL ;
    PORT
      LAYER M4 ;
        RECT  0 10.416 0.192 10.44 ;
    END
  END o[78]
  PIN o[79]
    DIRECTION OUTPUT ;
    USE SIGNAL ;
    PORT
      LAYER M4 ;
        RECT  0 10.56 0.192 10.584 ;
    END
  END o[79]
  PIN o[7]
    DIRECTION OUTPUT ;
    USE SIGNAL ;
    PORT
      LAYER M4 ;
        RECT  0 2.976 0.192 3 ;
    END
  END o[7]
  PIN o[80]
    DIRECTION OUTPUT ;
    USE SIGNAL ;
    PORT
      LAYER M4 ;
        RECT  0 10.656 0.192 10.68 ;
    END
  END o[80]
  PIN o[81]
    DIRECTION OUTPUT ;
    USE SIGNAL ;
    PORT
      LAYER M4 ;
        RECT  0 10.752 0.192 10.776 ;
    END
  END o[81]
  PIN o[82]
    DIRECTION OUTPUT ;
    USE SIGNAL ;
    PORT
      LAYER M4 ;
        RECT  0 10.848 0.192 10.872 ;
    END
  END o[82]
  PIN o[83]
    DIRECTION OUTPUT ;
    USE SIGNAL ;
    PORT
      LAYER M4 ;
        RECT  0 10.944 0.192 10.968 ;
    END
  END o[83]
  PIN o[84]
    DIRECTION OUTPUT ;
    USE SIGNAL ;
    PORT
      LAYER M4 ;
        RECT  0 11.088 0.192 11.112 ;
    END
  END o[84]
  PIN o[85]
    DIRECTION OUTPUT ;
    USE SIGNAL ;
    PORT
      LAYER M4 ;
        RECT  0 11.184 0.192 11.208 ;
    END
  END o[85]
  PIN o[86]
    DIRECTION OUTPUT ;
    USE SIGNAL ;
    PORT
      LAYER M4 ;
        RECT  0 11.28 0.192 11.304 ;
    END
  END o[86]
  PIN o[87]
    DIRECTION OUTPUT ;
    USE SIGNAL ;
    PORT
      LAYER M4 ;
        RECT  0 11.376 0.192 11.4 ;
    END
  END o[87]
  PIN o[88]
    DIRECTION OUTPUT ;
    USE SIGNAL ;
    PORT
      LAYER M4 ;
        RECT  0 11.472 0.192 11.496 ;
    END
  END o[88]
  PIN o[89]
    DIRECTION OUTPUT ;
    USE SIGNAL ;
    PORT
      LAYER M4 ;
        RECT  0 11.616 0.192 11.64 ;
    END
  END o[89]
  PIN o[8]
    DIRECTION OUTPUT ;
    USE SIGNAL ;
    PORT
      LAYER M4 ;
        RECT  0 3.072 0.192 3.096 ;
    END
  END o[8]
  PIN o[90]
    DIRECTION OUTPUT ;
    USE SIGNAL ;
    PORT
      LAYER M4 ;
        RECT  0 11.712 0.192 11.736 ;
    END
  END o[90]
  PIN o[91]
    DIRECTION OUTPUT ;
    USE SIGNAL ;
    PORT
      LAYER M4 ;
        RECT  0 11.808 0.192 11.832 ;
    END
  END o[91]
  PIN o[92]
    DIRECTION OUTPUT ;
    USE SIGNAL ;
    PORT
      LAYER M4 ;
        RECT  0 11.904 0.192 11.928 ;
    END
  END o[92]
  PIN o[93]
    DIRECTION OUTPUT ;
    USE SIGNAL ;
    PORT
      LAYER M4 ;
        RECT  0 12 0.192 12.024 ;
    END
  END o[93]
  PIN o[94]
    DIRECTION OUTPUT ;
    USE SIGNAL ;
    PORT
      LAYER M4 ;
        RECT  0 12.096 0.192 12.12 ;
    END
  END o[94]
  PIN o[95]
    DIRECTION OUTPUT ;
    USE SIGNAL ;
    PORT
      LAYER M4 ;
        RECT  0 12.24 0.192 12.264 ;
    END
  END o[95]
  PIN o[96]
    DIRECTION OUTPUT ;
    USE SIGNAL ;
    PORT
      LAYER M4 ;
        RECT  0 12.336 0.192 12.36 ;
    END
  END o[96]
  PIN o[97]
    DIRECTION OUTPUT ;
    USE SIGNAL ;
    PORT
      LAYER M4 ;
        RECT  0 12.432 0.192 12.456 ;
    END
  END o[97]
  PIN o[98]
    DIRECTION OUTPUT ;
    USE SIGNAL ;
    PORT
      LAYER M4 ;
        RECT  0 12.528 0.192 12.552 ;
    END
  END o[98]
  PIN o[99]
    DIRECTION OUTPUT ;
    USE SIGNAL ;
    PORT
      LAYER M4 ;
        RECT  0 12.624 0.192 12.648 ;
    END
  END o[99]
  PIN o[9]
    DIRECTION OUTPUT ;
    USE SIGNAL ;
    PORT
      LAYER M4 ;
        RECT  0 3.168 0.192 3.192 ;
    END
  END o[9]
  PIN rs
    DIRECTION INPUT ;
    USE SIGNAL ;
    PORT
      LAYER M5 ;
        RECT  11.856 58.128 11.88 58.32 ;
    END
    PORT
      LAYER M5 ;
        RECT  11.856 55.141 11.88 58.192 ;
    END
  END rs
  PIN VDD
    DIRECTION INOUT ;
    USE POWER ;
    PORT
      LAYER M5 ;
        RECT  13.392 2.151 13.512 56.169 ;
        RECT  10.692 2.151 10.812 56.169 ;
        RECT  7.992 2.151 8.112 56.169 ;
        RECT  5.292 2.151 5.412 56.169 ;
        RECT  2.592 2.151 2.712 56.169 ;
    END
  END VDD
  PIN VSS
    DIRECTION INOUT ;
    USE GROUND ;
    PORT
      LAYER M5 ;
        RECT  13.2 2.137 13.32 56.183 ;
        RECT  10.5 2.137 10.62 56.183 ;
        RECT  7.8 2.137 7.92 56.183 ;
        RECT  5.1 2.137 5.22 56.183 ;
        RECT  2.4 2.137 2.52 56.183 ;
    END
  END VSS
  # OT_OBS_CLOSED layer=M5 d_um=1.536 added=85
  OBS
    LAYER RVTN ;
     RECT  2.16 2.16 15.12 2.295 ;
     RECT  2.16 2.565 15.12 2.835 ;
     RECT  2.16 3.105 15.12 3.375 ;
     RECT  2.16 3.645 15.12 3.915 ;
     RECT  2.16 4.185 15.12 4.455 ;
     RECT  2.16 4.725 15.12 4.995 ;
     RECT  2.16 5.265 15.12 5.535 ;
     RECT  2.16 5.805 15.12 6.075 ;
     RECT  2.16 6.345 15.12 6.615 ;
     RECT  2.16 6.885 15.12 7.155 ;
     RECT  2.16 7.425 15.12 7.695 ;
     RECT  2.16 7.965 15.12 8.235 ;
     RECT  2.16 8.505 15.12 8.775 ;
     RECT  2.16 9.045 15.12 9.315 ;
     RECT  2.16 9.585 15.12 9.855 ;
     RECT  2.16 10.125 15.12 10.395 ;
     RECT  2.16 10.665 15.12 10.935 ;
     RECT  2.16 11.205 15.12 11.475 ;
     RECT  2.16 11.745 15.12 12.015 ;
     RECT  2.16 12.285 15.12 12.555 ;
     RECT  2.16 12.825 15.12 13.095 ;
     RECT  2.16 13.365 15.12 13.635 ;
     RECT  2.16 13.905 15.12 14.175 ;
     RECT  2.16 14.445 15.12 14.715 ;
     RECT  2.16 14.985 15.12 15.255 ;
     RECT  2.16 15.525 15.12 15.795 ;
     RECT  2.16 16.065 15.12 16.335 ;
     RECT  2.16 16.605 15.12 16.875 ;
     RECT  2.16 17.145 15.12 17.415 ;
     RECT  2.16 17.685 15.12 17.955 ;
     RECT  2.16 18.225 15.12 18.495 ;
     RECT  2.16 18.765 15.12 19.035 ;
     RECT  2.16 19.305 15.12 19.575 ;
     RECT  2.16 19.845 15.12 20.115 ;
     RECT  2.16 20.385 15.12 20.655 ;
     RECT  2.16 20.925 15.12 21.195 ;
     RECT  2.16 21.465 15.12 21.735 ;
     RECT  2.16 22.005 15.12 22.275 ;
     RECT  2.16 22.545 15.12 22.815 ;
     RECT  2.16 23.085 15.12 23.355 ;
     RECT  2.16 23.625 15.12 23.895 ;
     RECT  2.16 24.165 15.12 24.435 ;
     RECT  2.16 24.705 15.12 24.975 ;
     RECT  2.16 25.245 15.12 25.515 ;
     RECT  2.16 25.785 15.12 26.055 ;
     RECT  2.16 26.325 15.12 26.595 ;
     RECT  2.16 26.865 15.12 27.135 ;
     RECT  2.16 27.405 15.12 27.675 ;
     RECT  2.16 27.945 15.12 28.215 ;
     RECT  2.16 28.485 15.12 28.755 ;
     RECT  2.16 29.025 15.12 29.295 ;
     RECT  2.16 29.565 15.12 29.835 ;
     RECT  2.16 30.105 15.12 30.375 ;
     RECT  2.16 30.645 15.12 30.915 ;
     RECT  2.16 31.185 15.12 31.455 ;
     RECT  2.16 31.725 15.12 31.995 ;
     RECT  2.16 32.265 15.12 32.535 ;
     RECT  2.16 32.805 15.12 33.075 ;
     RECT  2.16 33.345 15.12 33.615 ;
     RECT  2.16 33.885 15.12 34.155 ;
     RECT  2.16 34.425 15.12 34.695 ;
     RECT  2.16 34.965 15.12 35.235 ;
     RECT  2.16 35.505 15.12 35.775 ;
     RECT  2.16 36.045 15.12 36.315 ;
     RECT  2.16 36.585 15.12 36.855 ;
     RECT  2.16 37.125 15.12 37.395 ;
     RECT  2.16 37.665 15.12 37.935 ;
     RECT  2.16 38.205 15.12 38.475 ;
     RECT  2.16 38.745 15.12 39.015 ;
     RECT  2.16 39.285 15.12 39.555 ;
     RECT  2.16 39.825 15.12 40.095 ;
     RECT  2.16 40.365 15.12 40.635 ;
     RECT  2.16 40.905 15.12 41.175 ;
     RECT  2.16 41.445 15.12 41.715 ;
     RECT  2.16 41.985 15.12 42.255 ;
     RECT  2.16 42.525 15.12 42.795 ;
     RECT  2.16 43.065 15.12 43.335 ;
     RECT  2.16 43.605 15.12 43.875 ;
     RECT  2.16 44.145 15.12 44.415 ;
     RECT  2.16 44.685 15.12 44.955 ;
     RECT  2.16 45.225 15.12 45.495 ;
     RECT  2.16 45.765 15.12 46.035 ;
     RECT  2.16 46.305 15.12 46.575 ;
     RECT  2.16 46.845 15.12 47.115 ;
     RECT  2.16 47.385 15.12 47.655 ;
     RECT  2.16 47.925 15.12 48.195 ;
     RECT  2.16 48.465 15.12 48.735 ;
     RECT  2.16 49.005 15.12 49.275 ;
     RECT  2.16 49.545 15.12 49.815 ;
     RECT  2.16 50.085 15.12 50.355 ;
     RECT  2.16 50.625 15.12 50.895 ;
     RECT  2.16 51.165 15.12 51.435 ;
     RECT  2.16 51.705 15.12 51.975 ;
     RECT  2.16 52.245 15.12 52.515 ;
     RECT  2.16 52.785 15.12 53.055 ;
     RECT  2.16 53.325 15.12 53.595 ;
     RECT  2.16 53.865 15.12 54.135 ;
     RECT  2.16 54.405 15.12 54.675 ;
     RECT  2.16 54.945 15.12 55.215 ;
     RECT  2.16 55.485 15.12 55.755 ;
     RECT  2.16 56.025 15.12 56.16 ;
    LAYER RVTP ;
     RECT  2.16 2.295 15.12 2.565 ;
     RECT  2.16 2.835 15.12 3.105 ;
     RECT  2.16 3.375 15.12 3.645 ;
     RECT  2.16 3.915 15.12 4.185 ;
     RECT  2.16 4.455 15.12 4.725 ;
     RECT  2.16 4.995 15.12 5.265 ;
     RECT  2.16 5.535 15.12 5.805 ;
     RECT  2.16 6.075 15.12 6.345 ;
     RECT  2.16 6.615 15.12 6.885 ;
     RECT  2.16 7.155 15.12 7.425 ;
     RECT  2.16 7.695 15.12 7.965 ;
     RECT  2.16 8.235 15.12 8.505 ;
     RECT  2.16 8.775 15.12 9.045 ;
     RECT  2.16 9.315 15.12 9.585 ;
     RECT  2.16 9.855 15.12 10.125 ;
     RECT  2.16 10.395 15.12 10.665 ;
     RECT  2.16 10.935 15.12 11.205 ;
     RECT  2.16 11.475 15.12 11.745 ;
     RECT  2.16 12.015 15.12 12.285 ;
     RECT  2.16 12.555 15.12 12.825 ;
     RECT  2.16 13.095 15.12 13.365 ;
     RECT  2.16 13.635 15.12 13.905 ;
     RECT  2.16 14.175 15.12 14.445 ;
     RECT  2.16 14.715 15.12 14.985 ;
     RECT  2.16 15.255 15.12 15.525 ;
     RECT  2.16 15.795 15.12 16.065 ;
     RECT  2.16 16.335 15.12 16.605 ;
     RECT  2.16 16.875 15.12 17.145 ;
     RECT  2.16 17.415 15.12 17.685 ;
     RECT  2.16 17.955 15.12 18.225 ;
     RECT  2.16 18.495 15.12 18.765 ;
     RECT  2.16 19.035 15.12 19.305 ;
     RECT  2.16 19.575 15.12 19.845 ;
     RECT  2.16 20.115 15.12 20.385 ;
     RECT  2.16 20.655 15.12 20.925 ;
     RECT  2.16 21.195 15.12 21.465 ;
     RECT  2.16 21.735 15.12 22.005 ;
     RECT  2.16 22.275 15.12 22.545 ;
     RECT  2.16 22.815 15.12 23.085 ;
     RECT  2.16 23.355 15.12 23.625 ;
     RECT  2.16 23.895 15.12 24.165 ;
     RECT  2.16 24.435 15.12 24.705 ;
     RECT  2.16 24.975 15.12 25.245 ;
     RECT  2.16 25.515 15.12 25.785 ;
     RECT  2.16 26.055 15.12 26.325 ;
     RECT  2.16 26.595 15.12 26.865 ;
     RECT  2.16 27.135 15.12 27.405 ;
     RECT  2.16 27.675 15.12 27.945 ;
     RECT  2.16 28.215 15.12 28.485 ;
     RECT  2.16 28.755 15.12 29.025 ;
     RECT  2.16 29.295 15.12 29.565 ;
     RECT  2.16 29.835 15.12 30.105 ;
     RECT  2.16 30.375 15.12 30.645 ;
     RECT  2.16 30.915 15.12 31.185 ;
     RECT  2.16 31.455 15.12 31.725 ;
     RECT  2.16 31.995 15.12 32.265 ;
     RECT  2.16 32.535 15.12 32.805 ;
     RECT  2.16 33.075 15.12 33.345 ;
     RECT  2.16 33.615 15.12 33.885 ;
     RECT  2.16 34.155 15.12 34.425 ;
     RECT  2.16 34.695 15.12 34.965 ;
     RECT  2.16 35.235 15.12 35.505 ;
     RECT  2.16 35.775 15.12 36.045 ;
     RECT  2.16 36.315 15.12 36.585 ;
     RECT  2.16 36.855 15.12 37.125 ;
     RECT  2.16 37.395 15.12 37.665 ;
     RECT  2.16 37.935 15.12 38.205 ;
     RECT  2.16 38.475 15.12 38.745 ;
     RECT  2.16 39.015 15.12 39.285 ;
     RECT  2.16 39.555 15.12 39.825 ;
     RECT  2.16 40.095 15.12 40.365 ;
     RECT  2.16 40.635 15.12 40.905 ;
     RECT  2.16 41.175 15.12 41.445 ;
     RECT  2.16 41.715 15.12 41.985 ;
     RECT  2.16 42.255 15.12 42.525 ;
     RECT  2.16 42.795 15.12 43.065 ;
     RECT  2.16 43.335 15.12 43.605 ;
     RECT  2.16 43.875 15.12 44.145 ;
     RECT  2.16 44.415 15.12 44.685 ;
     RECT  2.16 44.955 15.12 45.225 ;
     RECT  2.16 45.495 15.12 45.765 ;
     RECT  2.16 46.035 15.12 46.305 ;
     RECT  2.16 46.575 15.12 46.845 ;
     RECT  2.16 47.115 15.12 47.385 ;
     RECT  2.16 47.655 15.12 47.925 ;
     RECT  2.16 48.195 15.12 48.465 ;
     RECT  2.16 48.735 15.12 49.005 ;
     RECT  2.16 49.275 15.12 49.545 ;
     RECT  2.16 49.815 15.12 50.085 ;
     RECT  2.16 50.355 15.12 50.625 ;
     RECT  2.16 50.895 15.12 51.165 ;
     RECT  2.16 51.435 15.12 51.705 ;
     RECT  2.16 51.975 15.12 52.245 ;
     RECT  2.16 52.515 15.12 52.785 ;
     RECT  2.16 53.055 15.12 53.325 ;
     RECT  2.16 53.595 15.12 53.865 ;
     RECT  2.16 54.135 15.12 54.405 ;
     RECT  2.16 54.675 15.12 54.945 ;
     RECT  2.16 55.215 15.12 55.485 ;
     RECT  2.16 55.755 15.12 56.025 ;
    LAYER M1 ;
     RECT  2.16 2.151 15.12 56.169 ;
    LAYER M2 ;
     RECT  0.211 5.661 0.247 5.679 ;
     RECT  0.211 2.88 0.311 2.898 ;
     RECT  0.211 7.398 0.311 7.416 ;
     RECT  0.211 48.24 0.311 48.258 ;
     RECT  0.211 50.166 0.311 50.184 ;
     RECT  0.247 8.856 0.347 8.874 ;
     RECT  0.211 28.836 0.419 28.854 ;
     RECT  0.247 5.616 0.535 5.679 ;
     RECT  0.499 47.124 0.535 47.142 ;
     RECT  0.535 46.926 2.119 47.844 ;
     RECT  0.535 3.816 2.16 3.834 ;
     RECT  0.535 5.616 2.16 6.804 ;
     RECT  0.535 11.556 2.16 11.574 ;
     RECT  0.535 12.456 2.16 12.474 ;
     RECT  2.155 14.616 2.16 14.634 ;
     RECT  0.211 30.006 2.16 30.024 ;
     RECT  0.211 33.156 2.16 33.174 ;
     RECT  0.535 36.936 2.16 36.954 ;
     RECT  0.211 43.308 2.16 43.326 ;
     RECT  2.119 46.818 2.16 47.844 ;
     RECT  0.535 52.254 2.16 52.272 ;
     RECT  2.16 2.151 3.379 56.169 ;
     RECT  3.379 2.151 4.459 56.25 ;
     RECT  4.459 2.106 4.819 56.25 ;
     RECT  4.819 2.106 4.855 56.322 ;
     RECT  4.855 2.106 7.015 56.358 ;
     RECT  7.015 2.106 7.771 56.439 ;
     RECT  7.771 2.07 9.995 56.439 ;
     RECT  9.995 2.07 10.283 56.394 ;
     RECT  10.283 2.106 10.319 56.394 ;
     RECT  10.319 2.106 12.083 56.358 ;
     RECT  12.083 2.106 12.703 56.322 ;
     RECT  12.703 2.034 13.883 56.322 ;
     RECT  13.883 2.034 14.171 56.286 ;
     RECT  14.171 2.151 14.531 56.286 ;
     RECT  14.531 2.151 15.12 56.25 ;
     RECT  15.12 19.584 15.395 38.736 ;
     RECT  15.12 2.232 15.431 16.398 ;
     RECT  15.12 17.226 15.431 18.558 ;
     RECT  15.395 19.584 15.431 31.248 ;
     RECT  15.395 32.004 15.431 38.736 ;
     RECT  15.12 39.528 15.431 44.406 ;
     RECT  15.12 45.468 15.431 45.486 ;
     RECT  15.12 47.394 15.431 48.798 ;
     RECT  15.12 49.752 15.431 54.432 ;
     RECT  15.12 55.188 15.431 56.25 ;
     RECT  15.431 6.12 15.467 6.408 ;
     RECT  15.431 8.55 15.467 8.568 ;
     RECT  15.431 24.408 15.467 28.206 ;
     RECT  15.431 30.42 15.467 31.176 ;
     RECT  15.431 36.63 15.467 37.656 ;
     RECT  15.431 44.388 15.467 44.406 ;
     RECT  15.431 49.752 15.467 53.55 ;
     RECT  15.431 55.458 15.467 55.476 ;
     RECT  15.431 19.584 16.007 21.186 ;
     RECT  15.467 24.408 16.007 27.936 ;
     RECT  15.431 32.31 16.007 32.634 ;
     RECT  15.431 33.516 16.007 33.876 ;
     RECT  15.467 36.63 16.007 37.62 ;
     RECT  15.431 2.232 16.547 3.096 ;
     RECT  15.431 4.23 16.547 4.248 ;
     RECT  15.431 9.36 16.547 10.728 ;
     RECT  15.431 11.79 16.547 12.51 ;
     RECT  15.431 15.03 16.547 16.02 ;
     RECT  16.007 19.584 16.547 20.484 ;
     RECT  15.431 21.978 16.547 22.104 ;
     RECT  15.431 22.896 16.547 23.616 ;
     RECT  16.007 24.408 16.547 27.36 ;
     RECT  15.431 28.962 16.547 29.556 ;
     RECT  15.467 30.42 16.547 30.438 ;
     RECT  16.007 32.31 16.547 32.49 ;
     RECT  16.007 33.588 16.547 33.876 ;
     RECT  15.431 34.776 16.547 35.568 ;
     RECT  16.007 37.098 16.547 37.62 ;
     RECT  15.431 39.564 16.547 39.582 ;
     RECT  15.431 41.382 16.547 42.21 ;
     RECT  15.12 46.35 16.547 46.368 ;
     RECT  15.431 47.43 16.547 47.448 ;
     RECT  15.431 48.24 16.547 48.258 ;
     RECT  15.467 49.752 16.547 49.77 ;
     RECT  15.467 50.562 16.547 52.542 ;
     RECT  15.467 53.532 16.547 53.55 ;
     RECT  15.431 56.232 16.547 56.25 ;
     RECT  16.547 9.63 16.583 10.728 ;
     RECT  16.547 15.03 16.583 15.282 ;
     RECT  16.547 22.086 16.583 22.104 ;
     RECT  16.547 34.776 16.583 35.46 ;
     RECT  16.547 37.098 16.583 37.116 ;
     RECT  16.547 51.21 16.583 52.506 ;
     RECT  16.547 24.714 16.655 25.776 ;
     RECT  15.467 6.39 17.059 6.408 ;
     RECT  15.431 17.226 17.059 17.244 ;
     RECT  15.431 54.414 17.059 54.432 ;
     RECT  17.059 3.384 17.159 3.402 ;
     RECT  17.059 4.158 17.159 4.176 ;
     RECT  17.059 6.318 17.159 6.57 ;
     RECT  17.059 7.866 17.159 7.884 ;
     RECT  16.583 10.332 17.159 10.728 ;
     RECT  17.059 11.646 17.159 11.664 ;
     RECT  16.547 12.456 17.159 12.474 ;
     RECT  17.059 13.878 17.159 14.778 ;
     RECT  17.059 16.884 17.159 17.946 ;
     RECT  17.059 20.664 17.159 20.88 ;
     RECT  16.655 25.326 17.159 25.776 ;
     RECT  16.547 26.568 17.159 26.586 ;
     RECT  17.059 27.612 17.159 27.9 ;
     RECT  16.583 35.442 17.159 35.46 ;
     RECT  17.059 44.352 17.159 45.558 ;
     RECT  17.059 46.818 17.159 46.836 ;
     RECT  17.059 47.7 17.159 48.15 ;
     RECT  17.059 49.176 17.159 49.194 ;
     RECT  17.059 50.058 17.159 50.229 ;
     RECT  16.583 51.246 17.159 52.506 ;
     RECT  17.059 54.216 17.159 54.432 ;
    LAYER M3 ;
     RECT  14.148 2.029 14.166 2.101 ;
     RECT  4.464 2.101 4.482 2.143 ;
     RECT  7.776 2.065 7.794 2.143 ;
     RECT  10.26 2.065 10.278 2.143 ;
     RECT  12.708 2.029 12.726 2.143 ;
     RECT  13.824 2.101 14.166 2.143 ;
     RECT  3.564 2.059 3.582 2.219 ;
     RECT  11.7 2.263 11.718 2.299 ;
     RECT  12.708 2.143 14.166 2.299 ;
     RECT  10.26 2.143 10.605 2.335 ;
     RECT  2.415 2.143 2.505 2.347 ;
     RECT  11.7 2.299 14.166 2.347 ;
     RECT  4.464 2.143 5.205 2.371 ;
     RECT  6.876 2.335 6.966 2.371 ;
     RECT  7.776 2.143 7.905 2.371 ;
     RECT  10.26 2.335 10.746 2.371 ;
     RECT  11.7 2.347 14.886 2.371 ;
     RECT  2.415 2.347 2.538 2.413 ;
     RECT  4.248 2.371 5.205 2.413 ;
     RECT  2.415 2.413 2.697 2.443 ;
     RECT  2.304 2.443 2.697 2.461 ;
     RECT  7.776 2.371 8.334 2.461 ;
     RECT  9.144 2.263 9.162 2.461 ;
     RECT  6.84 2.371 6.966 2.497 ;
     RECT  7.776 2.461 8.406 2.497 ;
     RECT  10.08 2.371 14.886 2.497 ;
     RECT  9.144 2.461 9.306 2.569 ;
     RECT  10.08 2.497 14.958 2.569 ;
     RECT  2.304 2.461 2.754 2.587 ;
     RECT  6.84 2.497 8.406 2.605 ;
     RECT  9.144 2.569 14.958 2.605 ;
     RECT  0.216 2.059 0.234 2.731 ;
     RECT  6.84 2.605 14.958 2.731 ;
     RECT  6.84 2.731 15.426 2.839 ;
     RECT  0.216 2.731 0.27 2.86 ;
     RECT  6.48 2.839 15.426 2.875 ;
     RECT  2.304 2.587 3.51 3.001 ;
     RECT  4.248 2.413 5.397 3.001 ;
     RECT  0.216 2.86 0.306 3.005 ;
     RECT  0.288 3.005 0.306 3.053 ;
     RECT  6.336 2.875 15.426 3.064 ;
     RECT  6.3 3.064 15.426 3.101 ;
     RECT  6.336 3.101 15.426 3.137 ;
     RECT  2.304 3.001 5.397 3.209 ;
     RECT  6.48 3.137 15.426 3.299 ;
     RECT  16.524 2.203 16.542 3.355 ;
     RECT  2.304 3.209 4.014 3.389 ;
     RECT  6.48 3.299 13.914 3.407 ;
     RECT  16.524 3.355 17.154 3.407 ;
     RECT  14.832 3.299 15.426 3.713 ;
     RECT  2.304 3.389 3.942 3.839 ;
     RECT  5.115 3.209 5.397 3.883 ;
     RECT  2.304 3.839 3.258 3.911 ;
     RECT  0.54 3.811 0.558 4.061 ;
     RECT  5.115 3.883 5.598 4.109 ;
     RECT  16.524 3.407 17.082 4.153 ;
     RECT  16.524 4.153 17.154 4.205 ;
     RECT  6.912 3.407 13.914 4.219 ;
     RECT  16.524 4.205 16.542 4.253 ;
     RECT  3.996 4.219 4.014 4.379 ;
     RECT  6.84 4.219 13.914 4.459 ;
     RECT  6.84 4.459 13.95 4.559 ;
     RECT  6.84 4.559 13.842 4.657 ;
     RECT  2.304 3.911 2.898 4.693 ;
     RECT  14.832 3.713 14.85 4.699 ;
     RECT  14.832 4.699 14.886 4.747 ;
     RECT  5.115 4.109 5.397 4.765 ;
     RECT  4.068 4.621 4.158 4.795 ;
     RECT  4.896 4.765 5.397 4.795 ;
     RECT  6.732 4.657 13.842 4.919 ;
     RECT  2.304 4.693 2.934 4.987 ;
     RECT  2.304 4.987 3.006 5.063 ;
     RECT  2.304 5.063 2.697 5.071 ;
     RECT  2.232 5.071 2.697 5.117 ;
     RECT  4.068 4.795 5.397 5.179 ;
     RECT  6.732 4.919 11.79 5.269 ;
     RECT  3.996 5.179 5.397 5.341 ;
     RECT  16.524 5.083 16.542 5.357 ;
     RECT  6.264 5.269 11.79 5.549 ;
     RECT  0.252 4.699 0.27 5.644 ;
     RECT  3.924 5.341 5.397 5.701 ;
     RECT  14.832 4.747 15.426 5.8 ;
     RECT  3.924 5.701 5.454 5.809 ;
     RECT  12.528 4.919 13.842 5.851 ;
     RECT  6.732 5.549 11.79 5.881 ;
     RECT  12.528 5.851 13.914 5.881 ;
     RECT  0.216 5.644 0.306 5.933 ;
     RECT  3.924 5.809 5.778 5.999 ;
     RECT  6.732 5.881 13.914 5.999 ;
     RECT  3.924 5.999 5.67 6.029 ;
     RECT  2.304 5.117 2.697 6.079 ;
     RECT  14.832 5.8 15.462 6.143 ;
     RECT  2.304 6.079 3.15 6.151 ;
     RECT  3.924 6.029 5.598 6.151 ;
     RECT  16.524 6.235 16.542 6.283 ;
     RECT  0.54 6.079 0.558 6.379 ;
     RECT  16.524 6.283 17.154 6.413 ;
     RECT  0.54 6.379 0.63 6.449 ;
     RECT  17.064 6.413 17.154 6.605 ;
     RECT  6.804 5.999 13.914 6.655 ;
     RECT  14.832 6.143 15.426 6.655 ;
     RECT  6.804 6.655 15.426 6.853 ;
     RECT  2.304 6.151 5.598 6.893 ;
     RECT  5.04 6.893 5.598 6.961 ;
     RECT  5.04 6.961 5.886 7.051 ;
     RECT  6.624 6.853 15.426 7.051 ;
     RECT  0.54 6.449 0.558 7.085 ;
     RECT  5.04 7.051 15.426 7.151 ;
     RECT  5.04 7.151 5.958 7.349 ;
     RECT  2.304 6.893 4.122 7.373 ;
     RECT  0.216 7.291 0.306 7.436 ;
     RECT  2.304 7.373 4.05 7.469 ;
     RECT  0.252 7.436 0.27 7.613 ;
     RECT  6.804 7.151 15.426 7.799 ;
     RECT  16.524 7.147 16.542 7.819 ;
     RECT  16.524 7.819 17.082 7.861 ;
     RECT  5.04 7.349 5.778 7.889 ;
     RECT  16.524 7.861 17.154 7.901 ;
     RECT  7.092 7.799 15.426 7.925 ;
     RECT  2.304 7.469 4.014 7.949 ;
     RECT  5.04 7.889 5.706 8.041 ;
     RECT  16.524 7.901 16.542 8.045 ;
     RECT  4.86 8.041 5.706 8.131 ;
     RECT  2.304 7.949 2.826 8.141 ;
     RECT  3.708 7.949 4.014 8.267 ;
     RECT  4.788 8.131 5.706 8.401 ;
     RECT  14.832 7.925 15.426 8.545 ;
     RECT  7.092 7.925 13.914 8.671 ;
     RECT  4.104 8.401 5.706 8.699 ;
     RECT  2.412 8.141 2.826 8.707 ;
     RECT  7.056 8.671 13.914 8.731 ;
     RECT  0.252 8.635 0.27 8.827 ;
     RECT  0.252 8.827 0.342 8.879 ;
     RECT  0.252 8.879 0.27 8.909 ;
     RECT  14.832 8.545 15.462 8.909 ;
     RECT  2.412 8.707 3.186 8.969 ;
     RECT  4.104 8.699 5.598 8.969 ;
     RECT  6.444 8.731 13.914 8.971 ;
     RECT  14.832 8.909 15.426 9.041 ;
     RECT  2.412 8.969 2.697 9.121 ;
     RECT  4.104 8.969 4.122 9.121 ;
     RECT  6.444 8.971 14.094 9.149 ;
     RECT  16.524 9.163 16.542 9.403 ;
     RECT  3.744 9.121 4.122 9.751 ;
     RECT  5.004 8.969 5.598 9.751 ;
     RECT  3.744 9.751 5.598 9.787 ;
     RECT  6.444 9.149 13.554 9.787 ;
     RECT  14.832 9.041 14.922 9.835 ;
     RECT  3.744 9.787 13.554 9.859 ;
     RECT  0.252 9.691 0.27 9.869 ;
     RECT  14.832 9.835 15.426 9.887 ;
     RECT  3.636 9.859 13.554 9.923 ;
     RECT  6.444 9.923 13.554 9.931 ;
     RECT  3.636 9.923 5.397 10.049 ;
     RECT  2.304 9.121 2.697 10.075 ;
     RECT  6.444 9.931 14.058 10.193 ;
     RECT  2.232 10.075 2.697 10.253 ;
     RECT  6.444 10.193 13.842 10.253 ;
     RECT  2.268 10.253 2.697 10.291 ;
     RECT  16.524 9.403 16.578 10.315 ;
     RECT  2.268 10.291 2.862 10.435 ;
     RECT  2.268 10.435 2.898 10.561 ;
     RECT  14.832 9.887 14.922 10.651 ;
     RECT  2.268 10.561 2.97 10.661 ;
     RECT  4.176 10.049 5.397 10.685 ;
     RECT  16.524 10.315 17.154 10.733 ;
     RECT  16.524 10.733 17.082 10.781 ;
     RECT  4.176 10.685 4.374 10.831 ;
     RECT  0.396 10.843 0.414 10.939 ;
     RECT  3.996 10.831 4.374 11.011 ;
     RECT  5.115 10.685 5.397 11.101 ;
     RECT  6.84 10.253 13.842 11.101 ;
     RECT  6.84 11.101 13.914 11.131 ;
     RECT  6.804 11.131 13.914 11.165 ;
     RECT  5.115 11.101 5.454 11.209 ;
     RECT  0.288 10.939 0.414 11.227 ;
     RECT  2.268 10.661 2.898 11.399 ;
     RECT  0.252 11.227 0.414 11.405 ;
     RECT  5.115 11.209 5.526 11.471 ;
     RECT  14.832 10.651 15.426 11.479 ;
     RECT  6.804 11.165 13.842 11.515 ;
     RECT  2.304 11.399 2.898 11.551 ;
     RECT  3.636 11.011 4.374 11.551 ;
     RECT  16.524 10.781 16.542 11.611 ;
     RECT  16.524 11.611 17.082 11.641 ;
     RECT  14.616 11.479 15.426 11.669 ;
     RECT  16.524 11.641 17.154 11.693 ;
     RECT  14.832 11.669 15.426 11.741 ;
     RECT  2.304 11.551 4.374 11.749 ;
     RECT  5.115 11.471 5.49 11.749 ;
     RECT  14.832 11.741 15.39 11.777 ;
     RECT  6.264 11.515 13.842 11.911 ;
     RECT  2.304 11.749 5.49 12.331 ;
     RECT  6.264 11.911 13.986 12.331 ;
     RECT  16.524 11.693 16.542 12.427 ;
     RECT  16.524 12.427 17.082 12.451 ;
     RECT  2.304 12.331 13.986 12.479 ;
     RECT  16.524 12.451 17.154 12.509 ;
     RECT  0.54 11.551 0.558 12.557 ;
     RECT  14.832 11.777 14.886 12.571 ;
     RECT  6.3 12.479 13.986 12.631 ;
     RECT  14.832 12.571 15.426 12.631 ;
     RECT  2.304 12.479 5.397 13.019 ;
     RECT  16.524 12.509 16.542 13.133 ;
     RECT  0.252 13.339 0.27 13.532 ;
     RECT  6.3 12.631 15.426 13.675 ;
     RECT  2.34 13.019 5.397 13.819 ;
     RECT  2.304 13.819 5.397 13.829 ;
     RECT  6.264 13.675 15.426 13.829 ;
     RECT  6.264 13.829 13.914 13.865 ;
     RECT  17.136 13.864 17.154 13.873 ;
     RECT  6.264 13.865 11.574 13.901 ;
     RECT  0.288 13.867 0.306 14.011 ;
     RECT  0.288 14.011 0.414 14.141 ;
     RECT  6.264 13.901 6.282 14.189 ;
     RECT  14.832 13.829 15.426 14.441 ;
     RECT  2.304 13.829 4.014 14.611 ;
     RECT  7.128 13.901 11.574 14.611 ;
     RECT  12.564 13.865 13.914 14.611 ;
     RECT  2.16 14.611 4.014 14.669 ;
     RECT  2.268 14.669 4.014 14.675 ;
     RECT  7.128 14.611 13.914 14.675 ;
     RECT  4.788 13.829 5.397 14.677 ;
     RECT  4.788 14.677 5.886 14.731 ;
     RECT  17.064 13.873 17.154 14.783 ;
     RECT  17.064 14.783 17.082 14.813 ;
     RECT  16.524 14.875 16.578 15.053 ;
     RECT  2.268 14.675 3.042 15.101 ;
     RECT  4.032 14.731 5.886 15.179 ;
     RECT  16.56 15.053 16.578 15.287 ;
     RECT  5.115 15.179 5.886 15.295 ;
     RECT  7.2 14.675 13.914 15.307 ;
     RECT  14.868 14.441 15.426 15.307 ;
     RECT  5.115 15.295 6.282 15.341 ;
     RECT  5.115 15.341 5.454 15.359 ;
     RECT  7.2 15.307 15.426 15.449 ;
     RECT  2.304 15.101 3.042 15.565 ;
     RECT  6.264 15.341 6.282 15.595 ;
     RECT  7.2 15.449 13.842 15.595 ;
     RECT  2.304 15.565 3.078 15.601 ;
     RECT  4.032 15.179 4.05 15.601 ;
     RECT  2.304 15.601 4.05 15.961 ;
     RECT  5.115 15.359 5.397 15.961 ;
     RECT  16.524 15.931 16.542 16.025 ;
     RECT  0.252 15.211 0.27 16.253 ;
     RECT  6.264 15.595 13.842 16.259 ;
     RECT  14.796 15.449 15.426 16.259 ;
     RECT  2.304 15.961 5.397 16.303 ;
     RECT  6.264 16.259 11.718 16.303 ;
     RECT  12.6 16.259 13.842 16.303 ;
     RECT  14.832 16.259 15.426 16.403 ;
     RECT  12.6 16.303 13.878 16.501 ;
     RECT  2.304 16.303 11.718 16.589 ;
     RECT  5.115 16.589 11.718 16.829 ;
     RECT  17.136 16.843 17.154 16.879 ;
     RECT  17.064 16.879 17.154 16.987 ;
     RECT  2.304 16.589 4.338 17.069 ;
     RECT  12.6 16.501 13.914 17.149 ;
     RECT  14.832 16.403 14.922 17.149 ;
     RECT  12.6 17.149 14.922 17.179 ;
     RECT  6.804 16.829 11.718 17.221 ;
     RECT  12.6 17.179 15.426 17.221 ;
     RECT  16.524 16.987 17.154 17.249 ;
     RECT  2.304 17.069 3.15 17.275 ;
     RECT  2.268 17.275 3.15 17.339 ;
     RECT  5.115 16.829 5.814 17.339 ;
     RECT  3.924 17.069 4.338 17.419 ;
     RECT  5.115 17.339 5.67 17.419 ;
     RECT  6.804 17.221 15.426 17.456 ;
     RECT  6.84 17.456 15.426 17.501 ;
     RECT  3.924 17.419 5.67 17.519 ;
     RECT  7.056 17.501 15.426 17.609 ;
     RECT  7.056 17.609 11.466 17.645 ;
     RECT  5.115 17.519 5.67 17.681 ;
     RECT  7.056 17.645 11.214 17.693 ;
     RECT  17.064 17.249 17.154 17.951 ;
     RECT  3.924 17.519 4.338 17.981 ;
     RECT  17.064 17.951 17.082 17.981 ;
     RECT  2.304 17.339 3.15 18.031 ;
     RECT  3.924 17.981 4.158 18.031 ;
     RECT  5.115 17.681 5.397 18.301 ;
     RECT  2.304 18.031 4.158 18.419 ;
     RECT  4.968 18.301 5.397 18.419 ;
     RECT  12.6 17.609 15.426 18.419 ;
     RECT  5.04 18.419 5.397 18.463 ;
     RECT  7.164 17.693 11.214 18.499 ;
     RECT  14.832 18.419 15.426 18.563 ;
     RECT  5.04 18.463 5.634 18.571 ;
     RECT  7.164 18.499 11.862 18.571 ;
     RECT  12.6 18.419 13.914 18.571 ;
     RECT  14.832 18.563 14.994 18.605 ;
     RECT  5.04 18.571 5.706 18.689 ;
     RECT  2.304 18.419 4.122 18.859 ;
     RECT  2.016 18.859 4.122 19.037 ;
     RECT  7.164 18.571 13.914 19.147 ;
     RECT  2.304 19.037 4.122 19.201 ;
     RECT  5.04 18.689 5.397 19.201 ;
     RECT  6.624 19.147 13.914 19.265 ;
     RECT  16.56 18.811 16.578 19.291 ;
     RECT  2.304 19.201 5.397 19.337 ;
     RECT  6.804 19.265 13.914 19.381 ;
     RECT  14.832 18.605 14.886 19.381 ;
     RECT  6.804 19.381 14.886 19.499 ;
     RECT  6.804 19.499 13.914 19.517 ;
     RECT  14.796 19.499 14.886 19.531 ;
     RECT  6.804 19.517 11.718 19.643 ;
     RECT  16.524 19.291 16.578 19.661 ;
     RECT  3.96 19.337 5.397 19.769 ;
     RECT  6.804 19.643 11.574 20.083 ;
     RECT  14.796 19.531 15.426 20.183 ;
     RECT  4.068 19.769 5.397 20.191 ;
     RECT  4.068 20.191 5.778 20.309 ;
     RECT  12.564 19.517 13.914 20.317 ;
     RECT  4.068 20.309 5.397 20.333 ;
     RECT  12.456 20.317 13.914 20.353 ;
     RECT  2.304 19.337 2.862 20.461 ;
     RECT  6.552 20.083 11.574 20.489 ;
     RECT  16.524 19.661 16.542 20.489 ;
     RECT  2.304 20.461 2.97 20.551 ;
     RECT  7.164 20.489 11.574 20.551 ;
     RECT  12.384 20.353 13.914 20.551 ;
     RECT  14.832 20.183 15.426 20.651 ;
     RECT  2.196 20.551 2.97 20.669 ;
     RECT  4.068 20.333 4.266 20.683 ;
     RECT  2.304 20.669 2.97 20.695 ;
     RECT  4.032 20.683 4.266 20.695 ;
     RECT  17.064 20.635 17.154 20.885 ;
     RECT  17.064 20.885 17.082 20.909 ;
     RECT  2.304 20.695 4.266 20.957 ;
     RECT  0.252 19.387 0.27 21.101 ;
     RECT  7.164 20.551 13.914 21.115 ;
     RECT  2.304 20.957 3.078 21.119 ;
     RECT  2.304 21.119 2.79 21.155 ;
     RECT  15.984 20.971 16.002 21.191 ;
     RECT  7.164 21.115 13.95 21.271 ;
     RECT  14.832 20.651 14.85 21.271 ;
     RECT  3.852 20.957 4.266 21.361 ;
     RECT  5.112 20.333 5.397 21.361 ;
     RECT  7.164 21.271 14.85 21.403 ;
     RECT  1.152 21.259 1.17 21.437 ;
     RECT  7.164 21.403 15.426 21.461 ;
     RECT  3.852 21.361 5.397 21.505 ;
     RECT  7.164 21.461 13.95 21.539 ;
     RECT  3.852 21.505 5.994 21.659 ;
     RECT  14.832 21.461 14.85 21.731 ;
     RECT  7.164 21.539 13.914 21.739 ;
     RECT  2.304 21.155 2.697 21.901 ;
     RECT  16.524 21.835 16.542 22.001 ;
     RECT  16.56 22.027 16.578 22.109 ;
     RECT  3.852 21.659 5.397 22.199 ;
     RECT  7.128 21.739 13.914 22.207 ;
     RECT  7.02 22.207 13.914 22.279 ;
     RECT  7.02 22.279 14.094 22.309 ;
     RECT  6.84 22.309 14.094 22.349 ;
     RECT  3.852 22.199 4.05 22.351 ;
     RECT  2.304 21.901 2.754 22.441 ;
     RECT  3.672 22.351 4.05 22.441 ;
     RECT  15.408 22.267 15.426 22.459 ;
     RECT  2.304 22.441 4.05 22.469 ;
     RECT  6.228 22.507 6.246 22.577 ;
     RECT  2.304 22.469 3.942 22.811 ;
     RECT  5.076 22.199 5.397 22.855 ;
     RECT  3.924 22.811 3.942 23.009 ;
     RECT  6.984 22.349 14.094 23.069 ;
     RECT  7.128 23.069 14.094 23.117 ;
     RECT  7.128 23.117 11.826 23.165 ;
     RECT  12.564 23.117 14.094 23.251 ;
     RECT  14.832 22.459 15.426 23.251 ;
     RECT  2.304 22.811 3.114 23.315 ;
     RECT  7.128 23.165 11.79 23.315 ;
     RECT  5.076 22.855 5.562 23.431 ;
     RECT  16.524 22.891 16.542 23.621 ;
     RECT  5.004 23.431 5.562 23.665 ;
     RECT  5.004 23.665 5.994 23.701 ;
     RECT  7.416 23.315 11.79 23.729 ;
     RECT  4.896 23.701 5.994 23.819 ;
     RECT  7.416 23.729 11.682 23.819 ;
     RECT  2.304 23.315 3.078 23.827 ;
     RECT  4.896 23.819 5.454 23.891 ;
     RECT  2.196 23.827 3.078 23.933 ;
     RECT  1.152 23.707 1.17 23.995 ;
     RECT  4.104 23.791 4.122 24.061 ;
     RECT  12.564 23.251 15.426 24.088 ;
     RECT  1.152 23.995 1.278 24.125 ;
     RECT  12.492 24.088 15.426 24.161 ;
     RECT  2.304 23.933 3.078 24.187 ;
     RECT  1.152 24.125 1.242 24.221 ;
     RECT  14.616 24.161 15.426 24.233 ;
     RECT  4.104 24.061 4.158 24.241 ;
     RECT  4.896 23.891 5.397 24.241 ;
     RECT  12.492 24.161 13.842 24.269 ;
     RECT  2.304 24.187 3.294 24.331 ;
     RECT  4.104 24.241 5.397 24.331 ;
     RECT  7.416 23.819 11.502 24.359 ;
     RECT  7.416 24.359 11.43 24.367 ;
     RECT  1.224 24.221 1.242 24.413 ;
     RECT  2.304 24.331 5.397 24.467 ;
     RECT  7.38 24.367 11.43 24.523 ;
     RECT  7.272 24.523 11.43 24.637 ;
     RECT  16.524 24.379 16.542 24.667 ;
     RECT  7.164 24.637 11.43 24.701 ;
     RECT  16.524 24.667 16.65 24.709 ;
     RECT  16.452 24.709 16.65 24.749 ;
     RECT  0.396 24.859 0.414 24.955 ;
     RECT  0.288 24.955 0.414 24.989 ;
     RECT  4.824 24.467 5.397 25.007 ;
     RECT  0.288 24.989 0.306 25.085 ;
     RECT  14.616 24.233 14.634 25.099 ;
     RECT  15.408 24.233 15.426 25.099 ;
     RECT  7.236 24.701 11.43 25.177 ;
     RECT  16.524 24.749 16.65 25.291 ;
     RECT  2.304 24.467 4.014 25.313 ;
     RECT  7.236 25.177 11.574 25.321 ;
     RECT  12.492 24.269 13.806 25.321 ;
     RECT  14.616 25.099 15.426 25.321 ;
     RECT  7.236 25.321 15.426 25.435 ;
     RECT  1.26 25.387 1.278 25.483 ;
     RECT  1.152 25.483 1.278 25.517 ;
     RECT  2.304 25.313 3.258 25.565 ;
     RECT  1.152 25.517 1.17 25.661 ;
     RECT  6.264 25.681 6.282 25.753 ;
     RECT  7.128 25.435 15.426 25.753 ;
     RECT  6.264 25.753 15.426 25.757 ;
     RECT  16.524 25.291 17.154 25.805 ;
     RECT  3.996 25.313 4.014 25.819 ;
     RECT  4.968 25.007 5.397 25.819 ;
     RECT  2.304 25.565 2.934 25.951 ;
     RECT  3.996 25.819 5.397 25.979 ;
     RECT  2.196 25.951 2.934 26.045 ;
     RECT  5.004 25.979 5.397 26.189 ;
     RECT  3.996 25.979 4.014 26.221 ;
     RECT  2.304 26.045 2.934 26.299 ;
     RECT  3.888 26.221 4.014 26.299 ;
     RECT  5.115 26.189 5.397 26.401 ;
     RECT  5.115 26.401 5.67 26.491 ;
     RECT  6.768 25.757 13.914 26.491 ;
     RECT  5.115 26.491 13.914 26.519 ;
     RECT  16.524 25.805 16.542 26.539 ;
     RECT  16.524 26.539 17.154 26.591 ;
     RECT  16.524 26.591 17.082 26.621 ;
     RECT  0.252 26.587 0.27 26.765 ;
     RECT  6.228 26.519 13.914 26.789 ;
     RECT  2.304 26.299 4.014 26.869 ;
     RECT  2.304 26.869 4.266 26.941 ;
     RECT  2.268 26.941 4.266 27.031 ;
     RECT  14.832 25.757 15.426 27.131 ;
     RECT  14.832 27.131 14.886 27.203 ;
     RECT  5.115 26.519 5.454 27.329 ;
     RECT  16.524 26.621 16.542 27.365 ;
     RECT  5.115 27.329 5.397 27.445 ;
     RECT  2.268 27.031 4.338 27.481 ;
     RECT  5.076 27.445 5.397 27.481 ;
     RECT  2.268 27.481 5.397 27.671 ;
     RECT  1.152 27.739 1.17 27.787 ;
     RECT  6.804 26.789 13.914 27.841 ;
     RECT  17.064 27.595 17.154 27.905 ;
     RECT  17.136 27.905 17.154 27.917 ;
     RECT  15.984 27.913 16.002 27.965 ;
     RECT  6.804 27.841 14.022 28.147 ;
     RECT  14.832 27.203 14.85 28.171 ;
     RECT  14.832 28.171 14.922 28.183 ;
     RECT  6.696 28.147 14.022 28.408 ;
     RECT  1.152 27.787 1.278 28.445 ;
     RECT  6.624 28.408 14.022 28.445 ;
     RECT  6.696 28.445 14.022 28.493 ;
     RECT  14.832 28.183 15.462 28.493 ;
     RECT  2.304 27.671 5.397 28.525 ;
     RECT  6.768 28.493 14.022 28.651 ;
     RECT  2.304 28.525 5.922 28.679 ;
     RECT  0.396 28.651 0.414 28.747 ;
     RECT  0.216 28.747 0.414 28.859 ;
     RECT  2.304 28.679 5.397 28.949 ;
     RECT  0.252 28.859 0.414 28.973 ;
     RECT  0.252 28.973 0.27 29.069 ;
     RECT  2.304 28.949 2.826 29.083 ;
     RECT  2.232 29.083 2.826 29.129 ;
     RECT  14.832 28.493 14.85 29.227 ;
     RECT  6.768 28.651 14.094 29.291 ;
     RECT  6.804 29.291 14.094 29.371 ;
     RECT  14.832 29.227 15.426 29.371 ;
     RECT  3.6 28.949 5.397 29.489 ;
     RECT  6.804 29.371 15.426 29.561 ;
     RECT  16.524 28.957 16.542 29.561 ;
     RECT  2.304 29.129 2.826 29.731 ;
     RECT  3.852 29.489 5.397 29.731 ;
     RECT  6.84 29.561 15.426 29.789 ;
     RECT  2.304 29.731 2.862 29.831 ;
     RECT  3.852 29.731 6.066 29.939 ;
     RECT  0.216 29.992 0.234 30.029 ;
     RECT  3.852 29.939 5.598 30.029 ;
     RECT  6.84 29.789 13.842 30.029 ;
     RECT  2.304 29.831 2.826 30.125 ;
     RECT  6.84 30.029 13.806 30.209 ;
     RECT  3.852 30.029 5.49 30.271 ;
     RECT  6.912 30.209 13.806 30.413 ;
     RECT  16.524 30.283 16.542 30.443 ;
     RECT  3.708 30.271 5.49 30.893 ;
     RECT  14.832 29.789 15.426 30.907 ;
     RECT  14.832 30.907 15.462 30.919 ;
     RECT  2.304 30.125 2.754 30.955 ;
     RECT  3.708 30.893 4.266 30.991 ;
     RECT  14.58 30.919 15.462 31.081 ;
     RECT  6.912 30.413 13.734 31.099 ;
     RECT  6.84 31.099 13.734 31.109 ;
     RECT  14.508 31.081 15.462 31.133 ;
     RECT  14.832 31.133 15.462 31.181 ;
     RECT  5.04 30.893 5.49 31.189 ;
     RECT  2.304 30.955 2.862 31.195 ;
     RECT  3.636 30.991 4.266 31.195 ;
     RECT  12.492 31.109 13.734 31.195 ;
     RECT  5.04 31.189 5.742 31.229 ;
     RECT  5.115 31.229 5.742 31.379 ;
     RECT  14.832 31.181 15.426 31.523 ;
     RECT  6.84 31.109 11.754 31.675 ;
     RECT  14.868 31.523 15.426 31.721 ;
     RECT  12.492 31.195 14.094 31.793 ;
     RECT  6.768 31.675 11.754 31.915 ;
     RECT  5.115 31.379 5.397 31.999 ;
     RECT  6.264 31.915 11.754 32.011 ;
     RECT  12.492 31.793 13.986 32.011 ;
     RECT  15.372 31.721 15.426 32.027 ;
     RECT  2.304 31.195 4.266 32.071 ;
     RECT  0.252 30.763 0.27 32.141 ;
     RECT  2.304 32.071 4.302 32.161 ;
     RECT  5.076 31.999 5.397 32.161 ;
     RECT  6.264 32.011 13.986 32.297 ;
     RECT  16.524 32.155 16.542 32.491 ;
     RECT  6.588 32.297 13.986 32.495 ;
     RECT  15.984 32.491 16.542 32.495 ;
     RECT  6.696 32.495 13.986 32.539 ;
     RECT  6.696 32.539 14.202 32.575 ;
     RECT  6.696 32.575 14.382 32.587 ;
     RECT  2.304 32.161 5.397 32.639 ;
     RECT  15.984 32.495 16.002 32.639 ;
     RECT  4.14 32.639 5.397 32.765 ;
     RECT  6.696 32.587 14.85 32.801 ;
     RECT  2.304 32.639 3.366 32.875 ;
     RECT  12.168 32.801 14.31 33.071 ;
     RECT  12.168 33.071 13.986 33.101 ;
     RECT  0.216 33.151 0.234 33.197 ;
     RECT  6.696 32.801 11.43 33.241 ;
     RECT  6.588 33.241 11.43 33.269 ;
     RECT  4.212 32.765 5.397 33.341 ;
     RECT  6.588 33.269 11.394 33.385 ;
     RECT  2.268 32.875 3.366 33.511 ;
     RECT  4.212 33.341 4.23 33.511 ;
     RECT  15.408 32.827 15.426 33.511 ;
     RECT  16.524 33.451 16.542 33.511 ;
     RECT  2.268 33.511 4.23 33.533 ;
     RECT  15.408 33.511 16.542 33.581 ;
     RECT  12.168 33.101 13.842 33.643 ;
     RECT  2.304 33.533 4.23 33.647 ;
     RECT  6.228 33.385 11.394 33.691 ;
     RECT  15.408 33.581 15.426 33.691 ;
     RECT  6.192 33.691 11.394 33.845 ;
     RECT  5.115 33.341 5.397 33.853 ;
     RECT  16.524 33.581 16.542 33.881 ;
     RECT  12.132 33.643 13.842 33.889 ;
     RECT  14.904 33.691 15.426 34.075 ;
     RECT  5.115 33.853 5.418 34.079 ;
     RECT  6.264 33.845 11.394 34.195 ;
     RECT  12.132 33.889 13.878 34.195 ;
     RECT  14.832 34.075 15.426 34.231 ;
     RECT  14.616 34.231 15.426 34.349 ;
     RECT  6.264 34.195 13.878 34.385 ;
     RECT  2.304 33.647 4.158 34.421 ;
     RECT  6.264 34.385 11.286 34.421 ;
     RECT  3.708 34.421 4.158 34.465 ;
     RECT  5.115 34.079 5.397 34.465 ;
     RECT  2.304 34.421 2.862 34.555 ;
     RECT  2.268 34.555 2.862 34.619 ;
     RECT  12.348 34.385 13.878 34.699 ;
     RECT  16.524 34.699 16.542 34.771 ;
     RECT  3.708 34.465 5.397 34.889 ;
     RECT  4.248 34.889 5.397 35.261 ;
     RECT  12.348 34.699 13.95 35.339 ;
     RECT  6.264 34.421 11.178 35.357 ;
     RECT  6.804 35.357 11.178 35.419 ;
     RECT  16.524 34.771 16.578 35.419 ;
     RECT  16.524 35.419 17.082 35.437 ;
     RECT  6.804 35.419 11.286 35.467 ;
     RECT  14.832 34.349 15.426 35.473 ;
     RECT  16.524 35.437 17.154 35.501 ;
     RECT  16.524 35.501 16.542 35.573 ;
     RECT  4.248 35.261 4.374 35.671 ;
     RECT  4.032 35.671 4.374 35.807 ;
     RECT  6.804 35.467 11.538 35.845 ;
     RECT  12.348 35.339 13.626 35.845 ;
     RECT  5.115 35.261 5.397 35.941 ;
     RECT  2.304 34.619 2.862 36.091 ;
     RECT  2.304 36.091 3.114 36.121 ;
     RECT  6.804 35.845 13.626 36.121 ;
     RECT  14.508 35.473 15.426 36.121 ;
     RECT  2.304 36.121 3.186 36.239 ;
     RECT  6.264 36.121 15.426 36.311 ;
     RECT  5.115 35.941 5.454 36.589 ;
     RECT  6.264 36.311 14.922 36.589 ;
     RECT  3.996 36.379 4.014 36.616 ;
     RECT  5.115 36.589 14.922 36.625 ;
     RECT  15.984 36.379 16.002 36.653 ;
     RECT  3.744 36.616 4.014 36.751 ;
     RECT  5.004 36.625 14.922 36.779 ;
     RECT  14.832 36.779 14.922 36.887 ;
     RECT  14.904 36.887 14.922 36.923 ;
     RECT  5.004 36.779 13.986 37.049 ;
     RECT  0.54 36.931 0.558 37.085 ;
     RECT  16.488 37.003 16.542 37.093 ;
     RECT  3.744 36.751 4.158 37.201 ;
     RECT  5.004 37.049 13.914 37.201 ;
     RECT  16.488 37.093 16.578 37.229 ;
     RECT  16.524 37.229 16.578 37.373 ;
     RECT  2.304 36.239 2.934 37.471 ;
     RECT  3.744 37.201 13.914 37.471 ;
     RECT  2.304 37.471 13.914 37.589 ;
     RECT  16.524 37.373 16.542 37.625 ;
     RECT  15.408 37.243 15.426 37.633 ;
     RECT  15.408 37.633 15.462 37.669 ;
     RECT  14.904 37.669 15.462 37.867 ;
     RECT  14.832 37.867 15.462 37.997 ;
     RECT  2.304 37.589 5.706 38.201 ;
     RECT  6.516 37.589 13.914 38.443 ;
     RECT  14.832 37.997 15.426 38.443 ;
     RECT  3.888 38.201 5.706 38.507 ;
     RECT  6.516 38.443 15.426 38.551 ;
     RECT  6.192 38.551 15.426 38.669 ;
     RECT  6.408 38.669 15.426 38.705 ;
     RECT  6.408 38.705 13.95 38.717 ;
     RECT  14.832 38.705 15.426 38.765 ;
     RECT  0.252 38.875 0.27 39.053 ;
     RECT  6.984 38.717 13.95 39.053 ;
     RECT  3.888 38.507 5.397 39.055 ;
     RECT  3.744 39.055 5.397 39.056 ;
     RECT  6.984 39.053 13.914 39.149 ;
     RECT  2.304 38.201 2.934 39.181 ;
     RECT  3.744 39.056 4.266 39.181 ;
     RECT  2.304 39.181 4.266 39.209 ;
     RECT  2.304 39.209 3.042 39.281 ;
     RECT  4.032 39.209 4.266 39.281 ;
     RECT  2.304 39.281 2.826 39.293 ;
     RECT  14.832 38.765 14.85 39.523 ;
     RECT  16.524 39.355 16.542 39.587 ;
     RECT  5.115 39.056 5.397 39.631 ;
     RECT  5.115 39.631 5.886 39.821 ;
     RECT  4.14 39.281 4.266 39.901 ;
     RECT  5.115 39.821 5.49 39.901 ;
     RECT  7.236 39.149 13.914 40.123 ;
     RECT  6.696 40.123 13.914 40.135 ;
     RECT  2.304 39.293 2.697 40.171 ;
     RECT  4.14 39.901 5.49 40.289 ;
     RECT  6.696 40.135 13.95 40.289 ;
     RECT  4.14 40.289 5.397 40.397 ;
     RECT  6.696 40.289 13.842 40.397 ;
     RECT  4.14 40.397 4.374 40.403 ;
     RECT  2.304 40.171 3.114 40.411 ;
     RECT  7.2 40.397 13.842 40.469 ;
     RECT  2.304 40.411 3.366 40.531 ;
     RECT  14.832 39.523 15.426 40.703 ;
     RECT  12.492 40.469 13.842 40.901 ;
     RECT  7.2 40.469 11.502 40.937 ;
     RECT  7.2 40.937 11.106 41.009 ;
     RECT  2.304 40.531 4.05 41.099 ;
     RECT  5.115 40.397 5.397 41.251 ;
     RECT  12.492 40.901 13.662 41.251 ;
     RECT  3.996 41.099 4.05 41.405 ;
     RECT  6.192 40.873 6.354 41.405 ;
     RECT  4.032 41.405 4.05 41.467 ;
     RECT  4.824 41.251 5.397 41.467 ;
     RECT  7.2 41.009 11.034 41.683 ;
     RECT  4.032 41.467 5.397 41.755 ;
     RECT  6.804 41.683 11.034 41.755 ;
     RECT  12.42 41.251 13.662 41.755 ;
     RECT  2.304 41.099 2.97 41.881 ;
     RECT  14.832 40.703 14.994 41.899 ;
     RECT  4.032 41.755 5.562 41.909 ;
     RECT  2.304 41.881 3.15 41.944 ;
     RECT  12.348 41.755 13.842 41.947 ;
     RECT  2.304 41.944 3.222 41.981 ;
     RECT  6.804 41.755 11.358 42.025 ;
     RECT  12.276 41.947 13.842 42.025 ;
     RECT  0.252 41.947 0.27 42.125 ;
     RECT  16.524 41.227 16.542 42.215 ;
     RECT  14.832 41.899 15.426 42.259 ;
     RECT  6.804 42.025 13.842 42.283 ;
     RECT  6.732 42.283 13.842 42.331 ;
     RECT  4.032 41.909 5.397 42.457 ;
     RECT  6.192 42.331 13.842 42.601 ;
     RECT  14.616 42.259 15.426 42.601 ;
     RECT  3.816 42.457 5.397 42.727 ;
     RECT  6.192 42.601 15.426 42.727 ;
     RECT  2.304 41.981 2.826 42.961 ;
     RECT  2.304 42.961 3.042 43.099 ;
     RECT  3.816 42.727 15.426 43.099 ;
     RECT  2.304 43.099 15.426 43.147 ;
     RECT  2.232 43.147 15.426 43.259 ;
     RECT  0.216 43.303 0.234 43.517 ;
     RECT  2.304 43.259 15.426 43.529 ;
     RECT  2.304 43.529 4.266 43.799 ;
     RECT  5.115 43.529 15.426 43.853 ;
     RECT  16.524 43.099 16.542 44.141 ;
     RECT  2.304 43.799 4.05 44.177 ;
     RECT  0.252 44.011 0.27 44.189 ;
     RECT  2.304 44.177 4.014 44.203 ;
     RECT  7.344 43.853 15.426 44.203 ;
     RECT  5.115 43.853 6.21 44.213 ;
     RECT  2.268 44.203 4.014 44.249 ;
     RECT  7.344 44.203 15.462 44.339 ;
     RECT  17.064 44.299 17.082 44.347 ;
     RECT  14.832 44.339 15.462 44.411 ;
     RECT  5.115 44.213 5.397 44.761 ;
     RECT  7.344 44.339 13.95 44.789 ;
     RECT  2.304 44.249 4.014 44.879 ;
     RECT  6.12 44.213 6.21 44.959 ;
     RECT  6.12 44.959 6.462 45.005 ;
     RECT  5.004 44.761 5.397 45.031 ;
     RECT  2.304 44.879 3.366 45.257 ;
     RECT  14.832 44.411 15.066 45.259 ;
     RECT  4.464 45.031 5.397 45.301 ;
     RECT  12.528 44.789 13.95 45.301 ;
     RECT  14.832 45.259 15.426 45.301 ;
     RECT  2.304 45.257 3.186 45.355 ;
     RECT  2.268 45.355 3.186 45.419 ;
     RECT  7.344 44.789 11.466 45.427 ;
     RECT  6.948 45.427 11.466 45.485 ;
     RECT  12.528 45.301 15.426 45.491 ;
     RECT  17.064 44.347 17.154 45.563 ;
     RECT  17.064 45.563 17.082 45.581 ;
     RECT  6.984 45.485 11.466 45.595 ;
     RECT  12.528 45.491 14.85 45.595 ;
     RECT  4.464 45.301 5.886 45.661 ;
     RECT  3.996 45.661 5.886 45.739 ;
     RECT  6.984 45.595 14.85 45.761 ;
     RECT  0.252 45.595 0.27 45.773 ;
     RECT  7.056 45.761 14.85 45.965 ;
     RECT  2.304 45.419 3.186 46.039 ;
     RECT  3.996 45.739 6.03 46.039 ;
     RECT  7.236 45.965 14.85 46.067 ;
     RECT  14.832 46.067 14.85 46.219 ;
     RECT  7.236 46.067 13.734 46.253 ;
     RECT  16.524 46.075 16.542 46.373 ;
     RECT  14.832 46.219 15.03 46.397 ;
     RECT  2.304 46.039 6.03 46.499 ;
     RECT  2.304 46.499 5.397 46.651 ;
     RECT  2.124 46.651 5.397 46.841 ;
     RECT  17.064 46.795 17.154 46.841 ;
     RECT  17.064 46.841 17.082 46.877 ;
     RECT  7.272 46.253 13.734 46.939 ;
     RECT  14.832 46.397 14.958 46.939 ;
     RECT  6.228 46.843 6.246 47.083 ;
     RECT  7.272 46.939 14.958 47.083 ;
     RECT  0.54 46.921 0.558 47.119 ;
     RECT  2.304 46.841 5.397 47.309 ;
     RECT  6.228 47.083 14.958 47.371 ;
     RECT  16.524 47.131 16.542 47.453 ;
     RECT  6.192 47.371 15.426 47.579 ;
     RECT  7.128 47.579 15.426 47.651 ;
     RECT  17.064 47.659 17.082 47.695 ;
     RECT  7.128 47.651 14.886 47.723 ;
     RECT  6.192 47.579 6.39 47.849 ;
     RECT  7.128 47.723 13.77 47.849 ;
     RECT  6.192 47.849 6.21 47.885 ;
     RECT  0.504 47.119 0.558 47.933 ;
     RECT  4.788 47.309 5.397 48.001 ;
     RECT  2.304 47.309 3.762 48.091 ;
     RECT  4.788 48.001 5.742 48.091 ;
     RECT  17.064 47.695 17.154 48.173 ;
     RECT  2.304 48.091 5.742 48.191 ;
     RECT  0.252 48.091 0.306 48.22 ;
     RECT  16.524 48.187 16.542 48.263 ;
     RECT  0.216 48.22 0.306 48.365 ;
     RECT  0.252 48.365 0.306 48.413 ;
     RECT  14.832 47.723 14.886 48.541 ;
     RECT  14.616 48.541 14.886 48.619 ;
     RECT  7.128 47.849 13.662 48.631 ;
     RECT  14.616 48.619 15.426 48.659 ;
     RECT  7.128 48.631 13.842 48.703 ;
     RECT  2.304 48.191 5.397 48.704 ;
     RECT  6.984 48.703 13.842 48.715 ;
     RECT  0.252 48.413 0.27 48.749 ;
     RECT  14.832 48.659 15.426 48.803 ;
     RECT  2.304 48.704 3.294 48.955 ;
     RECT  6.732 48.715 13.842 49.081 ;
     RECT  2.196 48.955 3.294 49.109 ;
     RECT  17.064 49.147 17.082 49.171 ;
     RECT  17.064 49.171 17.154 49.229 ;
     RECT  6.732 49.081 14.058 49.243 ;
     RECT  6.66 49.243 14.058 49.441 ;
     RECT  14.832 48.803 14.922 49.441 ;
     RECT  6.66 49.441 14.922 49.517 ;
     RECT  2.268 49.109 3.294 49.549 ;
     RECT  4.032 48.704 5.397 49.549 ;
     RECT  2.268 49.549 5.397 49.709 ;
     RECT  16.524 49.675 16.542 49.775 ;
     RECT  6.66 49.517 13.914 49.867 ;
     RECT  0.288 49.867 0.306 49.915 ;
     RECT  14.832 49.517 14.922 49.915 ;
     RECT  17.064 50.011 17.082 50.053 ;
     RECT  6.588 49.867 13.914 50.08 ;
     RECT  14.832 49.915 15.426 50.107 ;
     RECT  6.552 50.08 13.914 50.141 ;
     RECT  0.216 49.915 0.306 50.204 ;
     RECT  6.84 50.141 13.914 50.279 ;
     RECT  17.064 50.053 17.154 50.285 ;
     RECT  0.252 50.204 0.27 50.333 ;
     RECT  14.832 50.107 15.462 50.351 ;
     RECT  14.832 50.351 15.426 50.423 ;
     RECT  7.308 50.279 13.914 50.431 ;
     RECT  14.832 50.423 14.85 50.431 ;
     RECT  2.304 49.709 5.397 50.549 ;
     RECT  2.304 50.549 4.014 50.621 ;
     RECT  7.308 50.431 14.85 50.621 ;
     RECT  3.42 50.621 4.014 50.729 ;
     RECT  4.752 50.549 5.397 50.891 ;
     RECT  16.524 50.539 16.578 51.211 ;
     RECT  5.076 50.891 5.397 51.269 ;
     RECT  2.304 50.621 2.697 51.359 ;
     RECT  7.344 50.621 14.85 51.403 ;
     RECT  2.34 51.359 2.697 51.511 ;
     RECT  3.564 50.729 4.014 51.511 ;
     RECT  7.2 51.403 14.922 51.629 ;
     RECT  2.34 51.511 4.014 51.691 ;
     RECT  0.252 51.643 0.27 51.821 ;
     RECT  7.2 51.629 13.842 51.835 ;
     RECT  2.34 51.691 4.086 51.871 ;
     RECT  14.832 51.629 14.922 51.979 ;
     RECT  6.3 51.907 6.318 52.027 ;
     RECT  7.128 51.835 13.842 52.027 ;
     RECT  2.34 51.871 4.23 52.123 ;
     RECT  5.115 51.269 5.397 52.141 ;
     RECT  6.3 52.027 13.842 52.141 ;
     RECT  2.304 52.123 4.23 52.213 ;
     RECT  5.115 52.141 13.842 52.213 ;
     RECT  1.152 51.883 1.17 52.249 ;
     RECT  0.54 52.249 1.17 52.267 ;
     RECT  2.304 52.213 13.842 52.301 ;
     RECT  7.2 52.301 13.842 52.411 ;
     RECT  0.54 52.267 1.242 52.445 ;
     RECT  16.524 51.211 17.154 52.511 ;
     RECT  16.524 52.511 17.082 52.541 ;
     RECT  16.524 52.541 16.542 52.547 ;
     RECT  0.54 52.445 1.17 52.685 ;
     RECT  7.2 52.411 13.914 52.753 ;
     RECT  14.832 51.979 15.426 52.753 ;
     RECT  7.2 52.753 15.426 52.861 ;
     RECT  7.2 52.861 15.462 53.015 ;
     RECT  1.152 52.685 1.17 53.021 ;
     RECT  2.304 52.301 6.246 53.059 ;
     RECT  14.832 53.015 15.462 53.069 ;
     RECT  2.304 53.059 6.318 53.159 ;
     RECT  7.2 53.015 13.842 53.32 ;
     RECT  16.524 53.467 16.542 53.555 ;
     RECT  6.804 53.32 13.842 54.031 ;
     RECT  14.832 53.069 15.426 54.031 ;
     RECT  2.304 53.159 5.778 54.059 ;
     RECT  6.588 54.031 15.426 54.131 ;
     RECT  5.004 54.059 5.778 54.139 ;
     RECT  6.588 54.131 14.85 54.139 ;
     RECT  17.064 54.187 17.154 54.331 ;
     RECT  16.524 54.331 17.154 54.437 ;
     RECT  17.064 54.437 17.082 54.461 ;
     RECT  5.004 54.139 14.85 54.599 ;
     RECT  5.112 54.599 14.85 54.907 ;
     RECT  2.304 54.059 4.086 54.941 ;
     RECT  3.996 54.941 4.086 55.111 ;
     RECT  5.112 54.907 14.958 55.139 ;
     RECT  14.796 55.139 14.958 55.147 ;
     RECT  5.112 55.139 13.914 55.181 ;
     RECT  5.112 55.181 13.842 55.211 ;
     RECT  6.336 55.211 13.842 55.277 ;
     RECT  3.996 55.111 4.158 55.291 ;
     RECT  16.524 55.195 16.542 55.325 ;
     RECT  3.996 55.291 4.374 55.381 ;
     RECT  5.112 55.211 5.397 55.381 ;
     RECT  14.796 55.147 15.426 55.453 ;
     RECT  6.336 55.277 6.354 55.517 ;
     RECT  14.796 55.453 15.462 55.613 ;
     RECT  3.996 55.381 5.397 55.675 ;
     RECT  2.304 54.941 2.862 55.723 ;
     RECT  3.96 55.675 5.397 55.723 ;
     RECT  2.304 55.723 5.397 55.907 ;
     RECT  0.252 55.291 0.27 55.915 ;
     RECT  7.164 55.277 13.842 55.949 ;
     RECT  11.664 55.949 13.842 55.985 ;
     RECT  7.164 55.949 10.926 55.997 ;
     RECT  0.252 55.915 0.414 56.011 ;
     RECT  8.676 55.997 10.926 56.021 ;
     RECT  0.216 56.011 0.414 56.045 ;
     RECT  9.036 56.021 10.926 56.045 ;
     RECT  2.304 55.907 5.274 56.057 ;
     RECT  7.164 55.997 7.905 56.065 ;
     RECT  11.736 55.985 13.842 56.093 ;
     RECT  14.796 55.613 15.426 56.093 ;
     RECT  12.06 56.093 13.842 56.101 ;
     RECT  4.176 56.057 5.274 56.129 ;
     RECT  2.304 56.057 3.402 56.141 ;
     RECT  2.415 56.141 3.402 56.177 ;
     RECT  7.02 56.065 7.905 56.177 ;
     RECT  9.036 56.045 10.605 56.177 ;
     RECT  12.06 56.101 14.526 56.177 ;
     RECT  4.248 56.129 5.274 56.219 ;
     RECT  13.68 56.177 14.526 56.219 ;
     RECT  3.096 56.177 3.402 56.255 ;
     RECT  4.824 56.219 5.274 56.255 ;
     RECT  16.524 56.107 16.542 56.255 ;
     RECT  0.216 56.045 0.234 56.285 ;
     RECT  3.096 56.255 3.114 56.285 ;
     RECT  12.06 56.177 12.582 56.291 ;
     RECT  13.86 56.219 14.526 56.291 ;
     RECT  4.824 56.255 4.878 56.327 ;
     RECT  9.036 56.177 10.314 56.327 ;
     RECT  13.86 56.291 13.878 56.327 ;
     RECT  4.86 56.327 4.878 56.363 ;
     RECT  12.06 56.291 12.078 56.363 ;
     RECT  7.02 56.177 7.434 56.399 ;
     RECT  9.972 56.327 10.314 56.399 ;
     RECT  7.02 56.399 7.038 56.444 ;
     RECT  9.972 56.399 9.99 56.444 ;
    LAYER M4 ;
     RECT  0.192 2.208 0.205 2.232 ;
     RECT  0.156 2.232 0.205 2.352 ;
     RECT  0.192 2.352 0.205 2.376 ;
     RECT  0.156 2.376 0.205 2.448 ;
     RECT  0.192 2.448 0.205 2.472 ;
     RECT  0.156 2.472 0.205 2.544 ;
     RECT  0.192 2.544 0.205 2.568 ;
     RECT  0.156 2.568 0.205 2.64 ;
     RECT  0.192 2.64 0.205 2.664 ;
     RECT  0.156 2.664 0.205 2.736 ;
     RECT  0.192 2.736 0.205 2.76 ;
     RECT  0.156 2.76 0.205 2.88 ;
     RECT  0.192 2.88 0.205 2.904 ;
     RECT  0.156 2.904 0.205 2.976 ;
     RECT  0.192 2.976 0.205 3 ;
     RECT  0.156 3 0.205 3.072 ;
     RECT  0.192 3.072 0.205 3.096 ;
     RECT  0.156 3.096 0.205 3.168 ;
     RECT  0.192 3.168 0.205 3.192 ;
     RECT  0.156 3.192 0.205 3.264 ;
     RECT  0.192 3.264 0.205 3.288 ;
     RECT  0.156 3.288 0.205 3.36 ;
     RECT  0.192 3.36 0.205 3.384 ;
     RECT  0.156 3.384 0.205 3.504 ;
     RECT  0.192 3.504 0.205 3.528 ;
     RECT  0.156 3.528 0.205 3.6 ;
     RECT  0.192 3.6 0.205 3.624 ;
     RECT  0.156 3.624 0.205 3.696 ;
     RECT  0.192 3.696 0.205 3.72 ;
     RECT  0.156 3.72 0.205 3.792 ;
     RECT  0.192 3.792 0.205 3.816 ;
     RECT  0.156 3.816 0.205 3.888 ;
     RECT  0.192 3.888 0.205 3.912 ;
     RECT  0.156 3.912 0.205 4.032 ;
     RECT  0.192 4.032 0.205 4.056 ;
     RECT  0.156 4.056 0.205 4.128 ;
     RECT  0.192 4.128 0.205 4.152 ;
     RECT  0.156 4.152 0.205 4.224 ;
     RECT  0.192 4.224 0.205 4.248 ;
     RECT  0.156 4.248 0.205 4.32 ;
     RECT  0.192 4.32 0.205 4.344 ;
     RECT  0.156 4.344 0.205 4.416 ;
     RECT  0.192 4.416 0.205 4.44 ;
     RECT  0.156 4.44 0.205 4.56 ;
     RECT  0.192 4.56 0.205 4.584 ;
     RECT  0.156 4.584 0.205 4.656 ;
     RECT  0.192 4.656 0.205 4.68 ;
     RECT  0.156 4.68 0.205 4.752 ;
     RECT  0.192 4.752 0.205 4.776 ;
     RECT  0.156 4.776 0.205 4.848 ;
     RECT  0.192 4.848 0.205 4.872 ;
     RECT  0.156 4.872 0.205 4.944 ;
     RECT  0.192 4.944 0.205 4.968 ;
     RECT  0.156 4.968 0.205 5.088 ;
     RECT  0.192 5.088 0.205 5.112 ;
     RECT  0.156 5.112 0.205 5.184 ;
     RECT  0.192 5.184 0.205 5.208 ;
     RECT  0.156 5.208 0.205 5.28 ;
     RECT  0.192 5.28 0.205 5.304 ;
     RECT  0.156 5.304 0.205 5.376 ;
     RECT  0.192 5.376 0.205 5.4 ;
     RECT  0.156 5.4 0.205 5.472 ;
     RECT  0.192 5.472 0.205 5.496 ;
     RECT  0.156 5.496 0.205 5.616 ;
     RECT  0.192 5.616 0.205 5.64 ;
     RECT  0.156 5.64 0.205 5.712 ;
     RECT  0.192 5.712 0.205 5.736 ;
     RECT  0.156 5.736 0.205 5.808 ;
     RECT  0.192 5.808 0.205 5.832 ;
     RECT  0.156 5.832 0.205 5.904 ;
     RECT  0.192 5.904 0.205 5.928 ;
     RECT  0.156 5.928 0.205 6 ;
     RECT  0.192 6 0.205 6.024 ;
     RECT  0.156 6.024 0.205 6.096 ;
     RECT  0.192 6.096 0.205 6.12 ;
     RECT  0.156 6.12 0.205 6.24 ;
     RECT  0.192 6.24 0.205 6.264 ;
     RECT  0.156 6.264 0.205 6.336 ;
     RECT  0.192 6.336 0.205 6.36 ;
     RECT  0.156 6.36 0.205 6.432 ;
     RECT  0.192 6.432 0.205 6.456 ;
     RECT  0.156 6.456 0.205 6.528 ;
     RECT  0.192 6.528 0.205 6.552 ;
     RECT  0.156 6.552 0.205 6.624 ;
     RECT  0.192 6.624 0.205 6.648 ;
     RECT  0.156 6.648 0.205 6.768 ;
     RECT  0.192 6.768 0.205 6.792 ;
     RECT  0.156 6.792 0.205 6.864 ;
     RECT  0.192 6.864 0.205 6.888 ;
     RECT  0.156 6.888 0.205 6.96 ;
     RECT  0.192 6.96 0.205 6.984 ;
     RECT  0.156 6.984 0.205 7.056 ;
     RECT  0.192 7.056 0.205 7.08 ;
     RECT  0.156 7.08 0.205 7.152 ;
     RECT  0.192 7.152 0.205 7.176 ;
     RECT  0.156 7.176 0.205 7.296 ;
     RECT  0.192 7.296 0.205 7.32 ;
     RECT  0.156 7.32 0.205 7.392 ;
     RECT  0.192 7.392 0.205 7.416 ;
     RECT  0.156 7.416 0.205 7.488 ;
     RECT  0.192 7.488 0.205 7.512 ;
     RECT  0.156 7.512 0.205 7.584 ;
     RECT  0.192 7.584 0.205 7.608 ;
     RECT  0.156 7.608 0.205 7.68 ;
     RECT  0.192 7.68 0.205 7.704 ;
     RECT  0.156 7.704 0.205 7.824 ;
     RECT  0.192 7.824 0.205 7.848 ;
     RECT  0.156 7.848 0.205 7.92 ;
     RECT  0.192 7.92 0.205 7.944 ;
     RECT  0.156 7.944 0.205 8.016 ;
     RECT  0.192 8.016 0.205 8.04 ;
     RECT  0.156 8.04 0.205 8.112 ;
     RECT  0.192 8.112 0.205 8.136 ;
     RECT  0.156 8.136 0.205 8.208 ;
     RECT  0.192 8.208 0.205 8.232 ;
     RECT  0.156 8.232 0.205 8.352 ;
     RECT  0.192 8.352 0.205 8.376 ;
     RECT  0.156 8.376 0.205 8.448 ;
     RECT  0.192 8.448 0.205 8.472 ;
     RECT  0.156 8.472 0.205 8.544 ;
     RECT  0.192 8.544 0.205 8.568 ;
     RECT  0.156 8.568 0.205 8.64 ;
     RECT  0.192 8.64 0.205 8.664 ;
     RECT  0.156 8.664 0.205 8.736 ;
     RECT  0.192 8.736 0.205 8.76 ;
     RECT  0.156 8.76 0.205 8.88 ;
     RECT  0.192 8.88 0.205 8.904 ;
     RECT  0.156 8.904 0.205 8.976 ;
     RECT  0.192 8.976 0.205 9 ;
     RECT  0.156 9 0.205 9.072 ;
     RECT  0.192 9.072 0.205 9.096 ;
     RECT  0.156 9.096 0.205 9.168 ;
     RECT  0.192 9.168 0.205 9.192 ;
     RECT  0.156 9.192 0.205 9.264 ;
     RECT  0.192 9.264 0.205 9.288 ;
     RECT  0.156 9.288 0.205 9.36 ;
     RECT  0.192 9.36 0.205 9.384 ;
     RECT  0.156 9.384 0.205 9.504 ;
     RECT  0.192 9.504 0.205 9.528 ;
     RECT  0.156 9.528 0.205 9.6 ;
     RECT  0.192 9.6 0.205 9.624 ;
     RECT  0.156 9.624 0.205 9.696 ;
     RECT  0.192 9.696 0.205 9.72 ;
     RECT  0.156 9.72 0.205 9.792 ;
     RECT  0.192 9.792 0.205 9.816 ;
     RECT  0.156 9.816 0.205 9.888 ;
     RECT  0.192 9.888 0.205 9.912 ;
     RECT  0.156 9.912 0.205 10.032 ;
     RECT  0.192 10.032 0.205 10.056 ;
     RECT  0.156 10.056 0.205 10.128 ;
     RECT  0.192 10.128 0.205 10.152 ;
     RECT  0.156 10.152 0.205 10.224 ;
     RECT  0.192 10.224 0.205 10.248 ;
     RECT  0.156 10.248 0.205 10.32 ;
     RECT  0.192 10.32 0.205 10.344 ;
     RECT  0.156 10.344 0.205 10.416 ;
     RECT  0.192 10.416 0.205 10.44 ;
     RECT  0.156 10.44 0.205 10.56 ;
     RECT  0.192 10.56 0.205 10.584 ;
     RECT  0.156 10.584 0.205 10.656 ;
     RECT  0.192 10.656 0.205 10.68 ;
     RECT  0.156 10.68 0.205 10.752 ;
     RECT  0.192 10.752 0.205 10.776 ;
     RECT  0.156 10.776 0.205 10.848 ;
     RECT  0.192 10.848 0.205 10.872 ;
     RECT  0.156 10.872 0.205 10.944 ;
     RECT  0.192 10.944 0.205 10.968 ;
     RECT  0.156 10.968 0.205 11.088 ;
     RECT  0.192 11.088 0.205 11.112 ;
     RECT  0.156 11.112 0.205 11.184 ;
     RECT  0.192 11.184 0.205 11.208 ;
     RECT  0.156 11.208 0.205 11.28 ;
     RECT  0.192 11.28 0.205 11.304 ;
     RECT  0.156 11.304 0.205 11.376 ;
     RECT  0.192 11.376 0.205 11.4 ;
     RECT  0.156 11.4 0.205 11.472 ;
     RECT  0.192 11.472 0.205 11.496 ;
     RECT  0.156 11.496 0.205 11.616 ;
     RECT  0.192 11.616 0.205 11.64 ;
     RECT  0.156 11.64 0.205 11.712 ;
     RECT  0.192 11.712 0.205 11.736 ;
     RECT  0.156 11.736 0.205 11.808 ;
     RECT  0.192 11.808 0.205 11.832 ;
     RECT  0.156 11.832 0.205 11.904 ;
     RECT  0.192 11.904 0.205 11.928 ;
     RECT  0.156 11.928 0.205 12 ;
     RECT  0.192 12 0.205 12.024 ;
     RECT  0.156 12.024 0.205 12.096 ;
     RECT  0.192 12.096 0.205 12.12 ;
     RECT  0.156 12.12 0.205 12.24 ;
     RECT  0.192 12.24 0.205 12.264 ;
     RECT  0.156 12.264 0.205 12.336 ;
     RECT  0.192 12.336 0.205 12.36 ;
     RECT  0.156 12.36 0.205 12.432 ;
     RECT  0.192 12.432 0.205 12.456 ;
     RECT  0.156 12.456 0.205 12.528 ;
     RECT  0.192 12.528 0.205 12.552 ;
     RECT  0.156 12.552 0.205 12.624 ;
     RECT  0.192 12.624 0.205 12.648 ;
     RECT  0.156 12.648 0.205 12.768 ;
     RECT  0.192 12.768 0.205 12.792 ;
     RECT  0.156 12.792 0.205 12.864 ;
     RECT  0.192 12.864 0.205 12.888 ;
     RECT  0.156 12.888 0.205 12.96 ;
     RECT  0.192 12.96 0.205 12.984 ;
     RECT  0.156 12.984 0.205 13.056 ;
     RECT  0.192 13.056 0.205 13.08 ;
     RECT  0.156 13.08 0.205 13.152 ;
     RECT  0.192 13.152 0.205 13.176 ;
     RECT  0.156 13.176 0.205 13.296 ;
     RECT  0.192 13.296 0.205 13.32 ;
     RECT  0.156 13.32 0.205 13.392 ;
     RECT  0.192 13.392 0.205 13.416 ;
     RECT  0.156 13.416 0.205 13.488 ;
     RECT  0.192 13.488 0.205 13.512 ;
     RECT  0.156 13.512 0.205 13.584 ;
     RECT  0.192 13.584 0.205 13.608 ;
     RECT  0.156 13.608 0.205 13.68 ;
     RECT  0.192 13.68 0.205 13.704 ;
     RECT  0.156 13.704 0.205 13.824 ;
     RECT  0.192 13.824 0.205 13.848 ;
     RECT  0.156 13.848 0.205 13.92 ;
     RECT  0.192 13.92 0.205 13.944 ;
     RECT  0.156 13.944 0.205 14.016 ;
     RECT  0.192 14.016 0.205 14.04 ;
     RECT  0.156 14.04 0.205 14.112 ;
     RECT  0.192 14.112 0.205 14.136 ;
     RECT  0.156 14.136 0.205 14.208 ;
     RECT  0.192 14.208 0.205 14.232 ;
     RECT  0.156 14.232 0.205 14.352 ;
     RECT  0.192 14.352 0.205 14.376 ;
     RECT  0.156 14.376 0.205 14.448 ;
     RECT  0.192 14.448 0.205 14.472 ;
     RECT  0.156 14.472 0.205 14.544 ;
     RECT  0.192 14.544 0.205 14.568 ;
     RECT  0.156 14.568 0.205 14.64 ;
     RECT  0.192 14.64 0.205 14.664 ;
     RECT  0.156 14.664 0.205 14.736 ;
     RECT  0.192 14.736 0.205 14.76 ;
     RECT  0.156 14.76 0.205 14.88 ;
     RECT  0.192 14.88 0.205 14.904 ;
     RECT  0.156 14.904 0.205 14.976 ;
     RECT  0.192 14.976 0.205 15 ;
     RECT  0.156 15 0.205 15.072 ;
     RECT  0.192 15.072 0.205 15.096 ;
     RECT  0.156 15.096 0.205 15.168 ;
     RECT  0.192 15.168 0.205 15.192 ;
     RECT  0.156 15.192 0.205 15.264 ;
     RECT  0.192 15.264 0.205 15.288 ;
     RECT  0.156 15.288 0.205 15.36 ;
     RECT  0.192 15.36 0.205 15.384 ;
     RECT  0.156 15.384 0.205 15.504 ;
     RECT  0.192 15.504 0.205 15.528 ;
     RECT  0.156 15.528 0.205 15.6 ;
     RECT  0.192 15.6 0.205 15.624 ;
     RECT  0.156 15.624 0.205 15.696 ;
     RECT  0.192 15.696 0.205 15.72 ;
     RECT  0.156 15.72 0.205 15.792 ;
     RECT  0.192 15.792 0.205 15.816 ;
     RECT  0.156 15.816 0.205 15.888 ;
     RECT  0.192 15.888 0.205 15.912 ;
     RECT  0.156 15.912 0.205 16.032 ;
     RECT  0.192 16.032 0.205 16.056 ;
     RECT  0.156 16.056 0.205 16.128 ;
     RECT  0.192 16.128 0.205 16.152 ;
     RECT  0.156 16.152 0.205 16.224 ;
     RECT  0.192 16.224 0.205 16.248 ;
     RECT  0.156 16.248 0.205 16.32 ;
     RECT  0.192 16.32 0.205 16.344 ;
     RECT  0.156 16.344 0.205 16.416 ;
     RECT  0.192 16.416 0.205 16.44 ;
     RECT  0.156 16.44 0.205 16.56 ;
     RECT  0.192 16.56 0.205 16.584 ;
     RECT  0.156 16.584 0.205 16.656 ;
     RECT  0.192 16.656 0.205 16.68 ;
     RECT  0.156 16.68 0.205 16.752 ;
     RECT  0.192 16.752 0.205 16.776 ;
     RECT  0.156 16.776 0.205 16.848 ;
     RECT  0.192 16.848 0.205 16.872 ;
     RECT  0.156 16.872 0.205 16.944 ;
     RECT  0.192 16.944 0.205 16.968 ;
     RECT  0.156 16.968 0.205 17.088 ;
     RECT  0.192 17.088 0.205 17.112 ;
     RECT  0.156 17.112 0.205 17.184 ;
     RECT  0.192 17.184 0.205 17.208 ;
     RECT  0.156 17.208 0.205 17.28 ;
     RECT  0.192 17.28 0.205 17.304 ;
     RECT  0.156 17.304 0.205 17.376 ;
     RECT  0.192 17.376 0.205 17.4 ;
     RECT  0.156 17.4 0.205 17.472 ;
     RECT  0.192 17.472 0.205 17.496 ;
     RECT  0.156 17.496 0.205 17.616 ;
     RECT  0.192 17.616 0.205 17.64 ;
     RECT  0.156 17.64 0.205 17.712 ;
     RECT  0.192 17.712 0.205 17.736 ;
     RECT  0.156 17.736 0.205 17.808 ;
     RECT  0.192 17.808 0.205 17.832 ;
     RECT  0.156 17.832 0.205 17.904 ;
     RECT  0.192 17.904 0.205 17.928 ;
     RECT  0.156 17.928 0.205 18 ;
     RECT  0.192 18 0.205 18.024 ;
     RECT  0.156 18.024 0.205 18.096 ;
     RECT  0.192 18.096 0.205 18.12 ;
     RECT  0.156 18.12 0.205 18.24 ;
     RECT  0.192 18.24 0.205 18.264 ;
     RECT  0.156 18.264 0.205 18.336 ;
     RECT  0.192 18.336 0.205 18.36 ;
     RECT  0.156 18.36 0.205 18.432 ;
     RECT  0.192 18.432 0.205 18.456 ;
     RECT  0.156 18.456 0.205 18.528 ;
     RECT  0.192 18.528 0.205 18.552 ;
     RECT  0.156 18.552 0.205 18.624 ;
     RECT  0.192 18.624 0.205 18.648 ;
     RECT  0.156 18.648 0.205 18.768 ;
     RECT  0.192 18.768 0.205 18.792 ;
     RECT  0.156 18.792 0.205 18.864 ;
     RECT  0.192 18.864 0.205 18.888 ;
     RECT  0.156 18.888 0.205 18.96 ;
     RECT  0.192 18.96 0.205 18.984 ;
     RECT  0.156 18.984 0.205 19.056 ;
     RECT  0.192 19.056 0.205 19.08 ;
     RECT  0.156 19.08 0.205 19.152 ;
     RECT  0.192 19.152 0.205 19.176 ;
     RECT  0.156 19.176 0.205 19.296 ;
     RECT  0.192 19.296 0.205 19.32 ;
     RECT  0.156 19.32 0.205 19.392 ;
     RECT  0.192 19.392 0.205 19.416 ;
     RECT  0.156 19.416 0.205 19.488 ;
     RECT  0.192 19.488 0.205 19.512 ;
     RECT  0.156 19.512 0.205 19.584 ;
     RECT  0.192 19.584 0.205 19.608 ;
     RECT  0.156 19.608 0.205 19.68 ;
     RECT  0.192 19.68 0.205 19.704 ;
     RECT  0.156 19.704 0.205 19.824 ;
     RECT  0.192 19.824 0.205 19.848 ;
     RECT  0.156 19.848 0.205 19.92 ;
     RECT  0.192 19.92 0.205 19.944 ;
     RECT  0.156 19.944 0.205 20.016 ;
     RECT  0.192 20.016 0.205 20.04 ;
     RECT  0.156 20.04 0.205 20.112 ;
     RECT  0.192 20.112 0.205 20.136 ;
     RECT  0.156 20.136 0.205 20.208 ;
     RECT  0.192 20.208 0.205 20.232 ;
     RECT  0.156 20.232 0.205 20.352 ;
     RECT  0.192 20.352 0.205 20.376 ;
     RECT  0.156 20.376 0.205 20.448 ;
     RECT  0.192 20.448 0.205 20.472 ;
     RECT  0.156 20.472 0.205 20.544 ;
     RECT  0.192 20.544 0.205 20.568 ;
     RECT  0.156 20.568 0.205 20.64 ;
     RECT  0.192 20.64 0.205 20.664 ;
     RECT  0.156 20.664 0.205 20.736 ;
     RECT  0.192 20.736 0.205 20.76 ;
     RECT  0.156 20.76 0.205 20.88 ;
     RECT  0.192 20.88 0.205 20.904 ;
     RECT  0.156 20.904 0.205 20.976 ;
     RECT  0.192 20.976 0.205 21 ;
     RECT  0.156 21 0.205 21.072 ;
     RECT  0.192 21.072 0.205 21.096 ;
     RECT  0.156 21.096 0.205 21.168 ;
     RECT  0.192 21.168 0.205 21.192 ;
     RECT  0.156 21.192 0.205 21.264 ;
     RECT  0.192 21.264 0.205 21.288 ;
     RECT  0.156 21.288 0.205 21.36 ;
     RECT  0.192 21.36 0.205 21.384 ;
     RECT  0.156 21.384 0.205 21.504 ;
     RECT  0.192 21.504 0.205 21.528 ;
     RECT  0.156 21.528 0.205 21.6 ;
     RECT  0.192 21.6 0.205 21.624 ;
     RECT  0.156 21.624 0.205 21.696 ;
     RECT  0.192 21.696 0.205 21.72 ;
     RECT  0.156 21.72 0.205 21.792 ;
     RECT  0.192 21.792 0.205 21.816 ;
     RECT  0.156 21.816 0.205 21.888 ;
     RECT  0.192 21.888 0.205 21.912 ;
     RECT  0.156 21.912 0.205 22.032 ;
     RECT  0.192 22.032 0.205 22.056 ;
     RECT  0.156 22.056 0.205 22.128 ;
     RECT  0.192 22.128 0.205 22.152 ;
     RECT  0.156 22.152 0.205 22.224 ;
     RECT  0.192 22.224 0.205 22.248 ;
     RECT  0.156 22.248 0.205 22.32 ;
     RECT  0.192 22.32 0.205 22.344 ;
     RECT  0.156 22.344 0.205 22.416 ;
     RECT  0.192 22.416 0.205 22.44 ;
     RECT  0.156 22.44 0.205 22.56 ;
     RECT  0.192 22.56 0.205 22.584 ;
     RECT  0.156 22.584 0.205 22.656 ;
     RECT  0.192 22.656 0.205 22.68 ;
     RECT  0.156 22.68 0.205 22.752 ;
     RECT  0.192 22.752 0.205 22.776 ;
     RECT  0.156 22.776 0.205 22.848 ;
     RECT  0.192 22.848 0.205 22.872 ;
     RECT  0.156 22.872 0.205 22.944 ;
     RECT  0.192 22.944 0.205 22.968 ;
     RECT  0.156 22.968 0.205 23.088 ;
     RECT  0.192 23.088 0.205 23.112 ;
     RECT  0.156 23.112 0.205 23.184 ;
     RECT  0.192 23.184 0.205 23.208 ;
     RECT  0.156 23.208 0.205 23.28 ;
     RECT  0.192 23.28 0.205 23.304 ;
     RECT  0.156 23.304 0.205 23.376 ;
     RECT  0.192 23.376 0.205 23.4 ;
     RECT  0.156 23.4 0.205 23.472 ;
     RECT  0.192 23.472 0.205 23.496 ;
     RECT  0.156 23.496 0.205 23.616 ;
     RECT  0.192 23.616 0.205 23.64 ;
     RECT  0.156 23.64 0.205 23.712 ;
     RECT  0.192 23.712 0.205 23.736 ;
     RECT  0.156 23.736 0.205 23.808 ;
     RECT  0.192 23.808 0.205 23.832 ;
     RECT  0.156 23.832 0.205 23.904 ;
     RECT  0.192 23.904 0.205 23.928 ;
     RECT  0.156 23.928 0.205 24 ;
     RECT  0.192 24 0.205 24.024 ;
     RECT  0.156 24.024 0.205 24.096 ;
     RECT  0.192 24.096 0.205 24.12 ;
     RECT  0.156 24.12 0.205 24.24 ;
     RECT  0.192 24.24 0.205 24.264 ;
     RECT  0.156 24.264 0.205 24.336 ;
     RECT  0.192 24.336 0.205 24.36 ;
     RECT  0.156 24.36 0.205 24.432 ;
     RECT  0.192 24.432 0.205 24.456 ;
     RECT  0.156 24.456 0.205 24.528 ;
     RECT  0.192 24.528 0.205 24.552 ;
     RECT  0.156 24.552 0.205 24.624 ;
     RECT  0.192 24.624 0.205 24.648 ;
     RECT  0.156 24.648 0.205 24.768 ;
     RECT  0.192 24.768 0.205 24.792 ;
     RECT  0.156 24.792 0.205 24.864 ;
     RECT  0.192 24.864 0.205 24.888 ;
     RECT  0.156 24.888 0.205 24.96 ;
     RECT  0.192 24.96 0.205 24.984 ;
     RECT  0.156 24.984 0.205 25.056 ;
     RECT  0.192 25.056 0.205 25.08 ;
     RECT  0.156 25.08 0.205 25.152 ;
     RECT  0.192 25.152 0.205 25.176 ;
     RECT  0.156 25.176 0.205 25.296 ;
     RECT  0.192 25.296 0.205 25.32 ;
     RECT  0.156 25.32 0.205 25.392 ;
     RECT  0.192 25.392 0.205 25.416 ;
     RECT  0.156 25.416 0.205 25.488 ;
     RECT  0.192 25.488 0.205 25.512 ;
     RECT  0.156 25.512 0.205 25.584 ;
     RECT  0.192 25.584 0.205 25.608 ;
     RECT  0.156 25.608 0.205 25.68 ;
     RECT  0.192 25.68 0.205 25.704 ;
     RECT  0.156 25.704 0.205 25.824 ;
     RECT  0.192 25.824 0.205 25.848 ;
     RECT  0.156 25.848 0.205 25.92 ;
     RECT  0.192 25.92 0.205 25.944 ;
     RECT  0.156 25.944 0.205 26.016 ;
     RECT  0.192 26.016 0.205 26.04 ;
     RECT  0.156 26.04 0.205 26.112 ;
     RECT  0.192 26.112 0.205 26.136 ;
     RECT  0.156 26.136 0.205 26.208 ;
     RECT  0.192 26.208 0.205 26.232 ;
     RECT  0.156 26.232 0.205 26.352 ;
     RECT  0.192 26.352 0.205 26.376 ;
     RECT  0.156 26.376 0.205 26.448 ;
     RECT  0.192 26.448 0.205 26.472 ;
     RECT  0.156 26.472 0.205 26.544 ;
     RECT  0.192 26.544 0.205 26.568 ;
     RECT  0.156 26.568 0.205 26.64 ;
     RECT  0.192 26.64 0.205 26.664 ;
     RECT  0.156 26.664 0.205 26.736 ;
     RECT  0.192 26.736 0.205 26.76 ;
     RECT  0.156 26.76 0.205 26.88 ;
     RECT  0.192 26.88 0.205 26.904 ;
     RECT  0.156 26.904 0.205 26.976 ;
     RECT  0.192 26.976 0.205 27 ;
     RECT  0.156 27 0.205 27.072 ;
     RECT  0.192 27.072 0.205 27.096 ;
     RECT  0.156 27.096 0.205 27.168 ;
     RECT  0.192 27.168 0.205 27.192 ;
     RECT  0.156 27.192 0.205 27.264 ;
     RECT  0.192 27.264 0.205 27.288 ;
     RECT  0.156 27.288 0.205 27.36 ;
     RECT  0.192 27.36 0.205 27.384 ;
     RECT  0.156 27.384 0.205 27.504 ;
     RECT  0.192 27.504 0.205 27.528 ;
     RECT  0.156 27.528 0.205 27.6 ;
     RECT  0.192 27.6 0.205 27.624 ;
     RECT  0.156 27.624 0.205 27.696 ;
     RECT  0.192 27.696 0.205 27.72 ;
     RECT  0.156 27.72 0.205 27.792 ;
     RECT  0.192 27.792 0.205 27.816 ;
     RECT  0.156 27.816 0.205 27.888 ;
     RECT  0.192 27.888 0.205 27.912 ;
     RECT  0.156 27.912 0.205 28.032 ;
     RECT  0.192 28.032 0.205 28.056 ;
     RECT  0.156 28.056 0.205 28.128 ;
     RECT  0.192 28.128 0.205 28.152 ;
     RECT  0.156 28.152 0.205 28.224 ;
     RECT  0.192 28.224 0.205 28.248 ;
     RECT  0.156 28.248 0.205 28.32 ;
     RECT  0.192 28.32 0.205 28.344 ;
     RECT  0.156 28.344 0.205 28.416 ;
     RECT  0.192 28.416 0.205 28.44 ;
     RECT  0.156 28.44 0.205 28.56 ;
     RECT  0.192 28.56 0.205 28.584 ;
     RECT  0.156 28.584 0.205 28.656 ;
     RECT  0.192 28.656 0.205 28.68 ;
     RECT  0.156 28.68 0.205 28.752 ;
     RECT  0.192 28.752 0.205 28.776 ;
     RECT  0.156 28.776 0.205 28.848 ;
     RECT  0.192 28.848 0.205 28.872 ;
     RECT  0.156 28.872 0.205 28.944 ;
     RECT  0.192 28.944 0.205 28.968 ;
     RECT  0.156 28.968 0.205 29.088 ;
     RECT  0.192 29.088 0.205 29.112 ;
     RECT  0.156 29.112 0.205 29.184 ;
     RECT  0.192 29.184 0.205 29.208 ;
     RECT  0.156 29.208 0.205 29.28 ;
     RECT  0.192 29.28 0.205 29.304 ;
     RECT  0.156 29.304 0.205 29.376 ;
     RECT  0.192 29.376 0.205 29.4 ;
     RECT  0.156 29.4 0.205 29.472 ;
     RECT  0.192 29.472 0.205 29.496 ;
     RECT  0.156 29.496 0.205 29.616 ;
     RECT  0.192 29.616 0.205 29.64 ;
     RECT  0.156 29.64 0.205 29.712 ;
     RECT  0.192 29.712 0.205 29.736 ;
     RECT  0.156 29.736 0.205 29.808 ;
     RECT  0.192 29.808 0.205 29.832 ;
     RECT  0.156 29.832 0.205 29.904 ;
     RECT  0.192 29.904 0.205 29.928 ;
     RECT  0.156 29.928 0.205 30 ;
     RECT  0.192 30 0.205 30.024 ;
     RECT  0.156 30.024 0.205 30.096 ;
     RECT  0.192 30.096 0.205 30.12 ;
     RECT  0.156 30.12 0.205 30.24 ;
     RECT  0.192 30.24 0.205 30.264 ;
     RECT  0.156 30.264 0.205 30.336 ;
     RECT  0.192 30.336 0.205 30.36 ;
     RECT  0.156 30.36 0.205 30.432 ;
     RECT  0.192 30.432 0.205 30.456 ;
     RECT  0.156 30.456 0.205 30.528 ;
     RECT  0.192 30.528 0.205 30.552 ;
     RECT  0.156 30.552 0.205 30.624 ;
     RECT  0.192 30.624 0.205 30.648 ;
     RECT  0.156 30.648 0.205 30.768 ;
     RECT  0.192 30.768 0.205 30.792 ;
     RECT  0.156 30.792 0.205 30.864 ;
     RECT  0.192 30.864 0.205 30.888 ;
     RECT  0.156 30.888 0.205 30.96 ;
     RECT  0.192 30.96 0.205 30.984 ;
     RECT  0.156 30.984 0.205 31.056 ;
     RECT  0.192 31.056 0.205 31.08 ;
     RECT  0.156 31.08 0.205 31.152 ;
     RECT  0.192 31.152 0.205 31.176 ;
     RECT  0.156 31.176 0.205 31.296 ;
     RECT  0.192 31.296 0.205 31.32 ;
     RECT  0.156 31.32 0.205 31.392 ;
     RECT  0.192 31.392 0.205 31.416 ;
     RECT  0.156 31.416 0.205 31.488 ;
     RECT  0.192 31.488 0.205 31.512 ;
     RECT  0.156 31.512 0.205 31.584 ;
     RECT  0.192 31.584 0.205 31.608 ;
     RECT  0.156 31.608 0.205 31.68 ;
     RECT  0.192 31.68 0.205 31.704 ;
     RECT  0.156 31.704 0.205 31.824 ;
     RECT  0.192 31.824 0.205 31.848 ;
     RECT  0.156 31.848 0.205 31.92 ;
     RECT  0.192 31.92 0.205 31.944 ;
     RECT  0.156 31.944 0.205 32.016 ;
     RECT  0.192 32.016 0.205 32.04 ;
     RECT  0.156 32.04 0.205 32.112 ;
     RECT  0.192 32.112 0.205 32.136 ;
     RECT  0.156 32.136 0.205 32.208 ;
     RECT  0.192 32.208 0.205 32.232 ;
     RECT  0.156 32.232 0.205 32.352 ;
     RECT  0.192 32.352 0.205 32.376 ;
     RECT  0.156 32.376 0.205 32.448 ;
     RECT  0.192 32.448 0.205 32.472 ;
     RECT  0.156 32.472 0.205 32.544 ;
     RECT  0.192 32.544 0.205 32.568 ;
     RECT  0.156 32.568 0.205 32.64 ;
     RECT  0.192 32.64 0.205 32.664 ;
     RECT  0.156 32.664 0.205 32.736 ;
     RECT  0.192 32.736 0.205 32.76 ;
     RECT  0.156 32.76 0.205 32.88 ;
     RECT  0.192 32.88 0.205 32.904 ;
     RECT  0.156 32.904 0.205 32.976 ;
     RECT  0.192 32.976 0.205 33 ;
     RECT  0.156 33 0.205 33.072 ;
     RECT  0.192 33.072 0.205 33.096 ;
     RECT  0.156 33.096 0.205 33.168 ;
     RECT  0.192 33.168 0.205 33.192 ;
     RECT  0.156 33.192 0.205 33.264 ;
     RECT  0.192 33.264 0.205 33.288 ;
     RECT  0.156 33.288 0.205 33.36 ;
     RECT  0.192 33.36 0.205 33.384 ;
     RECT  0.156 33.384 0.205 33.504 ;
     RECT  0.192 33.504 0.205 33.528 ;
     RECT  0.156 33.528 0.205 33.6 ;
     RECT  0.192 33.6 0.205 33.624 ;
     RECT  0.156 33.624 0.205 33.696 ;
     RECT  0.192 33.696 0.205 33.72 ;
     RECT  0.156 33.72 0.205 33.792 ;
     RECT  0.192 33.792 0.205 33.816 ;
     RECT  0.156 33.816 0.205 33.888 ;
     RECT  0.192 33.888 0.205 33.912 ;
     RECT  0.156 33.912 0.205 34.032 ;
     RECT  0.192 34.032 0.205 34.056 ;
     RECT  0.156 34.056 0.205 34.128 ;
     RECT  0.192 34.128 0.205 34.152 ;
     RECT  0.156 34.152 0.205 34.224 ;
     RECT  0.192 34.224 0.205 34.248 ;
     RECT  0.156 34.248 0.205 34.32 ;
     RECT  0.192 34.32 0.205 34.344 ;
     RECT  0.156 34.344 0.205 34.416 ;
     RECT  0.192 34.416 0.205 34.44 ;
     RECT  0.156 34.44 0.205 34.56 ;
     RECT  0.192 34.56 0.205 34.584 ;
     RECT  0.156 34.584 0.205 34.656 ;
     RECT  0.192 34.656 0.205 34.68 ;
     RECT  0.156 34.68 0.205 34.752 ;
     RECT  0.192 34.752 0.205 34.776 ;
     RECT  0.156 34.776 0.205 34.848 ;
     RECT  0.192 34.848 0.205 34.872 ;
     RECT  0.156 34.872 0.205 34.944 ;
     RECT  0.192 34.944 0.205 34.968 ;
     RECT  0.156 34.968 0.205 35.088 ;
     RECT  0.192 35.088 0.205 35.112 ;
     RECT  0.156 35.112 0.205 35.184 ;
     RECT  0.192 35.184 0.205 35.208 ;
     RECT  0.156 35.208 0.205 35.28 ;
     RECT  0.192 35.28 0.205 35.304 ;
     RECT  0.156 35.304 0.205 35.376 ;
     RECT  0.192 35.376 0.205 35.4 ;
     RECT  0.156 35.4 0.205 35.472 ;
     RECT  0.192 35.472 0.205 35.496 ;
     RECT  0.156 35.496 0.205 35.616 ;
     RECT  0.192 35.616 0.205 35.64 ;
     RECT  0.156 35.64 0.205 35.712 ;
     RECT  0.192 35.712 0.205 35.736 ;
     RECT  0.156 35.736 0.205 35.808 ;
     RECT  0.192 35.808 0.205 35.832 ;
     RECT  0.156 35.832 0.205 35.904 ;
     RECT  0.192 35.904 0.205 35.928 ;
     RECT  0.156 35.928 0.205 36 ;
     RECT  0.192 36 0.205 36.024 ;
     RECT  0.156 36.024 0.205 36.096 ;
     RECT  0.192 36.096 0.205 36.12 ;
     RECT  0.156 36.12 0.205 36.24 ;
     RECT  0.192 36.24 0.205 36.264 ;
     RECT  0.156 36.264 0.205 36.336 ;
     RECT  0.192 36.336 0.205 36.36 ;
     RECT  0.156 36.36 0.205 36.432 ;
     RECT  0.192 36.432 0.205 36.456 ;
     RECT  0.156 36.456 0.205 36.528 ;
     RECT  0.192 36.528 0.205 36.552 ;
     RECT  0.156 36.552 0.205 36.624 ;
     RECT  0.192 36.624 0.205 36.648 ;
     RECT  0.156 36.648 0.205 36.768 ;
     RECT  0.192 36.768 0.205 36.792 ;
     RECT  0.156 36.792 0.205 36.864 ;
     RECT  0.192 36.864 0.205 36.888 ;
     RECT  0.156 36.888 0.205 36.96 ;
     RECT  0.192 36.96 0.205 36.984 ;
     RECT  0.156 36.984 0.205 37.056 ;
     RECT  0.192 37.056 0.205 37.08 ;
     RECT  0.156 37.08 0.205 37.152 ;
     RECT  0.192 37.152 0.205 37.176 ;
     RECT  0.156 37.176 0.205 37.296 ;
     RECT  0.192 37.296 0.205 37.32 ;
     RECT  0.156 37.32 0.205 37.392 ;
     RECT  0.192 37.392 0.205 37.416 ;
     RECT  0.156 37.416 0.205 37.488 ;
     RECT  0.192 37.488 0.205 37.512 ;
     RECT  0.156 37.512 0.205 37.584 ;
     RECT  0.192 37.584 0.205 37.608 ;
     RECT  0.156 37.608 0.205 37.68 ;
     RECT  0.192 37.68 0.205 37.704 ;
     RECT  0.156 37.704 0.205 37.824 ;
     RECT  0.192 37.824 0.205 37.848 ;
     RECT  0.156 37.848 0.205 37.92 ;
     RECT  0.192 37.92 0.205 37.944 ;
     RECT  0.156 37.944 0.205 38.016 ;
     RECT  0.192 38.016 0.205 38.04 ;
     RECT  0.156 38.04 0.205 38.112 ;
     RECT  0.192 38.112 0.205 38.136 ;
     RECT  0.156 38.136 0.205 38.208 ;
     RECT  0.192 38.208 0.205 38.232 ;
     RECT  0.156 38.232 0.205 38.352 ;
     RECT  0.192 38.352 0.205 38.376 ;
     RECT  0.156 38.376 0.205 38.448 ;
     RECT  0.192 38.448 0.205 38.472 ;
     RECT  0.156 38.472 0.205 38.544 ;
     RECT  0.192 38.544 0.205 38.568 ;
     RECT  0.156 38.568 0.205 38.64 ;
     RECT  0.192 38.64 0.205 38.664 ;
     RECT  0.156 38.664 0.205 38.736 ;
     RECT  0.192 38.736 0.205 38.76 ;
     RECT  0.156 38.76 0.205 38.88 ;
     RECT  0.192 38.88 0.205 38.904 ;
     RECT  0.156 38.904 0.205 38.976 ;
     RECT  0.192 38.976 0.205 39 ;
     RECT  0.156 39 0.205 39.072 ;
     RECT  0.192 39.072 0.205 39.096 ;
     RECT  0.156 39.096 0.205 39.168 ;
     RECT  0.192 39.168 0.205 39.192 ;
     RECT  0.156 39.192 0.205 39.264 ;
     RECT  0.192 39.264 0.205 39.288 ;
     RECT  0.156 39.288 0.205 39.36 ;
     RECT  0.192 39.36 0.205 39.384 ;
     RECT  0.156 39.384 0.205 39.504 ;
     RECT  0.192 39.504 0.205 39.528 ;
     RECT  0.156 39.528 0.205 39.6 ;
     RECT  0.192 39.6 0.205 39.624 ;
     RECT  0.156 39.624 0.205 39.696 ;
     RECT  0.192 39.696 0.205 39.72 ;
     RECT  0.156 39.72 0.205 39.792 ;
     RECT  0.192 39.792 0.205 39.816 ;
     RECT  0.156 39.816 0.205 39.888 ;
     RECT  0.192 39.888 0.205 39.912 ;
     RECT  0.156 39.912 0.205 40.032 ;
     RECT  0.192 40.032 0.205 40.056 ;
     RECT  0.156 40.056 0.205 40.128 ;
     RECT  0.192 40.128 0.205 40.152 ;
     RECT  0.156 40.152 0.205 40.224 ;
     RECT  0.192 40.224 0.205 40.248 ;
     RECT  0.156 40.248 0.205 40.32 ;
     RECT  0.192 40.32 0.205 40.344 ;
     RECT  0.156 40.344 0.205 40.416 ;
     RECT  0.192 40.416 0.205 40.44 ;
     RECT  0.156 40.44 0.205 40.56 ;
     RECT  0.192 40.56 0.205 40.584 ;
     RECT  0.156 40.584 0.205 40.656 ;
     RECT  0.192 40.656 0.205 40.68 ;
     RECT  0.156 40.68 0.205 40.752 ;
     RECT  0.192 40.752 0.205 40.776 ;
     RECT  0.156 40.776 0.205 40.848 ;
     RECT  0.192 40.848 0.205 40.872 ;
     RECT  0.156 40.872 0.205 40.944 ;
     RECT  0.192 40.944 0.205 40.968 ;
     RECT  0.156 40.968 0.205 41.088 ;
     RECT  0.192 41.088 0.205 41.112 ;
     RECT  0.156 41.112 0.205 41.184 ;
     RECT  0.192 41.184 0.205 41.208 ;
     RECT  0.156 41.208 0.205 41.28 ;
     RECT  0.192 41.28 0.205 41.304 ;
     RECT  0.156 41.304 0.205 41.376 ;
     RECT  0.192 41.376 0.205 41.4 ;
     RECT  0.156 41.4 0.205 41.472 ;
     RECT  0.192 41.472 0.205 41.496 ;
     RECT  0.156 41.496 0.205 41.616 ;
     RECT  0.192 41.616 0.205 41.64 ;
     RECT  0.156 41.64 0.205 41.712 ;
     RECT  0.192 41.712 0.205 41.736 ;
     RECT  0.156 41.736 0.205 41.808 ;
     RECT  0.192 41.808 0.205 41.832 ;
     RECT  0.156 41.832 0.205 41.904 ;
     RECT  0.192 41.904 0.205 41.928 ;
     RECT  0.156 41.928 0.205 42 ;
     RECT  0.192 42 0.205 42.024 ;
     RECT  0.156 42.024 0.205 42.096 ;
     RECT  0.192 42.096 0.205 42.12 ;
     RECT  0.156 42.12 0.205 42.24 ;
     RECT  0.192 42.24 0.205 42.264 ;
     RECT  0.156 42.264 0.205 42.336 ;
     RECT  0.192 42.336 0.205 42.36 ;
     RECT  0.156 42.36 0.205 42.432 ;
     RECT  0.192 42.432 0.205 42.456 ;
     RECT  0.156 42.456 0.205 42.528 ;
     RECT  0.192 42.528 0.205 42.552 ;
     RECT  0.156 42.552 0.205 42.624 ;
     RECT  0.192 42.624 0.205 42.648 ;
     RECT  0.156 42.648 0.205 42.768 ;
     RECT  0.192 42.768 0.205 42.792 ;
     RECT  0.156 42.792 0.205 42.864 ;
     RECT  0.192 42.864 0.205 42.888 ;
     RECT  0.156 42.888 0.205 42.96 ;
     RECT  0.192 42.96 0.205 42.984 ;
     RECT  0.156 42.984 0.205 43.056 ;
     RECT  0.192 43.056 0.205 43.08 ;
     RECT  0.156 43.08 0.205 43.152 ;
     RECT  0.192 43.152 0.205 43.176 ;
     RECT  0.156 43.176 0.205 43.296 ;
     RECT  0.192 43.296 0.205 43.32 ;
     RECT  0.156 43.32 0.205 43.392 ;
     RECT  0.192 43.392 0.205 43.416 ;
     RECT  0.156 43.416 0.205 43.488 ;
     RECT  0.192 43.488 0.205 43.512 ;
     RECT  0.156 43.512 0.205 43.584 ;
     RECT  0.192 43.584 0.205 43.608 ;
     RECT  0.156 43.608 0.205 43.68 ;
     RECT  0.192 43.68 0.205 43.704 ;
     RECT  0.156 43.704 0.205 43.824 ;
     RECT  0.192 43.824 0.205 43.848 ;
     RECT  0.156 43.848 0.205 43.92 ;
     RECT  0.192 43.92 0.205 43.944 ;
     RECT  0.156 43.944 0.205 44.016 ;
     RECT  0.192 44.016 0.205 44.04 ;
     RECT  0.156 44.04 0.205 44.112 ;
     RECT  0.192 44.112 0.205 44.136 ;
     RECT  0.156 44.136 0.205 44.208 ;
     RECT  0.192 44.208 0.205 44.232 ;
     RECT  0.156 44.232 0.205 44.352 ;
     RECT  0.192 44.352 0.205 44.376 ;
     RECT  0.156 44.376 0.205 44.448 ;
     RECT  0.192 44.448 0.205 44.472 ;
     RECT  0.156 44.472 0.205 44.544 ;
     RECT  0.192 44.544 0.205 44.568 ;
     RECT  0.156 44.568 0.205 44.64 ;
     RECT  0.192 44.64 0.205 44.664 ;
     RECT  0.156 44.664 0.205 44.736 ;
     RECT  0.192 44.736 0.205 44.76 ;
     RECT  0.156 44.76 0.205 44.88 ;
     RECT  0.192 44.88 0.205 44.904 ;
     RECT  0.156 44.904 0.205 44.976 ;
     RECT  0.192 44.976 0.205 45 ;
     RECT  0.156 45 0.205 45.072 ;
     RECT  0.192 45.072 0.205 45.096 ;
     RECT  0.156 45.096 0.205 45.168 ;
     RECT  0.192 45.168 0.205 45.192 ;
     RECT  0.156 45.192 0.205 45.264 ;
     RECT  0.192 45.264 0.205 45.288 ;
     RECT  0.156 45.288 0.205 45.36 ;
     RECT  0.192 45.36 0.205 45.384 ;
     RECT  0.156 45.384 0.205 45.504 ;
     RECT  0.192 45.504 0.205 45.528 ;
     RECT  0.156 45.528 0.205 45.6 ;
     RECT  0.192 45.6 0.205 45.624 ;
     RECT  0.156 45.624 0.205 45.696 ;
     RECT  0.192 45.696 0.205 45.72 ;
     RECT  0.156 45.72 0.205 45.792 ;
     RECT  0.192 45.792 0.205 45.816 ;
     RECT  0.156 45.816 0.205 45.888 ;
     RECT  0.192 45.888 0.205 45.912 ;
     RECT  0.156 45.912 0.205 46.032 ;
     RECT  0.192 46.032 0.205 46.056 ;
     RECT  0.156 46.056 0.205 46.128 ;
     RECT  0.192 46.128 0.205 46.152 ;
     RECT  0.156 46.152 0.205 46.224 ;
     RECT  0.192 46.224 0.205 46.248 ;
     RECT  0.156 46.248 0.205 46.32 ;
     RECT  0.192 46.32 0.205 46.344 ;
     RECT  0.156 46.344 0.205 46.416 ;
     RECT  0.192 46.416 0.205 46.44 ;
     RECT  0.156 46.44 0.205 46.56 ;
     RECT  0.192 46.56 0.205 46.584 ;
     RECT  0.156 46.584 0.205 46.656 ;
     RECT  0.192 46.656 0.205 46.68 ;
     RECT  0.156 46.68 0.205 46.752 ;
     RECT  0.192 46.752 0.205 46.776 ;
     RECT  0.156 46.776 0.205 46.848 ;
     RECT  0.192 46.848 0.205 46.872 ;
     RECT  0.156 46.872 0.205 46.944 ;
     RECT  0.192 46.944 0.205 46.968 ;
     RECT  0.156 46.968 0.205 47.088 ;
     RECT  0.192 47.088 0.205 47.112 ;
     RECT  0.156 47.112 0.205 47.184 ;
     RECT  0.192 47.184 0.205 47.208 ;
     RECT  0.156 47.208 0.205 47.28 ;
     RECT  0.192 47.28 0.205 47.304 ;
     RECT  0.156 47.304 0.205 47.376 ;
     RECT  0.192 47.376 0.205 47.4 ;
     RECT  0.156 47.4 0.205 47.472 ;
     RECT  0.192 47.472 0.205 47.496 ;
     RECT  0.156 47.496 0.205 47.616 ;
     RECT  0.192 47.616 0.205 47.64 ;
     RECT  0.156 47.64 0.205 47.712 ;
     RECT  0.192 47.712 0.205 47.736 ;
     RECT  0.156 47.736 0.205 47.808 ;
     RECT  0.192 47.808 0.205 47.832 ;
     RECT  0.156 47.832 0.205 47.904 ;
     RECT  0.192 47.904 0.205 47.928 ;
     RECT  0.156 47.928 0.205 48 ;
     RECT  0.192 48 0.205 48.024 ;
     RECT  0.156 48.024 0.205 48.096 ;
     RECT  0.192 48.096 0.205 48.12 ;
     RECT  0.156 48.12 0.205 48.24 ;
     RECT  0.192 48.24 0.205 48.264 ;
     RECT  0.156 48.264 0.205 48.336 ;
     RECT  0.192 48.336 0.205 48.36 ;
     RECT  0.156 48.36 0.205 48.432 ;
     RECT  0.192 48.432 0.205 48.456 ;
     RECT  0.156 48.456 0.205 48.528 ;
     RECT  0.192 48.528 0.205 48.552 ;
     RECT  0.156 48.552 0.205 48.624 ;
     RECT  0.192 48.624 0.205 48.648 ;
     RECT  0.156 48.648 0.205 48.768 ;
     RECT  0.192 48.768 0.205 48.792 ;
     RECT  0.156 48.792 0.205 48.864 ;
     RECT  0.192 48.864 0.205 48.888 ;
     RECT  0.156 48.888 0.205 48.96 ;
     RECT  0.192 48.96 0.205 48.984 ;
     RECT  0.156 48.984 0.205 49.056 ;
     RECT  0.192 49.056 0.205 49.08 ;
     RECT  0.156 49.08 0.205 49.152 ;
     RECT  0.192 49.152 0.205 49.176 ;
     RECT  0.156 49.176 0.205 49.296 ;
     RECT  0.192 49.296 0.205 49.32 ;
     RECT  0.156 49.32 0.205 49.392 ;
     RECT  0.192 49.392 0.205 49.416 ;
     RECT  0.156 49.416 0.205 49.488 ;
     RECT  0.192 49.488 0.205 49.512 ;
     RECT  0.156 49.512 0.205 49.584 ;
     RECT  0.192 49.584 0.205 49.608 ;
     RECT  0.156 49.608 0.205 49.68 ;
     RECT  0.192 49.68 0.205 49.704 ;
     RECT  0.156 49.704 0.205 49.824 ;
     RECT  0.192 49.824 0.205 49.848 ;
     RECT  0.156 49.848 0.205 49.92 ;
     RECT  0.192 49.92 0.205 49.944 ;
     RECT  0.156 49.944 0.205 50.016 ;
     RECT  0.192 50.016 0.205 50.04 ;
     RECT  0.156 50.04 0.205 50.112 ;
     RECT  0.192 50.112 0.205 50.136 ;
     RECT  0.156 50.136 0.205 50.208 ;
     RECT  0.192 50.208 0.205 50.232 ;
     RECT  0.156 50.232 0.205 50.352 ;
     RECT  0.192 50.352 0.205 50.376 ;
     RECT  0.156 50.376 0.205 50.448 ;
     RECT  0.192 50.448 0.205 50.472 ;
     RECT  0.156 50.472 0.205 50.544 ;
     RECT  0.192 50.544 0.205 50.568 ;
     RECT  0.156 50.568 0.205 50.64 ;
     RECT  0.192 50.64 0.205 50.664 ;
     RECT  0.156 50.664 0.205 50.736 ;
     RECT  0.192 50.736 0.205 50.76 ;
     RECT  0.156 50.76 0.205 50.88 ;
     RECT  0.192 50.88 0.205 50.904 ;
     RECT  0.156 50.904 0.205 50.976 ;
     RECT  0.192 50.976 0.205 51 ;
     RECT  0.156 51 0.205 51.072 ;
     RECT  0.192 51.072 0.205 51.096 ;
     RECT  0.156 51.096 0.205 51.168 ;
     RECT  0.192 51.168 0.205 51.192 ;
     RECT  0.156 51.192 0.205 51.264 ;
     RECT  0.192 51.264 0.205 51.288 ;
     RECT  0.156 51.288 0.205 51.36 ;
     RECT  0.192 51.36 0.205 51.384 ;
     RECT  0.156 51.384 0.205 51.504 ;
     RECT  0.192 51.504 0.205 51.528 ;
     RECT  0.156 51.528 0.205 51.6 ;
     RECT  0.192 51.6 0.205 51.624 ;
     RECT  0.156 51.624 0.205 51.696 ;
     RECT  0.192 51.696 0.205 51.72 ;
     RECT  0.156 51.72 0.205 51.792 ;
     RECT  0.192 51.792 0.205 51.816 ;
     RECT  0.156 51.816 0.205 51.888 ;
     RECT  0.192 51.888 0.205 51.912 ;
     RECT  0.156 51.912 0.205 52.032 ;
     RECT  0.192 52.032 0.205 52.056 ;
     RECT  0.156 52.056 0.205 52.128 ;
     RECT  0.192 52.128 0.205 52.152 ;
     RECT  0.156 52.152 0.205 52.224 ;
     RECT  0.192 52.224 0.205 52.248 ;
     RECT  0.156 52.248 0.205 52.32 ;
     RECT  0.192 52.32 0.205 52.344 ;
     RECT  0.156 52.344 0.205 52.416 ;
     RECT  0.192 52.416 0.205 52.44 ;
     RECT  0.156 52.44 0.205 52.56 ;
     RECT  0.192 52.56 0.205 52.584 ;
     RECT  0.156 52.584 0.205 52.656 ;
     RECT  0.192 52.656 0.205 52.68 ;
     RECT  0.156 52.68 0.205 52.752 ;
     RECT  0.192 52.752 0.205 52.776 ;
     RECT  0.156 52.776 0.205 52.848 ;
     RECT  0.192 52.848 0.205 52.872 ;
     RECT  0.156 52.872 0.205 52.944 ;
     RECT  0.192 52.944 0.205 52.968 ;
     RECT  0.156 52.968 0.205 53.088 ;
     RECT  0.192 53.088 0.205 53.112 ;
     RECT  0.156 53.112 0.205 53.184 ;
     RECT  0.192 53.184 0.205 53.208 ;
     RECT  0.156 53.208 0.205 53.28 ;
     RECT  0.192 53.28 0.205 53.304 ;
     RECT  0.156 53.304 0.205 53.376 ;
     RECT  0.192 53.376 0.205 53.4 ;
     RECT  0.156 53.4 0.205 53.472 ;
     RECT  0.192 53.472 0.205 53.496 ;
     RECT  0.156 53.496 0.205 53.616 ;
     RECT  0.192 53.616 0.205 53.64 ;
     RECT  0.156 53.64 0.205 53.712 ;
     RECT  0.192 53.712 0.205 53.736 ;
     RECT  0.156 53.736 0.205 53.808 ;
     RECT  0.192 53.808 0.205 53.832 ;
     RECT  0.156 53.832 0.205 53.904 ;
     RECT  0.192 53.904 0.205 53.928 ;
     RECT  0.156 53.928 0.205 54 ;
     RECT  0.192 54 0.205 54.024 ;
     RECT  0.156 54.024 0.205 54.096 ;
     RECT  0.192 54.096 0.205 54.12 ;
     RECT  0.156 54.12 0.205 54.24 ;
     RECT  0.192 54.24 0.205 54.264 ;
     RECT  0.156 54.264 0.205 54.336 ;
     RECT  0.192 54.336 0.205 54.36 ;
     RECT  0.156 54.36 0.205 54.432 ;
     RECT  0.192 54.432 0.205 54.456 ;
     RECT  0.156 54.456 0.205 54.528 ;
     RECT  0.192 54.528 0.205 54.552 ;
     RECT  0.156 54.552 0.205 54.624 ;
     RECT  0.192 54.624 0.205 54.648 ;
     RECT  0.156 54.648 0.205 54.768 ;
     RECT  0.192 54.768 0.205 54.792 ;
     RECT  0.156 54.792 0.205 54.864 ;
     RECT  0.192 54.864 0.205 54.888 ;
     RECT  0.156 54.888 0.205 54.96 ;
     RECT  0.192 54.96 0.205 54.984 ;
     RECT  0.156 54.984 0.205 55.056 ;
     RECT  0.192 55.056 0.205 55.08 ;
     RECT  0.156 55.08 0.205 55.152 ;
     RECT  0.192 55.152 0.205 55.176 ;
     RECT  0.156 55.176 0.205 55.296 ;
     RECT  0.192 55.296 0.205 55.32 ;
     RECT  0.156 55.32 0.205 55.392 ;
     RECT  0.192 55.392 0.205 55.416 ;
     RECT  0.156 55.416 0.205 55.488 ;
     RECT  0.192 55.488 0.205 55.512 ;
     RECT  0.156 55.512 0.205 55.584 ;
     RECT  0.192 55.584 0.205 55.608 ;
     RECT  0.156 55.608 0.205 55.68 ;
     RECT  0.192 55.68 0.205 55.704 ;
     RECT  0.156 55.704 0.205 55.824 ;
     RECT  0.192 55.824 0.205 55.848 ;
     RECT  0.156 55.848 0.205 55.92 ;
     RECT  0.192 55.92 0.205 55.944 ;
     RECT  0.156 55.944 0.205 56.016 ;
     RECT  0.192 56.016 0.205 56.04 ;
     RECT  0.156 56.04 0.205 56.112 ;
     RECT  0.192 56.112 0.205 56.136 ;
     RECT  0.205 2.064 3.125 56.28 ;
     RECT  3.125 2.064 3.593 55.992 ;
     RECT  3.593 2.544 4.025 55.992 ;
     RECT  4.025 14.64 4.061 49.896 ;
     RECT  4.025 2.544 4.133 13.656 ;
     RECT  4.133 2.544 5.108 2.616 ;
     RECT  4.133 3.6 5.108 7.176 ;
     RECT  4.133 8.256 5.108 13.656 ;
     RECT  4.061 14.64 5.108 49.848 ;
     RECT  4.025 50.928 5.108 55.992 ;
     RECT  5.108 2.148 5.212 56.172 ;
     RECT  5.212 2.418 5.404 55.992 ;
     RECT  5.404 29.232 5.573 39.528 ;
     RECT  5.389 57.6 5.603 57.624 ;
     RECT  5.404 2.736 5.681 7.128 ;
     RECT  5.404 53.568 5.699 55.992 ;
     RECT  5.404 10.608 6.389 17.976 ;
     RECT  5.404 18.96 6.397 26.664 ;
     RECT  5.404 27.696 6.397 28.2 ;
     RECT  5.404 41.088 6.433 44.664 ;
     RECT  5.404 45.744 6.433 48.696 ;
     RECT  5.404 50.928 6.541 52.248 ;
     RECT  6.541 50.112 6.577 52.248 ;
     RECT  5.404 8.16 6.613 9.24 ;
     RECT  6.389 10.224 6.613 17.976 ;
     RECT  6.397 18.96 6.613 28.2 ;
     RECT  5.573 29.232 6.613 37.176 ;
     RECT  6.433 41.088 6.649 48.696 ;
     RECT  6.577 49.872 6.649 52.248 ;
     RECT  5.573 38.16 6.685 39.528 ;
     RECT  6.649 41.088 6.685 52.248 ;
     RECT  5.681 6.576 6.793 7.128 ;
     RECT  6.613 8.16 6.793 17.976 ;
     RECT  6.685 38.16 6.793 52.248 ;
     RECT  5.699 53.568 6.793 55.512 ;
     RECT  5.681 2.736 6.829 5.544 ;
     RECT  6.793 6.576 6.829 17.976 ;
     RECT  6.829 2.736 6.865 17.976 ;
     RECT  6.613 18.96 7.009 37.176 ;
     RECT  6.793 38.16 7.009 52.296 ;
     RECT  6.793 53.328 7.153 55.512 ;
     RECT  6.865 2.352 7.189 17.976 ;
     RECT  7.009 18.96 7.189 52.296 ;
     RECT  7.153 53.328 7.189 56.088 ;
     RECT  7.189 2.352 7.808 56.088 ;
     RECT  7.808 2.148 7.912 56.172 ;
     RECT  7.912 2.352 10.508 56.088 ;
     RECT  10.508 2.148 10.612 56.172 ;
     RECT  10.612 2.352 10.757 56.088 ;
     RECT  10.757 2.418 10.804 56.088 ;
     RECT  10.804 2.448 13.208 56.088 ;
     RECT  13.208 2.148 13.312 56.172 ;
     RECT  13.312 2.418 13.504 56.088 ;
     RECT  13.504 2.784 14.821 56.088 ;
     RECT  14.821 2.448 14.857 56.088 ;
     RECT  14.857 2.352 14.861 56.088 ;
     RECT  14.861 2.352 16.513 56.04 ;
     RECT  16.513 2.208 17.088 2.232 ;
     RECT  16.513 2.232 17.1 2.352 ;
     RECT  16.513 2.352 17.088 2.376 ;
     RECT  16.513 2.376 17.1 2.448 ;
     RECT  16.513 2.448 17.088 2.472 ;
     RECT  16.513 2.472 17.1 2.544 ;
     RECT  16.513 2.544 17.088 2.568 ;
     RECT  16.513 2.568 17.1 2.64 ;
     RECT  16.513 2.64 17.088 2.664 ;
     RECT  16.513 2.664 17.1 2.736 ;
     RECT  16.513 2.736 17.088 2.76 ;
     RECT  16.513 2.76 17.1 2.88 ;
     RECT  16.513 2.88 17.088 2.904 ;
     RECT  16.513 2.904 17.1 2.976 ;
     RECT  16.513 2.976 17.088 3 ;
     RECT  16.513 3 17.1 3.072 ;
     RECT  16.513 3.072 17.088 3.096 ;
     RECT  16.513 3.096 17.1 3.168 ;
     RECT  16.513 3.168 17.088 3.192 ;
     RECT  16.513 3.192 17.1 3.264 ;
     RECT  16.513 3.264 17.088 3.288 ;
     RECT  16.513 3.288 17.1 3.408 ;
     RECT  16.513 3.408 17.088 3.432 ;
     RECT  16.513 3.432 17.1 3.504 ;
     RECT  16.513 3.504 17.088 3.528 ;
     RECT  16.513 3.528 17.1 3.6 ;
     RECT  16.513 3.6 17.088 3.624 ;
     RECT  16.513 3.624 17.1 3.696 ;
     RECT  16.513 3.696 17.088 3.72 ;
     RECT  16.513 3.72 17.1 3.792 ;
     RECT  16.513 3.792 17.088 3.816 ;
     RECT  16.513 3.816 17.1 3.936 ;
     RECT  16.513 3.936 17.088 3.96 ;
     RECT  16.513 3.96 17.1 4.032 ;
     RECT  16.513 4.032 17.088 4.056 ;
     RECT  16.513 4.056 17.1 4.128 ;
     RECT  16.513 4.128 17.088 4.152 ;
     RECT  16.513 4.152 17.1 4.224 ;
     RECT  16.513 4.224 17.088 4.248 ;
     RECT  16.513 4.248 17.1 4.32 ;
     RECT  16.513 4.32 17.088 4.344 ;
     RECT  16.513 4.344 17.1 4.416 ;
     RECT  16.513 4.416 17.088 4.44 ;
     RECT  16.513 4.44 17.1 4.56 ;
     RECT  16.513 4.56 17.088 4.584 ;
     RECT  16.513 4.584 17.1 4.656 ;
     RECT  16.513 4.656 17.088 4.68 ;
     RECT  16.513 4.68 17.1 4.752 ;
     RECT  16.513 4.752 17.088 4.776 ;
     RECT  16.513 4.776 17.1 4.848 ;
     RECT  16.513 4.848 17.088 4.872 ;
     RECT  16.513 4.872 17.1 4.944 ;
     RECT  16.513 4.944 17.088 4.968 ;
     RECT  16.513 4.968 17.1 5.088 ;
     RECT  16.513 5.088 17.088 5.112 ;
     RECT  16.513 5.112 17.1 5.184 ;
     RECT  16.513 5.184 17.088 5.208 ;
     RECT  16.513 5.208 17.1 5.28 ;
     RECT  16.513 5.28 17.088 5.304 ;
     RECT  16.513 5.304 17.1 5.376 ;
     RECT  16.513 5.376 17.088 5.4 ;
     RECT  16.513 5.4 17.1 5.472 ;
     RECT  16.513 5.472 17.088 5.496 ;
     RECT  16.513 5.496 17.1 5.616 ;
     RECT  16.513 5.616 17.088 5.64 ;
     RECT  16.513 5.64 17.1 5.712 ;
     RECT  16.513 5.712 17.088 5.736 ;
     RECT  16.513 5.736 17.1 5.808 ;
     RECT  16.513 5.808 17.088 5.832 ;
     RECT  16.513 5.832 17.1 5.904 ;
     RECT  16.513 5.904 17.088 5.928 ;
     RECT  16.513 5.928 17.1 6 ;
     RECT  16.513 6 17.088 6.024 ;
     RECT  16.513 6.024 17.1 6.144 ;
     RECT  16.513 6.144 17.088 6.168 ;
     RECT  16.513 6.168 17.1 6.24 ;
     RECT  16.513 6.24 17.088 6.264 ;
     RECT  16.513 6.264 17.1 6.336 ;
     RECT  16.513 6.336 17.088 6.36 ;
     RECT  16.513 6.36 17.1 6.432 ;
     RECT  16.513 6.432 17.088 6.456 ;
     RECT  16.513 6.456 17.1 6.528 ;
     RECT  16.513 6.528 17.088 6.552 ;
     RECT  16.513 6.552 17.1 6.672 ;
     RECT  16.513 6.672 17.088 6.696 ;
     RECT  16.513 6.696 17.1 6.768 ;
     RECT  16.513 6.768 17.088 6.792 ;
     RECT  16.513 6.792 17.1 6.864 ;
     RECT  16.513 6.864 17.088 6.888 ;
     RECT  16.513 6.888 17.1 6.96 ;
     RECT  16.513 6.96 17.088 6.984 ;
     RECT  16.513 6.984 17.1 7.056 ;
     RECT  16.513 7.056 17.088 7.08 ;
     RECT  16.513 7.08 17.1 7.2 ;
     RECT  16.513 7.2 17.088 7.224 ;
     RECT  16.513 7.224 17.1 7.296 ;
     RECT  16.513 7.296 17.088 7.32 ;
     RECT  16.513 7.32 17.1 7.392 ;
     RECT  16.513 7.392 17.088 7.416 ;
     RECT  16.513 7.416 17.1 7.488 ;
     RECT  16.513 7.488 17.088 7.512 ;
     RECT  16.513 7.512 17.1 7.584 ;
     RECT  16.513 7.584 17.088 7.608 ;
     RECT  16.513 7.608 17.1 7.728 ;
     RECT  16.513 7.728 17.088 7.752 ;
     RECT  16.513 7.752 17.1 7.824 ;
     RECT  16.513 7.824 17.088 7.848 ;
     RECT  16.513 7.848 17.1 7.92 ;
     RECT  16.513 7.92 17.088 7.944 ;
     RECT  16.513 7.944 17.1 8.016 ;
     RECT  16.513 8.016 17.088 8.04 ;
     RECT  16.513 8.04 17.1 8.112 ;
     RECT  16.513 8.112 17.088 8.136 ;
     RECT  16.513 8.136 17.1 8.256 ;
     RECT  16.513 8.256 17.088 8.28 ;
     RECT  16.513 8.28 17.1 8.352 ;
     RECT  16.513 8.352 17.088 8.376 ;
     RECT  16.513 8.376 17.1 8.448 ;
     RECT  16.513 8.448 17.088 8.472 ;
     RECT  16.513 8.472 17.1 8.544 ;
     RECT  16.513 8.544 17.088 8.568 ;
     RECT  16.513 8.568 17.1 8.64 ;
     RECT  16.513 8.64 17.088 8.664 ;
     RECT  16.513 8.664 17.1 8.784 ;
     RECT  16.513 8.784 17.088 8.808 ;
     RECT  16.513 8.808 17.1 8.88 ;
     RECT  16.513 8.88 17.088 8.904 ;
     RECT  16.513 8.904 17.1 8.976 ;
     RECT  16.513 8.976 17.088 9 ;
     RECT  16.513 9 17.1 9.072 ;
     RECT  16.513 9.072 17.088 9.096 ;
     RECT  16.513 9.096 17.1 9.168 ;
     RECT  16.513 9.168 17.088 9.192 ;
     RECT  16.513 9.192 17.1 9.312 ;
     RECT  16.513 9.312 17.088 9.336 ;
     RECT  16.513 9.336 17.1 9.408 ;
     RECT  16.513 9.408 17.088 9.432 ;
     RECT  16.513 9.432 17.1 9.504 ;
     RECT  16.513 9.504 17.088 9.528 ;
     RECT  16.513 9.528 17.1 9.6 ;
     RECT  16.513 9.6 17.088 9.624 ;
     RECT  16.513 9.624 17.1 9.696 ;
     RECT  16.513 9.696 17.088 9.72 ;
     RECT  16.513 9.72 17.1 9.84 ;
     RECT  16.513 9.84 17.088 9.864 ;
     RECT  16.513 9.864 17.1 9.936 ;
     RECT  16.513 9.936 17.088 9.96 ;
     RECT  16.513 9.96 17.1 10.032 ;
     RECT  16.513 10.032 17.088 10.056 ;
     RECT  16.513 10.056 17.1 10.128 ;
     RECT  16.513 10.128 17.088 10.152 ;
     RECT  16.513 10.152 17.1 10.224 ;
     RECT  16.513 10.224 17.088 10.248 ;
     RECT  16.513 10.248 17.1 10.368 ;
     RECT  16.513 10.368 17.088 10.392 ;
     RECT  16.513 10.392 17.1 10.464 ;
     RECT  16.513 10.464 17.088 10.488 ;
     RECT  16.513 10.488 17.1 10.56 ;
     RECT  16.513 10.56 17.088 10.584 ;
     RECT  16.513 10.584 17.1 10.656 ;
     RECT  16.513 10.656 17.088 10.68 ;
     RECT  16.513 10.68 17.1 10.752 ;
     RECT  16.513 10.752 17.088 10.776 ;
     RECT  16.513 10.776 17.1 10.896 ;
     RECT  16.513 10.896 17.088 10.92 ;
     RECT  16.513 10.92 17.1 10.992 ;
     RECT  16.513 10.992 17.088 11.016 ;
     RECT  16.513 11.016 17.1 11.088 ;
     RECT  16.513 11.088 17.088 11.112 ;
     RECT  16.513 11.112 17.1 11.184 ;
     RECT  16.513 11.184 17.088 11.208 ;
     RECT  16.513 11.208 17.1 11.28 ;
     RECT  16.513 11.28 17.088 11.304 ;
     RECT  16.513 11.304 17.1 11.424 ;
     RECT  16.513 11.424 17.088 11.448 ;
     RECT  16.513 11.448 17.1 11.52 ;
     RECT  16.513 11.52 17.088 11.544 ;
     RECT  16.513 11.544 17.1 11.616 ;
     RECT  16.513 11.616 17.088 11.64 ;
     RECT  16.513 11.64 17.1 11.712 ;
     RECT  16.513 11.712 17.088 11.736 ;
     RECT  16.513 11.736 17.1 11.808 ;
     RECT  16.513 11.808 17.088 11.832 ;
     RECT  16.513 11.832 17.1 11.904 ;
     RECT  16.513 11.904 17.088 11.928 ;
     RECT  16.513 11.928 17.1 12.048 ;
     RECT  16.513 12.048 17.088 12.072 ;
     RECT  16.513 12.072 17.1 12.144 ;
     RECT  16.513 12.144 17.088 12.168 ;
     RECT  16.513 12.168 17.1 12.24 ;
     RECT  16.513 12.24 17.088 12.264 ;
     RECT  16.513 12.264 17.1 12.336 ;
     RECT  16.513 12.336 17.088 12.36 ;
     RECT  16.513 12.36 17.1 12.432 ;
     RECT  16.513 12.432 17.088 12.456 ;
     RECT  16.513 12.456 17.1 12.576 ;
     RECT  16.513 12.576 17.088 12.6 ;
     RECT  16.513 12.6 17.1 12.672 ;
     RECT  16.513 12.672 17.088 12.696 ;
     RECT  16.513 12.696 17.1 12.768 ;
     RECT  16.513 12.768 17.088 12.792 ;
     RECT  16.513 12.792 17.1 12.864 ;
     RECT  16.513 12.864 17.088 12.888 ;
     RECT  16.513 12.888 17.1 12.96 ;
     RECT  16.513 12.96 17.088 12.984 ;
     RECT  16.513 12.984 17.1 13.104 ;
     RECT  16.513 13.104 17.088 13.128 ;
     RECT  16.513 13.128 17.1 13.2 ;
     RECT  16.513 13.2 17.088 13.224 ;
     RECT  16.513 13.224 17.1 13.296 ;
     RECT  16.513 13.296 17.088 13.32 ;
     RECT  16.513 13.32 17.1 13.392 ;
     RECT  16.513 13.392 17.088 13.416 ;
     RECT  16.513 13.416 17.1 13.488 ;
     RECT  16.513 13.488 17.088 13.512 ;
     RECT  16.513 13.512 17.1 13.632 ;
     RECT  16.513 13.632 17.088 13.656 ;
     RECT  16.513 13.656 17.1 13.728 ;
     RECT  16.513 13.728 17.088 13.752 ;
     RECT  16.513 13.752 17.1 13.824 ;
     RECT  16.513 13.824 17.088 13.848 ;
     RECT  16.513 13.848 17.1 13.92 ;
     RECT  16.513 13.92 17.088 13.944 ;
     RECT  16.513 13.944 17.1 14.016 ;
     RECT  16.513 14.016 17.088 14.04 ;
     RECT  16.513 14.04 17.1 14.16 ;
     RECT  16.513 14.16 17.088 14.184 ;
     RECT  16.513 14.184 17.1 14.256 ;
     RECT  16.513 14.256 17.088 14.28 ;
     RECT  16.513 14.28 17.1 14.352 ;
     RECT  16.513 14.352 17.088 14.376 ;
     RECT  16.513 14.376 17.1 14.448 ;
     RECT  16.513 14.448 17.088 14.472 ;
     RECT  16.513 14.472 17.1 14.544 ;
     RECT  16.513 14.544 17.088 14.568 ;
     RECT  16.513 14.568 17.1 14.688 ;
     RECT  16.513 14.688 17.088 14.712 ;
     RECT  16.513 14.712 17.1 14.784 ;
     RECT  16.513 14.784 17.088 14.808 ;
     RECT  16.513 14.808 17.1 14.88 ;
     RECT  16.513 14.88 17.088 14.904 ;
     RECT  16.513 14.904 17.1 14.976 ;
     RECT  16.513 14.976 17.088 15 ;
     RECT  16.513 15 17.1 15.072 ;
     RECT  16.513 15.072 17.088 15.096 ;
     RECT  16.513 15.096 17.1 15.216 ;
     RECT  16.513 15.216 17.088 15.24 ;
     RECT  16.513 15.24 17.1 15.312 ;
     RECT  16.513 15.312 17.088 15.336 ;
     RECT  16.513 15.336 17.1 15.408 ;
     RECT  16.513 15.408 17.088 15.432 ;
     RECT  16.513 15.432 17.1 15.504 ;
     RECT  16.513 15.504 17.088 15.528 ;
     RECT  16.513 15.528 17.1 15.6 ;
     RECT  16.513 15.6 17.088 15.624 ;
     RECT  16.513 15.624 17.1 15.744 ;
     RECT  16.513 15.744 17.088 15.768 ;
     RECT  16.513 15.768 17.1 15.84 ;
     RECT  16.513 15.84 17.088 15.864 ;
     RECT  16.513 15.864 17.1 15.936 ;
     RECT  16.513 15.936 17.088 15.96 ;
     RECT  16.513 15.96 17.1 16.032 ;
     RECT  16.513 16.032 17.088 16.056 ;
     RECT  16.513 16.056 17.1 16.128 ;
     RECT  16.513 16.128 17.088 16.152 ;
     RECT  16.513 16.152 17.1 16.272 ;
     RECT  16.513 16.272 17.088 16.296 ;
     RECT  16.513 16.296 17.1 16.368 ;
     RECT  16.513 16.368 17.088 16.392 ;
     RECT  16.513 16.392 17.1 16.464 ;
     RECT  16.513 16.464 17.088 16.488 ;
     RECT  16.513 16.488 17.1 16.56 ;
     RECT  16.513 16.56 17.088 16.584 ;
     RECT  16.513 16.584 17.1 16.656 ;
     RECT  16.513 16.656 17.088 16.68 ;
     RECT  16.513 16.68 17.1 16.8 ;
     RECT  16.513 16.8 17.088 16.824 ;
     RECT  16.513 16.824 17.1 16.896 ;
     RECT  16.513 16.896 17.088 16.92 ;
     RECT  16.513 16.92 17.1 16.992 ;
     RECT  16.513 16.992 17.088 17.016 ;
     RECT  16.513 17.016 17.1 17.088 ;
     RECT  16.513 17.088 17.088 17.112 ;
     RECT  16.513 17.112 17.1 17.184 ;
     RECT  16.513 17.184 17.088 17.208 ;
     RECT  16.513 17.208 17.1 17.328 ;
     RECT  16.513 17.328 17.088 17.352 ;
     RECT  16.513 17.352 17.1 17.424 ;
     RECT  16.513 17.424 17.088 17.448 ;
     RECT  16.513 17.448 17.1 17.52 ;
     RECT  16.513 17.52 17.088 17.544 ;
     RECT  16.513 17.544 17.1 17.616 ;
     RECT  16.513 17.616 17.088 17.64 ;
     RECT  16.513 17.64 17.1 17.712 ;
     RECT  16.513 17.712 17.088 17.736 ;
     RECT  16.513 17.736 17.1 17.856 ;
     RECT  16.513 17.856 17.088 17.88 ;
     RECT  16.513 17.88 17.1 17.952 ;
     RECT  16.513 17.952 17.088 17.976 ;
     RECT  16.513 17.976 17.1 18.048 ;
     RECT  16.513 18.048 17.088 18.072 ;
     RECT  16.513 18.072 17.1 18.144 ;
     RECT  16.513 18.144 17.088 18.168 ;
     RECT  16.513 18.168 17.1 18.24 ;
     RECT  16.513 18.24 17.088 18.264 ;
     RECT  16.513 18.264 17.1 18.384 ;
     RECT  16.513 18.384 17.088 18.408 ;
     RECT  16.513 18.408 17.1 18.48 ;
     RECT  16.513 18.48 17.088 18.504 ;
     RECT  16.513 18.504 17.1 18.576 ;
     RECT  16.513 18.576 17.088 18.6 ;
     RECT  16.513 18.6 17.1 18.672 ;
     RECT  16.513 18.672 17.088 18.696 ;
     RECT  16.513 18.696 17.1 18.768 ;
     RECT  16.513 18.768 17.088 18.792 ;
     RECT  16.513 18.792 17.1 18.912 ;
     RECT  16.513 18.912 17.088 18.936 ;
     RECT  16.513 18.936 17.1 19.008 ;
     RECT  16.513 19.008 17.088 19.032 ;
     RECT  16.513 19.032 17.1 19.104 ;
     RECT  16.513 19.104 17.088 19.128 ;
     RECT  16.513 19.128 17.1 19.2 ;
     RECT  16.513 19.2 17.088 19.224 ;
     RECT  16.513 19.224 17.1 19.296 ;
     RECT  16.513 19.296 17.088 19.32 ;
     RECT  16.513 19.32 17.1 19.44 ;
     RECT  16.513 19.44 17.088 19.464 ;
     RECT  16.513 19.464 17.1 19.536 ;
     RECT  16.513 19.536 17.088 19.56 ;
     RECT  16.513 19.56 17.1 19.632 ;
     RECT  16.513 19.632 17.088 19.656 ;
     RECT  16.513 19.656 17.1 19.728 ;
     RECT  16.513 19.728 17.088 19.752 ;
     RECT  16.513 19.752 17.1 19.824 ;
     RECT  16.513 19.824 17.088 19.848 ;
     RECT  16.513 19.848 17.1 19.92 ;
     RECT  16.513 19.92 17.088 19.944 ;
     RECT  16.513 19.944 17.1 20.064 ;
     RECT  16.513 20.064 17.088 20.088 ;
     RECT  16.513 20.088 17.1 20.16 ;
     RECT  16.513 20.16 17.088 20.184 ;
     RECT  16.513 20.184 17.1 20.256 ;
     RECT  16.513 20.256 17.088 20.28 ;
     RECT  16.513 20.28 17.1 20.352 ;
     RECT  16.513 20.352 17.088 20.376 ;
     RECT  16.513 20.376 17.1 20.448 ;
     RECT  16.513 20.448 17.088 20.472 ;
     RECT  16.513 20.472 17.1 20.592 ;
     RECT  16.513 20.592 17.088 20.616 ;
     RECT  16.513 20.616 17.1 20.688 ;
     RECT  16.513 20.688 17.088 20.712 ;
     RECT  16.513 20.712 17.1 20.784 ;
     RECT  16.513 20.784 17.088 20.808 ;
     RECT  16.513 20.808 17.1 20.88 ;
     RECT  16.513 20.88 17.088 20.904 ;
     RECT  16.513 20.904 17.1 20.976 ;
     RECT  16.513 20.976 17.088 21 ;
     RECT  16.513 21 17.1 21.12 ;
     RECT  16.513 21.12 17.088 21.144 ;
     RECT  16.513 21.144 17.1 21.216 ;
     RECT  16.513 21.216 17.088 21.24 ;
     RECT  16.513 21.24 17.1 21.312 ;
     RECT  16.513 21.312 17.088 21.336 ;
     RECT  16.513 21.336 17.1 21.408 ;
     RECT  16.513 21.408 17.088 21.432 ;
     RECT  16.513 21.432 17.1 21.504 ;
     RECT  16.513 21.504 17.088 21.528 ;
     RECT  16.513 21.528 17.1 21.648 ;
     RECT  16.513 21.648 17.088 21.672 ;
     RECT  16.513 21.672 17.1 21.744 ;
     RECT  16.513 21.744 17.088 21.768 ;
     RECT  16.513 21.768 17.1 21.84 ;
     RECT  16.513 21.84 17.088 21.864 ;
     RECT  16.513 21.864 17.1 21.936 ;
     RECT  16.513 21.936 17.088 21.96 ;
     RECT  16.513 21.96 17.1 22.032 ;
     RECT  16.513 22.032 17.088 22.056 ;
     RECT  16.513 22.056 17.1 22.176 ;
     RECT  16.513 22.176 17.088 22.2 ;
     RECT  16.513 22.2 17.1 22.272 ;
     RECT  16.513 22.272 17.088 22.296 ;
     RECT  16.513 22.296 17.1 22.368 ;
     RECT  16.513 22.368 17.088 22.392 ;
     RECT  16.513 22.392 17.1 22.464 ;
     RECT  16.513 22.464 17.088 22.488 ;
     RECT  16.513 22.488 17.1 22.56 ;
     RECT  16.513 22.56 17.088 22.584 ;
     RECT  16.513 22.584 17.1 22.704 ;
     RECT  16.513 22.704 17.088 22.728 ;
     RECT  16.513 22.728 17.1 22.8 ;
     RECT  16.513 22.8 17.088 22.824 ;
     RECT  16.513 22.824 17.1 22.896 ;
     RECT  16.513 22.896 17.088 22.92 ;
     RECT  16.513 22.92 17.1 22.992 ;
     RECT  16.513 22.992 17.088 23.016 ;
     RECT  16.513 23.016 17.1 23.088 ;
     RECT  16.513 23.088 17.088 23.112 ;
     RECT  16.513 23.112 17.1 23.232 ;
     RECT  16.513 23.232 17.088 23.256 ;
     RECT  16.513 23.256 17.1 23.328 ;
     RECT  16.513 23.328 17.088 23.352 ;
     RECT  16.513 23.352 17.1 23.424 ;
     RECT  16.513 23.424 17.088 23.448 ;
     RECT  16.513 23.448 17.1 23.52 ;
     RECT  16.513 23.52 17.088 23.544 ;
     RECT  16.513 23.544 17.1 23.616 ;
     RECT  16.513 23.616 17.088 23.64 ;
     RECT  16.513 23.64 17.1 23.76 ;
     RECT  16.513 23.76 17.088 23.784 ;
     RECT  16.513 23.784 17.1 23.856 ;
     RECT  16.513 23.856 17.088 23.88 ;
     RECT  16.513 23.88 17.1 23.952 ;
     RECT  16.513 23.952 17.088 23.976 ;
     RECT  16.513 23.976 17.1 24.048 ;
     RECT  16.513 24.048 17.088 24.072 ;
     RECT  16.513 24.072 17.1 24.144 ;
     RECT  16.513 24.144 17.088 24.168 ;
     RECT  16.513 24.168 17.1 24.288 ;
     RECT  16.513 24.288 17.088 24.312 ;
     RECT  16.513 24.312 17.1 24.384 ;
     RECT  16.513 24.384 17.088 24.408 ;
     RECT  16.513 24.408 17.1 24.48 ;
     RECT  16.513 24.48 17.088 24.504 ;
     RECT  16.513 24.504 17.1 24.576 ;
     RECT  16.513 24.576 17.088 24.6 ;
     RECT  16.513 24.6 17.1 24.672 ;
     RECT  16.513 24.672 17.088 24.696 ;
     RECT  16.513 24.696 17.1 24.816 ;
     RECT  16.513 24.816 17.088 24.84 ;
     RECT  16.513 24.84 17.1 24.912 ;
     RECT  16.513 24.912 17.088 24.936 ;
     RECT  16.513 24.936 17.1 25.008 ;
     RECT  16.513 25.008 17.088 25.032 ;
     RECT  16.513 25.032 17.1 25.104 ;
     RECT  16.513 25.104 17.088 25.128 ;
     RECT  16.513 25.128 17.1 25.2 ;
     RECT  16.513 25.2 17.088 25.224 ;
     RECT  16.513 25.224 17.1 25.344 ;
     RECT  16.513 25.344 17.088 25.368 ;
     RECT  16.513 25.368 17.1 25.44 ;
     RECT  16.513 25.44 17.088 25.464 ;
     RECT  16.513 25.464 17.1 25.536 ;
     RECT  16.513 25.536 17.088 25.56 ;
     RECT  16.513 25.56 17.1 25.632 ;
     RECT  16.513 25.632 17.088 25.656 ;
     RECT  16.513 25.656 17.1 25.728 ;
     RECT  16.513 25.728 17.088 25.752 ;
     RECT  16.513 25.752 17.1 25.872 ;
     RECT  16.513 25.872 17.088 25.896 ;
     RECT  16.513 25.896 17.1 25.968 ;
     RECT  16.513 25.968 17.088 25.992 ;
     RECT  16.513 25.992 17.1 26.064 ;
     RECT  16.513 26.064 17.088 26.088 ;
     RECT  16.513 26.088 17.1 26.16 ;
     RECT  16.513 26.16 17.088 26.184 ;
     RECT  16.513 26.184 17.1 26.256 ;
     RECT  16.513 26.256 17.088 26.28 ;
     RECT  16.513 26.28 17.1 26.4 ;
     RECT  16.513 26.4 17.088 26.424 ;
     RECT  16.513 26.424 17.1 26.496 ;
     RECT  16.513 26.496 17.088 26.52 ;
     RECT  16.513 26.52 17.1 26.592 ;
     RECT  16.513 26.592 17.088 26.616 ;
     RECT  16.513 26.616 17.1 26.688 ;
     RECT  16.513 26.688 17.088 26.712 ;
     RECT  16.513 26.712 17.1 26.784 ;
     RECT  16.513 26.784 17.088 26.808 ;
     RECT  16.513 26.808 17.1 26.928 ;
     RECT  16.513 26.928 17.088 26.952 ;
     RECT  16.513 26.952 17.1 27.024 ;
     RECT  16.513 27.024 17.088 27.048 ;
     RECT  16.513 27.048 17.1 27.12 ;
     RECT  16.513 27.12 17.088 27.144 ;
     RECT  16.513 27.144 17.1 27.216 ;
     RECT  16.513 27.216 17.088 27.24 ;
     RECT  16.513 27.24 17.1 27.312 ;
     RECT  16.513 27.312 17.088 27.336 ;
     RECT  16.513 27.336 17.1 27.408 ;
     RECT  16.513 27.408 17.088 27.432 ;
     RECT  16.513 27.432 17.1 27.552 ;
     RECT  16.513 27.552 17.088 27.576 ;
     RECT  16.513 27.576 17.1 27.648 ;
     RECT  16.513 27.648 17.088 27.672 ;
     RECT  16.513 27.672 17.1 27.744 ;
     RECT  16.513 27.744 17.088 27.768 ;
     RECT  16.513 27.768 17.1 27.84 ;
     RECT  16.513 27.84 17.088 27.864 ;
     RECT  16.513 27.864 17.1 27.936 ;
     RECT  16.513 27.936 17.088 27.96 ;
     RECT  16.513 27.96 17.1 28.08 ;
     RECT  16.513 28.08 17.088 28.104 ;
     RECT  16.513 28.104 17.1 28.176 ;
     RECT  16.513 28.176 17.088 28.2 ;
     RECT  16.513 28.2 17.1 28.272 ;
     RECT  16.513 28.272 17.088 28.296 ;
     RECT  16.513 28.296 17.1 28.368 ;
     RECT  16.513 28.368 17.088 28.392 ;
     RECT  16.513 28.392 17.1 28.464 ;
     RECT  16.513 28.464 17.088 28.488 ;
     RECT  16.513 28.488 17.1 28.608 ;
     RECT  16.513 28.608 17.088 28.632 ;
     RECT  16.513 28.632 17.1 28.704 ;
     RECT  16.513 28.704 17.088 28.728 ;
     RECT  16.513 28.728 17.1 28.8 ;
     RECT  16.513 28.8 17.088 28.824 ;
     RECT  16.513 28.824 17.1 28.896 ;
     RECT  16.513 28.896 17.088 28.92 ;
     RECT  16.513 28.92 17.1 28.992 ;
     RECT  16.513 28.992 17.088 29.016 ;
     RECT  16.513 29.016 17.1 29.136 ;
     RECT  16.513 29.136 17.088 29.16 ;
     RECT  16.513 29.16 17.1 29.232 ;
     RECT  16.513 29.232 17.088 29.256 ;
     RECT  16.513 29.256 17.1 29.328 ;
     RECT  16.513 29.328 17.088 29.352 ;
     RECT  16.513 29.352 17.1 29.424 ;
     RECT  16.513 29.424 17.088 29.448 ;
     RECT  16.513 29.448 17.1 29.52 ;
     RECT  16.513 29.52 17.088 29.544 ;
     RECT  16.513 29.544 17.1 29.664 ;
     RECT  16.513 29.664 17.088 29.688 ;
     RECT  16.513 29.688 17.1 29.76 ;
     RECT  16.513 29.76 17.088 29.784 ;
     RECT  16.513 29.784 17.1 29.856 ;
     RECT  16.513 29.856 17.088 29.88 ;
     RECT  16.513 29.88 17.1 29.952 ;
     RECT  16.513 29.952 17.088 29.976 ;
     RECT  16.513 29.976 17.1 30.048 ;
     RECT  16.513 30.048 17.088 30.072 ;
     RECT  16.513 30.072 17.1 30.192 ;
     RECT  16.513 30.192 17.088 30.216 ;
     RECT  16.513 30.216 17.1 30.288 ;
     RECT  16.513 30.288 17.088 30.312 ;
     RECT  16.513 30.312 17.1 30.384 ;
     RECT  16.513 30.384 17.088 30.408 ;
     RECT  16.513 30.408 17.1 30.48 ;
     RECT  16.513 30.48 17.088 30.504 ;
     RECT  16.513 30.504 17.1 30.576 ;
     RECT  16.513 30.576 17.088 30.6 ;
     RECT  16.513 30.6 17.1 30.72 ;
     RECT  16.513 30.72 17.088 30.744 ;
     RECT  16.513 30.744 17.1 30.816 ;
     RECT  16.513 30.816 17.088 30.84 ;
     RECT  16.513 30.84 17.1 30.912 ;
     RECT  16.513 30.912 17.088 30.936 ;
     RECT  16.513 30.936 17.1 31.008 ;
     RECT  16.513 31.008 17.088 31.032 ;
     RECT  16.513 31.032 17.1 31.104 ;
     RECT  16.513 31.104 17.088 31.128 ;
     RECT  16.513 31.128 17.1 31.248 ;
     RECT  16.513 31.248 17.088 31.272 ;
     RECT  16.513 31.272 17.1 31.344 ;
     RECT  16.513 31.344 17.088 31.368 ;
     RECT  16.513 31.368 17.1 31.44 ;
     RECT  16.513 31.44 17.088 31.464 ;
     RECT  16.513 31.464 17.1 31.536 ;
     RECT  16.513 31.536 17.088 31.56 ;
     RECT  16.513 31.56 17.1 31.632 ;
     RECT  16.513 31.632 17.088 31.656 ;
     RECT  16.513 31.656 17.1 31.776 ;
     RECT  16.513 31.776 17.088 31.8 ;
     RECT  16.513 31.8 17.1 31.872 ;
     RECT  16.513 31.872 17.088 31.896 ;
     RECT  16.513 31.896 17.1 31.968 ;
     RECT  16.513 31.968 17.088 31.992 ;
     RECT  16.513 31.992 17.1 32.064 ;
     RECT  16.513 32.064 17.088 32.088 ;
     RECT  16.513 32.088 17.1 32.16 ;
     RECT  16.513 32.16 17.088 32.184 ;
     RECT  16.513 32.184 17.1 32.304 ;
     RECT  16.513 32.304 17.088 32.328 ;
     RECT  16.513 32.328 17.1 32.4 ;
     RECT  16.513 32.4 17.088 32.424 ;
     RECT  16.513 32.424 17.1 32.496 ;
     RECT  16.513 32.496 17.088 32.52 ;
     RECT  16.513 32.52 17.1 32.592 ;
     RECT  16.513 32.592 17.088 32.616 ;
     RECT  16.513 32.616 17.1 32.688 ;
     RECT  16.513 32.688 17.088 32.712 ;
     RECT  16.513 32.712 17.1 32.832 ;
     RECT  16.513 32.832 17.088 32.856 ;
     RECT  16.513 32.856 17.1 32.928 ;
     RECT  16.513 32.928 17.088 32.952 ;
     RECT  16.513 32.952 17.1 33.024 ;
     RECT  16.513 33.024 17.088 33.048 ;
     RECT  16.513 33.048 17.1 33.12 ;
     RECT  16.513 33.12 17.088 33.144 ;
     RECT  16.513 33.144 17.1 33.216 ;
     RECT  16.513 33.216 17.088 33.24 ;
     RECT  16.513 33.24 17.1 33.36 ;
     RECT  16.513 33.36 17.088 33.384 ;
     RECT  16.513 33.384 17.1 33.456 ;
     RECT  16.513 33.456 17.088 33.48 ;
     RECT  16.513 33.48 17.1 33.552 ;
     RECT  16.513 33.552 17.088 33.576 ;
     RECT  16.513 33.576 17.1 33.648 ;
     RECT  16.513 33.648 17.088 33.672 ;
     RECT  16.513 33.672 17.1 33.744 ;
     RECT  16.513 33.744 17.088 33.768 ;
     RECT  16.513 33.768 17.1 33.888 ;
     RECT  16.513 33.888 17.088 33.912 ;
     RECT  16.513 33.912 17.1 33.984 ;
     RECT  16.513 33.984 17.088 34.008 ;
     RECT  16.513 34.008 17.1 34.08 ;
     RECT  16.513 34.08 17.088 34.104 ;
     RECT  16.513 34.104 17.1 34.176 ;
     RECT  16.513 34.176 17.088 34.2 ;
     RECT  16.513 34.2 17.1 34.272 ;
     RECT  16.513 34.272 17.088 34.296 ;
     RECT  16.513 34.296 17.1 34.416 ;
     RECT  16.513 34.416 17.088 34.44 ;
     RECT  16.513 34.44 17.1 34.512 ;
     RECT  16.513 34.512 17.088 34.536 ;
     RECT  16.513 34.536 17.1 34.608 ;
     RECT  16.513 34.608 17.088 34.632 ;
     RECT  16.513 34.632 17.1 34.704 ;
     RECT  16.513 34.704 17.088 34.728 ;
     RECT  16.513 34.728 17.1 34.8 ;
     RECT  16.513 34.8 17.088 34.824 ;
     RECT  16.513 34.824 17.1 34.944 ;
     RECT  16.513 34.944 17.088 34.968 ;
     RECT  16.513 34.968 17.1 35.04 ;
     RECT  16.513 35.04 17.088 35.064 ;
     RECT  16.513 35.064 17.1 35.136 ;
     RECT  16.513 35.136 17.088 35.16 ;
     RECT  16.513 35.16 17.1 35.232 ;
     RECT  16.513 35.232 17.088 35.256 ;
     RECT  16.513 35.256 17.1 35.328 ;
     RECT  16.513 35.328 17.088 35.352 ;
     RECT  16.513 35.352 17.1 35.424 ;
     RECT  16.513 35.424 17.088 35.448 ;
     RECT  16.513 35.448 17.1 35.568 ;
     RECT  16.513 35.568 17.088 35.592 ;
     RECT  16.513 35.592 17.1 35.664 ;
     RECT  16.513 35.664 17.088 35.688 ;
     RECT  16.513 35.688 17.1 35.76 ;
     RECT  16.513 35.76 17.088 35.784 ;
     RECT  16.513 35.784 17.1 35.856 ;
     RECT  16.513 35.856 17.088 35.88 ;
     RECT  16.513 35.88 17.1 35.952 ;
     RECT  16.513 35.952 17.088 35.976 ;
     RECT  16.513 35.976 17.1 36.096 ;
     RECT  16.513 36.096 17.088 36.12 ;
     RECT  16.513 36.12 17.1 36.192 ;
     RECT  16.513 36.192 17.088 36.216 ;
     RECT  16.513 36.216 17.1 36.288 ;
     RECT  16.513 36.288 17.088 36.312 ;
     RECT  16.513 36.312 17.1 36.384 ;
     RECT  16.513 36.384 17.088 36.408 ;
     RECT  16.513 36.408 17.1 36.48 ;
     RECT  16.513 36.48 17.088 36.504 ;
     RECT  16.513 36.504 17.1 36.624 ;
     RECT  16.513 36.624 17.088 36.648 ;
     RECT  16.513 36.648 17.1 36.72 ;
     RECT  16.513 36.72 17.088 36.744 ;
     RECT  16.513 36.744 17.1 36.816 ;
     RECT  16.513 36.816 17.088 36.84 ;
     RECT  16.513 36.84 17.1 36.912 ;
     RECT  16.513 36.912 17.088 36.936 ;
     RECT  16.513 36.936 17.1 37.008 ;
     RECT  16.513 37.008 17.088 37.032 ;
     RECT  16.513 37.032 17.1 37.152 ;
     RECT  16.513 37.152 17.088 37.176 ;
     RECT  16.513 37.176 17.1 37.248 ;
     RECT  16.513 37.248 17.088 37.272 ;
     RECT  16.513 37.272 17.1 37.344 ;
     RECT  16.513 37.344 17.088 37.368 ;
     RECT  16.513 37.368 17.1 37.44 ;
     RECT  16.513 37.44 17.088 37.464 ;
     RECT  16.513 37.464 17.1 37.536 ;
     RECT  16.513 37.536 17.088 37.56 ;
     RECT  16.513 37.56 17.1 37.68 ;
     RECT  16.513 37.68 17.088 37.704 ;
     RECT  16.513 37.704 17.1 37.776 ;
     RECT  16.513 37.776 17.088 37.8 ;
     RECT  16.513 37.8 17.1 37.872 ;
     RECT  16.513 37.872 17.088 37.896 ;
     RECT  16.513 37.896 17.1 37.968 ;
     RECT  16.513 37.968 17.088 37.992 ;
     RECT  16.513 37.992 17.1 38.064 ;
     RECT  16.513 38.064 17.088 38.088 ;
     RECT  16.513 38.088 17.1 38.208 ;
     RECT  16.513 38.208 17.088 38.232 ;
     RECT  16.513 38.232 17.1 38.304 ;
     RECT  16.513 38.304 17.088 38.328 ;
     RECT  16.513 38.328 17.1 38.4 ;
     RECT  16.513 38.4 17.088 38.424 ;
     RECT  16.513 38.424 17.1 38.496 ;
     RECT  16.513 38.496 17.088 38.52 ;
     RECT  16.513 38.52 17.1 38.592 ;
     RECT  16.513 38.592 17.088 38.616 ;
     RECT  16.513 38.616 17.1 38.736 ;
     RECT  16.513 38.736 17.088 38.76 ;
     RECT  16.513 38.76 17.1 38.832 ;
     RECT  16.513 38.832 17.088 38.856 ;
     RECT  16.513 38.856 17.1 38.928 ;
     RECT  16.513 38.928 17.088 38.952 ;
     RECT  16.513 38.952 17.1 39.024 ;
     RECT  16.513 39.024 17.088 39.048 ;
     RECT  16.513 39.048 17.1 39.12 ;
     RECT  16.513 39.12 17.088 39.144 ;
     RECT  16.513 39.144 17.1 39.264 ;
     RECT  16.513 39.264 17.088 39.288 ;
     RECT  16.513 39.288 17.1 39.36 ;
     RECT  16.513 39.36 17.088 39.384 ;
     RECT  16.513 39.384 17.1 39.456 ;
     RECT  16.513 39.456 17.088 39.48 ;
     RECT  16.513 39.48 17.1 39.552 ;
     RECT  16.513 39.552 17.088 39.576 ;
     RECT  16.513 39.576 17.1 39.648 ;
     RECT  16.513 39.648 17.088 39.672 ;
     RECT  16.513 39.672 17.1 39.792 ;
     RECT  16.513 39.792 17.088 39.816 ;
     RECT  16.513 39.816 17.1 39.888 ;
     RECT  16.513 39.888 17.088 39.912 ;
     RECT  16.513 39.912 17.1 39.984 ;
     RECT  16.513 39.984 17.088 40.008 ;
     RECT  16.513 40.008 17.1 40.08 ;
     RECT  16.513 40.08 17.088 40.104 ;
     RECT  16.513 40.104 17.1 40.176 ;
     RECT  16.513 40.176 17.088 40.2 ;
     RECT  16.513 40.2 17.1 40.32 ;
     RECT  16.513 40.32 17.088 40.344 ;
     RECT  16.513 40.344 17.1 40.416 ;
     RECT  16.513 40.416 17.088 40.44 ;
     RECT  16.513 40.44 17.1 40.512 ;
     RECT  16.513 40.512 17.088 40.536 ;
     RECT  16.513 40.536 17.1 40.608 ;
     RECT  16.513 40.608 17.088 40.632 ;
     RECT  16.513 40.632 17.1 40.704 ;
     RECT  16.513 40.704 17.088 40.728 ;
     RECT  16.513 40.728 17.1 40.848 ;
     RECT  16.513 40.848 17.088 40.872 ;
     RECT  16.513 40.872 17.1 40.944 ;
     RECT  16.513 40.944 17.088 40.968 ;
     RECT  16.513 40.968 17.1 41.04 ;
     RECT  16.513 41.04 17.088 41.064 ;
     RECT  16.513 41.064 17.1 41.136 ;
     RECT  16.513 41.136 17.088 41.16 ;
     RECT  16.513 41.16 17.1 41.232 ;
     RECT  16.513 41.232 17.088 41.256 ;
     RECT  16.513 41.256 17.1 41.376 ;
     RECT  16.513 41.376 17.088 41.4 ;
     RECT  16.513 41.4 17.1 41.472 ;
     RECT  16.513 41.472 17.088 41.496 ;
     RECT  16.513 41.496 17.1 41.568 ;
     RECT  16.513 41.568 17.088 41.592 ;
     RECT  16.513 41.592 17.1 41.664 ;
     RECT  16.513 41.664 17.088 41.688 ;
     RECT  16.513 41.688 17.1 41.76 ;
     RECT  16.513 41.76 17.088 41.784 ;
     RECT  16.513 41.784 17.1 41.904 ;
     RECT  16.513 41.904 17.088 41.928 ;
     RECT  16.513 41.928 17.1 42 ;
     RECT  16.513 42 17.088 42.024 ;
     RECT  16.513 42.024 17.1 42.096 ;
     RECT  16.513 42.096 17.088 42.12 ;
     RECT  16.513 42.12 17.1 42.192 ;
     RECT  16.513 42.192 17.088 42.216 ;
     RECT  16.513 42.216 17.1 42.288 ;
     RECT  16.513 42.288 17.088 42.312 ;
     RECT  16.513 42.312 17.1 42.432 ;
     RECT  16.513 42.432 17.088 42.456 ;
     RECT  16.513 42.456 17.1 42.528 ;
     RECT  16.513 42.528 17.088 42.552 ;
     RECT  16.513 42.552 17.1 42.624 ;
     RECT  16.513 42.624 17.088 42.648 ;
     RECT  16.513 42.648 17.1 42.72 ;
     RECT  16.513 42.72 17.088 42.744 ;
     RECT  16.513 42.744 17.1 42.816 ;
     RECT  16.513 42.816 17.088 42.84 ;
     RECT  16.513 42.84 17.1 42.912 ;
     RECT  16.513 42.912 17.088 42.936 ;
     RECT  16.513 42.936 17.1 43.056 ;
     RECT  16.513 43.056 17.088 43.08 ;
     RECT  16.513 43.08 17.1 43.152 ;
     RECT  16.513 43.152 17.088 43.176 ;
     RECT  16.513 43.176 17.1 43.248 ;
     RECT  16.513 43.248 17.088 43.272 ;
     RECT  16.513 43.272 17.1 43.344 ;
     RECT  16.513 43.344 17.088 43.368 ;
     RECT  16.513 43.368 17.1 43.44 ;
     RECT  16.513 43.44 17.088 43.464 ;
     RECT  16.513 43.464 17.1 43.584 ;
     RECT  16.513 43.584 17.088 43.608 ;
     RECT  16.513 43.608 17.1 43.68 ;
     RECT  16.513 43.68 17.088 43.704 ;
     RECT  16.513 43.704 17.1 43.776 ;
     RECT  16.513 43.776 17.088 43.8 ;
     RECT  16.513 43.8 17.1 43.872 ;
     RECT  16.513 43.872 17.088 43.896 ;
     RECT  16.513 43.896 17.1 43.968 ;
     RECT  16.513 43.968 17.088 43.992 ;
     RECT  16.513 43.992 17.1 44.112 ;
     RECT  16.513 44.112 17.088 44.136 ;
     RECT  16.513 44.136 17.1 44.208 ;
     RECT  16.513 44.208 17.088 44.232 ;
     RECT  16.513 44.232 17.1 44.304 ;
     RECT  16.513 44.304 17.088 44.328 ;
     RECT  16.513 44.328 17.1 44.4 ;
     RECT  16.513 44.4 17.088 44.424 ;
     RECT  16.513 44.424 17.1 44.496 ;
     RECT  16.513 44.496 17.088 44.52 ;
     RECT  16.513 44.52 17.1 44.64 ;
     RECT  16.513 44.64 17.088 44.664 ;
     RECT  16.513 44.664 17.1 44.736 ;
     RECT  16.513 44.736 17.088 44.76 ;
     RECT  16.513 44.76 17.1 44.832 ;
     RECT  16.513 44.832 17.088 44.856 ;
     RECT  16.513 44.856 17.1 44.928 ;
     RECT  16.513 44.928 17.088 44.952 ;
     RECT  16.513 44.952 17.1 45.024 ;
     RECT  16.513 45.024 17.088 45.048 ;
     RECT  16.513 45.048 17.1 45.168 ;
     RECT  16.513 45.168 17.088 45.192 ;
     RECT  16.513 45.192 17.1 45.264 ;
     RECT  16.513 45.264 17.088 45.288 ;
     RECT  16.513 45.288 17.1 45.36 ;
     RECT  16.513 45.36 17.088 45.384 ;
     RECT  16.513 45.384 17.1 45.456 ;
     RECT  16.513 45.456 17.088 45.48 ;
     RECT  16.513 45.48 17.1 45.552 ;
     RECT  16.513 45.552 17.088 45.576 ;
     RECT  16.513 45.576 17.1 45.696 ;
     RECT  16.513 45.696 17.088 45.72 ;
     RECT  16.513 45.72 17.1 45.792 ;
     RECT  16.513 45.792 17.088 45.816 ;
     RECT  16.513 45.816 17.1 45.888 ;
     RECT  16.513 45.888 17.088 45.912 ;
     RECT  16.513 45.912 17.1 45.984 ;
     RECT  16.513 45.984 17.088 46.008 ;
     RECT  16.513 46.008 17.1 46.08 ;
     RECT  16.513 46.08 17.088 46.104 ;
     RECT  16.513 46.104 17.1 46.224 ;
     RECT  16.513 46.224 17.088 46.248 ;
     RECT  16.513 46.248 17.1 46.32 ;
     RECT  16.513 46.32 17.088 46.344 ;
     RECT  16.513 46.344 17.1 46.416 ;
     RECT  16.513 46.416 17.088 46.44 ;
     RECT  16.513 46.44 17.1 46.512 ;
     RECT  16.513 46.512 17.088 46.536 ;
     RECT  16.513 46.536 17.1 46.608 ;
     RECT  16.513 46.608 17.088 46.632 ;
     RECT  16.513 46.632 17.1 46.752 ;
     RECT  16.513 46.752 17.088 46.776 ;
     RECT  16.513 46.776 17.1 46.848 ;
     RECT  16.513 46.848 17.088 46.872 ;
     RECT  16.513 46.872 17.1 46.944 ;
     RECT  16.513 46.944 17.088 46.968 ;
     RECT  16.513 46.968 17.1 47.04 ;
     RECT  16.513 47.04 17.088 47.064 ;
     RECT  16.513 47.064 17.1 47.136 ;
     RECT  16.513 47.136 17.088 47.16 ;
     RECT  16.513 47.16 17.1 47.28 ;
     RECT  16.513 47.28 17.088 47.304 ;
     RECT  16.513 47.304 17.1 47.376 ;
     RECT  16.513 47.376 17.088 47.4 ;
     RECT  16.513 47.4 17.1 47.472 ;
     RECT  16.513 47.472 17.088 47.496 ;
     RECT  16.513 47.496 17.1 47.568 ;
     RECT  16.513 47.568 17.088 47.592 ;
     RECT  16.513 47.592 17.1 47.664 ;
     RECT  16.513 47.664 17.088 47.688 ;
     RECT  16.513 47.688 17.1 47.808 ;
     RECT  16.513 47.808 17.088 47.832 ;
     RECT  16.513 47.832 17.1 47.904 ;
     RECT  16.513 47.904 17.088 47.928 ;
     RECT  16.513 47.928 17.1 48 ;
     RECT  16.513 48 17.088 48.024 ;
     RECT  16.513 48.024 17.1 48.096 ;
     RECT  16.513 48.096 17.088 48.12 ;
     RECT  16.513 48.12 17.1 48.192 ;
     RECT  16.513 48.192 17.088 48.216 ;
     RECT  16.513 48.216 17.1 48.336 ;
     RECT  16.513 48.336 17.088 48.36 ;
     RECT  16.513 48.36 17.1 48.432 ;
     RECT  16.513 48.432 17.088 48.456 ;
     RECT  16.513 48.456 17.1 48.528 ;
     RECT  16.513 48.528 17.088 48.552 ;
     RECT  16.513 48.552 17.1 48.624 ;
     RECT  16.513 48.624 17.088 48.648 ;
     RECT  16.513 48.648 17.1 48.72 ;
     RECT  16.513 48.72 17.088 48.744 ;
     RECT  16.513 48.744 17.1 48.864 ;
     RECT  16.513 48.864 17.088 48.888 ;
     RECT  16.513 48.888 17.1 48.96 ;
     RECT  16.513 48.96 17.088 48.984 ;
     RECT  16.513 48.984 17.1 49.056 ;
     RECT  16.513 49.056 17.088 49.08 ;
     RECT  16.513 49.08 17.1 49.152 ;
     RECT  16.513 49.152 17.088 49.176 ;
     RECT  16.513 49.176 17.1 49.248 ;
     RECT  16.513 49.248 17.088 49.272 ;
     RECT  16.513 49.272 17.1 49.392 ;
     RECT  16.513 49.392 17.088 49.416 ;
     RECT  16.513 49.416 17.1 49.488 ;
     RECT  16.513 49.488 17.088 49.512 ;
     RECT  16.513 49.512 17.1 49.584 ;
     RECT  16.513 49.584 17.088 49.608 ;
     RECT  16.513 49.608 17.1 49.68 ;
     RECT  16.513 49.68 17.088 49.704 ;
     RECT  16.513 49.704 17.1 49.776 ;
     RECT  16.513 49.776 17.088 49.8 ;
     RECT  16.513 49.8 17.1 49.92 ;
     RECT  16.513 49.92 17.088 49.944 ;
     RECT  16.513 49.944 17.1 50.016 ;
     RECT  16.513 50.016 17.088 50.04 ;
     RECT  16.513 50.04 17.1 50.112 ;
     RECT  16.513 50.112 17.088 50.136 ;
     RECT  16.513 50.136 17.1 50.208 ;
     RECT  16.513 50.208 17.088 50.232 ;
     RECT  16.513 50.232 17.1 50.304 ;
     RECT  16.513 50.304 17.088 50.328 ;
     RECT  16.513 50.328 17.1 50.4 ;
     RECT  16.513 50.4 17.088 50.424 ;
     RECT  16.513 50.424 17.1 50.544 ;
     RECT  16.513 50.544 17.088 50.568 ;
     RECT  16.513 50.568 17.1 50.64 ;
     RECT  16.513 50.64 17.088 50.664 ;
     RECT  16.513 50.664 17.1 50.736 ;
     RECT  16.513 50.736 17.088 50.76 ;
     RECT  16.513 50.76 17.1 50.832 ;
     RECT  16.513 50.832 17.088 50.856 ;
     RECT  16.513 50.856 17.1 50.928 ;
     RECT  16.513 50.928 17.088 50.952 ;
     RECT  16.513 50.952 17.1 51.072 ;
     RECT  16.513 51.072 17.088 51.096 ;
     RECT  16.513 51.096 17.1 51.168 ;
     RECT  16.513 51.168 17.088 51.192 ;
     RECT  16.513 51.192 17.1 51.264 ;
     RECT  16.513 51.264 17.088 51.288 ;
     RECT  16.513 51.288 17.1 51.36 ;
     RECT  16.513 51.36 17.088 51.384 ;
     RECT  16.513 51.384 17.1 51.456 ;
     RECT  16.513 51.456 17.088 51.48 ;
     RECT  16.513 51.48 17.1 51.6 ;
     RECT  16.513 51.6 17.088 51.624 ;
     RECT  16.513 51.624 17.1 51.696 ;
     RECT  16.513 51.696 17.088 51.72 ;
     RECT  16.513 51.72 17.1 51.792 ;
     RECT  16.513 51.792 17.088 51.816 ;
     RECT  16.513 51.816 17.1 51.888 ;
     RECT  16.513 51.888 17.088 51.912 ;
     RECT  16.513 51.912 17.1 51.984 ;
     RECT  16.513 51.984 17.088 52.008 ;
     RECT  16.513 52.008 17.1 52.128 ;
     RECT  16.513 52.128 17.088 52.152 ;
     RECT  16.513 52.152 17.1 52.224 ;
     RECT  16.513 52.224 17.088 52.248 ;
     RECT  16.513 52.248 17.1 52.32 ;
     RECT  16.513 52.32 17.088 52.344 ;
     RECT  16.513 52.344 17.1 52.416 ;
     RECT  16.513 52.416 17.088 52.44 ;
     RECT  16.513 52.44 17.1 52.512 ;
     RECT  16.513 52.512 17.088 52.536 ;
     RECT  16.513 52.536 17.1 52.656 ;
     RECT  16.513 52.656 17.088 52.68 ;
     RECT  16.513 52.68 17.1 52.752 ;
     RECT  16.513 52.752 17.088 52.776 ;
     RECT  16.513 52.776 17.1 52.848 ;
     RECT  16.513 52.848 17.088 52.872 ;
     RECT  16.513 52.872 17.1 52.944 ;
     RECT  16.513 52.944 17.088 52.968 ;
     RECT  16.513 52.968 17.1 53.04 ;
     RECT  16.513 53.04 17.088 53.064 ;
     RECT  16.513 53.064 17.1 53.184 ;
     RECT  16.513 53.184 17.088 53.208 ;
     RECT  16.513 53.208 17.1 53.28 ;
     RECT  16.513 53.28 17.088 53.304 ;
     RECT  16.513 53.304 17.1 53.376 ;
     RECT  16.513 53.376 17.088 53.4 ;
     RECT  16.513 53.4 17.1 53.472 ;
     RECT  16.513 53.472 17.088 53.496 ;
     RECT  16.513 53.496 17.1 53.568 ;
     RECT  16.513 53.568 17.088 53.592 ;
     RECT  16.513 53.592 17.1 53.712 ;
     RECT  16.513 53.712 17.088 53.736 ;
     RECT  16.513 53.736 17.1 53.808 ;
     RECT  16.513 53.808 17.088 53.832 ;
     RECT  16.513 53.832 17.1 53.904 ;
     RECT  16.513 53.904 17.088 53.928 ;
     RECT  16.513 53.928 17.1 54 ;
     RECT  16.513 54 17.088 54.024 ;
     RECT  16.513 54.024 17.1 54.096 ;
     RECT  16.513 54.096 17.088 54.12 ;
     RECT  16.513 54.12 17.1 54.24 ;
     RECT  16.513 54.24 17.088 54.264 ;
     RECT  16.513 54.264 17.1 54.336 ;
     RECT  16.513 54.336 17.088 54.36 ;
     RECT  16.513 54.36 17.1 54.432 ;
     RECT  16.513 54.432 17.088 54.456 ;
     RECT  16.513 54.456 17.1 54.528 ;
     RECT  16.513 54.528 17.088 54.552 ;
     RECT  16.513 54.552 17.1 54.624 ;
     RECT  16.513 54.624 17.088 54.648 ;
     RECT  16.513 54.648 17.1 54.768 ;
     RECT  16.513 54.768 17.088 54.792 ;
     RECT  16.513 54.792 17.1 54.864 ;
     RECT  16.513 54.864 17.088 54.888 ;
     RECT  16.513 54.888 17.1 54.96 ;
     RECT  16.513 54.96 17.088 54.984 ;
     RECT  16.513 54.984 17.1 55.056 ;
     RECT  16.513 55.056 17.088 55.08 ;
     RECT  16.513 55.08 17.1 55.152 ;
     RECT  16.513 55.152 17.088 55.176 ;
     RECT  16.513 55.176 17.1 55.296 ;
     RECT  16.513 55.296 17.088 55.32 ;
     RECT  16.513 55.32 17.1 55.392 ;
     RECT  16.513 55.392 17.088 55.416 ;
     RECT  16.513 55.416 17.1 55.488 ;
     RECT  16.513 55.488 17.088 55.512 ;
     RECT  16.513 55.512 17.1 55.584 ;
     RECT  16.513 55.584 17.088 55.608 ;
     RECT  16.513 55.608 17.1 55.68 ;
     RECT  16.513 55.68 17.088 55.704 ;
     RECT  16.513 55.704 17.1 55.824 ;
     RECT  16.513 55.824 17.088 55.848 ;
     RECT  16.513 55.848 17.1 55.92 ;
     RECT  16.513 55.92 17.088 55.944 ;
     RECT  16.513 55.944 17.1 56.016 ;
     RECT  16.513 56.016 17.088 56.04 ;
     RECT  16.513 56.04 17.1 56.112 ;
     RECT  16.513 56.112 17.088 56.136 ;
     RECT  17.1 3.36 17.165 3.408 ;
     RECT  17.1 3.432 17.165 3.504 ;
     RECT  17.1 3.528 17.165 3.6 ;
     RECT  17.1 3.624 17.165 3.696 ;
     RECT  17.1 3.72 17.165 3.792 ;
     RECT  17.1 3.816 17.165 3.936 ;
     RECT  17.1 3.96 17.165 4.032 ;
     RECT  17.1 4.056 17.165 4.128 ;
     RECT  17.1 4.152 17.165 4.2 ;
     RECT  17.1 6.288 17.165 6.336 ;
     RECT  17.1 6.36 17.165 6.432 ;
     RECT  17.1 6.456 17.165 6.528 ;
     RECT  17.1 6.552 17.165 6.6 ;
     RECT  17.1 7.872 17.165 7.896 ;
     RECT  17.1 10.32 17.165 10.368 ;
     RECT  17.1 10.392 17.165 10.464 ;
     RECT  17.1 10.488 17.165 10.56 ;
     RECT  17.1 10.584 17.165 10.656 ;
     RECT  17.1 10.68 17.165 10.752 ;
     RECT  17.1 10.776 17.165 10.896 ;
     RECT  17.1 10.92 17.165 10.992 ;
     RECT  17.1 11.016 17.165 11.088 ;
     RECT  17.1 11.112 17.165 11.184 ;
     RECT  17.1 11.208 17.165 11.28 ;
     RECT  17.1 11.304 17.165 11.424 ;
     RECT  17.1 11.448 17.165 11.52 ;
     RECT  17.1 11.544 17.165 11.616 ;
     RECT  17.1 11.64 17.165 11.712 ;
     RECT  17.1 11.736 17.165 11.808 ;
     RECT  17.1 11.832 17.165 11.904 ;
     RECT  17.1 11.928 17.165 12.048 ;
     RECT  17.1 12.072 17.165 12.144 ;
     RECT  17.1 12.168 17.165 12.24 ;
     RECT  17.1 12.264 17.165 12.336 ;
     RECT  17.1 12.36 17.165 12.432 ;
     RECT  17.1 12.456 17.165 12.504 ;
     RECT  17.1 13.872 17.165 13.92 ;
     RECT  17.1 13.944 17.165 14.016 ;
     RECT  17.1 14.04 17.165 14.16 ;
     RECT  17.1 14.184 17.165 14.256 ;
     RECT  17.1 14.28 17.165 14.352 ;
     RECT  17.1 14.376 17.165 14.448 ;
     RECT  17.1 14.472 17.165 14.544 ;
     RECT  17.1 14.568 17.165 14.688 ;
     RECT  17.1 14.712 17.165 14.76 ;
     RECT  17.1 16.848 17.165 16.896 ;
     RECT  17.1 16.92 17.165 16.992 ;
     RECT  17.1 17.016 17.165 17.088 ;
     RECT  17.1 17.112 17.165 17.184 ;
     RECT  17.1 17.208 17.165 17.328 ;
     RECT  17.1 17.352 17.165 17.424 ;
     RECT  17.1 17.448 17.165 17.52 ;
     RECT  17.1 17.544 17.165 17.616 ;
     RECT  17.1 17.64 17.165 17.712 ;
     RECT  17.1 17.736 17.165 17.856 ;
     RECT  17.1 17.88 17.165 17.928 ;
     RECT  17.1 20.64 17.165 20.688 ;
     RECT  17.1 20.712 17.165 20.784 ;
     RECT  17.1 20.808 17.165 20.856 ;
     RECT  17.1 25.296 17.165 25.344 ;
     RECT  17.1 25.368 17.165 25.44 ;
     RECT  17.1 25.464 17.165 25.536 ;
     RECT  17.1 25.56 17.165 25.632 ;
     RECT  17.1 25.656 17.165 25.728 ;
     RECT  17.1 25.752 17.165 25.872 ;
     RECT  17.1 25.896 17.165 25.968 ;
     RECT  17.1 25.992 17.165 26.064 ;
     RECT  17.1 26.088 17.165 26.16 ;
     RECT  17.1 26.184 17.165 26.256 ;
     RECT  17.1 26.28 17.165 26.4 ;
     RECT  17.1 26.424 17.165 26.496 ;
     RECT  17.1 26.52 17.165 26.568 ;
     RECT  17.1 27.6 17.165 27.648 ;
     RECT  17.1 27.672 17.165 27.744 ;
     RECT  17.1 27.768 17.165 27.84 ;
     RECT  17.1 27.864 17.165 27.912 ;
     RECT  17.1 35.472 17.165 35.496 ;
     RECT  17.1 44.352 17.165 44.4 ;
     RECT  17.1 44.424 17.165 44.496 ;
     RECT  17.1 44.52 17.165 44.64 ;
     RECT  17.1 44.664 17.165 44.736 ;
     RECT  17.1 44.76 17.165 44.832 ;
     RECT  17.1 44.856 17.165 44.928 ;
     RECT  17.1 44.952 17.165 45.024 ;
     RECT  17.1 45.048 17.165 45.168 ;
     RECT  17.1 45.192 17.165 45.264 ;
     RECT  17.1 45.288 17.165 45.36 ;
     RECT  17.1 45.384 17.165 45.456 ;
     RECT  17.1 45.48 17.165 45.528 ;
     RECT  17.1 46.8 17.165 46.848 ;
     RECT  17.1 46.872 17.165 46.944 ;
     RECT  17.1 46.968 17.165 47.04 ;
     RECT  17.1 47.064 17.165 47.136 ;
     RECT  17.1 47.16 17.165 47.28 ;
     RECT  17.1 47.304 17.165 47.376 ;
     RECT  17.1 47.4 17.165 47.472 ;
     RECT  17.1 47.496 17.165 47.568 ;
     RECT  17.1 47.592 17.165 47.664 ;
     RECT  17.1 47.688 17.165 47.808 ;
     RECT  17.1 47.832 17.165 47.904 ;
     RECT  17.1 47.928 17.165 48 ;
     RECT  17.1 48.024 17.165 48.096 ;
     RECT  17.1 48.12 17.165 48.168 ;
     RECT  17.1 49.2 17.165 49.248 ;
     RECT  17.1 49.272 17.165 49.392 ;
     RECT  17.1 49.416 17.165 49.488 ;
     RECT  17.1 49.512 17.165 49.584 ;
     RECT  17.1 49.608 17.165 49.68 ;
     RECT  17.1 49.704 17.165 49.776 ;
     RECT  17.1 49.8 17.165 49.92 ;
     RECT  17.1 49.944 17.165 50.016 ;
     RECT  17.1 50.04 17.165 50.112 ;
     RECT  17.1 50.136 17.165 50.208 ;
     RECT  17.1 50.232 17.165 50.304 ;
     RECT  17.1 50.328 17.165 50.4 ;
     RECT  17.1 50.424 17.165 50.544 ;
     RECT  17.1 50.568 17.165 50.64 ;
     RECT  17.1 50.664 17.165 50.736 ;
     RECT  17.1 50.76 17.165 50.832 ;
     RECT  17.1 50.856 17.165 50.928 ;
     RECT  17.1 50.952 17.165 51.072 ;
     RECT  17.1 51.096 17.165 51.168 ;
     RECT  17.1 51.192 17.165 51.264 ;
     RECT  17.1 51.288 17.165 51.36 ;
     RECT  17.1 51.384 17.165 51.456 ;
     RECT  17.1 51.48 17.165 51.6 ;
     RECT  17.1 51.624 17.165 51.696 ;
     RECT  17.1 51.72 17.165 51.792 ;
     RECT  17.1 51.816 17.165 51.888 ;
     RECT  17.1 51.912 17.165 51.984 ;
     RECT  17.1 52.008 17.165 52.128 ;
     RECT  17.1 52.152 17.165 52.224 ;
     RECT  17.1 52.248 17.165 52.32 ;
     RECT  17.1 52.344 17.165 52.416 ;
     RECT  17.1 52.44 17.165 52.488 ;
     RECT  17.1 54.192 17.165 54.24 ;
     RECT  17.1 54.264 17.165 54.336 ;
     RECT  17.1 54.36 17.165 54.408 ;
    LAYER M5 ;
     RECT  2.4 2.137 2.52 2.151 ;
     RECT  5.1 2.137 5.22 2.151 ;
     RECT  7.8 2.137 7.92 2.151 ;
     RECT  10.5 2.137 10.62 2.151 ;
     RECT  13.2 2.137 13.32 2.151 ;
     RECT  7.8 2.151 8.112 2.773 ;
     RECT  7.2 2.773 8.112 3.397 ;
     RECT  7.2 3.397 9.048 4.163 ;
     RECT  10.5 2.151 10.812 4.261 ;
     RECT  9.264 4.741 9.288 4.883 ;
     RECT  7.2 4.163 8.112 4.933 ;
     RECT  6.48 4.933 8.112 4.979 ;
     RECT  10.5 4.261 11.064 5.747 ;
     RECT  14.832 5.701 14.856 5.939 ;
     RECT  7.8 4.979 8.112 6.181 ;
     RECT  9.312 6.469 9.336 6.611 ;
     RECT  7.8 6.181 8.28 7.189 ;
     RECT  10.5 5.747 10.812 7.381 ;
     RECT  7.8 7.189 9.048 8.485 ;
     RECT  6.48 4.979 6.504 8.771 ;
     RECT  7.68 8.485 9.048 9.253 ;
     RECT  7.68 9.253 9.144 9.779 ;
     RECT  10.5 7.381 10.92 10.115 ;
     RECT  6.432 10.213 6.456 10.981 ;
     RECT  7.8 9.779 9.144 10.981 ;
     RECT  6.432 10.981 9.144 11.171 ;
     RECT  7.8 11.171 9.144 11.221 ;
     RECT  10.5 10.115 10.812 11.221 ;
     RECT  7.8 11.221 10.812 12.325 ;
     RECT  7.8 12.325 10.968 12.563 ;
     RECT  7.8 12.563 9.144 12.947 ;
     RECT  6.432 11.171 6.456 13.091 ;
     RECT  10.5 12.563 10.968 13.331 ;
     RECT  7.8 12.947 8.232 13.621 ;
     RECT  2.4 2.151 2.712 14.485 ;
     RECT  2.304 14.485 2.712 14.675 ;
     RECT  10.5 13.331 10.812 14.725 ;
     RECT  13.2 2.151 13.512 15.493 ;
     RECT  13.2 15.493 13.944 15.589 ;
     RECT  13.2 15.589 14.856 15.827 ;
     RECT  14.832 15.827 14.856 15.875 ;
     RECT  10.5 14.725 11.016 16.213 ;
     RECT  10.5 16.213 11.496 16.355 ;
     RECT  10.5 16.355 11.016 16.405 ;
     RECT  7.248 13.621 8.232 16.547 ;
     RECT  10.032 16.405 11.016 16.643 ;
     RECT  7.8 16.547 8.232 16.837 ;
     RECT  7.8 16.837 8.952 17.219 ;
     RECT  13.2 15.827 13.512 18.709 ;
     RECT  12.528 18.709 13.512 19.379 ;
     RECT  7.8 17.219 8.232 20.003 ;
     RECT  10.128 16.643 11.016 20.051 ;
     RECT  7.8 20.003 8.112 22.405 ;
     RECT  10.32 20.051 11.016 22.595 ;
     RECT  9.216 22.549 9.24 22.933 ;
     RECT  9.12 22.933 9.24 23.123 ;
     RECT  2.4 14.675 2.712 23.173 ;
     RECT  2.304 23.173 2.712 23.363 ;
     RECT  7.68 22.405 8.112 24.083 ;
     RECT  10.32 22.595 10.812 24.613 ;
     RECT  7.8 24.083 8.112 24.709 ;
     RECT  9.216 23.123 9.24 24.709 ;
     RECT  10.32 24.613 11.496 24.755 ;
     RECT  0.192 24.901 0.216 25.091 ;
     RECT  7.8 24.709 9.24 25.427 ;
     RECT  13.2 19.379 13.512 25.813 ;
     RECT  13.2 25.813 13.944 26.099 ;
     RECT  2.4 23.363 2.712 27.925 ;
     RECT  9.216 25.427 9.24 28.019 ;
     RECT  2.256 27.925 2.712 28.067 ;
     RECT  5.1 2.151 5.412 30.085 ;
     RECT  9.12 30.517 9.144 30.755 ;
     RECT  10.32 24.755 10.812 32.005 ;
     RECT  9.12 31.861 9.24 32.051 ;
     RECT  9.216 32.051 9.24 32.483 ;
     RECT  10.32 32.005 11.016 32.531 ;
     RECT  2.4 28.067 2.712 32.581 ;
     RECT  2.304 32.581 2.712 32.819 ;
     RECT  13.2 26.099 13.512 33.253 ;
     RECT  13.104 33.253 13.512 33.443 ;
     RECT  7.8 25.427 8.112 33.589 ;
     RECT  10.32 32.531 10.812 34.213 ;
     RECT  10.176 34.213 10.812 34.355 ;
     RECT  13.2 33.443 13.512 34.405 ;
     RECT  9.12 34.213 9.144 34.547 ;
     RECT  13.104 34.405 13.512 35.075 ;
     RECT  10.32 34.355 10.812 36.325 ;
     RECT  6.96 33.589 8.112 36.515 ;
     RECT  10.08 36.325 10.812 36.515 ;
     RECT  7.68 36.515 8.112 36.565 ;
     RECT  10.32 36.515 10.812 36.565 ;
     RECT  7.68 36.565 8.52 37.333 ;
     RECT  7.68 37.333 9.144 37.619 ;
     RECT  7.8 37.619 9.144 37.859 ;
     RECT  13.2 35.075 13.512 37.957 ;
     RECT  13.104 37.957 13.512 38.243 ;
     RECT  2.4 32.819 2.712 38.245 ;
     RECT  7.8 37.859 8.52 38.339 ;
     RECT  2.304 38.245 2.712 38.387 ;
     RECT  7.8 38.339 8.112 38.677 ;
     RECT  10.32 36.565 11.448 39.299 ;
     RECT  6.864 38.677 8.112 39.395 ;
     RECT  10.5 39.299 11.448 39.541 ;
     RECT  10.5 39.541 11.496 39.877 ;
     RECT  10.5 39.877 11.544 40.069 ;
     RECT  13.2 38.243 13.512 40.069 ;
     RECT  10.5 40.069 11.64 40.357 ;
     RECT  10.368 40.357 11.64 40.403 ;
     RECT  7.392 39.395 8.112 40.741 ;
     RECT  7.392 40.741 9 40.931 ;
     RECT  10.368 40.403 11.208 40.979 ;
     RECT  13.104 40.069 13.512 41.221 ;
     RECT  7.392 40.931 8.112 41.363 ;
     RECT  12.576 41.221 13.512 41.459 ;
     RECT  7.8 41.363 8.112 42.469 ;
     RECT  10.368 40.979 10.812 42.565 ;
     RECT  7.8 42.469 8.904 42.611 ;
     RECT  7.8 42.611 8.112 42.613 ;
     RECT  2.4 38.387 2.712 42.997 ;
     RECT  13.2 41.459 13.512 42.997 ;
     RECT  2.304 42.997 2.712 43.139 ;
     RECT  13.2 42.997 13.944 43.139 ;
     RECT  7.44 42.613 8.112 43.141 ;
     RECT  6.72 43.141 8.112 43.187 ;
     RECT  9.12 42.853 9.192 43.523 ;
     RECT  10.368 42.565 11.016 43.861 ;
     RECT  9.168 43.523 9.192 44.293 ;
     RECT  10.32 43.861 11.016 44.483 ;
     RECT  9.168 44.293 9.24 44.533 ;
     RECT  9.12 44.533 9.24 44.627 ;
     RECT  14.832 43.669 14.856 44.867 ;
     RECT  9.12 44.627 9.144 44.915 ;
     RECT  10.32 44.483 10.812 45.589 ;
     RECT  10.32 45.589 11.496 45.683 ;
     RECT  10.368 45.683 11.496 45.779 ;
     RECT  7.8 43.187 8.112 45.877 ;
     RECT  9.168 45.685 9.192 45.877 ;
     RECT  7.8 45.877 9.192 45.923 ;
     RECT  7.8 45.923 8.856 46.211 ;
     RECT  13.2 43.139 13.512 47.029 ;
     RECT  12.912 47.029 13.512 47.171 ;
     RECT  14.832 46.261 14.856 47.315 ;
     RECT  7.8 46.211 8.112 47.749 ;
     RECT  7.8 47.749 8.568 48.469 ;
     RECT  7.8 48.469 8.664 48.757 ;
     RECT  14.832 48.709 14.856 48.899 ;
     RECT  7.8 48.757 9 49.043 ;
     RECT  7.8 49.043 8.568 49.235 ;
     RECT  6.72 43.187 6.744 50.101 ;
     RECT  6.624 50.101 6.744 50.147 ;
     RECT  13.2 47.171 13.512 50.389 ;
     RECT  12.576 50.389 13.512 51.299 ;
     RECT  9.12 51.541 9.144 51.683 ;
     RECT  12.624 51.299 13.512 52.021 ;
     RECT  12.624 52.021 13.944 52.211 ;
     RECT  13.2 52.211 13.944 52.307 ;
     RECT  10.368 45.779 10.812 52.309 ;
     RECT  10.368 52.309 10.92 52.499 ;
     RECT  14.832 52.741 14.856 52.979 ;
     RECT  10.5 52.499 10.92 53.075 ;
     RECT  13.2 52.307 13.512 54.421 ;
     RECT  12.48 54.421 13.512 54.659 ;
     RECT  5.1 30.085 5.592 54.709 ;
     RECT  6.624 50.147 6.648 54.709 ;
     RECT  5.1 54.709 6.648 54.755 ;
     RECT  9.12 54.373 9.144 54.803 ;
     RECT  5.1 54.755 5.688 56.003 ;
     RECT  2.4 43.139 2.712 56.169 ;
     RECT  7.8 49.235 8.112 56.169 ;
     RECT  10.5 53.075 10.812 56.169 ;
     RECT  13.2 54.659 13.512 56.169 ;
     RECT  2.4 56.169 2.52 56.183 ;
     RECT  5.1 56.003 5.592 56.183 ;
     RECT  7.8 56.169 7.92 56.183 ;
     RECT  10.5 56.169 10.62 56.183 ;
     RECT  13.2 56.169 13.32 56.183 ;
     RECT  5.568 56.183 5.592 57.635 ;
     RECT  9.048 3.397 10.5 4.163 ;
     RECT  8.112 4.163 10.5 4.741 ;
     RECT  8.112 4.741 9.264 4.883 ;
     RECT  9.288 4.741 10.5 4.883 ;
     RECT  8.112 4.883 8.28 6.181 ;
     RECT  5.412 4.933 6.48 8.771 ;
     RECT  6.504 4.979 7.8 8.485 ;
     RECT  13.512 5.701 14.832 5.939 ;
     RECT  8.28 6.469 9.312 6.611 ;
     RECT  9.336 6.469 10.5 6.611 ;
     RECT  8.28 6.611 10.5 7.189 ;
     RECT  9.048 7.189 10.5 9.253 ;
     RECT  6.504 8.485 7.68 8.771 ;
     RECT  5.412 8.771 7.68 9.779 ;
     RECT  9.144 9.253 10.5 11.221 ;
     RECT  5.412 9.779 7.8 10.213 ;
     RECT  5.412 10.213 6.432 13.091 ;
     RECT  6.456 10.213 7.8 10.981 ;
     RECT  6.456 11.171 7.8 13.091 ;
     RECT  9.144 12.563 10.5 12.947 ;
     RECT  7.248 13.091 7.8 13.621 ;
     RECT  10.812 13.331 10.968 14.725 ;
     RECT  13.512 15.827 14.832 15.875 ;
     RECT  10.032 16.643 10.128 16.837 ;
     RECT  8.952 16.837 10.128 17.219 ;
     RECT  11.016 18.709 12.528 19.379 ;
     RECT  8.112 22.549 9.216 22.933 ;
     RECT  9.24 22.549 10.32 28.019 ;
     RECT  8.112 22.933 9.12 23.123 ;
     RECT  8.112 23.123 9.216 24.709 ;
     RECT  8.112 25.427 9.216 28.019 ;
     RECT  8.112 30.517 9.12 30.755 ;
     RECT  9.144 30.517 10.32 30.755 ;
     RECT  8.112 30.755 10.32 31.861 ;
     RECT  8.112 31.861 9.12 32.051 ;
     RECT  9.24 31.861 10.32 32.483 ;
     RECT  8.112 32.051 9.216 32.483 ;
     RECT  13.104 33.443 13.2 34.405 ;
     RECT  5.592 33.589 6.96 36.515 ;
     RECT  8.112 34.213 9.12 34.547 ;
     RECT  9.144 34.213 10.176 34.355 ;
     RECT  9.144 34.355 10.32 34.547 ;
     RECT  10.08 36.515 10.32 37.333 ;
     RECT  9.144 37.333 10.32 37.859 ;
     RECT  7.68 37.619 7.8 38.677 ;
     RECT  5.592 38.677 6.864 39.395 ;
     RECT  10.32 39.299 10.5 40.357 ;
     RECT  11.64 40.069 13.104 40.403 ;
     RECT  10.32 40.357 10.368 40.741 ;
     RECT  11.208 40.403 13.104 40.979 ;
     RECT  9 40.741 10.368 40.931 ;
     RECT  12.576 40.979 13.104 41.221 ;
     RECT  7.44 41.363 7.8 42.613 ;
     RECT  8.904 42.469 10.368 42.611 ;
     RECT  8.112 42.611 10.368 42.853 ;
     RECT  8.112 42.853 9.12 43.523 ;
     RECT  9.192 42.853 10.368 43.861 ;
     RECT  13.512 43.139 13.944 43.669 ;
     RECT  5.592 43.141 6.72 50.101 ;
     RECT  6.744 43.187 7.8 50.147 ;
     RECT  8.112 43.523 9.168 44.533 ;
     RECT  13.512 43.669 14.832 44.867 ;
     RECT  9.192 43.861 10.32 44.293 ;
     RECT  9.24 44.293 10.32 44.627 ;
     RECT  10.812 44.483 11.016 45.589 ;
     RECT  8.112 44.533 9.12 44.915 ;
     RECT  9.144 44.627 10.32 44.915 ;
     RECT  13.512 44.867 14.856 46.261 ;
     RECT  8.112 44.915 10.32 45.683 ;
     RECT  8.112 45.683 10.368 45.685 ;
     RECT  8.112 45.685 9.168 45.877 ;
     RECT  9.192 45.685 10.368 45.923 ;
     RECT  8.856 45.923 10.368 46.211 ;
     RECT  13.512 46.261 14.832 47.315 ;
     RECT  13.512 47.315 14.856 48.709 ;
     RECT  13.512 48.709 14.832 48.899 ;
     RECT  9 48.757 10.368 49.043 ;
     RECT  5.592 50.101 6.624 54.709 ;
     RECT  6.648 50.147 7.8 54.755 ;
     RECT  8.112 51.541 9.12 51.683 ;
     RECT  9.144 51.541 10.368 51.683 ;
     RECT  13.512 52.307 13.944 52.741 ;
     RECT  13.512 52.741 14.832 52.979 ;
     RECT  8.112 54.373 9.12 54.803 ;
     RECT  9.144 54.373 10.5 54.803 ;
  END
END dsfd_dvrlyh_512_EW
END LIBRARY
